VERSION 5.8 ;
BUSBITCHARS "[]" ;
DIVIDERCHAR "/" ;
UNITS
    DATABASE MICRONS 1000 ;
END UNITS

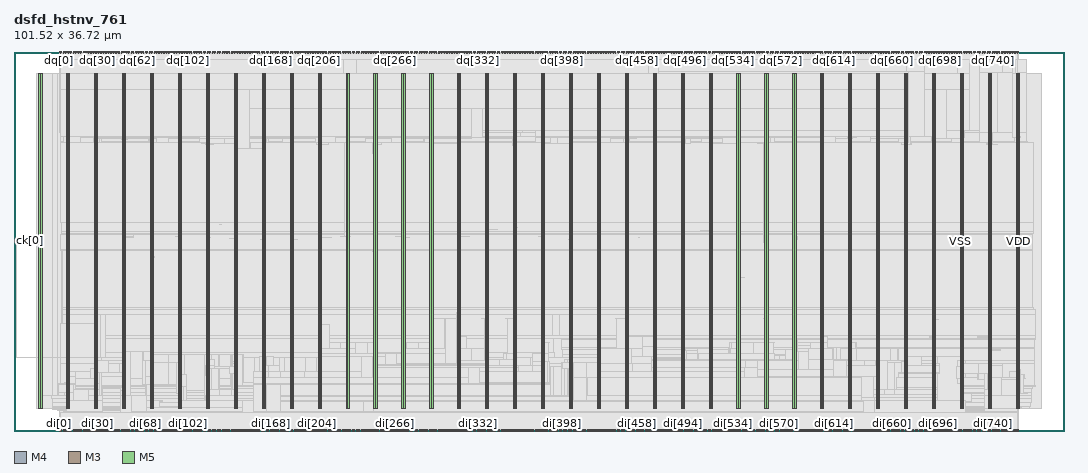
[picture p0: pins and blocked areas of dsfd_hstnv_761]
MACRO dsfd_hstnv_761
  FOREIGN dsfd_hstnv_761 0 0 ;
  CLASS BLOCK ;
  SIZE 101.52 BY 36.72 ;
  PIN ck[0]
    DIRECTION INPUT ;
    USE SIGNAL ;
    PORT
      LAYER M4 ;
        RECT  0 18.384 0.192 18.408 ;
    END
    PORT
      LAYER M4 ;
        RECT  0.156 18.384 0.275 18.408 ;
    END
  END ck[0]
  PIN di[0]
    DIRECTION INPUT ;
    USE SIGNAL ;
    PORT
      LAYER M3 ;
        RECT  4.356 0 4.374 0.144 ;
    END
  END di[0]
  PIN di[100]
    DIRECTION INPUT ;
    USE SIGNAL ;
    PORT
      LAYER M3 ;
        RECT  16.56 0 16.578 0.144 ;
    END
  END di[100]
  PIN di[101]
    DIRECTION INPUT ;
    USE SIGNAL ;
    PORT
      LAYER M5 ;
        RECT  16.704 0 16.728 0.192 ;
    END
  END di[101]
  PIN di[102]
    DIRECTION INPUT ;
    USE SIGNAL ;
    PORT
      LAYER M3 ;
        RECT  16.812 0 16.83 0.144 ;
    END
  END di[102]
  PIN di[103]
    DIRECTION INPUT ;
    USE SIGNAL ;
    PORT
      LAYER M5 ;
        RECT  16.944 0 16.968 0.192 ;
    END
  END di[103]
  PIN di[104]
    DIRECTION INPUT ;
    USE SIGNAL ;
    PORT
      LAYER M3 ;
        RECT  17.064 0 17.082 0.144 ;
    END
  END di[104]
  PIN di[105]
    DIRECTION INPUT ;
    USE SIGNAL ;
    PORT
      LAYER M5 ;
        RECT  17.184 0 17.208 0.192 ;
    END
  END di[105]
  PIN di[106]
    DIRECTION INPUT ;
    USE SIGNAL ;
    PORT
      LAYER M3 ;
        RECT  17.316 0 17.334 0.144 ;
    END
  END di[106]
  PIN di[107]
    DIRECTION INPUT ;
    USE SIGNAL ;
    PORT
      LAYER M5 ;
        RECT  17.424 0 17.448 0.192 ;
    END
  END di[107]
  PIN di[108]
    DIRECTION INPUT ;
    USE SIGNAL ;
    PORT
      LAYER M3 ;
        RECT  17.568 0 17.586 0.144 ;
    END
  END di[108]
  PIN di[109]
    DIRECTION INPUT ;
    USE SIGNAL ;
    PORT
      LAYER M5 ;
        RECT  17.664 0 17.688 0.192 ;
    END
  END di[109]
  PIN di[10]
    DIRECTION INPUT ;
    USE SIGNAL ;
    PORT
      LAYER M3 ;
        RECT  5.58 0 5.598 0.144 ;
    END
  END di[10]
  PIN di[110]
    DIRECTION INPUT ;
    USE SIGNAL ;
    PORT
      LAYER M3 ;
        RECT  17.784 0 17.802 0.144 ;
    END
  END di[110]
  PIN di[111]
    DIRECTION INPUT ;
    USE SIGNAL ;
    PORT
      LAYER M5 ;
        RECT  17.904 0 17.928 0.192 ;
    END
  END di[111]
  PIN di[112]
    DIRECTION INPUT ;
    USE SIGNAL ;
    PORT
      LAYER M3 ;
        RECT  18.036 0 18.054 0.144 ;
    END
  END di[112]
  PIN di[113]
    DIRECTION INPUT ;
    USE SIGNAL ;
    PORT
      LAYER M5 ;
        RECT  18.144 0 18.168 0.192 ;
    END
  END di[113]
  PIN di[114]
    DIRECTION INPUT ;
    USE SIGNAL ;
    PORT
      LAYER M3 ;
        RECT  18.288 0 18.306 0.144 ;
    END
  END di[114]
  PIN di[115]
    DIRECTION INPUT ;
    USE SIGNAL ;
    PORT
      LAYER M5 ;
        RECT  18.384 0 18.408 0.192 ;
    END
  END di[115]
  PIN di[116]
    DIRECTION INPUT ;
    USE SIGNAL ;
    PORT
      LAYER M3 ;
        RECT  18.54 0 18.558 0.144 ;
    END
  END di[116]
  PIN di[117]
    DIRECTION INPUT ;
    USE SIGNAL ;
    PORT
      LAYER M5 ;
        RECT  18.672 0 18.696 0.192 ;
    END
  END di[117]
  PIN di[118]
    DIRECTION INPUT ;
    USE SIGNAL ;
    PORT
      LAYER M3 ;
        RECT  18.756 0 18.774 0.144 ;
    END
  END di[118]
  PIN di[119]
    DIRECTION INPUT ;
    USE SIGNAL ;
    PORT
      LAYER M5 ;
        RECT  18.912 0 18.936 0.192 ;
    END
  END di[119]
  PIN di[11]
    DIRECTION INPUT ;
    USE SIGNAL ;
    PORT
      LAYER M5 ;
        RECT  5.712 0 5.736 0.192 ;
    END
  END di[11]
  PIN di[120]
    DIRECTION INPUT ;
    USE SIGNAL ;
    PORT
      LAYER M3 ;
        RECT  19.008 0 19.026 0.144 ;
    END
  END di[120]
  PIN di[121]
    DIRECTION INPUT ;
    USE SIGNAL ;
    PORT
      LAYER M5 ;
        RECT  19.152 0 19.176 0.192 ;
    END
  END di[121]
  PIN di[122]
    DIRECTION INPUT ;
    USE SIGNAL ;
    PORT
      LAYER M3 ;
        RECT  19.26 0 19.278 0.144 ;
    END
  END di[122]
  PIN di[123]
    DIRECTION INPUT ;
    USE SIGNAL ;
    PORT
      LAYER M5 ;
        RECT  19.392 0 19.416 0.192 ;
    END
  END di[123]
  PIN di[124]
    DIRECTION INPUT ;
    USE SIGNAL ;
    PORT
      LAYER M3 ;
        RECT  19.512 0 19.53 0.144 ;
    END
  END di[124]
  PIN di[125]
    DIRECTION INPUT ;
    USE SIGNAL ;
    PORT
      LAYER M5 ;
        RECT  19.632 0 19.656 0.192 ;
    END
  END di[125]
  PIN di[126]
    DIRECTION INPUT ;
    USE SIGNAL ;
    PORT
      LAYER M3 ;
        RECT  19.764 0 19.782 0.144 ;
    END
  END di[126]
  PIN di[127]
    DIRECTION INPUT ;
    USE SIGNAL ;
    PORT
      LAYER M5 ;
        RECT  19.872 0 19.896 0.192 ;
    END
  END di[127]
  PIN di[128]
    DIRECTION INPUT ;
    USE SIGNAL ;
    PORT
      LAYER M3 ;
        RECT  19.98 0 19.998 0.144 ;
    END
  END di[128]
  PIN di[129]
    DIRECTION INPUT ;
    USE SIGNAL ;
    PORT
      LAYER M5 ;
        RECT  20.112 0 20.136 0.192 ;
    END
  END di[129]
  PIN di[12]
    DIRECTION INPUT ;
    USE SIGNAL ;
    PORT
      LAYER M3 ;
        RECT  5.832 0 5.85 0.144 ;
    END
  END di[12]
  PIN di[130]
    DIRECTION INPUT ;
    USE SIGNAL ;
    PORT
      LAYER M3 ;
        RECT  20.232 0 20.25 0.144 ;
    END
  END di[130]
  PIN di[131]
    DIRECTION INPUT ;
    USE SIGNAL ;
    PORT
      LAYER M5 ;
        RECT  20.352 0 20.376 0.192 ;
    END
  END di[131]
  PIN di[132]
    DIRECTION INPUT ;
    USE SIGNAL ;
    PORT
      LAYER M3 ;
        RECT  20.484 0 20.502 0.144 ;
    END
  END di[132]
  PIN di[133]
    DIRECTION INPUT ;
    USE SIGNAL ;
    PORT
      LAYER M5 ;
        RECT  20.592 0 20.616 0.192 ;
    END
  END di[133]
  PIN di[134]
    DIRECTION INPUT ;
    USE SIGNAL ;
    PORT
      LAYER M3 ;
        RECT  20.736 0 20.754 0.144 ;
    END
  END di[134]
  PIN di[135]
    DIRECTION INPUT ;
    USE SIGNAL ;
    PORT
      LAYER M5 ;
        RECT  20.832 0 20.856 0.192 ;
    END
  END di[135]
  PIN di[136]
    DIRECTION INPUT ;
    USE SIGNAL ;
    PORT
      LAYER M3 ;
        RECT  20.988 0 21.006 0.144 ;
    END
  END di[136]
  PIN di[137]
    DIRECTION INPUT ;
    USE SIGNAL ;
    PORT
      LAYER M5 ;
        RECT  21.072 0 21.096 0.192 ;
    END
  END di[137]
  PIN di[138]
    DIRECTION INPUT ;
    USE SIGNAL ;
    PORT
      LAYER M3 ;
        RECT  21.204 0 21.222 0.144 ;
    END
  END di[138]
  PIN di[139]
    DIRECTION INPUT ;
    USE SIGNAL ;
    PORT
      LAYER M5 ;
        RECT  21.312 0 21.336 0.192 ;
    END
  END di[139]
  PIN di[13]
    DIRECTION INPUT ;
    USE SIGNAL ;
    PORT
      LAYER M5 ;
        RECT  5.952 0 5.976 0.192 ;
    END
  END di[13]
  PIN di[140]
    DIRECTION INPUT ;
    USE SIGNAL ;
    PORT
      LAYER M3 ;
        RECT  21.456 0 21.474 0.144 ;
    END
  END di[140]
  PIN di[141]
    DIRECTION INPUT ;
    USE SIGNAL ;
    PORT
      LAYER M5 ;
        RECT  21.6 0 21.624 0.192 ;
    END
  END di[141]
  PIN di[142]
    DIRECTION INPUT ;
    USE SIGNAL ;
    PORT
      LAYER M3 ;
        RECT  21.708 0 21.726 0.144 ;
    END
  END di[142]
  PIN di[143]
    DIRECTION INPUT ;
    USE SIGNAL ;
    PORT
      LAYER M5 ;
        RECT  21.84 0 21.864 0.192 ;
    END
  END di[143]
  PIN di[144]
    DIRECTION INPUT ;
    USE SIGNAL ;
    PORT
      LAYER M3 ;
        RECT  21.96 0 21.978 0.144 ;
    END
  END di[144]
  PIN di[145]
    DIRECTION INPUT ;
    USE SIGNAL ;
    PORT
      LAYER M5 ;
        RECT  22.08 0 22.104 0.192 ;
    END
  END di[145]
  PIN di[146]
    DIRECTION INPUT ;
    USE SIGNAL ;
    PORT
      LAYER M3 ;
        RECT  22.176 0 22.194 0.144 ;
    END
  END di[146]
  PIN di[147]
    DIRECTION INPUT ;
    USE SIGNAL ;
    PORT
      LAYER M5 ;
        RECT  22.32 0 22.344 0.192 ;
    END
  END di[147]
  PIN di[148]
    DIRECTION INPUT ;
    USE SIGNAL ;
    PORT
      LAYER M3 ;
        RECT  22.428 0 22.446 0.144 ;
    END
  END di[148]
  PIN di[149]
    DIRECTION INPUT ;
    USE SIGNAL ;
    PORT
      LAYER M5 ;
        RECT  22.56 0 22.584 0.192 ;
    END
  END di[149]
  PIN di[14]
    DIRECTION INPUT ;
    USE SIGNAL ;
    PORT
      LAYER M3 ;
        RECT  6.084 0 6.102 0.144 ;
    END
  END di[14]
  PIN di[150]
    DIRECTION INPUT ;
    USE SIGNAL ;
    PORT
      LAYER M3 ;
        RECT  22.68 0 22.698 0.144 ;
    END
  END di[150]
  PIN di[151]
    DIRECTION INPUT ;
    USE SIGNAL ;
    PORT
      LAYER M5 ;
        RECT  22.8 0 22.824 0.192 ;
    END
  END di[151]
  PIN di[152]
    DIRECTION INPUT ;
    USE SIGNAL ;
    PORT
      LAYER M3 ;
        RECT  22.932 0 22.95 0.144 ;
    END
  END di[152]
  PIN di[153]
    DIRECTION INPUT ;
    USE SIGNAL ;
    PORT
      LAYER M5 ;
        RECT  23.04 0 23.064 0.192 ;
    END
  END di[153]
  PIN di[154]
    DIRECTION INPUT ;
    USE SIGNAL ;
    PORT
      LAYER M3 ;
        RECT  23.184 0 23.202 0.144 ;
    END
  END di[154]
  PIN di[155]
    DIRECTION INPUT ;
    USE SIGNAL ;
    PORT
      LAYER M5 ;
        RECT  23.28 0 23.304 0.192 ;
    END
  END di[155]
  PIN di[156]
    DIRECTION INPUT ;
    USE SIGNAL ;
    PORT
      LAYER M3 ;
        RECT  23.4 0 23.418 0.144 ;
    END
  END di[156]
  PIN di[157]
    DIRECTION INPUT ;
    USE SIGNAL ;
    PORT
      LAYER M5 ;
        RECT  23.52 0 23.544 0.192 ;
    END
  END di[157]
  PIN di[158]
    DIRECTION INPUT ;
    USE SIGNAL ;
    PORT
      LAYER M3 ;
        RECT  23.652 0 23.67 0.144 ;
    END
  END di[158]
  PIN di[159]
    DIRECTION INPUT ;
    USE SIGNAL ;
    PORT
      LAYER M5 ;
        RECT  23.76 0 23.784 0.192 ;
    END
  END di[159]
  PIN di[15]
    DIRECTION INPUT ;
    USE SIGNAL ;
    PORT
      LAYER M5 ;
        RECT  6.192 0 6.216 0.192 ;
    END
  END di[15]
  PIN di[160]
    DIRECTION INPUT ;
    USE SIGNAL ;
    PORT
      LAYER M3 ;
        RECT  23.904 0 23.922 0.144 ;
    END
  END di[160]
  PIN di[161]
    DIRECTION INPUT ;
    USE SIGNAL ;
    PORT
      LAYER M5 ;
        RECT  24 0 24.024 0.192 ;
    END
  END di[161]
  PIN di[162]
    DIRECTION INPUT ;
    USE SIGNAL ;
    PORT
      LAYER M3 ;
        RECT  24.156 0 24.174 0.144 ;
    END
  END di[162]
  PIN di[163]
    DIRECTION INPUT ;
    USE SIGNAL ;
    PORT
      LAYER M5 ;
        RECT  24.24 0 24.264 0.192 ;
    END
  END di[163]
  PIN di[164]
    DIRECTION INPUT ;
    USE SIGNAL ;
    PORT
      LAYER M3 ;
        RECT  24.372 0 24.39 0.144 ;
    END
  END di[164]
  PIN di[165]
    DIRECTION INPUT ;
    USE SIGNAL ;
    PORT
      LAYER M5 ;
        RECT  24.528 0 24.552 0.192 ;
    END
  END di[165]
  PIN di[166]
    DIRECTION INPUT ;
    USE SIGNAL ;
    PORT
      LAYER M3 ;
        RECT  24.624 0 24.642 0.144 ;
    END
  END di[166]
  PIN di[167]
    DIRECTION INPUT ;
    USE SIGNAL ;
    PORT
      LAYER M5 ;
        RECT  24.768 0 24.792 0.192 ;
    END
  END di[167]
  PIN di[168]
    DIRECTION INPUT ;
    USE SIGNAL ;
    PORT
      LAYER M3 ;
        RECT  24.876 0 24.894 0.144 ;
    END
  END di[168]
  PIN di[169]
    DIRECTION INPUT ;
    USE SIGNAL ;
    PORT
      LAYER M5 ;
        RECT  25.008 0 25.032 0.192 ;
    END
  END di[169]
  PIN di[16]
    DIRECTION INPUT ;
    USE SIGNAL ;
    PORT
      LAYER M3 ;
        RECT  6.336 0 6.354 0.144 ;
    END
  END di[16]
  PIN di[170]
    DIRECTION INPUT ;
    USE SIGNAL ;
    PORT
      LAYER M3 ;
        RECT  25.128 0 25.146 0.144 ;
    END
  END di[170]
  PIN di[171]
    DIRECTION INPUT ;
    USE SIGNAL ;
    PORT
      LAYER M5 ;
        RECT  25.248 0 25.272 0.192 ;
    END
  END di[171]
  PIN di[172]
    DIRECTION INPUT ;
    USE SIGNAL ;
    PORT
      LAYER M3 ;
        RECT  25.38 0 25.398 0.144 ;
    END
  END di[172]
  PIN di[173]
    DIRECTION INPUT ;
    USE SIGNAL ;
    PORT
      LAYER M5 ;
        RECT  25.488 0 25.512 0.192 ;
    END
  END di[173]
  PIN di[174]
    DIRECTION INPUT ;
    USE SIGNAL ;
    PORT
      LAYER M3 ;
        RECT  25.596 0 25.614 0.144 ;
    END
  END di[174]
  PIN di[175]
    DIRECTION INPUT ;
    USE SIGNAL ;
    PORT
      LAYER M5 ;
        RECT  25.728 0 25.752 0.192 ;
    END
  END di[175]
  PIN di[176]
    DIRECTION INPUT ;
    USE SIGNAL ;
    PORT
      LAYER M3 ;
        RECT  25.848 0 25.866 0.144 ;
    END
  END di[176]
  PIN di[177]
    DIRECTION INPUT ;
    USE SIGNAL ;
    PORT
      LAYER M5 ;
        RECT  25.968 0 25.992 0.192 ;
    END
  END di[177]
  PIN di[178]
    DIRECTION INPUT ;
    USE SIGNAL ;
    PORT
      LAYER M3 ;
        RECT  26.1 0 26.118 0.144 ;
    END
  END di[178]
  PIN di[179]
    DIRECTION INPUT ;
    USE SIGNAL ;
    PORT
      LAYER M5 ;
        RECT  26.208 0 26.232 0.192 ;
    END
  END di[179]
  PIN di[17]
    DIRECTION INPUT ;
    USE SIGNAL ;
    PORT
      LAYER M5 ;
        RECT  6.432 0 6.456 0.192 ;
    END
  END di[17]
  PIN di[180]
    DIRECTION INPUT ;
    USE SIGNAL ;
    PORT
      LAYER M3 ;
        RECT  26.352 0 26.37 0.144 ;
    END
  END di[180]
  PIN di[181]
    DIRECTION INPUT ;
    USE SIGNAL ;
    PORT
      LAYER M5 ;
        RECT  26.448 0 26.472 0.192 ;
    END
  END di[181]
  PIN di[182]
    DIRECTION INPUT ;
    USE SIGNAL ;
    PORT
      LAYER M3 ;
        RECT  26.568 0 26.586 0.144 ;
    END
  END di[182]
  PIN di[183]
    DIRECTION INPUT ;
    USE SIGNAL ;
    PORT
      LAYER M5 ;
        RECT  26.688 0 26.712 0.192 ;
    END
  END di[183]
  PIN di[184]
    DIRECTION INPUT ;
    USE SIGNAL ;
    PORT
      LAYER M3 ;
        RECT  26.82 0 26.838 0.144 ;
    END
  END di[184]
  PIN di[185]
    DIRECTION INPUT ;
    USE SIGNAL ;
    PORT
      LAYER M5 ;
        RECT  26.928 0 26.952 0.192 ;
    END
  END di[185]
  PIN di[186]
    DIRECTION INPUT ;
    USE SIGNAL ;
    PORT
      LAYER M3 ;
        RECT  27.072 0 27.09 0.144 ;
    END
  END di[186]
  PIN di[187]
    DIRECTION INPUT ;
    USE SIGNAL ;
    PORT
      LAYER M5 ;
        RECT  27.216 0 27.24 0.192 ;
    END
  END di[187]
  PIN di[188]
    DIRECTION INPUT ;
    USE SIGNAL ;
    PORT
      LAYER M3 ;
        RECT  27.324 0 27.342 0.144 ;
    END
  END di[188]
  PIN di[189]
    DIRECTION INPUT ;
    USE SIGNAL ;
    PORT
      LAYER M5 ;
        RECT  27.456 0 27.48 0.192 ;
    END
  END di[189]
  PIN di[18]
    DIRECTION INPUT ;
    USE SIGNAL ;
    PORT
      LAYER M3 ;
        RECT  6.552 0 6.57 0.144 ;
    END
  END di[18]
  PIN di[190]
    DIRECTION INPUT ;
    USE SIGNAL ;
    PORT
      LAYER M3 ;
        RECT  27.576 0 27.594 0.144 ;
    END
  END di[190]
  PIN di[191]
    DIRECTION INPUT ;
    USE SIGNAL ;
    PORT
      LAYER M5 ;
        RECT  27.696 0 27.72 0.192 ;
    END
  END di[191]
  PIN di[192]
    DIRECTION INPUT ;
    USE SIGNAL ;
    PORT
      LAYER M3 ;
        RECT  27.792 0 27.81 0.144 ;
    END
  END di[192]
  PIN di[193]
    DIRECTION INPUT ;
    USE SIGNAL ;
    PORT
      LAYER M5 ;
        RECT  27.936 0 27.96 0.192 ;
    END
  END di[193]
  PIN di[194]
    DIRECTION INPUT ;
    USE SIGNAL ;
    PORT
      LAYER M3 ;
        RECT  28.044 0 28.062 0.144 ;
    END
  END di[194]
  PIN di[195]
    DIRECTION INPUT ;
    USE SIGNAL ;
    PORT
      LAYER M5 ;
        RECT  28.176 0 28.2 0.192 ;
    END
  END di[195]
  PIN di[196]
    DIRECTION INPUT ;
    USE SIGNAL ;
    PORT
      LAYER M3 ;
        RECT  28.296 0 28.314 0.144 ;
    END
  END di[196]
  PIN di[197]
    DIRECTION INPUT ;
    USE SIGNAL ;
    PORT
      LAYER M5 ;
        RECT  28.416 0 28.44 0.192 ;
    END
  END di[197]
  PIN di[198]
    DIRECTION INPUT ;
    USE SIGNAL ;
    PORT
      LAYER M3 ;
        RECT  28.548 0 28.566 0.144 ;
    END
  END di[198]
  PIN di[199]
    DIRECTION INPUT ;
    USE SIGNAL ;
    PORT
      LAYER M5 ;
        RECT  28.656 0 28.68 0.192 ;
    END
  END di[199]
  PIN di[19]
    DIRECTION INPUT ;
    USE SIGNAL ;
    PORT
      LAYER M5 ;
        RECT  6.672 0 6.696 0.192 ;
    END
  END di[19]
  PIN di[1]
    DIRECTION INPUT ;
    USE SIGNAL ;
    PORT
      LAYER M5 ;
        RECT  4.512 0 4.536 0.192 ;
    END
  END di[1]
  PIN di[200]
    DIRECTION INPUT ;
    USE SIGNAL ;
    PORT
      LAYER M3 ;
        RECT  28.8 0 28.818 0.144 ;
    END
  END di[200]
  PIN di[201]
    DIRECTION INPUT ;
    USE SIGNAL ;
    PORT
      LAYER M5 ;
        RECT  28.896 0 28.92 0.192 ;
    END
  END di[201]
  PIN di[202]
    DIRECTION INPUT ;
    USE SIGNAL ;
    PORT
      LAYER M3 ;
        RECT  29.016 0 29.034 0.144 ;
    END
  END di[202]
  PIN di[203]
    DIRECTION INPUT ;
    USE SIGNAL ;
    PORT
      LAYER M5 ;
        RECT  29.136 0 29.16 0.192 ;
    END
  END di[203]
  PIN di[204]
    DIRECTION INPUT ;
    USE SIGNAL ;
    PORT
      LAYER M3 ;
        RECT  29.268 0 29.286 0.144 ;
    END
  END di[204]
  PIN di[205]
    DIRECTION INPUT ;
    USE SIGNAL ;
    PORT
      LAYER M5 ;
        RECT  29.376 0 29.4 0.192 ;
    END
  END di[205]
  PIN di[206]
    DIRECTION INPUT ;
    USE SIGNAL ;
    PORT
      LAYER M3 ;
        RECT  29.52 0 29.538 0.144 ;
    END
  END di[206]
  PIN di[207]
    DIRECTION INPUT ;
    USE SIGNAL ;
    PORT
      LAYER M5 ;
        RECT  29.616 0 29.64 0.192 ;
    END
  END di[207]
  PIN di[208]
    DIRECTION INPUT ;
    USE SIGNAL ;
    PORT
      LAYER M3 ;
        RECT  29.772 0 29.79 0.144 ;
    END
  END di[208]
  PIN di[209]
    DIRECTION INPUT ;
    USE SIGNAL ;
    PORT
      LAYER M5 ;
        RECT  29.856 0 29.88 0.192 ;
    END
  END di[209]
  PIN di[20]
    DIRECTION INPUT ;
    USE SIGNAL ;
    PORT
      LAYER M3 ;
        RECT  6.804 0 6.822 0.144 ;
    END
  END di[20]
  PIN di[210]
    DIRECTION INPUT ;
    USE SIGNAL ;
    PORT
      LAYER M3 ;
        RECT  29.988 0 30.006 0.144 ;
    END
  END di[210]
  PIN di[211]
    DIRECTION INPUT ;
    USE SIGNAL ;
    PORT
      LAYER M5 ;
        RECT  30.144 0 30.168 0.192 ;
    END
  END di[211]
  PIN di[212]
    DIRECTION INPUT ;
    USE SIGNAL ;
    PORT
      LAYER M3 ;
        RECT  30.24 0 30.258 0.144 ;
    END
  END di[212]
  PIN di[213]
    DIRECTION INPUT ;
    USE SIGNAL ;
    PORT
      LAYER M5 ;
        RECT  30.384 0 30.408 0.192 ;
    END
  END di[213]
  PIN di[214]
    DIRECTION INPUT ;
    USE SIGNAL ;
    PORT
      LAYER M3 ;
        RECT  30.492 0 30.51 0.144 ;
    END
  END di[214]
  PIN di[215]
    DIRECTION INPUT ;
    USE SIGNAL ;
    PORT
      LAYER M5 ;
        RECT  30.624 0 30.648 0.192 ;
    END
  END di[215]
  PIN di[216]
    DIRECTION INPUT ;
    USE SIGNAL ;
    PORT
      LAYER M3 ;
        RECT  30.744 0 30.762 0.144 ;
    END
  END di[216]
  PIN di[217]
    DIRECTION INPUT ;
    USE SIGNAL ;
    PORT
      LAYER M5 ;
        RECT  30.864 0 30.888 0.192 ;
    END
  END di[217]
  PIN di[218]
    DIRECTION INPUT ;
    USE SIGNAL ;
    PORT
      LAYER M3 ;
        RECT  30.996 0 31.014 0.144 ;
    END
  END di[218]
  PIN di[219]
    DIRECTION INPUT ;
    USE SIGNAL ;
    PORT
      LAYER M5 ;
        RECT  31.104 0 31.128 0.192 ;
    END
  END di[219]
  PIN di[21]
    DIRECTION INPUT ;
    USE SIGNAL ;
    PORT
      LAYER M5 ;
        RECT  6.912 0 6.936 0.192 ;
    END
  END di[21]
  PIN di[220]
    DIRECTION INPUT ;
    USE SIGNAL ;
    PORT
      LAYER M3 ;
        RECT  31.212 0 31.23 0.144 ;
    END
  END di[220]
  PIN di[221]
    DIRECTION INPUT ;
    USE SIGNAL ;
    PORT
      LAYER M5 ;
        RECT  31.344 0 31.368 0.192 ;
    END
  END di[221]
  PIN di[222]
    DIRECTION INPUT ;
    USE SIGNAL ;
    PORT
      LAYER M3 ;
        RECT  31.464 0 31.482 0.144 ;
    END
  END di[222]
  PIN di[223]
    DIRECTION INPUT ;
    USE SIGNAL ;
    PORT
      LAYER M5 ;
        RECT  31.584 0 31.608 0.192 ;
    END
  END di[223]
  PIN di[224]
    DIRECTION INPUT ;
    USE SIGNAL ;
    PORT
      LAYER M3 ;
        RECT  31.716 0 31.734 0.144 ;
    END
  END di[224]
  PIN di[225]
    DIRECTION INPUT ;
    USE SIGNAL ;
    PORT
      LAYER M5 ;
        RECT  31.824 0 31.848 0.192 ;
    END
  END di[225]
  PIN di[226]
    DIRECTION INPUT ;
    USE SIGNAL ;
    PORT
      LAYER M3 ;
        RECT  31.968 0 31.986 0.144 ;
    END
  END di[226]
  PIN di[227]
    DIRECTION INPUT ;
    USE SIGNAL ;
    PORT
      LAYER M5 ;
        RECT  32.064 0 32.088 0.192 ;
    END
  END di[227]
  PIN di[228]
    DIRECTION INPUT ;
    USE SIGNAL ;
    PORT
      LAYER M3 ;
        RECT  32.184 0 32.202 0.144 ;
    END
  END di[228]
  PIN di[229]
    DIRECTION INPUT ;
    USE SIGNAL ;
    PORT
      LAYER M5 ;
        RECT  32.304 0 32.328 0.192 ;
    END
  END di[229]
  PIN di[22]
    DIRECTION INPUT ;
    USE SIGNAL ;
    PORT
      LAYER M3 ;
        RECT  7.056 0 7.074 0.144 ;
    END
  END di[22]
  PIN di[230]
    DIRECTION INPUT ;
    USE SIGNAL ;
    PORT
      LAYER M3 ;
        RECT  32.436 0 32.454 0.144 ;
    END
  END di[230]
  PIN di[231]
    DIRECTION INPUT ;
    USE SIGNAL ;
    PORT
      LAYER M5 ;
        RECT  32.544 0 32.568 0.192 ;
    END
  END di[231]
  PIN di[232]
    DIRECTION INPUT ;
    USE SIGNAL ;
    PORT
      LAYER M3 ;
        RECT  32.688 0 32.706 0.144 ;
    END
  END di[232]
  PIN di[233]
    DIRECTION INPUT ;
    USE SIGNAL ;
    PORT
      LAYER M5 ;
        RECT  32.784 0 32.808 0.192 ;
    END
  END di[233]
  PIN di[234]
    DIRECTION INPUT ;
    USE SIGNAL ;
    PORT
      LAYER M3 ;
        RECT  32.94 0 32.958 0.144 ;
    END
  END di[234]
  PIN di[235]
    DIRECTION INPUT ;
    USE SIGNAL ;
    PORT
      LAYER M5 ;
        RECT  33.072 0 33.096 0.192 ;
    END
  END di[235]
  PIN di[236]
    DIRECTION INPUT ;
    USE SIGNAL ;
    PORT
      LAYER M3 ;
        RECT  33.192 0 33.21 0.144 ;
    END
  END di[236]
  PIN di[237]
    DIRECTION INPUT ;
    USE SIGNAL ;
    PORT
      LAYER M5 ;
        RECT  33.312 0 33.336 0.192 ;
    END
  END di[237]
  PIN di[238]
    DIRECTION INPUT ;
    USE SIGNAL ;
    PORT
      LAYER M3 ;
        RECT  33.408 0 33.426 0.144 ;
    END
  END di[238]
  PIN di[239]
    DIRECTION INPUT ;
    USE SIGNAL ;
    PORT
      LAYER M5 ;
        RECT  33.552 0 33.576 0.192 ;
    END
  END di[239]
  PIN di[23]
    DIRECTION INPUT ;
    USE SIGNAL ;
    PORT
      LAYER M5 ;
        RECT  7.2 0 7.224 0.192 ;
    END
  END di[23]
  PIN di[240]
    DIRECTION INPUT ;
    USE SIGNAL ;
    PORT
      LAYER M3 ;
        RECT  33.66 0 33.678 0.144 ;
    END
  END di[240]
  PIN di[241]
    DIRECTION INPUT ;
    USE SIGNAL ;
    PORT
      LAYER M5 ;
        RECT  33.792 0 33.816 0.192 ;
    END
  END di[241]
  PIN di[242]
    DIRECTION INPUT ;
    USE SIGNAL ;
    PORT
      LAYER M3 ;
        RECT  33.912 0 33.93 0.144 ;
    END
  END di[242]
  PIN di[243]
    DIRECTION INPUT ;
    USE SIGNAL ;
    PORT
      LAYER M5 ;
        RECT  34.032 0 34.056 0.192 ;
    END
  END di[243]
  PIN di[244]
    DIRECTION INPUT ;
    USE SIGNAL ;
    PORT
      LAYER M3 ;
        RECT  34.164 0 34.182 0.144 ;
    END
  END di[244]
  PIN di[245]
    DIRECTION INPUT ;
    USE SIGNAL ;
    PORT
      LAYER M5 ;
        RECT  34.272 0 34.296 0.192 ;
    END
  END di[245]
  PIN di[246]
    DIRECTION INPUT ;
    USE SIGNAL ;
    PORT
      LAYER M3 ;
        RECT  34.38 0 34.398 0.144 ;
    END
  END di[246]
  PIN di[247]
    DIRECTION INPUT ;
    USE SIGNAL ;
    PORT
      LAYER M5 ;
        RECT  34.512 0 34.536 0.192 ;
    END
  END di[247]
  PIN di[248]
    DIRECTION INPUT ;
    USE SIGNAL ;
    PORT
      LAYER M3 ;
        RECT  34.632 0 34.65 0.144 ;
    END
  END di[248]
  PIN di[249]
    DIRECTION INPUT ;
    USE SIGNAL ;
    PORT
      LAYER M5 ;
        RECT  34.752 0 34.776 0.192 ;
    END
  END di[249]
  PIN di[24]
    DIRECTION INPUT ;
    USE SIGNAL ;
    PORT
      LAYER M3 ;
        RECT  7.308 0 7.326 0.144 ;
    END
  END di[24]
  PIN di[250]
    DIRECTION INPUT ;
    USE SIGNAL ;
    PORT
      LAYER M3 ;
        RECT  34.884 0 34.902 0.144 ;
    END
  END di[250]
  PIN di[251]
    DIRECTION INPUT ;
    USE SIGNAL ;
    PORT
      LAYER M5 ;
        RECT  34.992 0 35.016 0.192 ;
    END
  END di[251]
  PIN di[252]
    DIRECTION INPUT ;
    USE SIGNAL ;
    PORT
      LAYER M3 ;
        RECT  35.136 0 35.154 0.144 ;
    END
  END di[252]
  PIN di[253]
    DIRECTION INPUT ;
    USE SIGNAL ;
    PORT
      LAYER M5 ;
        RECT  35.232 0 35.256 0.192 ;
    END
  END di[253]
  PIN di[254]
    DIRECTION INPUT ;
    USE SIGNAL ;
    PORT
      LAYER M3 ;
        RECT  35.388 0 35.406 0.144 ;
    END
  END di[254]
  PIN di[255]
    DIRECTION INPUT ;
    USE SIGNAL ;
    PORT
      LAYER M5 ;
        RECT  35.472 0 35.496 0.192 ;
    END
  END di[255]
  PIN di[256]
    DIRECTION INPUT ;
    USE SIGNAL ;
    PORT
      LAYER M3 ;
        RECT  35.604 0 35.622 0.144 ;
    END
  END di[256]
  PIN di[257]
    DIRECTION INPUT ;
    USE SIGNAL ;
    PORT
      LAYER M5 ;
        RECT  35.712 0 35.736 0.192 ;
    END
  END di[257]
  PIN di[258]
    DIRECTION INPUT ;
    USE SIGNAL ;
    PORT
      LAYER M3 ;
        RECT  35.856 0 35.874 0.144 ;
    END
  END di[258]
  PIN di[259]
    DIRECTION INPUT ;
    USE SIGNAL ;
    PORT
      LAYER M5 ;
        RECT  36 0 36.024 0.192 ;
    END
  END di[259]
  PIN di[25]
    DIRECTION INPUT ;
    USE SIGNAL ;
    PORT
      LAYER M5 ;
        RECT  7.44 0 7.464 0.192 ;
    END
  END di[25]
  PIN di[260]
    DIRECTION INPUT ;
    USE SIGNAL ;
    PORT
      LAYER M3 ;
        RECT  36.108 0 36.126 0.144 ;
    END
  END di[260]
  PIN di[261]
    DIRECTION INPUT ;
    USE SIGNAL ;
    PORT
      LAYER M5 ;
        RECT  36.24 0 36.264 0.192 ;
    END
  END di[261]
  PIN di[262]
    DIRECTION INPUT ;
    USE SIGNAL ;
    PORT
      LAYER M3 ;
        RECT  36.36 0 36.378 0.144 ;
    END
  END di[262]
  PIN di[263]
    DIRECTION INPUT ;
    USE SIGNAL ;
    PORT
      LAYER M5 ;
        RECT  36.48 0 36.504 0.192 ;
    END
  END di[263]
  PIN di[264]
    DIRECTION INPUT ;
    USE SIGNAL ;
    PORT
      LAYER M3 ;
        RECT  36.576 0 36.594 0.144 ;
    END
  END di[264]
  PIN di[265]
    DIRECTION INPUT ;
    USE SIGNAL ;
    PORT
      LAYER M5 ;
        RECT  36.72 0 36.744 0.192 ;
    END
  END di[265]
  PIN di[266]
    DIRECTION INPUT ;
    USE SIGNAL ;
    PORT
      LAYER M3 ;
        RECT  36.828 0 36.846 0.144 ;
    END
  END di[266]
  PIN di[267]
    DIRECTION INPUT ;
    USE SIGNAL ;
    PORT
      LAYER M5 ;
        RECT  36.96 0 36.984 0.192 ;
    END
  END di[267]
  PIN di[268]
    DIRECTION INPUT ;
    USE SIGNAL ;
    PORT
      LAYER M3 ;
        RECT  37.08 0 37.098 0.144 ;
    END
  END di[268]
  PIN di[269]
    DIRECTION INPUT ;
    USE SIGNAL ;
    PORT
      LAYER M5 ;
        RECT  37.2 0 37.224 0.192 ;
    END
  END di[269]
  PIN di[26]
    DIRECTION INPUT ;
    USE SIGNAL ;
    PORT
      LAYER M3 ;
        RECT  7.56 0 7.578 0.144 ;
    END
  END di[26]
  PIN di[270]
    DIRECTION INPUT ;
    USE SIGNAL ;
    PORT
      LAYER M3 ;
        RECT  37.332 0 37.35 0.144 ;
    END
  END di[270]
  PIN di[271]
    DIRECTION INPUT ;
    USE SIGNAL ;
    PORT
      LAYER M5 ;
        RECT  37.44 0 37.464 0.192 ;
    END
  END di[271]
  PIN di[272]
    DIRECTION INPUT ;
    USE SIGNAL ;
    PORT
      LAYER M3 ;
        RECT  37.584 0 37.602 0.144 ;
    END
  END di[272]
  PIN di[273]
    DIRECTION INPUT ;
    USE SIGNAL ;
    PORT
      LAYER M5 ;
        RECT  37.68 0 37.704 0.192 ;
    END
  END di[273]
  PIN di[274]
    DIRECTION INPUT ;
    USE SIGNAL ;
    PORT
      LAYER M3 ;
        RECT  37.8 0 37.818 0.144 ;
    END
  END di[274]
  PIN di[275]
    DIRECTION INPUT ;
    USE SIGNAL ;
    PORT
      LAYER M5 ;
        RECT  37.92 0 37.944 0.192 ;
    END
  END di[275]
  PIN di[276]
    DIRECTION INPUT ;
    USE SIGNAL ;
    PORT
      LAYER M3 ;
        RECT  38.052 0 38.07 0.144 ;
    END
  END di[276]
  PIN di[277]
    DIRECTION INPUT ;
    USE SIGNAL ;
    PORT
      LAYER M5 ;
        RECT  38.16 0 38.184 0.192 ;
    END
  END di[277]
  PIN di[278]
    DIRECTION INPUT ;
    USE SIGNAL ;
    PORT
      LAYER M3 ;
        RECT  38.304 0 38.322 0.144 ;
    END
  END di[278]
  PIN di[279]
    DIRECTION INPUT ;
    USE SIGNAL ;
    PORT
      LAYER M5 ;
        RECT  38.4 0 38.424 0.192 ;
    END
  END di[279]
  PIN di[27]
    DIRECTION INPUT ;
    USE SIGNAL ;
    PORT
      LAYER M5 ;
        RECT  7.68 0 7.704 0.192 ;
    END
  END di[27]
  PIN di[280]
    DIRECTION INPUT ;
    USE SIGNAL ;
    PORT
      LAYER M3 ;
        RECT  38.556 0 38.574 0.144 ;
    END
  END di[280]
  PIN di[281]
    DIRECTION INPUT ;
    USE SIGNAL ;
    PORT
      LAYER M5 ;
        RECT  38.688 0 38.712 0.192 ;
    END
  END di[281]
  PIN di[282]
    DIRECTION INPUT ;
    USE SIGNAL ;
    PORT
      LAYER M3 ;
        RECT  38.808 0 38.826 0.144 ;
    END
  END di[282]
  PIN di[283]
    DIRECTION INPUT ;
    USE SIGNAL ;
    PORT
      LAYER M5 ;
        RECT  38.928 0 38.952 0.192 ;
    END
  END di[283]
  PIN di[284]
    DIRECTION INPUT ;
    USE SIGNAL ;
    PORT
      LAYER M3 ;
        RECT  39.024 0 39.042 0.144 ;
    END
  END di[284]
  PIN di[285]
    DIRECTION INPUT ;
    USE SIGNAL ;
    PORT
      LAYER M5 ;
        RECT  39.168 0 39.192 0.192 ;
    END
  END di[285]
  PIN di[286]
    DIRECTION INPUT ;
    USE SIGNAL ;
    PORT
      LAYER M3 ;
        RECT  39.276 0 39.294 0.144 ;
    END
  END di[286]
  PIN di[287]
    DIRECTION INPUT ;
    USE SIGNAL ;
    PORT
      LAYER M5 ;
        RECT  39.408 0 39.432 0.192 ;
    END
  END di[287]
  PIN di[288]
    DIRECTION INPUT ;
    USE SIGNAL ;
    PORT
      LAYER M3 ;
        RECT  39.528 0 39.546 0.144 ;
    END
  END di[288]
  PIN di[289]
    DIRECTION INPUT ;
    USE SIGNAL ;
    PORT
      LAYER M5 ;
        RECT  39.648 0 39.672 0.192 ;
    END
  END di[289]
  PIN di[28]
    DIRECTION INPUT ;
    USE SIGNAL ;
    PORT
      LAYER M3 ;
        RECT  7.776 0 7.794 0.144 ;
    END
  END di[28]
  PIN di[290]
    DIRECTION INPUT ;
    USE SIGNAL ;
    PORT
      LAYER M3 ;
        RECT  39.78 0 39.798 0.144 ;
    END
  END di[290]
  PIN di[291]
    DIRECTION INPUT ;
    USE SIGNAL ;
    PORT
      LAYER M5 ;
        RECT  39.888 0 39.912 0.192 ;
    END
  END di[291]
  PIN di[292]
    DIRECTION INPUT ;
    USE SIGNAL ;
    PORT
      LAYER M3 ;
        RECT  39.996 0 40.014 0.144 ;
    END
  END di[292]
  PIN di[293]
    DIRECTION INPUT ;
    USE SIGNAL ;
    PORT
      LAYER M5 ;
        RECT  40.128 0 40.152 0.192 ;
    END
  END di[293]
  PIN di[294]
    DIRECTION INPUT ;
    USE SIGNAL ;
    PORT
      LAYER M3 ;
        RECT  40.248 0 40.266 0.144 ;
    END
  END di[294]
  PIN di[295]
    DIRECTION INPUT ;
    USE SIGNAL ;
    PORT
      LAYER M5 ;
        RECT  40.368 0 40.392 0.192 ;
    END
  END di[295]
  PIN di[296]
    DIRECTION INPUT ;
    USE SIGNAL ;
    PORT
      LAYER M3 ;
        RECT  40.5 0 40.518 0.144 ;
    END
  END di[296]
  PIN di[297]
    DIRECTION INPUT ;
    USE SIGNAL ;
    PORT
      LAYER M5 ;
        RECT  40.608 0 40.632 0.192 ;
    END
  END di[297]
  PIN di[298]
    DIRECTION INPUT ;
    USE SIGNAL ;
    PORT
      LAYER M3 ;
        RECT  40.752 0 40.77 0.144 ;
    END
  END di[298]
  PIN di[299]
    DIRECTION INPUT ;
    USE SIGNAL ;
    PORT
      LAYER M5 ;
        RECT  40.848 0 40.872 0.192 ;
    END
  END di[299]
  PIN di[29]
    DIRECTION INPUT ;
    USE SIGNAL ;
    PORT
      LAYER M5 ;
        RECT  7.92 0 7.944 0.192 ;
    END
  END di[29]
  PIN di[2]
    DIRECTION INPUT ;
    USE SIGNAL ;
    PORT
      LAYER M3 ;
        RECT  4.608 0 4.626 0.144 ;
    END
  END di[2]
  PIN di[300]
    DIRECTION INPUT ;
    USE SIGNAL ;
    PORT
      LAYER M3 ;
        RECT  41.004 0 41.022 0.144 ;
    END
  END di[300]
  PIN di[301]
    DIRECTION INPUT ;
    USE SIGNAL ;
    PORT
      LAYER M5 ;
        RECT  41.088 0 41.112 0.192 ;
    END
  END di[301]
  PIN di[302]
    DIRECTION INPUT ;
    USE SIGNAL ;
    PORT
      LAYER M3 ;
        RECT  41.22 0 41.238 0.144 ;
    END
  END di[302]
  PIN di[303]
    DIRECTION INPUT ;
    USE SIGNAL ;
    PORT
      LAYER M5 ;
        RECT  41.328 0 41.352 0.192 ;
    END
  END di[303]
  PIN di[304]
    DIRECTION INPUT ;
    USE SIGNAL ;
    PORT
      LAYER M3 ;
        RECT  41.472 0 41.49 0.144 ;
    END
  END di[304]
  PIN di[305]
    DIRECTION INPUT ;
    USE SIGNAL ;
    PORT
      LAYER M5 ;
        RECT  41.616 0 41.64 0.192 ;
    END
  END di[305]
  PIN di[306]
    DIRECTION INPUT ;
    USE SIGNAL ;
    PORT
      LAYER M3 ;
        RECT  41.724 0 41.742 0.144 ;
    END
  END di[306]
  PIN di[307]
    DIRECTION INPUT ;
    USE SIGNAL ;
    PORT
      LAYER M5 ;
        RECT  41.856 0 41.88 0.192 ;
    END
  END di[307]
  PIN di[308]
    DIRECTION INPUT ;
    USE SIGNAL ;
    PORT
      LAYER M3 ;
        RECT  41.976 0 41.994 0.144 ;
    END
  END di[308]
  PIN di[309]
    DIRECTION INPUT ;
    USE SIGNAL ;
    PORT
      LAYER M5 ;
        RECT  42.096 0 42.12 0.192 ;
    END
  END di[309]
  PIN di[30]
    DIRECTION INPUT ;
    USE SIGNAL ;
    PORT
      LAYER M3 ;
        RECT  8.028 0 8.046 0.144 ;
    END
  END di[30]
  PIN di[310]
    DIRECTION INPUT ;
    USE SIGNAL ;
    PORT
      LAYER M3 ;
        RECT  42.192 0 42.21 0.144 ;
    END
  END di[310]
  PIN di[311]
    DIRECTION INPUT ;
    USE SIGNAL ;
    PORT
      LAYER M5 ;
        RECT  42.336 0 42.36 0.192 ;
    END
  END di[311]
  PIN di[312]
    DIRECTION INPUT ;
    USE SIGNAL ;
    PORT
      LAYER M3 ;
        RECT  42.444 0 42.462 0.144 ;
    END
  END di[312]
  PIN di[313]
    DIRECTION INPUT ;
    USE SIGNAL ;
    PORT
      LAYER M5 ;
        RECT  42.576 0 42.6 0.192 ;
    END
  END di[313]
  PIN di[314]
    DIRECTION INPUT ;
    USE SIGNAL ;
    PORT
      LAYER M3 ;
        RECT  42.696 0 42.714 0.144 ;
    END
  END di[314]
  PIN di[315]
    DIRECTION INPUT ;
    USE SIGNAL ;
    PORT
      LAYER M5 ;
        RECT  42.816 0 42.84 0.192 ;
    END
  END di[315]
  PIN di[316]
    DIRECTION INPUT ;
    USE SIGNAL ;
    PORT
      LAYER M3 ;
        RECT  42.948 0 42.966 0.144 ;
    END
  END di[316]
  PIN di[317]
    DIRECTION INPUT ;
    USE SIGNAL ;
    PORT
      LAYER M5 ;
        RECT  43.056 0 43.08 0.192 ;
    END
  END di[317]
  PIN di[318]
    DIRECTION INPUT ;
    USE SIGNAL ;
    PORT
      LAYER M3 ;
        RECT  43.2 0 43.218 0.144 ;
    END
  END di[318]
  PIN di[319]
    DIRECTION INPUT ;
    USE SIGNAL ;
    PORT
      LAYER M5 ;
        RECT  43.296 0 43.32 0.192 ;
    END
  END di[319]
  PIN di[31]
    DIRECTION INPUT ;
    USE SIGNAL ;
    PORT
      LAYER M5 ;
        RECT  8.16 0 8.184 0.192 ;
    END
  END di[31]
  PIN di[320]
    DIRECTION INPUT ;
    USE SIGNAL ;
    PORT
      LAYER M3 ;
        RECT  43.416 0 43.434 0.144 ;
    END
  END di[320]
  PIN di[321]
    DIRECTION INPUT ;
    USE SIGNAL ;
    PORT
      LAYER M5 ;
        RECT  43.536 0 43.56 0.192 ;
    END
  END di[321]
  PIN di[322]
    DIRECTION INPUT ;
    USE SIGNAL ;
    PORT
      LAYER M3 ;
        RECT  43.668 0 43.686 0.144 ;
    END
  END di[322]
  PIN di[323]
    DIRECTION INPUT ;
    USE SIGNAL ;
    PORT
      LAYER M5 ;
        RECT  43.776 0 43.8 0.192 ;
    END
  END di[323]
  PIN di[324]
    DIRECTION INPUT ;
    USE SIGNAL ;
    PORT
      LAYER M3 ;
        RECT  43.92 0 43.938 0.144 ;
    END
  END di[324]
  PIN di[325]
    DIRECTION INPUT ;
    USE SIGNAL ;
    PORT
      LAYER M5 ;
        RECT  44.016 0 44.04 0.192 ;
    END
  END di[325]
  PIN di[326]
    DIRECTION INPUT ;
    USE SIGNAL ;
    PORT
      LAYER M3 ;
        RECT  44.172 0 44.19 0.144 ;
    END
  END di[326]
  PIN di[327]
    DIRECTION INPUT ;
    USE SIGNAL ;
    PORT
      LAYER M5 ;
        RECT  44.256 0 44.28 0.192 ;
    END
  END di[327]
  PIN di[328]
    DIRECTION INPUT ;
    USE SIGNAL ;
    PORT
      LAYER M3 ;
        RECT  44.388 0 44.406 0.144 ;
    END
  END di[328]
  PIN di[329]
    DIRECTION INPUT ;
    USE SIGNAL ;
    PORT
      LAYER M5 ;
        RECT  44.544 0 44.568 0.192 ;
    END
  END di[329]
  PIN di[32]
    DIRECTION INPUT ;
    USE SIGNAL ;
    PORT
      LAYER M3 ;
        RECT  8.28 0 8.298 0.144 ;
    END
  END di[32]
  PIN di[330]
    DIRECTION INPUT ;
    USE SIGNAL ;
    PORT
      LAYER M3 ;
        RECT  44.64 0 44.658 0.144 ;
    END
  END di[330]
  PIN di[331]
    DIRECTION INPUT ;
    USE SIGNAL ;
    PORT
      LAYER M5 ;
        RECT  44.784 0 44.808 0.192 ;
    END
  END di[331]
  PIN di[332]
    DIRECTION INPUT ;
    USE SIGNAL ;
    PORT
      LAYER M3 ;
        RECT  44.892 0 44.91 0.144 ;
    END
  END di[332]
  PIN di[333]
    DIRECTION INPUT ;
    USE SIGNAL ;
    PORT
      LAYER M5 ;
        RECT  45.024 0 45.048 0.192 ;
    END
  END di[333]
  PIN di[334]
    DIRECTION INPUT ;
    USE SIGNAL ;
    PORT
      LAYER M3 ;
        RECT  45.144 0 45.162 0.144 ;
    END
  END di[334]
  PIN di[335]
    DIRECTION INPUT ;
    USE SIGNAL ;
    PORT
      LAYER M5 ;
        RECT  45.264 0 45.288 0.192 ;
    END
  END di[335]
  PIN di[336]
    DIRECTION INPUT ;
    USE SIGNAL ;
    PORT
      LAYER M3 ;
        RECT  45.396 0 45.414 0.144 ;
    END
  END di[336]
  PIN di[337]
    DIRECTION INPUT ;
    USE SIGNAL ;
    PORT
      LAYER M5 ;
        RECT  45.504 0 45.528 0.192 ;
    END
  END di[337]
  PIN di[338]
    DIRECTION INPUT ;
    USE SIGNAL ;
    PORT
      LAYER M3 ;
        RECT  45.612 0 45.63 0.144 ;
    END
  END di[338]
  PIN di[339]
    DIRECTION INPUT ;
    USE SIGNAL ;
    PORT
      LAYER M5 ;
        RECT  45.744 0 45.768 0.192 ;
    END
  END di[339]
  PIN di[33]
    DIRECTION INPUT ;
    USE SIGNAL ;
    PORT
      LAYER M5 ;
        RECT  8.4 0 8.424 0.192 ;
    END
  END di[33]
  PIN di[340]
    DIRECTION INPUT ;
    USE SIGNAL ;
    PORT
      LAYER M3 ;
        RECT  45.864 0 45.882 0.144 ;
    END
  END di[340]
  PIN di[341]
    DIRECTION INPUT ;
    USE SIGNAL ;
    PORT
      LAYER M5 ;
        RECT  45.984 0 46.008 0.192 ;
    END
  END di[341]
  PIN di[342]
    DIRECTION INPUT ;
    USE SIGNAL ;
    PORT
      LAYER M3 ;
        RECT  46.116 0 46.134 0.144 ;
    END
  END di[342]
  PIN di[343]
    DIRECTION INPUT ;
    USE SIGNAL ;
    PORT
      LAYER M5 ;
        RECT  46.224 0 46.248 0.192 ;
    END
  END di[343]
  PIN di[344]
    DIRECTION INPUT ;
    USE SIGNAL ;
    PORT
      LAYER M3 ;
        RECT  46.368 0 46.386 0.144 ;
    END
  END di[344]
  PIN di[345]
    DIRECTION INPUT ;
    USE SIGNAL ;
    PORT
      LAYER M5 ;
        RECT  46.464 0 46.488 0.192 ;
    END
  END di[345]
  PIN di[346]
    DIRECTION INPUT ;
    USE SIGNAL ;
    PORT
      LAYER M3 ;
        RECT  46.584 0 46.602 0.144 ;
    END
  END di[346]
  PIN di[347]
    DIRECTION INPUT ;
    USE SIGNAL ;
    PORT
      LAYER M5 ;
        RECT  46.704 0 46.728 0.192 ;
    END
  END di[347]
  PIN di[348]
    DIRECTION INPUT ;
    USE SIGNAL ;
    PORT
      LAYER M3 ;
        RECT  46.836 0 46.854 0.144 ;
    END
  END di[348]
  PIN di[349]
    DIRECTION INPUT ;
    USE SIGNAL ;
    PORT
      LAYER M5 ;
        RECT  46.944 0 46.968 0.192 ;
    END
  END di[349]
  PIN di[34]
    DIRECTION INPUT ;
    USE SIGNAL ;
    PORT
      LAYER M3 ;
        RECT  8.532 0 8.55 0.144 ;
    END
  END di[34]
  PIN di[350]
    DIRECTION INPUT ;
    USE SIGNAL ;
    PORT
      LAYER M3 ;
        RECT  47.088 0 47.106 0.144 ;
    END
  END di[350]
  PIN di[351]
    DIRECTION INPUT ;
    USE SIGNAL ;
    PORT
      LAYER M5 ;
        RECT  47.232 0 47.256 0.192 ;
    END
  END di[351]
  PIN di[352]
    DIRECTION INPUT ;
    USE SIGNAL ;
    PORT
      LAYER M3 ;
        RECT  47.34 0 47.358 0.144 ;
    END
  END di[352]
  PIN di[353]
    DIRECTION INPUT ;
    USE SIGNAL ;
    PORT
      LAYER M5 ;
        RECT  47.472 0 47.496 0.192 ;
    END
  END di[353]
  PIN di[354]
    DIRECTION INPUT ;
    USE SIGNAL ;
    PORT
      LAYER M3 ;
        RECT  47.592 0 47.61 0.144 ;
    END
  END di[354]
  PIN di[355]
    DIRECTION INPUT ;
    USE SIGNAL ;
    PORT
      LAYER M5 ;
        RECT  47.712 0 47.736 0.192 ;
    END
  END di[355]
  PIN di[356]
    DIRECTION INPUT ;
    USE SIGNAL ;
    PORT
      LAYER M3 ;
        RECT  47.808 0 47.826 0.144 ;
    END
  END di[356]
  PIN di[357]
    DIRECTION INPUT ;
    USE SIGNAL ;
    PORT
      LAYER M5 ;
        RECT  47.952 0 47.976 0.192 ;
    END
  END di[357]
  PIN di[358]
    DIRECTION INPUT ;
    USE SIGNAL ;
    PORT
      LAYER M3 ;
        RECT  48.06 0 48.078 0.144 ;
    END
  END di[358]
  PIN di[359]
    DIRECTION INPUT ;
    USE SIGNAL ;
    PORT
      LAYER M5 ;
        RECT  48.192 0 48.216 0.192 ;
    END
  END di[359]
  PIN di[35]
    DIRECTION INPUT ;
    USE SIGNAL ;
    PORT
      LAYER M5 ;
        RECT  8.64 0 8.664 0.192 ;
    END
  END di[35]
  PIN di[360]
    DIRECTION INPUT ;
    USE SIGNAL ;
    PORT
      LAYER M3 ;
        RECT  48.312 0 48.33 0.144 ;
    END
  END di[360]
  PIN di[361]
    DIRECTION INPUT ;
    USE SIGNAL ;
    PORT
      LAYER M5 ;
        RECT  48.432 0 48.456 0.192 ;
    END
  END di[361]
  PIN di[362]
    DIRECTION INPUT ;
    USE SIGNAL ;
    PORT
      LAYER M3 ;
        RECT  48.564 0 48.582 0.144 ;
    END
  END di[362]
  PIN di[363]
    DIRECTION INPUT ;
    USE SIGNAL ;
    PORT
      LAYER M5 ;
        RECT  48.672 0 48.696 0.192 ;
    END
  END di[363]
  PIN di[364]
    DIRECTION INPUT ;
    USE SIGNAL ;
    PORT
      LAYER M3 ;
        RECT  48.816 0 48.834 0.144 ;
    END
  END di[364]
  PIN di[365]
    DIRECTION INPUT ;
    USE SIGNAL ;
    PORT
      LAYER M5 ;
        RECT  48.912 0 48.936 0.192 ;
    END
  END di[365]
  PIN di[366]
    DIRECTION INPUT ;
    USE SIGNAL ;
    PORT
      LAYER M3 ;
        RECT  49.032 0 49.05 0.144 ;
    END
  END di[366]
  PIN di[367]
    DIRECTION INPUT ;
    USE SIGNAL ;
    PORT
      LAYER M5 ;
        RECT  49.152 0 49.176 0.192 ;
    END
  END di[367]
  PIN di[368]
    DIRECTION INPUT ;
    USE SIGNAL ;
    PORT
      LAYER M3 ;
        RECT  49.284 0 49.302 0.144 ;
    END
  END di[368]
  PIN di[369]
    DIRECTION INPUT ;
    USE SIGNAL ;
    PORT
      LAYER M5 ;
        RECT  49.392 0 49.416 0.192 ;
    END
  END di[369]
  PIN di[36]
    DIRECTION INPUT ;
    USE SIGNAL ;
    PORT
      LAYER M3 ;
        RECT  8.748 0 8.766 0.144 ;
    END
  END di[36]
  PIN di[370]
    DIRECTION INPUT ;
    USE SIGNAL ;
    PORT
      LAYER M3 ;
        RECT  49.536 0 49.554 0.144 ;
    END
  END di[370]
  PIN di[371]
    DIRECTION INPUT ;
    USE SIGNAL ;
    PORT
      LAYER M5 ;
        RECT  49.632 0 49.656 0.192 ;
    END
  END di[371]
  PIN di[372]
    DIRECTION INPUT ;
    USE SIGNAL ;
    PORT
      LAYER M3 ;
        RECT  49.788 0 49.806 0.144 ;
    END
  END di[372]
  PIN di[373]
    DIRECTION INPUT ;
    USE SIGNAL ;
    PORT
      LAYER M5 ;
        RECT  49.872 0 49.896 0.192 ;
    END
  END di[373]
  PIN di[374]
    DIRECTION INPUT ;
    USE SIGNAL ;
    PORT
      LAYER M3 ;
        RECT  50.004 0 50.022 0.144 ;
    END
  END di[374]
  PIN di[375]
    DIRECTION INPUT ;
    USE SIGNAL ;
    PORT
      LAYER M5 ;
        RECT  50.16 0 50.184 0.192 ;
    END
  END di[375]
  PIN di[376]
    DIRECTION INPUT ;
    USE SIGNAL ;
    PORT
      LAYER M3 ;
        RECT  50.256 0 50.274 0.144 ;
    END
  END di[376]
  PIN di[377]
    DIRECTION INPUT ;
    USE SIGNAL ;
    PORT
      LAYER M5 ;
        RECT  50.4 0 50.424 0.192 ;
    END
  END di[377]
  PIN di[378]
    DIRECTION INPUT ;
    USE SIGNAL ;
    PORT
      LAYER M3 ;
        RECT  50.508 0 50.526 0.144 ;
    END
  END di[378]
  PIN di[379]
    DIRECTION INPUT ;
    USE SIGNAL ;
    PORT
      LAYER M5 ;
        RECT  50.64 0 50.664 0.192 ;
    END
  END di[379]
  PIN di[37]
    DIRECTION INPUT ;
    USE SIGNAL ;
    PORT
      LAYER M5 ;
        RECT  8.88 0 8.904 0.192 ;
    END
  END di[37]
  PIN di[380]
    DIRECTION INPUT ;
    USE SIGNAL ;
    PORT
      LAYER M3 ;
        RECT  50.76 0 50.778 0.144 ;
    END
  END di[380]
  PIN di[381]
    DIRECTION INPUT ;
    USE SIGNAL ;
    PORT
      LAYER M5 ;
        RECT  50.88 0 50.904 0.192 ;
    END
  END di[381]
  PIN di[382]
    DIRECTION INPUT ;
    USE SIGNAL ;
    PORT
      LAYER M3 ;
        RECT  51.012 0 51.03 0.144 ;
    END
  END di[382]
  PIN di[383]
    DIRECTION INPUT ;
    USE SIGNAL ;
    PORT
      LAYER M5 ;
        RECT  51.12 0 51.144 0.192 ;
    END
  END di[383]
  PIN di[384]
    DIRECTION INPUT ;
    USE SIGNAL ;
    PORT
      LAYER M3 ;
        RECT  51.228 0 51.246 0.144 ;
    END
  END di[384]
  PIN di[385]
    DIRECTION INPUT ;
    USE SIGNAL ;
    PORT
      LAYER M5 ;
        RECT  51.36 0 51.384 0.192 ;
    END
  END di[385]
  PIN di[386]
    DIRECTION INPUT ;
    USE SIGNAL ;
    PORT
      LAYER M3 ;
        RECT  51.48 0 51.498 0.144 ;
    END
  END di[386]
  PIN di[387]
    DIRECTION INPUT ;
    USE SIGNAL ;
    PORT
      LAYER M5 ;
        RECT  51.6 0 51.624 0.192 ;
    END
  END di[387]
  PIN di[388]
    DIRECTION INPUT ;
    USE SIGNAL ;
    PORT
      LAYER M3 ;
        RECT  51.732 0 51.75 0.144 ;
    END
  END di[388]
  PIN di[389]
    DIRECTION INPUT ;
    USE SIGNAL ;
    PORT
      LAYER M5 ;
        RECT  51.84 0 51.864 0.192 ;
    END
  END di[389]
  PIN di[38]
    DIRECTION INPUT ;
    USE SIGNAL ;
    PORT
      LAYER M3 ;
        RECT  9 0 9.018 0.144 ;
    END
  END di[38]
  PIN di[390]
    DIRECTION INPUT ;
    USE SIGNAL ;
    PORT
      LAYER M3 ;
        RECT  51.984 0 52.002 0.144 ;
    END
  END di[390]
  PIN di[391]
    DIRECTION INPUT ;
    USE SIGNAL ;
    PORT
      LAYER M5 ;
        RECT  52.08 0 52.104 0.192 ;
    END
  END di[391]
  PIN di[392]
    DIRECTION INPUT ;
    USE SIGNAL ;
    PORT
      LAYER M3 ;
        RECT  52.2 0 52.218 0.144 ;
    END
  END di[392]
  PIN di[393]
    DIRECTION INPUT ;
    USE SIGNAL ;
    PORT
      LAYER M5 ;
        RECT  52.32 0 52.344 0.192 ;
    END
  END di[393]
  PIN di[394]
    DIRECTION INPUT ;
    USE SIGNAL ;
    PORT
      LAYER M3 ;
        RECT  52.452 0 52.47 0.144 ;
    END
  END di[394]
  PIN di[395]
    DIRECTION INPUT ;
    USE SIGNAL ;
    PORT
      LAYER M5 ;
        RECT  52.56 0 52.584 0.192 ;
    END
  END di[395]
  PIN di[396]
    DIRECTION INPUT ;
    USE SIGNAL ;
    PORT
      LAYER M3 ;
        RECT  52.704 0 52.722 0.144 ;
    END
  END di[396]
  PIN di[397]
    DIRECTION INPUT ;
    USE SIGNAL ;
    PORT
      LAYER M5 ;
        RECT  52.8 0 52.824 0.192 ;
    END
  END di[397]
  PIN di[398]
    DIRECTION INPUT ;
    USE SIGNAL ;
    PORT
      LAYER M3 ;
        RECT  52.956 0 52.974 0.144 ;
    END
  END di[398]
  PIN di[399]
    DIRECTION INPUT ;
    USE SIGNAL ;
    PORT
      LAYER M5 ;
        RECT  53.088 0 53.112 0.192 ;
    END
  END di[399]
  PIN di[39]
    DIRECTION INPUT ;
    USE SIGNAL ;
    PORT
      LAYER M5 ;
        RECT  9.12 0 9.144 0.192 ;
    END
  END di[39]
  PIN di[3]
    DIRECTION INPUT ;
    USE SIGNAL ;
    PORT
      LAYER M5 ;
        RECT  4.752 0 4.776 0.192 ;
    END
  END di[3]
  PIN di[400]
    DIRECTION INPUT ;
    USE SIGNAL ;
    PORT
      LAYER M3 ;
        RECT  53.208 0 53.226 0.144 ;
    END
  END di[400]
  PIN di[401]
    DIRECTION INPUT ;
    USE SIGNAL ;
    PORT
      LAYER M5 ;
        RECT  53.328 0 53.352 0.192 ;
    END
  END di[401]
  PIN di[402]
    DIRECTION INPUT ;
    USE SIGNAL ;
    PORT
      LAYER M3 ;
        RECT  53.424 0 53.442 0.144 ;
    END
  END di[402]
  PIN di[403]
    DIRECTION INPUT ;
    USE SIGNAL ;
    PORT
      LAYER M5 ;
        RECT  53.568 0 53.592 0.192 ;
    END
  END di[403]
  PIN di[404]
    DIRECTION INPUT ;
    USE SIGNAL ;
    PORT
      LAYER M3 ;
        RECT  53.676 0 53.694 0.144 ;
    END
  END di[404]
  PIN di[405]
    DIRECTION INPUT ;
    USE SIGNAL ;
    PORT
      LAYER M5 ;
        RECT  53.808 0 53.832 0.192 ;
    END
  END di[405]
  PIN di[406]
    DIRECTION INPUT ;
    USE SIGNAL ;
    PORT
      LAYER M3 ;
        RECT  53.928 0 53.946 0.144 ;
    END
  END di[406]
  PIN di[407]
    DIRECTION INPUT ;
    USE SIGNAL ;
    PORT
      LAYER M5 ;
        RECT  54.048 0 54.072 0.192 ;
    END
  END di[407]
  PIN di[408]
    DIRECTION INPUT ;
    USE SIGNAL ;
    PORT
      LAYER M3 ;
        RECT  54.18 0 54.198 0.144 ;
    END
  END di[408]
  PIN di[409]
    DIRECTION INPUT ;
    USE SIGNAL ;
    PORT
      LAYER M5 ;
        RECT  54.288 0 54.312 0.192 ;
    END
  END di[409]
  PIN di[40]
    DIRECTION INPUT ;
    USE SIGNAL ;
    PORT
      LAYER M3 ;
        RECT  9.252 0 9.27 0.144 ;
    END
  END di[40]
  PIN di[410]
    DIRECTION INPUT ;
    USE SIGNAL ;
    PORT
      LAYER M3 ;
        RECT  54.396 0 54.414 0.144 ;
    END
  END di[410]
  PIN di[411]
    DIRECTION INPUT ;
    USE SIGNAL ;
    PORT
      LAYER M5 ;
        RECT  54.528 0 54.552 0.192 ;
    END
  END di[411]
  PIN di[412]
    DIRECTION INPUT ;
    USE SIGNAL ;
    PORT
      LAYER M3 ;
        RECT  54.648 0 54.666 0.144 ;
    END
  END di[412]
  PIN di[413]
    DIRECTION INPUT ;
    USE SIGNAL ;
    PORT
      LAYER M5 ;
        RECT  54.768 0 54.792 0.192 ;
    END
  END di[413]
  PIN di[414]
    DIRECTION INPUT ;
    USE SIGNAL ;
    PORT
      LAYER M3 ;
        RECT  54.9 0 54.918 0.144 ;
    END
  END di[414]
  PIN di[415]
    DIRECTION INPUT ;
    USE SIGNAL ;
    PORT
      LAYER M5 ;
        RECT  55.008 0 55.032 0.192 ;
    END
  END di[415]
  PIN di[416]
    DIRECTION INPUT ;
    USE SIGNAL ;
    PORT
      LAYER M3 ;
        RECT  55.152 0 55.17 0.144 ;
    END
  END di[416]
  PIN di[417]
    DIRECTION INPUT ;
    USE SIGNAL ;
    PORT
      LAYER M5 ;
        RECT  55.248 0 55.272 0.192 ;
    END
  END di[417]
  PIN di[418]
    DIRECTION INPUT ;
    USE SIGNAL ;
    PORT
      LAYER M3 ;
        RECT  55.404 0 55.422 0.144 ;
    END
  END di[418]
  PIN di[419]
    DIRECTION INPUT ;
    USE SIGNAL ;
    PORT
      LAYER M5 ;
        RECT  55.488 0 55.512 0.192 ;
    END
  END di[419]
  PIN di[41]
    DIRECTION INPUT ;
    USE SIGNAL ;
    PORT
      LAYER M5 ;
        RECT  9.36 0 9.384 0.192 ;
    END
  END di[41]
  PIN di[420]
    DIRECTION INPUT ;
    USE SIGNAL ;
    PORT
      LAYER M3 ;
        RECT  55.62 0 55.638 0.144 ;
    END
  END di[420]
  PIN di[421]
    DIRECTION INPUT ;
    USE SIGNAL ;
    PORT
      LAYER M5 ;
        RECT  55.776 0 55.8 0.192 ;
    END
  END di[421]
  PIN di[422]
    DIRECTION INPUT ;
    USE SIGNAL ;
    PORT
      LAYER M3 ;
        RECT  55.872 0 55.89 0.144 ;
    END
  END di[422]
  PIN di[423]
    DIRECTION INPUT ;
    USE SIGNAL ;
    PORT
      LAYER M5 ;
        RECT  56.016 0 56.04 0.192 ;
    END
  END di[423]
  PIN di[424]
    DIRECTION INPUT ;
    USE SIGNAL ;
    PORT
      LAYER M3 ;
        RECT  56.124 0 56.142 0.144 ;
    END
  END di[424]
  PIN di[425]
    DIRECTION INPUT ;
    USE SIGNAL ;
    PORT
      LAYER M5 ;
        RECT  56.256 0 56.28 0.192 ;
    END
  END di[425]
  PIN di[426]
    DIRECTION INPUT ;
    USE SIGNAL ;
    PORT
      LAYER M3 ;
        RECT  56.376 0 56.394 0.144 ;
    END
  END di[426]
  PIN di[427]
    DIRECTION INPUT ;
    USE SIGNAL ;
    PORT
      LAYER M5 ;
        RECT  56.496 0 56.52 0.192 ;
    END
  END di[427]
  PIN di[428]
    DIRECTION INPUT ;
    USE SIGNAL ;
    PORT
      LAYER M3 ;
        RECT  56.592 0 56.61 0.144 ;
    END
  END di[428]
  PIN di[429]
    DIRECTION INPUT ;
    USE SIGNAL ;
    PORT
      LAYER M5 ;
        RECT  56.736 0 56.76 0.192 ;
    END
  END di[429]
  PIN di[42]
    DIRECTION INPUT ;
    USE SIGNAL ;
    PORT
      LAYER M3 ;
        RECT  9.504 0 9.522 0.144 ;
    END
  END di[42]
  PIN di[430]
    DIRECTION INPUT ;
    USE SIGNAL ;
    PORT
      LAYER M3 ;
        RECT  56.844 0 56.862 0.144 ;
    END
  END di[430]
  PIN di[431]
    DIRECTION INPUT ;
    USE SIGNAL ;
    PORT
      LAYER M5 ;
        RECT  56.976 0 57 0.192 ;
    END
  END di[431]
  PIN di[432]
    DIRECTION INPUT ;
    USE SIGNAL ;
    PORT
      LAYER M3 ;
        RECT  57.096 0 57.114 0.144 ;
    END
  END di[432]
  PIN di[433]
    DIRECTION INPUT ;
    USE SIGNAL ;
    PORT
      LAYER M5 ;
        RECT  57.216 0 57.24 0.192 ;
    END
  END di[433]
  PIN di[434]
    DIRECTION INPUT ;
    USE SIGNAL ;
    PORT
      LAYER M3 ;
        RECT  57.348 0 57.366 0.144 ;
    END
  END di[434]
  PIN di[435]
    DIRECTION INPUT ;
    USE SIGNAL ;
    PORT
      LAYER M5 ;
        RECT  57.456 0 57.48 0.192 ;
    END
  END di[435]
  PIN di[436]
    DIRECTION INPUT ;
    USE SIGNAL ;
    PORT
      LAYER M3 ;
        RECT  57.6 0 57.618 0.144 ;
    END
  END di[436]
  PIN di[437]
    DIRECTION INPUT ;
    USE SIGNAL ;
    PORT
      LAYER M5 ;
        RECT  57.696 0 57.72 0.192 ;
    END
  END di[437]
  PIN di[438]
    DIRECTION INPUT ;
    USE SIGNAL ;
    PORT
      LAYER M3 ;
        RECT  57.816 0 57.834 0.144 ;
    END
  END di[438]
  PIN di[439]
    DIRECTION INPUT ;
    USE SIGNAL ;
    PORT
      LAYER M5 ;
        RECT  57.936 0 57.96 0.192 ;
    END
  END di[439]
  PIN di[43]
    DIRECTION INPUT ;
    USE SIGNAL ;
    PORT
      LAYER M5 ;
        RECT  9.6 0 9.624 0.192 ;
    END
  END di[43]
  PIN di[440]
    DIRECTION INPUT ;
    USE SIGNAL ;
    PORT
      LAYER M3 ;
        RECT  58.068 0 58.086 0.144 ;
    END
  END di[440]
  PIN di[441]
    DIRECTION INPUT ;
    USE SIGNAL ;
    PORT
      LAYER M5 ;
        RECT  58.176 0 58.2 0.192 ;
    END
  END di[441]
  PIN di[442]
    DIRECTION INPUT ;
    USE SIGNAL ;
    PORT
      LAYER M3 ;
        RECT  58.32 0 58.338 0.144 ;
    END
  END di[442]
  PIN di[443]
    DIRECTION INPUT ;
    USE SIGNAL ;
    PORT
      LAYER M5 ;
        RECT  58.416 0 58.44 0.192 ;
    END
  END di[443]
  PIN di[444]
    DIRECTION INPUT ;
    USE SIGNAL ;
    PORT
      LAYER M3 ;
        RECT  58.572 0 58.59 0.144 ;
    END
  END di[444]
  PIN di[445]
    DIRECTION INPUT ;
    USE SIGNAL ;
    PORT
      LAYER M5 ;
        RECT  58.704 0 58.728 0.192 ;
    END
  END di[445]
  PIN di[446]
    DIRECTION INPUT ;
    USE SIGNAL ;
    PORT
      LAYER M3 ;
        RECT  58.824 0 58.842 0.144 ;
    END
  END di[446]
  PIN di[447]
    DIRECTION INPUT ;
    USE SIGNAL ;
    PORT
      LAYER M5 ;
        RECT  58.944 0 58.968 0.192 ;
    END
  END di[447]
  PIN di[448]
    DIRECTION INPUT ;
    USE SIGNAL ;
    PORT
      LAYER M3 ;
        RECT  59.04 0 59.058 0.144 ;
    END
  END di[448]
  PIN di[449]
    DIRECTION INPUT ;
    USE SIGNAL ;
    PORT
      LAYER M5 ;
        RECT  59.184 0 59.208 0.192 ;
    END
  END di[449]
  PIN di[44]
    DIRECTION INPUT ;
    USE SIGNAL ;
    PORT
      LAYER M3 ;
        RECT  9.756 0 9.774 0.144 ;
    END
  END di[44]
  PIN di[450]
    DIRECTION INPUT ;
    USE SIGNAL ;
    PORT
      LAYER M3 ;
        RECT  59.292 0 59.31 0.144 ;
    END
  END di[450]
  PIN di[451]
    DIRECTION INPUT ;
    USE SIGNAL ;
    PORT
      LAYER M5 ;
        RECT  59.424 0 59.448 0.192 ;
    END
  END di[451]
  PIN di[452]
    DIRECTION INPUT ;
    USE SIGNAL ;
    PORT
      LAYER M3 ;
        RECT  59.544 0 59.562 0.144 ;
    END
  END di[452]
  PIN di[453]
    DIRECTION INPUT ;
    USE SIGNAL ;
    PORT
      LAYER M5 ;
        RECT  59.664 0 59.688 0.192 ;
    END
  END di[453]
  PIN di[454]
    DIRECTION INPUT ;
    USE SIGNAL ;
    PORT
      LAYER M3 ;
        RECT  59.796 0 59.814 0.144 ;
    END
  END di[454]
  PIN di[455]
    DIRECTION INPUT ;
    USE SIGNAL ;
    PORT
      LAYER M5 ;
        RECT  59.904 0 59.928 0.192 ;
    END
  END di[455]
  PIN di[456]
    DIRECTION INPUT ;
    USE SIGNAL ;
    PORT
      LAYER M3 ;
        RECT  60.012 0 60.03 0.144 ;
    END
  END di[456]
  PIN di[457]
    DIRECTION INPUT ;
    USE SIGNAL ;
    PORT
      LAYER M5 ;
        RECT  60.144 0 60.168 0.192 ;
    END
  END di[457]
  PIN di[458]
    DIRECTION INPUT ;
    USE SIGNAL ;
    PORT
      LAYER M3 ;
        RECT  60.264 0 60.282 0.144 ;
    END
  END di[458]
  PIN di[459]
    DIRECTION INPUT ;
    USE SIGNAL ;
    PORT
      LAYER M5 ;
        RECT  60.384 0 60.408 0.192 ;
    END
  END di[459]
  PIN di[45]
    DIRECTION INPUT ;
    USE SIGNAL ;
    PORT
      LAYER M5 ;
        RECT  9.84 0 9.864 0.192 ;
    END
  END di[45]
  PIN di[460]
    DIRECTION INPUT ;
    USE SIGNAL ;
    PORT
      LAYER M3 ;
        RECT  60.516 0 60.534 0.144 ;
    END
  END di[460]
  PIN di[461]
    DIRECTION INPUT ;
    USE SIGNAL ;
    PORT
      LAYER M5 ;
        RECT  60.624 0 60.648 0.192 ;
    END
  END di[461]
  PIN di[462]
    DIRECTION INPUT ;
    USE SIGNAL ;
    PORT
      LAYER M3 ;
        RECT  60.768 0 60.786 0.144 ;
    END
  END di[462]
  PIN di[463]
    DIRECTION INPUT ;
    USE SIGNAL ;
    PORT
      LAYER M5 ;
        RECT  60.864 0 60.888 0.192 ;
    END
  END di[463]
  PIN di[464]
    DIRECTION INPUT ;
    USE SIGNAL ;
    PORT
      LAYER M3 ;
        RECT  61.02 0 61.038 0.144 ;
    END
  END di[464]
  PIN di[465]
    DIRECTION INPUT ;
    USE SIGNAL ;
    PORT
      LAYER M5 ;
        RECT  61.104 0 61.128 0.192 ;
    END
  END di[465]
  PIN di[466]
    DIRECTION INPUT ;
    USE SIGNAL ;
    PORT
      LAYER M3 ;
        RECT  61.236 0 61.254 0.144 ;
    END
  END di[466]
  PIN di[467]
    DIRECTION INPUT ;
    USE SIGNAL ;
    PORT
      LAYER M5 ;
        RECT  61.344 0 61.368 0.192 ;
    END
  END di[467]
  PIN di[468]
    DIRECTION INPUT ;
    USE SIGNAL ;
    PORT
      LAYER M3 ;
        RECT  61.488 0 61.506 0.144 ;
    END
  END di[468]
  PIN di[469]
    DIRECTION INPUT ;
    USE SIGNAL ;
    PORT
      LAYER M5 ;
        RECT  61.632 0 61.656 0.192 ;
    END
  END di[469]
  PIN di[46]
    DIRECTION INPUT ;
    USE SIGNAL ;
    PORT
      LAYER M3 ;
        RECT  9.972 0 9.99 0.144 ;
    END
  END di[46]
  PIN di[470]
    DIRECTION INPUT ;
    USE SIGNAL ;
    PORT
      LAYER M3 ;
        RECT  61.74 0 61.758 0.144 ;
    END
  END di[470]
  PIN di[471]
    DIRECTION INPUT ;
    USE SIGNAL ;
    PORT
      LAYER M5 ;
        RECT  61.872 0 61.896 0.192 ;
    END
  END di[471]
  PIN di[472]
    DIRECTION INPUT ;
    USE SIGNAL ;
    PORT
      LAYER M3 ;
        RECT  61.992 0 62.01 0.144 ;
    END
  END di[472]
  PIN di[473]
    DIRECTION INPUT ;
    USE SIGNAL ;
    PORT
      LAYER M5 ;
        RECT  62.112 0 62.136 0.192 ;
    END
  END di[473]
  PIN di[474]
    DIRECTION INPUT ;
    USE SIGNAL ;
    PORT
      LAYER M3 ;
        RECT  62.208 0 62.226 0.144 ;
    END
  END di[474]
  PIN di[475]
    DIRECTION INPUT ;
    USE SIGNAL ;
    PORT
      LAYER M5 ;
        RECT  62.352 0 62.376 0.192 ;
    END
  END di[475]
  PIN di[476]
    DIRECTION INPUT ;
    USE SIGNAL ;
    PORT
      LAYER M3 ;
        RECT  62.46 0 62.478 0.144 ;
    END
  END di[476]
  PIN di[477]
    DIRECTION INPUT ;
    USE SIGNAL ;
    PORT
      LAYER M5 ;
        RECT  62.592 0 62.616 0.192 ;
    END
  END di[477]
  PIN di[478]
    DIRECTION INPUT ;
    USE SIGNAL ;
    PORT
      LAYER M3 ;
        RECT  62.712 0 62.73 0.144 ;
    END
  END di[478]
  PIN di[479]
    DIRECTION INPUT ;
    USE SIGNAL ;
    PORT
      LAYER M5 ;
        RECT  62.832 0 62.856 0.192 ;
    END
  END di[479]
  PIN di[47]
    DIRECTION INPUT ;
    USE SIGNAL ;
    PORT
      LAYER M5 ;
        RECT  10.128 0 10.152 0.192 ;
    END
  END di[47]
  PIN di[480]
    DIRECTION INPUT ;
    USE SIGNAL ;
    PORT
      LAYER M3 ;
        RECT  62.964 0 62.982 0.144 ;
    END
  END di[480]
  PIN di[481]
    DIRECTION INPUT ;
    USE SIGNAL ;
    PORT
      LAYER M5 ;
        RECT  63.072 0 63.096 0.192 ;
    END
  END di[481]
  PIN di[482]
    DIRECTION INPUT ;
    USE SIGNAL ;
    PORT
      LAYER M3 ;
        RECT  63.216 0 63.234 0.144 ;
    END
  END di[482]
  PIN di[483]
    DIRECTION INPUT ;
    USE SIGNAL ;
    PORT
      LAYER M5 ;
        RECT  63.312 0 63.336 0.192 ;
    END
  END di[483]
  PIN di[484]
    DIRECTION INPUT ;
    USE SIGNAL ;
    PORT
      LAYER M3 ;
        RECT  63.432 0 63.45 0.144 ;
    END
  END di[484]
  PIN di[485]
    DIRECTION INPUT ;
    USE SIGNAL ;
    PORT
      LAYER M5 ;
        RECT  63.552 0 63.576 0.192 ;
    END
  END di[485]
  PIN di[486]
    DIRECTION INPUT ;
    USE SIGNAL ;
    PORT
      LAYER M3 ;
        RECT  63.684 0 63.702 0.144 ;
    END
  END di[486]
  PIN di[487]
    DIRECTION INPUT ;
    USE SIGNAL ;
    PORT
      LAYER M5 ;
        RECT  63.792 0 63.816 0.192 ;
    END
  END di[487]
  PIN di[488]
    DIRECTION INPUT ;
    USE SIGNAL ;
    PORT
      LAYER M3 ;
        RECT  63.936 0 63.954 0.144 ;
    END
  END di[488]
  PIN di[489]
    DIRECTION INPUT ;
    USE SIGNAL ;
    PORT
      LAYER M5 ;
        RECT  64.032 0 64.056 0.192 ;
    END
  END di[489]
  PIN di[48]
    DIRECTION INPUT ;
    USE SIGNAL ;
    PORT
      LAYER M3 ;
        RECT  10.224 0 10.242 0.144 ;
    END
  END di[48]
  PIN di[490]
    DIRECTION INPUT ;
    USE SIGNAL ;
    PORT
      LAYER M3 ;
        RECT  64.188 0 64.206 0.144 ;
    END
  END di[490]
  PIN di[491]
    DIRECTION INPUT ;
    USE SIGNAL ;
    PORT
      LAYER M5 ;
        RECT  64.272 0 64.296 0.192 ;
    END
  END di[491]
  PIN di[492]
    DIRECTION INPUT ;
    USE SIGNAL ;
    PORT
      LAYER M3 ;
        RECT  64.404 0 64.422 0.144 ;
    END
  END di[492]
  PIN di[493]
    DIRECTION INPUT ;
    USE SIGNAL ;
    PORT
      LAYER M5 ;
        RECT  64.56 0 64.584 0.192 ;
    END
  END di[493]
  PIN di[494]
    DIRECTION INPUT ;
    USE SIGNAL ;
    PORT
      LAYER M3 ;
        RECT  64.656 0 64.674 0.144 ;
    END
  END di[494]
  PIN di[495]
    DIRECTION INPUT ;
    USE SIGNAL ;
    PORT
      LAYER M5 ;
        RECT  64.8 0 64.824 0.192 ;
    END
  END di[495]
  PIN di[496]
    DIRECTION INPUT ;
    USE SIGNAL ;
    PORT
      LAYER M3 ;
        RECT  64.908 0 64.926 0.144 ;
    END
  END di[496]
  PIN di[497]
    DIRECTION INPUT ;
    USE SIGNAL ;
    PORT
      LAYER M5 ;
        RECT  65.04 0 65.064 0.192 ;
    END
  END di[497]
  PIN di[498]
    DIRECTION INPUT ;
    USE SIGNAL ;
    PORT
      LAYER M3 ;
        RECT  65.16 0 65.178 0.144 ;
    END
  END di[498]
  PIN di[499]
    DIRECTION INPUT ;
    USE SIGNAL ;
    PORT
      LAYER M5 ;
        RECT  65.28 0 65.304 0.192 ;
    END
  END di[499]
  PIN di[49]
    DIRECTION INPUT ;
    USE SIGNAL ;
    PORT
      LAYER M5 ;
        RECT  10.368 0 10.392 0.192 ;
    END
  END di[49]
  PIN di[4]
    DIRECTION INPUT ;
    USE SIGNAL ;
    PORT
      LAYER M3 ;
        RECT  4.86 0 4.878 0.144 ;
    END
  END di[4]
  PIN di[500]
    DIRECTION INPUT ;
    USE SIGNAL ;
    PORT
      LAYER M3 ;
        RECT  65.412 0 65.43 0.144 ;
    END
  END di[500]
  PIN di[501]
    DIRECTION INPUT ;
    USE SIGNAL ;
    PORT
      LAYER M5 ;
        RECT  65.52 0 65.544 0.192 ;
    END
  END di[501]
  PIN di[502]
    DIRECTION INPUT ;
    USE SIGNAL ;
    PORT
      LAYER M3 ;
        RECT  65.628 0 65.646 0.144 ;
    END
  END di[502]
  PIN di[503]
    DIRECTION INPUT ;
    USE SIGNAL ;
    PORT
      LAYER M5 ;
        RECT  65.76 0 65.784 0.192 ;
    END
  END di[503]
  PIN di[504]
    DIRECTION INPUT ;
    USE SIGNAL ;
    PORT
      LAYER M3 ;
        RECT  65.88 0 65.898 0.144 ;
    END
  END di[504]
  PIN di[505]
    DIRECTION INPUT ;
    USE SIGNAL ;
    PORT
      LAYER M5 ;
        RECT  66 0 66.024 0.192 ;
    END
  END di[505]
  PIN di[506]
    DIRECTION INPUT ;
    USE SIGNAL ;
    PORT
      LAYER M3 ;
        RECT  66.132 0 66.15 0.144 ;
    END
  END di[506]
  PIN di[507]
    DIRECTION INPUT ;
    USE SIGNAL ;
    PORT
      LAYER M5 ;
        RECT  66.24 0 66.264 0.192 ;
    END
  END di[507]
  PIN di[508]
    DIRECTION INPUT ;
    USE SIGNAL ;
    PORT
      LAYER M3 ;
        RECT  66.384 0 66.402 0.144 ;
    END
  END di[508]
  PIN di[509]
    DIRECTION INPUT ;
    USE SIGNAL ;
    PORT
      LAYER M5 ;
        RECT  66.48 0 66.504 0.192 ;
    END
  END di[509]
  PIN di[50]
    DIRECTION INPUT ;
    USE SIGNAL ;
    PORT
      LAYER M3 ;
        RECT  10.476 0 10.494 0.144 ;
    END
  END di[50]
  PIN di[510]
    DIRECTION INPUT ;
    USE SIGNAL ;
    PORT
      LAYER M3 ;
        RECT  66.6 0 66.618 0.144 ;
    END
  END di[510]
  PIN di[511]
    DIRECTION INPUT ;
    USE SIGNAL ;
    PORT
      LAYER M5 ;
        RECT  66.72 0 66.744 0.192 ;
    END
  END di[511]
  PIN di[512]
    DIRECTION INPUT ;
    USE SIGNAL ;
    PORT
      LAYER M3 ;
        RECT  66.852 0 66.87 0.144 ;
    END
  END di[512]
  PIN di[513]
    DIRECTION INPUT ;
    USE SIGNAL ;
    PORT
      LAYER M5 ;
        RECT  66.96 0 66.984 0.192 ;
    END
  END di[513]
  PIN di[514]
    DIRECTION INPUT ;
    USE SIGNAL ;
    PORT
      LAYER M3 ;
        RECT  67.104 0 67.122 0.144 ;
    END
  END di[514]
  PIN di[515]
    DIRECTION INPUT ;
    USE SIGNAL ;
    PORT
      LAYER M5 ;
        RECT  67.248 0 67.272 0.192 ;
    END
  END di[515]
  PIN di[516]
    DIRECTION INPUT ;
    USE SIGNAL ;
    PORT
      LAYER M3 ;
        RECT  67.356 0 67.374 0.144 ;
    END
  END di[516]
  PIN di[517]
    DIRECTION INPUT ;
    USE SIGNAL ;
    PORT
      LAYER M5 ;
        RECT  67.488 0 67.512 0.192 ;
    END
  END di[517]
  PIN di[518]
    DIRECTION INPUT ;
    USE SIGNAL ;
    PORT
      LAYER M3 ;
        RECT  67.608 0 67.626 0.144 ;
    END
  END di[518]
  PIN di[519]
    DIRECTION INPUT ;
    USE SIGNAL ;
    PORT
      LAYER M5 ;
        RECT  67.728 0 67.752 0.192 ;
    END
  END di[519]
  PIN di[51]
    DIRECTION INPUT ;
    USE SIGNAL ;
    PORT
      LAYER M5 ;
        RECT  10.608 0 10.632 0.192 ;
    END
  END di[51]
  PIN di[520]
    DIRECTION INPUT ;
    USE SIGNAL ;
    PORT
      LAYER M3 ;
        RECT  67.824 0 67.842 0.144 ;
    END
  END di[520]
  PIN di[521]
    DIRECTION INPUT ;
    USE SIGNAL ;
    PORT
      LAYER M5 ;
        RECT  67.968 0 67.992 0.192 ;
    END
  END di[521]
  PIN di[522]
    DIRECTION INPUT ;
    USE SIGNAL ;
    PORT
      LAYER M3 ;
        RECT  68.076 0 68.094 0.144 ;
    END
  END di[522]
  PIN di[523]
    DIRECTION INPUT ;
    USE SIGNAL ;
    PORT
      LAYER M5 ;
        RECT  68.208 0 68.232 0.192 ;
    END
  END di[523]
  PIN di[524]
    DIRECTION INPUT ;
    USE SIGNAL ;
    PORT
      LAYER M3 ;
        RECT  68.328 0 68.346 0.144 ;
    END
  END di[524]
  PIN di[525]
    DIRECTION INPUT ;
    USE SIGNAL ;
    PORT
      LAYER M5 ;
        RECT  68.448 0 68.472 0.192 ;
    END
  END di[525]
  PIN di[526]
    DIRECTION INPUT ;
    USE SIGNAL ;
    PORT
      LAYER M3 ;
        RECT  68.58 0 68.598 0.144 ;
    END
  END di[526]
  PIN di[527]
    DIRECTION INPUT ;
    USE SIGNAL ;
    PORT
      LAYER M5 ;
        RECT  68.688 0 68.712 0.192 ;
    END
  END di[527]
  PIN di[528]
    DIRECTION INPUT ;
    USE SIGNAL ;
    PORT
      LAYER M3 ;
        RECT  68.832 0 68.85 0.144 ;
    END
  END di[528]
  PIN di[529]
    DIRECTION INPUT ;
    USE SIGNAL ;
    PORT
      LAYER M5 ;
        RECT  68.928 0 68.952 0.192 ;
    END
  END di[529]
  PIN di[52]
    DIRECTION INPUT ;
    USE SIGNAL ;
    PORT
      LAYER M3 ;
        RECT  10.728 0 10.746 0.144 ;
    END
  END di[52]
  PIN di[530]
    DIRECTION INPUT ;
    USE SIGNAL ;
    PORT
      LAYER M3 ;
        RECT  69.048 0 69.066 0.144 ;
    END
  END di[530]
  PIN di[531]
    DIRECTION INPUT ;
    USE SIGNAL ;
    PORT
      LAYER M5 ;
        RECT  69.168 0 69.192 0.192 ;
    END
  END di[531]
  PIN di[532]
    DIRECTION INPUT ;
    USE SIGNAL ;
    PORT
      LAYER M3 ;
        RECT  69.3 0 69.318 0.144 ;
    END
  END di[532]
  PIN di[533]
    DIRECTION INPUT ;
    USE SIGNAL ;
    PORT
      LAYER M5 ;
        RECT  69.408 0 69.432 0.192 ;
    END
  END di[533]
  PIN di[534]
    DIRECTION INPUT ;
    USE SIGNAL ;
    PORT
      LAYER M3 ;
        RECT  69.552 0 69.57 0.144 ;
    END
  END di[534]
  PIN di[535]
    DIRECTION INPUT ;
    USE SIGNAL ;
    PORT
      LAYER M5 ;
        RECT  69.648 0 69.672 0.192 ;
    END
  END di[535]
  PIN di[536]
    DIRECTION INPUT ;
    USE SIGNAL ;
    PORT
      LAYER M3 ;
        RECT  69.804 0 69.822 0.144 ;
    END
  END di[536]
  PIN di[537]
    DIRECTION INPUT ;
    USE SIGNAL ;
    PORT
      LAYER M5 ;
        RECT  69.888 0 69.912 0.192 ;
    END
  END di[537]
  PIN di[538]
    DIRECTION INPUT ;
    USE SIGNAL ;
    PORT
      LAYER M3 ;
        RECT  70.02 0 70.038 0.144 ;
    END
  END di[538]
  PIN di[539]
    DIRECTION INPUT ;
    USE SIGNAL ;
    PORT
      LAYER M5 ;
        RECT  70.176 0 70.2 0.192 ;
    END
  END di[539]
  PIN di[53]
    DIRECTION INPUT ;
    USE SIGNAL ;
    PORT
      LAYER M5 ;
        RECT  10.848 0 10.872 0.192 ;
    END
  END di[53]
  PIN di[540]
    DIRECTION INPUT ;
    USE SIGNAL ;
    PORT
      LAYER M3 ;
        RECT  70.272 0 70.29 0.144 ;
    END
  END di[540]
  PIN di[541]
    DIRECTION INPUT ;
    USE SIGNAL ;
    PORT
      LAYER M5 ;
        RECT  70.416 0 70.44 0.192 ;
    END
  END di[541]
  PIN di[542]
    DIRECTION INPUT ;
    USE SIGNAL ;
    PORT
      LAYER M3 ;
        RECT  70.524 0 70.542 0.144 ;
    END
  END di[542]
  PIN di[543]
    DIRECTION INPUT ;
    USE SIGNAL ;
    PORT
      LAYER M5 ;
        RECT  70.656 0 70.68 0.192 ;
    END
  END di[543]
  PIN di[544]
    DIRECTION INPUT ;
    USE SIGNAL ;
    PORT
      LAYER M3 ;
        RECT  70.776 0 70.794 0.144 ;
    END
  END di[544]
  PIN di[545]
    DIRECTION INPUT ;
    USE SIGNAL ;
    PORT
      LAYER M5 ;
        RECT  70.896 0 70.92 0.192 ;
    END
  END di[545]
  PIN di[546]
    DIRECTION INPUT ;
    USE SIGNAL ;
    PORT
      LAYER M3 ;
        RECT  71.028 0 71.046 0.144 ;
    END
  END di[546]
  PIN di[547]
    DIRECTION INPUT ;
    USE SIGNAL ;
    PORT
      LAYER M5 ;
        RECT  71.136 0 71.16 0.192 ;
    END
  END di[547]
  PIN di[548]
    DIRECTION INPUT ;
    USE SIGNAL ;
    PORT
      LAYER M3 ;
        RECT  71.244 0 71.262 0.144 ;
    END
  END di[548]
  PIN di[549]
    DIRECTION INPUT ;
    USE SIGNAL ;
    PORT
      LAYER M5 ;
        RECT  71.376 0 71.4 0.192 ;
    END
  END di[549]
  PIN di[54]
    DIRECTION INPUT ;
    USE SIGNAL ;
    PORT
      LAYER M3 ;
        RECT  10.98 0 10.998 0.144 ;
    END
  END di[54]
  PIN di[550]
    DIRECTION INPUT ;
    USE SIGNAL ;
    PORT
      LAYER M3 ;
        RECT  71.496 0 71.514 0.144 ;
    END
  END di[550]
  PIN di[551]
    DIRECTION INPUT ;
    USE SIGNAL ;
    PORT
      LAYER M5 ;
        RECT  71.616 0 71.64 0.192 ;
    END
  END di[551]
  PIN di[552]
    DIRECTION INPUT ;
    USE SIGNAL ;
    PORT
      LAYER M3 ;
        RECT  71.748 0 71.766 0.144 ;
    END
  END di[552]
  PIN di[553]
    DIRECTION INPUT ;
    USE SIGNAL ;
    PORT
      LAYER M5 ;
        RECT  71.856 0 71.88 0.192 ;
    END
  END di[553]
  PIN di[554]
    DIRECTION INPUT ;
    USE SIGNAL ;
    PORT
      LAYER M3 ;
        RECT  72 0 72.018 0.144 ;
    END
  END di[554]
  PIN di[555]
    DIRECTION INPUT ;
    USE SIGNAL ;
    PORT
      LAYER M5 ;
        RECT  72.096 0 72.12 0.192 ;
    END
  END di[555]
  PIN di[556]
    DIRECTION INPUT ;
    USE SIGNAL ;
    PORT
      LAYER M3 ;
        RECT  72.216 0 72.234 0.144 ;
    END
  END di[556]
  PIN di[557]
    DIRECTION INPUT ;
    USE SIGNAL ;
    PORT
      LAYER M5 ;
        RECT  72.336 0 72.36 0.192 ;
    END
  END di[557]
  PIN di[558]
    DIRECTION INPUT ;
    USE SIGNAL ;
    PORT
      LAYER M3 ;
        RECT  72.468 0 72.486 0.144 ;
    END
  END di[558]
  PIN di[559]
    DIRECTION INPUT ;
    USE SIGNAL ;
    PORT
      LAYER M5 ;
        RECT  72.576 0 72.6 0.192 ;
    END
  END di[559]
  PIN di[55]
    DIRECTION INPUT ;
    USE SIGNAL ;
    PORT
      LAYER M5 ;
        RECT  11.088 0 11.112 0.192 ;
    END
  END di[55]
  PIN di[560]
    DIRECTION INPUT ;
    USE SIGNAL ;
    PORT
      LAYER M3 ;
        RECT  72.72 0 72.738 0.144 ;
    END
  END di[560]
  PIN di[561]
    DIRECTION INPUT ;
    USE SIGNAL ;
    PORT
      LAYER M5 ;
        RECT  72.816 0 72.84 0.192 ;
    END
  END di[561]
  PIN di[562]
    DIRECTION INPUT ;
    USE SIGNAL ;
    PORT
      LAYER M3 ;
        RECT  72.972 0 72.99 0.144 ;
    END
  END di[562]
  PIN di[563]
    DIRECTION INPUT ;
    USE SIGNAL ;
    PORT
      LAYER M5 ;
        RECT  73.104 0 73.128 0.192 ;
    END
  END di[563]
  PIN di[564]
    DIRECTION INPUT ;
    USE SIGNAL ;
    PORT
      LAYER M3 ;
        RECT  73.224 0 73.242 0.144 ;
    END
  END di[564]
  PIN di[565]
    DIRECTION INPUT ;
    USE SIGNAL ;
    PORT
      LAYER M5 ;
        RECT  73.344 0 73.368 0.192 ;
    END
  END di[565]
  PIN di[566]
    DIRECTION INPUT ;
    USE SIGNAL ;
    PORT
      LAYER M3 ;
        RECT  73.44 0 73.458 0.144 ;
    END
  END di[566]
  PIN di[567]
    DIRECTION INPUT ;
    USE SIGNAL ;
    PORT
      LAYER M5 ;
        RECT  73.584 0 73.608 0.192 ;
    END
  END di[567]
  PIN di[568]
    DIRECTION INPUT ;
    USE SIGNAL ;
    PORT
      LAYER M3 ;
        RECT  73.692 0 73.71 0.144 ;
    END
  END di[568]
  PIN di[569]
    DIRECTION INPUT ;
    USE SIGNAL ;
    PORT
      LAYER M5 ;
        RECT  73.824 0 73.848 0.192 ;
    END
  END di[569]
  PIN di[56]
    DIRECTION INPUT ;
    USE SIGNAL ;
    PORT
      LAYER M3 ;
        RECT  11.196 0 11.214 0.144 ;
    END
  END di[56]
  PIN di[570]
    DIRECTION INPUT ;
    USE SIGNAL ;
    PORT
      LAYER M3 ;
        RECT  73.944 0 73.962 0.144 ;
    END
  END di[570]
  PIN di[571]
    DIRECTION INPUT ;
    USE SIGNAL ;
    PORT
      LAYER M5 ;
        RECT  74.064 0 74.088 0.192 ;
    END
  END di[571]
  PIN di[572]
    DIRECTION INPUT ;
    USE SIGNAL ;
    PORT
      LAYER M3 ;
        RECT  74.196 0 74.214 0.144 ;
    END
  END di[572]
  PIN di[573]
    DIRECTION INPUT ;
    USE SIGNAL ;
    PORT
      LAYER M5 ;
        RECT  74.304 0 74.328 0.192 ;
    END
  END di[573]
  PIN di[574]
    DIRECTION INPUT ;
    USE SIGNAL ;
    PORT
      LAYER M3 ;
        RECT  74.412 0 74.43 0.144 ;
    END
  END di[574]
  PIN di[575]
    DIRECTION INPUT ;
    USE SIGNAL ;
    PORT
      LAYER M5 ;
        RECT  74.544 0 74.568 0.192 ;
    END
  END di[575]
  PIN di[576]
    DIRECTION INPUT ;
    USE SIGNAL ;
    PORT
      LAYER M3 ;
        RECT  74.664 0 74.682 0.144 ;
    END
  END di[576]
  PIN di[577]
    DIRECTION INPUT ;
    USE SIGNAL ;
    PORT
      LAYER M5 ;
        RECT  74.784 0 74.808 0.192 ;
    END
  END di[577]
  PIN di[578]
    DIRECTION INPUT ;
    USE SIGNAL ;
    PORT
      LAYER M3 ;
        RECT  74.916 0 74.934 0.144 ;
    END
  END di[578]
  PIN di[579]
    DIRECTION INPUT ;
    USE SIGNAL ;
    PORT
      LAYER M5 ;
        RECT  75.024 0 75.048 0.192 ;
    END
  END di[579]
  PIN di[57]
    DIRECTION INPUT ;
    USE SIGNAL ;
    PORT
      LAYER M5 ;
        RECT  11.328 0 11.352 0.192 ;
    END
  END di[57]
  PIN di[580]
    DIRECTION INPUT ;
    USE SIGNAL ;
    PORT
      LAYER M3 ;
        RECT  75.168 0 75.186 0.144 ;
    END
  END di[580]
  PIN di[581]
    DIRECTION INPUT ;
    USE SIGNAL ;
    PORT
      LAYER M5 ;
        RECT  75.264 0 75.288 0.192 ;
    END
  END di[581]
  PIN di[582]
    DIRECTION INPUT ;
    USE SIGNAL ;
    PORT
      LAYER M3 ;
        RECT  75.42 0 75.438 0.144 ;
    END
  END di[582]
  PIN di[583]
    DIRECTION INPUT ;
    USE SIGNAL ;
    PORT
      LAYER M5 ;
        RECT  75.504 0 75.528 0.192 ;
    END
  END di[583]
  PIN di[584]
    DIRECTION INPUT ;
    USE SIGNAL ;
    PORT
      LAYER M3 ;
        RECT  75.636 0 75.654 0.144 ;
    END
  END di[584]
  PIN di[585]
    DIRECTION INPUT ;
    USE SIGNAL ;
    PORT
      LAYER M5 ;
        RECT  75.792 0 75.816 0.192 ;
    END
  END di[585]
  PIN di[586]
    DIRECTION INPUT ;
    USE SIGNAL ;
    PORT
      LAYER M3 ;
        RECT  75.888 0 75.906 0.144 ;
    END
  END di[586]
  PIN di[587]
    DIRECTION INPUT ;
    USE SIGNAL ;
    PORT
      LAYER M5 ;
        RECT  76.032 0 76.056 0.192 ;
    END
    PORT
      LAYER M5 ;
        RECT  75.888 0.133 76.2 0.144 ;
    END
  END di[587]
  PIN di[588]
    DIRECTION INPUT ;
    USE SIGNAL ;
    PORT
      LAYER M3 ;
        RECT  76.14 0 76.158 0.144 ;
    END
  END di[588]
  PIN di[589]
    DIRECTION INPUT ;
    USE SIGNAL ;
    PORT
      LAYER M5 ;
        RECT  76.272 0 76.296 0.192 ;
    END
  END di[589]
  PIN di[58]
    DIRECTION INPUT ;
    USE SIGNAL ;
    PORT
      LAYER M3 ;
        RECT  11.448 0 11.466 0.144 ;
    END
  END di[58]
  PIN di[590]
    DIRECTION INPUT ;
    USE SIGNAL ;
    PORT
      LAYER M3 ;
        RECT  76.392 0 76.41 0.144 ;
    END
  END di[590]
  PIN di[591]
    DIRECTION INPUT ;
    USE SIGNAL ;
    PORT
      LAYER M5 ;
        RECT  76.512 0 76.536 0.192 ;
    END
  END di[591]
  PIN di[592]
    DIRECTION INPUT ;
    USE SIGNAL ;
    PORT
      LAYER M3 ;
        RECT  76.608 0 76.626 0.144 ;
    END
  END di[592]
  PIN di[593]
    DIRECTION INPUT ;
    USE SIGNAL ;
    PORT
      LAYER M5 ;
        RECT  76.752 0 76.776 0.192 ;
    END
  END di[593]
  PIN di[594]
    DIRECTION INPUT ;
    USE SIGNAL ;
    PORT
      LAYER M3 ;
        RECT  76.86 0 76.878 0.144 ;
    END
  END di[594]
  PIN di[595]
    DIRECTION INPUT ;
    USE SIGNAL ;
    PORT
      LAYER M5 ;
        RECT  76.992 0 77.016 0.192 ;
    END
  END di[595]
  PIN di[596]
    DIRECTION INPUT ;
    USE SIGNAL ;
    PORT
      LAYER M3 ;
        RECT  77.112 0 77.13 0.144 ;
    END
  END di[596]
  PIN di[597]
    DIRECTION INPUT ;
    USE SIGNAL ;
    PORT
      LAYER M5 ;
        RECT  77.232 0 77.256 0.192 ;
    END
  END di[597]
  PIN di[598]
    DIRECTION INPUT ;
    USE SIGNAL ;
    PORT
      LAYER M3 ;
        RECT  77.364 0 77.382 0.144 ;
    END
  END di[598]
  PIN di[599]
    DIRECTION INPUT ;
    USE SIGNAL ;
    PORT
      LAYER M5 ;
        RECT  77.472 0 77.496 0.192 ;
    END
  END di[599]
  PIN di[59]
    DIRECTION INPUT ;
    USE SIGNAL ;
    PORT
      LAYER M5 ;
        RECT  11.568 0 11.592 0.192 ;
    END
  END di[59]
  PIN di[5]
    DIRECTION INPUT ;
    USE SIGNAL ;
    PORT
      LAYER M5 ;
        RECT  4.992 0 5.016 0.192 ;
    END
  END di[5]
  PIN di[600]
    DIRECTION INPUT ;
    USE SIGNAL ;
    PORT
      LAYER M3 ;
        RECT  77.616 0 77.634 0.144 ;
    END
  END di[600]
  PIN di[601]
    DIRECTION INPUT ;
    USE SIGNAL ;
    PORT
      LAYER M5 ;
        RECT  77.712 0 77.736 0.192 ;
    END
  END di[601]
  PIN di[602]
    DIRECTION INPUT ;
    USE SIGNAL ;
    PORT
      LAYER M3 ;
        RECT  77.832 0 77.85 0.144 ;
    END
  END di[602]
  PIN di[603]
    DIRECTION INPUT ;
    USE SIGNAL ;
    PORT
      LAYER M5 ;
        RECT  77.952 0 77.976 0.192 ;
    END
  END di[603]
  PIN di[604]
    DIRECTION INPUT ;
    USE SIGNAL ;
    PORT
      LAYER M3 ;
        RECT  78.084 0 78.102 0.144 ;
    END
  END di[604]
  PIN di[605]
    DIRECTION INPUT ;
    USE SIGNAL ;
    PORT
      LAYER M5 ;
        RECT  78.192 0 78.216 0.192 ;
    END
  END di[605]
  PIN di[606]
    DIRECTION INPUT ;
    USE SIGNAL ;
    PORT
      LAYER M3 ;
        RECT  78.336 0 78.354 0.144 ;
    END
  END di[606]
  PIN di[607]
    DIRECTION INPUT ;
    USE SIGNAL ;
    PORT
      LAYER M5 ;
        RECT  78.432 0 78.456 0.192 ;
    END
  END di[607]
  PIN di[608]
    DIRECTION INPUT ;
    USE SIGNAL ;
    PORT
      LAYER M3 ;
        RECT  78.588 0 78.606 0.144 ;
    END
  END di[608]
  PIN di[609]
    DIRECTION INPUT ;
    USE SIGNAL ;
    PORT
      LAYER M5 ;
        RECT  78.72 0 78.744 0.192 ;
    END
  END di[609]
  PIN di[60]
    DIRECTION INPUT ;
    USE SIGNAL ;
    PORT
      LAYER M3 ;
        RECT  11.7 0 11.718 0.144 ;
    END
  END di[60]
  PIN di[610]
    DIRECTION INPUT ;
    USE SIGNAL ;
    PORT
      LAYER M3 ;
        RECT  78.84 0 78.858 0.144 ;
    END
  END di[610]
  PIN di[611]
    DIRECTION INPUT ;
    USE SIGNAL ;
    PORT
      LAYER M5 ;
        RECT  78.96 0 78.984 0.192 ;
    END
  END di[611]
  PIN di[612]
    DIRECTION INPUT ;
    USE SIGNAL ;
    PORT
      LAYER M3 ;
        RECT  79.056 0 79.074 0.144 ;
    END
  END di[612]
  PIN di[613]
    DIRECTION INPUT ;
    USE SIGNAL ;
    PORT
      LAYER M5 ;
        RECT  79.2 0 79.224 0.192 ;
    END
  END di[613]
  PIN di[614]
    DIRECTION INPUT ;
    USE SIGNAL ;
    PORT
      LAYER M3 ;
        RECT  79.308 0 79.326 0.144 ;
    END
  END di[614]
  PIN di[615]
    DIRECTION INPUT ;
    USE SIGNAL ;
    PORT
      LAYER M5 ;
        RECT  79.44 0 79.464 0.192 ;
    END
  END di[615]
  PIN di[616]
    DIRECTION INPUT ;
    USE SIGNAL ;
    PORT
      LAYER M3 ;
        RECT  79.56 0 79.578 0.144 ;
    END
  END di[616]
  PIN di[617]
    DIRECTION INPUT ;
    USE SIGNAL ;
    PORT
      LAYER M5 ;
        RECT  79.68 0 79.704 0.192 ;
    END
  END di[617]
  PIN di[618]
    DIRECTION INPUT ;
    USE SIGNAL ;
    PORT
      LAYER M3 ;
        RECT  79.812 0 79.83 0.144 ;
    END
  END di[618]
  PIN di[619]
    DIRECTION INPUT ;
    USE SIGNAL ;
    PORT
      LAYER M5 ;
        RECT  79.92 0 79.944 0.192 ;
    END
  END di[619]
  PIN di[61]
    DIRECTION INPUT ;
    USE SIGNAL ;
    PORT
      LAYER M5 ;
        RECT  11.808 0 11.832 0.192 ;
    END
  END di[61]
  PIN di[620]
    DIRECTION INPUT ;
    USE SIGNAL ;
    PORT
      LAYER M3 ;
        RECT  80.028 0 80.046 0.144 ;
    END
  END di[620]
  PIN di[621]
    DIRECTION INPUT ;
    USE SIGNAL ;
    PORT
      LAYER M5 ;
        RECT  80.16 0 80.184 0.192 ;
    END
  END di[621]
  PIN di[622]
    DIRECTION INPUT ;
    USE SIGNAL ;
    PORT
      LAYER M3 ;
        RECT  80.28 0 80.298 0.144 ;
    END
  END di[622]
  PIN di[623]
    DIRECTION INPUT ;
    USE SIGNAL ;
    PORT
      LAYER M5 ;
        RECT  80.4 0 80.424 0.192 ;
    END
  END di[623]
  PIN di[624]
    DIRECTION INPUT ;
    USE SIGNAL ;
    PORT
      LAYER M3 ;
        RECT  80.532 0 80.55 0.144 ;
    END
  END di[624]
  PIN di[625]
    DIRECTION INPUT ;
    USE SIGNAL ;
    PORT
      LAYER M5 ;
        RECT  80.64 0 80.664 0.192 ;
    END
  END di[625]
  PIN di[626]
    DIRECTION INPUT ;
    USE SIGNAL ;
    PORT
      LAYER M3 ;
        RECT  80.784 0 80.802 0.144 ;
    END
  END di[626]
  PIN di[627]
    DIRECTION INPUT ;
    USE SIGNAL ;
    PORT
      LAYER M5 ;
        RECT  80.88 0 80.904 0.192 ;
    END
  END di[627]
  PIN di[628]
    DIRECTION INPUT ;
    USE SIGNAL ;
    PORT
      LAYER M3 ;
        RECT  81.036 0 81.054 0.144 ;
    END
  END di[628]
  PIN di[629]
    DIRECTION INPUT ;
    USE SIGNAL ;
    PORT
      LAYER M5 ;
        RECT  81.12 0 81.144 0.192 ;
    END
  END di[629]
  PIN di[62]
    DIRECTION INPUT ;
    USE SIGNAL ;
    PORT
      LAYER M3 ;
        RECT  11.952 0 11.97 0.144 ;
    END
  END di[62]
  PIN di[630]
    DIRECTION INPUT ;
    USE SIGNAL ;
    PORT
      LAYER M3 ;
        RECT  81.252 0 81.27 0.144 ;
    END
  END di[630]
  PIN di[631]
    DIRECTION INPUT ;
    USE SIGNAL ;
    PORT
      LAYER M5 ;
        RECT  81.36 0 81.384 0.192 ;
    END
  END di[631]
  PIN di[632]
    DIRECTION INPUT ;
    USE SIGNAL ;
    PORT
      LAYER M3 ;
        RECT  81.504 0 81.522 0.144 ;
    END
  END di[632]
  PIN di[633]
    DIRECTION INPUT ;
    USE SIGNAL ;
    PORT
      LAYER M5 ;
        RECT  81.648 0 81.672 0.192 ;
    END
  END di[633]
  PIN di[634]
    DIRECTION INPUT ;
    USE SIGNAL ;
    PORT
      LAYER M3 ;
        RECT  81.756 0 81.774 0.144 ;
    END
  END di[634]
  PIN di[635]
    DIRECTION INPUT ;
    USE SIGNAL ;
    PORT
      LAYER M5 ;
        RECT  81.888 0 81.912 0.192 ;
    END
  END di[635]
  PIN di[636]
    DIRECTION INPUT ;
    USE SIGNAL ;
    PORT
      LAYER M3 ;
        RECT  82.008 0 82.026 0.144 ;
    END
  END di[636]
  PIN di[637]
    DIRECTION INPUT ;
    USE SIGNAL ;
    PORT
      LAYER M5 ;
        RECT  82.128 0 82.152 0.192 ;
    END
  END di[637]
  PIN di[638]
    DIRECTION INPUT ;
    USE SIGNAL ;
    PORT
      LAYER M3 ;
        RECT  82.224 0 82.242 0.144 ;
    END
  END di[638]
  PIN di[639]
    DIRECTION INPUT ;
    USE SIGNAL ;
    PORT
      LAYER M5 ;
        RECT  82.368 0 82.392 0.192 ;
    END
  END di[639]
  PIN di[63]
    DIRECTION INPUT ;
    USE SIGNAL ;
    PORT
      LAYER M5 ;
        RECT  12.048 0 12.072 0.192 ;
    END
  END di[63]
  PIN di[640]
    DIRECTION INPUT ;
    USE SIGNAL ;
    PORT
      LAYER M3 ;
        RECT  82.476 0 82.494 0.144 ;
    END
  END di[640]
  PIN di[641]
    DIRECTION INPUT ;
    USE SIGNAL ;
    PORT
      LAYER M5 ;
        RECT  82.608 0 82.632 0.192 ;
    END
  END di[641]
  PIN di[642]
    DIRECTION INPUT ;
    USE SIGNAL ;
    PORT
      LAYER M3 ;
        RECT  82.728 0 82.746 0.144 ;
    END
  END di[642]
  PIN di[643]
    DIRECTION INPUT ;
    USE SIGNAL ;
    PORT
      LAYER M5 ;
        RECT  82.848 0 82.872 0.192 ;
    END
  END di[643]
  PIN di[644]
    DIRECTION INPUT ;
    USE SIGNAL ;
    PORT
      LAYER M3 ;
        RECT  82.98 0 82.998 0.144 ;
    END
  END di[644]
  PIN di[645]
    DIRECTION INPUT ;
    USE SIGNAL ;
    PORT
      LAYER M5 ;
        RECT  83.088 0 83.112 0.192 ;
    END
  END di[645]
  PIN di[646]
    DIRECTION INPUT ;
    USE SIGNAL ;
    PORT
      LAYER M3 ;
        RECT  83.232 0 83.25 0.144 ;
    END
  END di[646]
  PIN di[647]
    DIRECTION INPUT ;
    USE SIGNAL ;
    PORT
      LAYER M5 ;
        RECT  83.328 0 83.352 0.192 ;
    END
  END di[647]
  PIN di[648]
    DIRECTION INPUT ;
    USE SIGNAL ;
    PORT
      LAYER M3 ;
        RECT  83.448 0 83.466 0.144 ;
    END
  END di[648]
  PIN di[649]
    DIRECTION INPUT ;
    USE SIGNAL ;
    PORT
      LAYER M5 ;
        RECT  83.568 0 83.592 0.192 ;
    END
  END di[649]
  PIN di[64]
    DIRECTION INPUT ;
    USE SIGNAL ;
    PORT
      LAYER M3 ;
        RECT  12.168 0 12.186 0.144 ;
    END
  END di[64]
  PIN di[650]
    DIRECTION INPUT ;
    USE SIGNAL ;
    PORT
      LAYER M3 ;
        RECT  83.7 0 83.718 0.144 ;
    END
  END di[650]
  PIN di[651]
    DIRECTION INPUT ;
    USE SIGNAL ;
    PORT
      LAYER M5 ;
        RECT  83.808 0 83.832 0.192 ;
    END
  END di[651]
  PIN di[652]
    DIRECTION INPUT ;
    USE SIGNAL ;
    PORT
      LAYER M3 ;
        RECT  83.952 0 83.97 0.144 ;
    END
  END di[652]
  PIN di[653]
    DIRECTION INPUT ;
    USE SIGNAL ;
    PORT
      LAYER M5 ;
        RECT  84.048 0 84.072 0.192 ;
    END
  END di[653]
  PIN di[654]
    DIRECTION INPUT ;
    USE SIGNAL ;
    PORT
      LAYER M3 ;
        RECT  84.204 0 84.222 0.144 ;
    END
  END di[654]
  PIN di[655]
    DIRECTION INPUT ;
    USE SIGNAL ;
    PORT
      LAYER M5 ;
        RECT  84.288 0 84.312 0.192 ;
    END
  END di[655]
  PIN di[656]
    DIRECTION INPUT ;
    USE SIGNAL ;
    PORT
      LAYER M3 ;
        RECT  84.42 0 84.438 0.144 ;
    END
  END di[656]
  PIN di[657]
    DIRECTION INPUT ;
    USE SIGNAL ;
    PORT
      LAYER M5 ;
        RECT  84.576 0 84.6 0.192 ;
    END
  END di[657]
  PIN di[658]
    DIRECTION INPUT ;
    USE SIGNAL ;
    PORT
      LAYER M3 ;
        RECT  84.672 0 84.69 0.144 ;
    END
  END di[658]
  PIN di[659]
    DIRECTION INPUT ;
    USE SIGNAL ;
    PORT
      LAYER M5 ;
        RECT  84.816 0 84.84 0.192 ;
    END
  END di[659]
  PIN di[65]
    DIRECTION INPUT ;
    USE SIGNAL ;
    PORT
      LAYER M5 ;
        RECT  12.288 0 12.312 0.192 ;
    END
  END di[65]
  PIN di[660]
    DIRECTION INPUT ;
    USE SIGNAL ;
    PORT
      LAYER M3 ;
        RECT  84.924 0 84.942 0.144 ;
    END
  END di[660]
  PIN di[661]
    DIRECTION INPUT ;
    USE SIGNAL ;
    PORT
      LAYER M5 ;
        RECT  85.056 0 85.08 0.192 ;
    END
  END di[661]
  PIN di[662]
    DIRECTION INPUT ;
    USE SIGNAL ;
    PORT
      LAYER M3 ;
        RECT  85.176 0 85.194 0.144 ;
    END
  END di[662]
  PIN di[663]
    DIRECTION INPUT ;
    USE SIGNAL ;
    PORT
      LAYER M5 ;
        RECT  85.296 0 85.32 0.192 ;
    END
  END di[663]
  PIN di[664]
    DIRECTION INPUT ;
    USE SIGNAL ;
    PORT
      LAYER M3 ;
        RECT  85.428 0 85.446 0.144 ;
    END
  END di[664]
  PIN di[665]
    DIRECTION INPUT ;
    USE SIGNAL ;
    PORT
      LAYER M5 ;
        RECT  85.536 0 85.56 0.192 ;
    END
  END di[665]
  PIN di[666]
    DIRECTION INPUT ;
    USE SIGNAL ;
    PORT
      LAYER M3 ;
        RECT  85.644 0 85.662 0.144 ;
    END
  END di[666]
  PIN di[667]
    DIRECTION INPUT ;
    USE SIGNAL ;
    PORT
      LAYER M5 ;
        RECT  85.776 0 85.8 0.192 ;
    END
  END di[667]
  PIN di[668]
    DIRECTION INPUT ;
    USE SIGNAL ;
    PORT
      LAYER M3 ;
        RECT  85.896 0 85.914 0.144 ;
    END
  END di[668]
  PIN di[669]
    DIRECTION INPUT ;
    USE SIGNAL ;
    PORT
      LAYER M5 ;
        RECT  86.016 0 86.04 0.192 ;
    END
  END di[669]
  PIN di[66]
    DIRECTION INPUT ;
    USE SIGNAL ;
    PORT
      LAYER M3 ;
        RECT  12.42 0 12.438 0.144 ;
    END
  END di[66]
  PIN di[670]
    DIRECTION INPUT ;
    USE SIGNAL ;
    PORT
      LAYER M3 ;
        RECT  86.148 0 86.166 0.144 ;
    END
  END di[670]
  PIN di[671]
    DIRECTION INPUT ;
    USE SIGNAL ;
    PORT
      LAYER M5 ;
        RECT  86.256 0 86.28 0.192 ;
    END
  END di[671]
  PIN di[672]
    DIRECTION INPUT ;
    USE SIGNAL ;
    PORT
      LAYER M3 ;
        RECT  86.4 0 86.418 0.144 ;
    END
  END di[672]
  PIN di[673]
    DIRECTION INPUT ;
    USE SIGNAL ;
    PORT
      LAYER M5 ;
        RECT  86.496 0 86.52 0.192 ;
    END
  END di[673]
  PIN di[674]
    DIRECTION INPUT ;
    USE SIGNAL ;
    PORT
      LAYER M3 ;
        RECT  86.616 0 86.634 0.144 ;
    END
  END di[674]
  PIN di[675]
    DIRECTION INPUT ;
    USE SIGNAL ;
    PORT
      LAYER M5 ;
        RECT  86.736 0 86.76 0.192 ;
    END
  END di[675]
  PIN di[676]
    DIRECTION INPUT ;
    USE SIGNAL ;
    PORT
      LAYER M3 ;
        RECT  86.868 0 86.886 0.144 ;
    END
  END di[676]
  PIN di[677]
    DIRECTION INPUT ;
    USE SIGNAL ;
    PORT
      LAYER M5 ;
        RECT  86.976 0 87 0.192 ;
    END
  END di[677]
  PIN di[678]
    DIRECTION INPUT ;
    USE SIGNAL ;
    PORT
      LAYER M3 ;
        RECT  87.12 0 87.138 0.144 ;
    END
  END di[678]
  PIN di[679]
    DIRECTION INPUT ;
    USE SIGNAL ;
    PORT
      LAYER M5 ;
        RECT  87.264 0 87.288 0.192 ;
    END
  END di[679]
  PIN di[67]
    DIRECTION INPUT ;
    USE SIGNAL ;
    PORT
      LAYER M5 ;
        RECT  12.528 0 12.552 0.192 ;
    END
  END di[67]
  PIN di[680]
    DIRECTION INPUT ;
    USE SIGNAL ;
    PORT
      LAYER M3 ;
        RECT  87.372 0 87.39 0.144 ;
    END
  END di[680]
  PIN di[681]
    DIRECTION INPUT ;
    USE SIGNAL ;
    PORT
      LAYER M5 ;
        RECT  87.504 0 87.528 0.192 ;
    END
  END di[681]
  PIN di[682]
    DIRECTION INPUT ;
    USE SIGNAL ;
    PORT
      LAYER M3 ;
        RECT  87.624 0 87.642 0.144 ;
    END
  END di[682]
  PIN di[683]
    DIRECTION INPUT ;
    USE SIGNAL ;
    PORT
      LAYER M5 ;
        RECT  87.744 0 87.768 0.192 ;
    END
  END di[683]
  PIN di[684]
    DIRECTION INPUT ;
    USE SIGNAL ;
    PORT
      LAYER M3 ;
        RECT  87.84 0 87.858 0.144 ;
    END
  END di[684]
  PIN di[685]
    DIRECTION INPUT ;
    USE SIGNAL ;
    PORT
      LAYER M5 ;
        RECT  87.984 0 88.008 0.192 ;
    END
  END di[685]
  PIN di[686]
    DIRECTION INPUT ;
    USE SIGNAL ;
    PORT
      LAYER M3 ;
        RECT  88.092 0 88.11 0.144 ;
    END
  END di[686]
  PIN di[687]
    DIRECTION INPUT ;
    USE SIGNAL ;
    PORT
      LAYER M5 ;
        RECT  88.224 0 88.248 0.192 ;
    END
  END di[687]
  PIN di[688]
    DIRECTION INPUT ;
    USE SIGNAL ;
    PORT
      LAYER M3 ;
        RECT  88.344 0 88.362 0.144 ;
    END
  END di[688]
  PIN di[689]
    DIRECTION INPUT ;
    USE SIGNAL ;
    PORT
      LAYER M5 ;
        RECT  88.464 0 88.488 0.192 ;
    END
  END di[689]
  PIN di[68]
    DIRECTION INPUT ;
    USE SIGNAL ;
    PORT
      LAYER M3 ;
        RECT  12.672 0 12.69 0.144 ;
    END
  END di[68]
  PIN di[690]
    DIRECTION INPUT ;
    USE SIGNAL ;
    PORT
      LAYER M3 ;
        RECT  88.596 0 88.614 0.144 ;
    END
  END di[690]
  PIN di[691]
    DIRECTION INPUT ;
    USE SIGNAL ;
    PORT
      LAYER M5 ;
        RECT  88.704 0 88.728 0.192 ;
    END
  END di[691]
  PIN di[692]
    DIRECTION INPUT ;
    USE SIGNAL ;
    PORT
      LAYER M3 ;
        RECT  88.848 0 88.866 0.144 ;
    END
  END di[692]
  PIN di[693]
    DIRECTION INPUT ;
    USE SIGNAL ;
    PORT
      LAYER M5 ;
        RECT  88.944 0 88.968 0.192 ;
    END
  END di[693]
  PIN di[694]
    DIRECTION INPUT ;
    USE SIGNAL ;
    PORT
      LAYER M3 ;
        RECT  89.064 0 89.082 0.144 ;
    END
  END di[694]
  PIN di[695]
    DIRECTION INPUT ;
    USE SIGNAL ;
    PORT
      LAYER M5 ;
        RECT  89.184 0 89.208 0.192 ;
    END
  END di[695]
  PIN di[696]
    DIRECTION INPUT ;
    USE SIGNAL ;
    PORT
      LAYER M3 ;
        RECT  89.316 0 89.334 0.144 ;
    END
  END di[696]
  PIN di[697]
    DIRECTION INPUT ;
    USE SIGNAL ;
    PORT
      LAYER M5 ;
        RECT  89.424 0 89.448 0.192 ;
    END
  END di[697]
  PIN di[698]
    DIRECTION INPUT ;
    USE SIGNAL ;
    PORT
      LAYER M3 ;
        RECT  89.568 0 89.586 0.144 ;
    END
  END di[698]
  PIN di[699]
    DIRECTION INPUT ;
    USE SIGNAL ;
    PORT
      LAYER M5 ;
        RECT  89.664 0 89.688 0.192 ;
    END
  END di[699]
  PIN di[69]
    DIRECTION INPUT ;
    USE SIGNAL ;
    PORT
      LAYER M5 ;
        RECT  12.768 0 12.792 0.192 ;
    END
  END di[69]
  PIN di[6]
    DIRECTION INPUT ;
    USE SIGNAL ;
    PORT
      LAYER M3 ;
        RECT  5.112 0 5.13 0.144 ;
    END
  END di[6]
  PIN di[700]
    DIRECTION INPUT ;
    USE SIGNAL ;
    PORT
      LAYER M3 ;
        RECT  89.82 0 89.838 0.144 ;
    END
  END di[700]
  PIN di[701]
    DIRECTION INPUT ;
    USE SIGNAL ;
    PORT
      LAYER M5 ;
        RECT  89.904 0 89.928 0.192 ;
    END
  END di[701]
  PIN di[702]
    DIRECTION INPUT ;
    USE SIGNAL ;
    PORT
      LAYER M3 ;
        RECT  90.036 0 90.054 0.144 ;
    END
  END di[702]
  PIN di[703]
    DIRECTION INPUT ;
    USE SIGNAL ;
    PORT
      LAYER M5 ;
        RECT  90.192 0 90.216 0.192 ;
    END
  END di[703]
  PIN di[704]
    DIRECTION INPUT ;
    USE SIGNAL ;
    PORT
      LAYER M3 ;
        RECT  90.288 0 90.306 0.144 ;
    END
  END di[704]
  PIN di[705]
    DIRECTION INPUT ;
    USE SIGNAL ;
    PORT
      LAYER M5 ;
        RECT  90.432 0 90.456 0.192 ;
    END
  END di[705]
  PIN di[706]
    DIRECTION INPUT ;
    USE SIGNAL ;
    PORT
      LAYER M3 ;
        RECT  90.54 0 90.558 0.144 ;
    END
  END di[706]
  PIN di[707]
    DIRECTION INPUT ;
    USE SIGNAL ;
    PORT
      LAYER M5 ;
        RECT  90.672 0 90.696 0.192 ;
    END
  END di[707]
  PIN di[708]
    DIRECTION INPUT ;
    USE SIGNAL ;
    PORT
      LAYER M3 ;
        RECT  90.792 0 90.81 0.144 ;
    END
  END di[708]
  PIN di[709]
    DIRECTION INPUT ;
    USE SIGNAL ;
    PORT
      LAYER M5 ;
        RECT  90.912 0 90.936 0.192 ;
    END
  END di[709]
  PIN di[70]
    DIRECTION INPUT ;
    USE SIGNAL ;
    PORT
      LAYER M3 ;
        RECT  12.924 0 12.942 0.144 ;
    END
  END di[70]
  PIN di[710]
    DIRECTION INPUT ;
    USE SIGNAL ;
    PORT
      LAYER M3 ;
        RECT  91.044 0 91.062 0.144 ;
    END
  END di[710]
  PIN di[711]
    DIRECTION INPUT ;
    USE SIGNAL ;
    PORT
      LAYER M5 ;
        RECT  91.152 0 91.176 0.192 ;
    END
  END di[711]
  PIN di[712]
    DIRECTION INPUT ;
    USE SIGNAL ;
    PORT
      LAYER M3 ;
        RECT  91.26 0 91.278 0.144 ;
    END
  END di[712]
  PIN di[713]
    DIRECTION INPUT ;
    USE SIGNAL ;
    PORT
      LAYER M5 ;
        RECT  91.392 0 91.416 0.192 ;
    END
  END di[713]
  PIN di[714]
    DIRECTION INPUT ;
    USE SIGNAL ;
    PORT
      LAYER M3 ;
        RECT  91.512 0 91.53 0.144 ;
    END
  END di[714]
  PIN di[715]
    DIRECTION INPUT ;
    USE SIGNAL ;
    PORT
      LAYER M5 ;
        RECT  91.632 0 91.656 0.192 ;
    END
  END di[715]
  PIN di[716]
    DIRECTION INPUT ;
    USE SIGNAL ;
    PORT
      LAYER M3 ;
        RECT  91.764 0 91.782 0.144 ;
    END
  END di[716]
  PIN di[717]
    DIRECTION INPUT ;
    USE SIGNAL ;
    PORT
      LAYER M5 ;
        RECT  91.872 0 91.896 0.192 ;
    END
  END di[717]
  PIN di[718]
    DIRECTION INPUT ;
    USE SIGNAL ;
    PORT
      LAYER M3 ;
        RECT  92.016 0 92.034 0.144 ;
    END
  END di[718]
  PIN di[719]
    DIRECTION INPUT ;
    USE SIGNAL ;
    PORT
      LAYER M5 ;
        RECT  92.112 0 92.136 0.192 ;
    END
  END di[719]
  PIN di[71]
    DIRECTION INPUT ;
    USE SIGNAL ;
    PORT
      LAYER M5 ;
        RECT  13.056 0 13.08 0.192 ;
    END
  END di[71]
  PIN di[720]
    DIRECTION INPUT ;
    USE SIGNAL ;
    PORT
      LAYER M3 ;
        RECT  92.232 0 92.25 0.144 ;
    END
  END di[720]
  PIN di[721]
    DIRECTION INPUT ;
    USE SIGNAL ;
    PORT
      LAYER M5 ;
        RECT  92.352 0 92.376 0.192 ;
    END
  END di[721]
  PIN di[722]
    DIRECTION INPUT ;
    USE SIGNAL ;
    PORT
      LAYER M3 ;
        RECT  92.484 0 92.502 0.144 ;
    END
  END di[722]
  PIN di[723]
    DIRECTION INPUT ;
    USE SIGNAL ;
    PORT
      LAYER M5 ;
        RECT  92.592 0 92.616 0.192 ;
    END
  END di[723]
  PIN di[724]
    DIRECTION INPUT ;
    USE SIGNAL ;
    PORT
      LAYER M3 ;
        RECT  92.736 0 92.754 0.144 ;
    END
  END di[724]
  PIN di[725]
    DIRECTION INPUT ;
    USE SIGNAL ;
    PORT
      LAYER M5 ;
        RECT  92.832 0 92.856 0.192 ;
    END
  END di[725]
  PIN di[726]
    DIRECTION INPUT ;
    USE SIGNAL ;
    PORT
      LAYER M3 ;
        RECT  92.988 0 93.006 0.144 ;
    END
  END di[726]
  PIN di[727]
    DIRECTION INPUT ;
    USE SIGNAL ;
    PORT
      LAYER M5 ;
        RECT  93.12 0 93.144 0.192 ;
    END
  END di[727]
  PIN di[728]
    DIRECTION INPUT ;
    USE SIGNAL ;
    PORT
      LAYER M3 ;
        RECT  93.24 0 93.258 0.144 ;
    END
  END di[728]
  PIN di[729]
    DIRECTION INPUT ;
    USE SIGNAL ;
    PORT
      LAYER M5 ;
        RECT  93.36 0 93.384 0.192 ;
    END
  END di[729]
  PIN di[72]
    DIRECTION INPUT ;
    USE SIGNAL ;
    PORT
      LAYER M3 ;
        RECT  13.176 0 13.194 0.144 ;
    END
  END di[72]
  PIN di[730]
    DIRECTION INPUT ;
    USE SIGNAL ;
    PORT
      LAYER M3 ;
        RECT  93.456 0 93.474 0.144 ;
    END
  END di[730]
  PIN di[731]
    DIRECTION INPUT ;
    USE SIGNAL ;
    PORT
      LAYER M5 ;
        RECT  93.6 0 93.624 0.192 ;
    END
  END di[731]
  PIN di[732]
    DIRECTION INPUT ;
    USE SIGNAL ;
    PORT
      LAYER M3 ;
        RECT  93.708 0 93.726 0.144 ;
    END
  END di[732]
  PIN di[733]
    DIRECTION INPUT ;
    USE SIGNAL ;
    PORT
      LAYER M5 ;
        RECT  93.84 0 93.864 0.192 ;
    END
  END di[733]
  PIN di[734]
    DIRECTION INPUT ;
    USE SIGNAL ;
    PORT
      LAYER M3 ;
        RECT  93.96 0 93.978 0.144 ;
    END
  END di[734]
  PIN di[735]
    DIRECTION INPUT ;
    USE SIGNAL ;
    PORT
      LAYER M5 ;
        RECT  94.08 0 94.104 0.192 ;
    END
  END di[735]
  PIN di[736]
    DIRECTION INPUT ;
    USE SIGNAL ;
    PORT
      LAYER M3 ;
        RECT  94.212 0 94.23 0.144 ;
    END
  END di[736]
  PIN di[737]
    DIRECTION INPUT ;
    USE SIGNAL ;
    PORT
      LAYER M5 ;
        RECT  94.32 0 94.344 0.192 ;
    END
  END di[737]
  PIN di[738]
    DIRECTION INPUT ;
    USE SIGNAL ;
    PORT
      LAYER M3 ;
        RECT  94.428 0 94.446 0.144 ;
    END
  END di[738]
  PIN di[739]
    DIRECTION INPUT ;
    USE SIGNAL ;
    PORT
      LAYER M5 ;
        RECT  94.56 0 94.584 0.192 ;
    END
  END di[739]
  PIN di[73]
    DIRECTION INPUT ;
    USE SIGNAL ;
    PORT
      LAYER M5 ;
        RECT  13.296 0 13.32 0.192 ;
    END
  END di[73]
  PIN di[740]
    DIRECTION INPUT ;
    USE SIGNAL ;
    PORT
      LAYER M3 ;
        RECT  94.68 0 94.698 0.144 ;
    END
  END di[740]
  PIN di[741]
    DIRECTION INPUT ;
    USE SIGNAL ;
    PORT
      LAYER M5 ;
        RECT  94.8 0 94.824 0.192 ;
    END
  END di[741]
  PIN di[742]
    DIRECTION INPUT ;
    USE SIGNAL ;
    PORT
      LAYER M3 ;
        RECT  94.932 0 94.95 0.144 ;
    END
  END di[742]
  PIN di[743]
    DIRECTION INPUT ;
    USE SIGNAL ;
    PORT
      LAYER M5 ;
        RECT  95.04 0 95.064 0.192 ;
    END
  END di[743]
  PIN di[744]
    DIRECTION INPUT ;
    USE SIGNAL ;
    PORT
      LAYER M3 ;
        RECT  95.184 0 95.202 0.144 ;
    END
  END di[744]
  PIN di[745]
    DIRECTION INPUT ;
    USE SIGNAL ;
    PORT
      LAYER M5 ;
        RECT  95.28 0 95.304 0.192 ;
    END
  END di[745]
  PIN di[746]
    DIRECTION INPUT ;
    USE SIGNAL ;
    PORT
      LAYER M3 ;
        RECT  95.436 0 95.454 0.144 ;
    END
  END di[746]
  PIN di[747]
    DIRECTION INPUT ;
    USE SIGNAL ;
    PORT
      LAYER M5 ;
        RECT  95.52 0 95.544 0.192 ;
    END
  END di[747]
  PIN di[748]
    DIRECTION INPUT ;
    USE SIGNAL ;
    PORT
      LAYER M3 ;
        RECT  95.652 0 95.67 0.144 ;
    END
  END di[748]
  PIN di[749]
    DIRECTION INPUT ;
    USE SIGNAL ;
    PORT
      LAYER M5 ;
        RECT  95.808 0 95.832 0.192 ;
    END
  END di[749]
  PIN di[74]
    DIRECTION INPUT ;
    USE SIGNAL ;
    PORT
      LAYER M3 ;
        RECT  13.392 0 13.41 0.144 ;
    END
  END di[74]
  PIN di[750]
    DIRECTION INPUT ;
    USE SIGNAL ;
    PORT
      LAYER M3 ;
        RECT  95.904 0 95.922 0.144 ;
    END
  END di[750]
  PIN di[751]
    DIRECTION INPUT ;
    USE SIGNAL ;
    PORT
      LAYER M5 ;
        RECT  96.048 0 96.072 0.192 ;
    END
  END di[751]
  PIN di[752]
    DIRECTION INPUT ;
    USE SIGNAL ;
    PORT
      LAYER M3 ;
        RECT  96.156 0 96.174 0.144 ;
    END
  END di[752]
  PIN di[753]
    DIRECTION INPUT ;
    USE SIGNAL ;
    PORT
      LAYER M5 ;
        RECT  96.288 0 96.312 0.192 ;
    END
  END di[753]
  PIN di[754]
    DIRECTION INPUT ;
    USE SIGNAL ;
    PORT
      LAYER M3 ;
        RECT  96.408 0 96.426 0.144 ;
    END
  END di[754]
  PIN di[755]
    DIRECTION INPUT ;
    USE SIGNAL ;
    PORT
      LAYER M5 ;
        RECT  96.528 0 96.552 0.192 ;
    END
  END di[755]
  PIN di[756]
    DIRECTION INPUT ;
    USE SIGNAL ;
    PORT
      LAYER M3 ;
        RECT  96.624 0 96.642 0.144 ;
    END
  END di[756]
  PIN di[757]
    DIRECTION INPUT ;
    USE SIGNAL ;
    PORT
      LAYER M5 ;
        RECT  96.768 0 96.792 0.192 ;
    END
  END di[757]
  PIN di[758]
    DIRECTION INPUT ;
    USE SIGNAL ;
    PORT
      LAYER M3 ;
        RECT  96.876 0 96.894 0.144 ;
    END
  END di[758]
  PIN di[759]
    DIRECTION INPUT ;
    USE SIGNAL ;
    PORT
      LAYER M5 ;
        RECT  97.008 0 97.032 0.192 ;
    END
  END di[759]
  PIN di[75]
    DIRECTION INPUT ;
    USE SIGNAL ;
    PORT
      LAYER M5 ;
        RECT  13.536 0 13.56 0.192 ;
    END
  END di[75]
  PIN di[760]
    DIRECTION INPUT ;
    USE SIGNAL ;
    PORT
      LAYER M3 ;
        RECT  97.128 0 97.146 0.144 ;
    END
  END di[760]
  PIN di[76]
    DIRECTION INPUT ;
    USE SIGNAL ;
    PORT
      LAYER M3 ;
        RECT  13.644 0 13.662 0.144 ;
    END
  END di[76]
  PIN di[77]
    DIRECTION INPUT ;
    USE SIGNAL ;
    PORT
      LAYER M5 ;
        RECT  13.776 0 13.8 0.192 ;
    END
  END di[77]
  PIN di[78]
    DIRECTION INPUT ;
    USE SIGNAL ;
    PORT
      LAYER M3 ;
        RECT  13.896 0 13.914 0.144 ;
    END
  END di[78]
  PIN di[79]
    DIRECTION INPUT ;
    USE SIGNAL ;
    PORT
      LAYER M5 ;
        RECT  14.016 0 14.04 0.192 ;
    END
  END di[79]
  PIN di[7]
    DIRECTION INPUT ;
    USE SIGNAL ;
    PORT
      LAYER M5 ;
        RECT  5.232 0 5.256 0.192 ;
    END
  END di[7]
  PIN di[80]
    DIRECTION INPUT ;
    USE SIGNAL ;
    PORT
      LAYER M3 ;
        RECT  14.148 0 14.166 0.144 ;
    END
  END di[80]
  PIN di[81]
    DIRECTION INPUT ;
    USE SIGNAL ;
    PORT
      LAYER M5 ;
        RECT  14.256 0 14.28 0.192 ;
    END
  END di[81]
  PIN di[82]
    DIRECTION INPUT ;
    USE SIGNAL ;
    PORT
      LAYER M3 ;
        RECT  14.364 0 14.382 0.144 ;
    END
  END di[82]
  PIN di[83]
    DIRECTION INPUT ;
    USE SIGNAL ;
    PORT
      LAYER M5 ;
        RECT  14.496 0 14.52 0.192 ;
    END
  END di[83]
  PIN di[84]
    DIRECTION INPUT ;
    USE SIGNAL ;
    PORT
      LAYER M3 ;
        RECT  14.616 0 14.634 0.144 ;
    END
  END di[84]
  PIN di[85]
    DIRECTION INPUT ;
    USE SIGNAL ;
    PORT
      LAYER M5 ;
        RECT  14.736 0 14.76 0.192 ;
    END
  END di[85]
  PIN di[86]
    DIRECTION INPUT ;
    USE SIGNAL ;
    PORT
      LAYER M3 ;
        RECT  14.868 0 14.886 0.144 ;
    END
  END di[86]
  PIN di[87]
    DIRECTION INPUT ;
    USE SIGNAL ;
    PORT
      LAYER M5 ;
        RECT  14.976 0 15 0.192 ;
    END
  END di[87]
  PIN di[88]
    DIRECTION INPUT ;
    USE SIGNAL ;
    PORT
      LAYER M3 ;
        RECT  15.12 0 15.138 0.144 ;
    END
  END di[88]
  PIN di[89]
    DIRECTION INPUT ;
    USE SIGNAL ;
    PORT
      LAYER M5 ;
        RECT  15.216 0 15.24 0.192 ;
    END
  END di[89]
  PIN di[8]
    DIRECTION INPUT ;
    USE SIGNAL ;
    PORT
      LAYER M3 ;
        RECT  5.364 0 5.382 0.144 ;
    END
  END di[8]
  PIN di[90]
    DIRECTION INPUT ;
    USE SIGNAL ;
    PORT
      LAYER M3 ;
        RECT  15.372 0 15.39 0.144 ;
    END
  END di[90]
  PIN di[91]
    DIRECTION INPUT ;
    USE SIGNAL ;
    PORT
      LAYER M5 ;
        RECT  15.456 0 15.48 0.192 ;
    END
  END di[91]
  PIN di[92]
    DIRECTION INPUT ;
    USE SIGNAL ;
    PORT
      LAYER M3 ;
        RECT  15.588 0 15.606 0.144 ;
    END
  END di[92]
  PIN di[93]
    DIRECTION INPUT ;
    USE SIGNAL ;
    PORT
      LAYER M5 ;
        RECT  15.696 0 15.72 0.192 ;
    END
  END di[93]
  PIN di[94]
    DIRECTION INPUT ;
    USE SIGNAL ;
    PORT
      LAYER M3 ;
        RECT  15.84 0 15.858 0.144 ;
    END
  END di[94]
  PIN di[95]
    DIRECTION INPUT ;
    USE SIGNAL ;
    PORT
      LAYER M5 ;
        RECT  15.984 0 16.008 0.192 ;
    END
  END di[95]
  PIN di[96]
    DIRECTION INPUT ;
    USE SIGNAL ;
    PORT
      LAYER M3 ;
        RECT  16.092 0 16.11 0.144 ;
    END
  END di[96]
  PIN di[97]
    DIRECTION INPUT ;
    USE SIGNAL ;
    PORT
      LAYER M5 ;
        RECT  16.224 0 16.248 0.192 ;
    END
  END di[97]
  PIN di[98]
    DIRECTION INPUT ;
    USE SIGNAL ;
    PORT
      LAYER M3 ;
        RECT  16.344 0 16.362 0.144 ;
    END
  END di[98]
  PIN di[99]
    DIRECTION INPUT ;
    USE SIGNAL ;
    PORT
      LAYER M5 ;
        RECT  16.464 0 16.488 0.192 ;
    END
  END di[99]
  PIN di[9]
    DIRECTION INPUT ;
    USE SIGNAL ;
    PORT
      LAYER M5 ;
        RECT  5.472 0 5.496 0.192 ;
    END
  END di[9]
  PIN dq[0]
    DIRECTION OUTPUT ;
    USE SIGNAL ;
    PORT
      LAYER M3 ;
        RECT  4.356 36.576 4.374 36.72 ;
    END
  END dq[0]
  PIN dq[100]
    DIRECTION OUTPUT ;
    USE SIGNAL ;
    PORT
      LAYER M3 ;
        RECT  16.56 36.576 16.578 36.72 ;
    END
  END dq[100]
  PIN dq[101]
    DIRECTION OUTPUT ;
    USE SIGNAL ;
    PORT
      LAYER M5 ;
        RECT  16.704 36.528 16.728 36.72 ;
    END
  END dq[101]
  PIN dq[102]
    DIRECTION OUTPUT ;
    USE SIGNAL ;
    PORT
      LAYER M3 ;
        RECT  16.812 36.576 16.83 36.72 ;
    END
  END dq[102]
  PIN dq[103]
    DIRECTION OUTPUT ;
    USE SIGNAL ;
    PORT
      LAYER M5 ;
        RECT  16.944 36.528 16.968 36.72 ;
    END
  END dq[103]
  PIN dq[104]
    DIRECTION OUTPUT ;
    USE SIGNAL ;
    PORT
      LAYER M3 ;
        RECT  17.064 36.576 17.082 36.72 ;
    END
  END dq[104]
  PIN dq[105]
    DIRECTION OUTPUT ;
    USE SIGNAL ;
    PORT
      LAYER M5 ;
        RECT  17.184 36.528 17.208 36.72 ;
    END
  END dq[105]
  PIN dq[106]
    DIRECTION OUTPUT ;
    USE SIGNAL ;
    PORT
      LAYER M3 ;
        RECT  17.316 36.576 17.334 36.72 ;
    END
  END dq[106]
  PIN dq[107]
    DIRECTION OUTPUT ;
    USE SIGNAL ;
    PORT
      LAYER M5 ;
        RECT  17.424 36.528 17.448 36.72 ;
    END
  END dq[107]
  PIN dq[108]
    DIRECTION OUTPUT ;
    USE SIGNAL ;
    PORT
      LAYER M3 ;
        RECT  17.568 36.576 17.586 36.72 ;
    END
  END dq[108]
  PIN dq[109]
    DIRECTION OUTPUT ;
    USE SIGNAL ;
    PORT
      LAYER M5 ;
        RECT  17.664 36.528 17.688 36.72 ;
    END
  END dq[109]
  PIN dq[10]
    DIRECTION OUTPUT ;
    USE SIGNAL ;
    PORT
      LAYER M3 ;
        RECT  5.58 36.576 5.598 36.72 ;
    END
  END dq[10]
  PIN dq[110]
    DIRECTION OUTPUT ;
    USE SIGNAL ;
    PORT
      LAYER M3 ;
        RECT  17.784 36.576 17.802 36.72 ;
    END
  END dq[110]
  PIN dq[111]
    DIRECTION OUTPUT ;
    USE SIGNAL ;
    PORT
      LAYER M5 ;
        RECT  17.904 36.528 17.928 36.72 ;
    END
  END dq[111]
  PIN dq[112]
    DIRECTION OUTPUT ;
    USE SIGNAL ;
    PORT
      LAYER M3 ;
        RECT  18.036 36.576 18.054 36.72 ;
    END
  END dq[112]
  PIN dq[113]
    DIRECTION OUTPUT ;
    USE SIGNAL ;
    PORT
      LAYER M5 ;
        RECT  18.144 36.528 18.168 36.72 ;
    END
  END dq[113]
  PIN dq[114]
    DIRECTION OUTPUT ;
    USE SIGNAL ;
    PORT
      LAYER M3 ;
        RECT  18.288 36.576 18.306 36.72 ;
    END
  END dq[114]
  PIN dq[115]
    DIRECTION OUTPUT ;
    USE SIGNAL ;
    PORT
      LAYER M5 ;
        RECT  18.384 36.528 18.408 36.72 ;
    END
  END dq[115]
  PIN dq[116]
    DIRECTION OUTPUT ;
    USE SIGNAL ;
    PORT
      LAYER M3 ;
        RECT  18.54 36.576 18.558 36.72 ;
    END
  END dq[116]
  PIN dq[117]
    DIRECTION OUTPUT ;
    USE SIGNAL ;
    PORT
      LAYER M5 ;
        RECT  18.672 36.528 18.696 36.72 ;
    END
  END dq[117]
  PIN dq[118]
    DIRECTION OUTPUT ;
    USE SIGNAL ;
    PORT
      LAYER M3 ;
        RECT  18.756 36.576 18.774 36.72 ;
    END
  END dq[118]
  PIN dq[119]
    DIRECTION OUTPUT ;
    USE SIGNAL ;
    PORT
      LAYER M5 ;
        RECT  18.912 36.528 18.936 36.72 ;
    END
  END dq[119]
  PIN dq[11]
    DIRECTION OUTPUT ;
    USE SIGNAL ;
    PORT
      LAYER M5 ;
        RECT  5.712 36.528 5.736 36.72 ;
    END
  END dq[11]
  PIN dq[120]
    DIRECTION OUTPUT ;
    USE SIGNAL ;
    PORT
      LAYER M3 ;
        RECT  19.008 36.576 19.026 36.72 ;
    END
  END dq[120]
  PIN dq[121]
    DIRECTION OUTPUT ;
    USE SIGNAL ;
    PORT
      LAYER M5 ;
        RECT  19.152 36.528 19.176 36.72 ;
    END
  END dq[121]
  PIN dq[122]
    DIRECTION OUTPUT ;
    USE SIGNAL ;
    PORT
      LAYER M3 ;
        RECT  19.26 36.576 19.278 36.72 ;
    END
  END dq[122]
  PIN dq[123]
    DIRECTION OUTPUT ;
    USE SIGNAL ;
    PORT
      LAYER M5 ;
        RECT  19.392 36.528 19.416 36.72 ;
    END
  END dq[123]
  PIN dq[124]
    DIRECTION OUTPUT ;
    USE SIGNAL ;
    PORT
      LAYER M3 ;
        RECT  19.512 36.576 19.53 36.72 ;
    END
  END dq[124]
  PIN dq[125]
    DIRECTION OUTPUT ;
    USE SIGNAL ;
    PORT
      LAYER M5 ;
        RECT  19.632 36.528 19.656 36.72 ;
    END
  END dq[125]
  PIN dq[126]
    DIRECTION OUTPUT ;
    USE SIGNAL ;
    PORT
      LAYER M3 ;
        RECT  19.764 36.576 19.782 36.72 ;
    END
  END dq[126]
  PIN dq[127]
    DIRECTION OUTPUT ;
    USE SIGNAL ;
    PORT
      LAYER M5 ;
        RECT  19.872 36.528 19.896 36.72 ;
    END
  END dq[127]
  PIN dq[128]
    DIRECTION OUTPUT ;
    USE SIGNAL ;
    PORT
      LAYER M3 ;
        RECT  19.98 36.576 19.998 36.72 ;
    END
  END dq[128]
  PIN dq[129]
    DIRECTION OUTPUT ;
    USE SIGNAL ;
    PORT
      LAYER M5 ;
        RECT  20.112 36.528 20.136 36.72 ;
    END
  END dq[129]
  PIN dq[12]
    DIRECTION OUTPUT ;
    USE SIGNAL ;
    PORT
      LAYER M3 ;
        RECT  5.832 36.576 5.85 36.72 ;
    END
  END dq[12]
  PIN dq[130]
    DIRECTION OUTPUT ;
    USE SIGNAL ;
    PORT
      LAYER M3 ;
        RECT  20.232 36.576 20.25 36.72 ;
    END
  END dq[130]
  PIN dq[131]
    DIRECTION OUTPUT ;
    USE SIGNAL ;
    PORT
      LAYER M5 ;
        RECT  20.352 36.528 20.376 36.72 ;
    END
  END dq[131]
  PIN dq[132]
    DIRECTION OUTPUT ;
    USE SIGNAL ;
    PORT
      LAYER M3 ;
        RECT  20.484 36.576 20.502 36.72 ;
    END
  END dq[132]
  PIN dq[133]
    DIRECTION OUTPUT ;
    USE SIGNAL ;
    PORT
      LAYER M5 ;
        RECT  20.592 36.528 20.616 36.72 ;
    END
  END dq[133]
  PIN dq[134]
    DIRECTION OUTPUT ;
    USE SIGNAL ;
    PORT
      LAYER M3 ;
        RECT  20.736 36.576 20.754 36.72 ;
    END
  END dq[134]
  PIN dq[135]
    DIRECTION OUTPUT ;
    USE SIGNAL ;
    PORT
      LAYER M5 ;
        RECT  20.832 36.528 20.856 36.72 ;
    END
  END dq[135]
  PIN dq[136]
    DIRECTION OUTPUT ;
    USE SIGNAL ;
    PORT
      LAYER M3 ;
        RECT  20.988 36.576 21.006 36.72 ;
    END
  END dq[136]
  PIN dq[137]
    DIRECTION OUTPUT ;
    USE SIGNAL ;
    PORT
      LAYER M5 ;
        RECT  21.072 36.528 21.096 36.72 ;
    END
  END dq[137]
  PIN dq[138]
    DIRECTION OUTPUT ;
    USE SIGNAL ;
    PORT
      LAYER M3 ;
        RECT  21.204 36.576 21.222 36.72 ;
    END
  END dq[138]
  PIN dq[139]
    DIRECTION OUTPUT ;
    USE SIGNAL ;
    PORT
      LAYER M5 ;
        RECT  21.312 36.528 21.336 36.72 ;
    END
  END dq[139]
  PIN dq[13]
    DIRECTION OUTPUT ;
    USE SIGNAL ;
    PORT
      LAYER M5 ;
        RECT  5.952 36.528 5.976 36.72 ;
    END
  END dq[13]
  PIN dq[140]
    DIRECTION OUTPUT ;
    USE SIGNAL ;
    PORT
      LAYER M3 ;
        RECT  21.456 36.576 21.474 36.72 ;
    END
  END dq[140]
  PIN dq[141]
    DIRECTION OUTPUT ;
    USE SIGNAL ;
    PORT
      LAYER M5 ;
        RECT  21.6 36.528 21.624 36.72 ;
    END
  END dq[141]
  PIN dq[142]
    DIRECTION OUTPUT ;
    USE SIGNAL ;
    PORT
      LAYER M3 ;
        RECT  21.708 36.576 21.726 36.72 ;
    END
  END dq[142]
  PIN dq[143]
    DIRECTION OUTPUT ;
    USE SIGNAL ;
    PORT
      LAYER M5 ;
        RECT  21.84 36.528 21.864 36.72 ;
    END
  END dq[143]
  PIN dq[144]
    DIRECTION OUTPUT ;
    USE SIGNAL ;
    PORT
      LAYER M3 ;
        RECT  21.96 36.576 21.978 36.72 ;
    END
  END dq[144]
  PIN dq[145]
    DIRECTION OUTPUT ;
    USE SIGNAL ;
    PORT
      LAYER M5 ;
        RECT  22.08 36.528 22.104 36.72 ;
    END
  END dq[145]
  PIN dq[146]
    DIRECTION OUTPUT ;
    USE SIGNAL ;
    PORT
      LAYER M3 ;
        RECT  22.176 36.576 22.194 36.72 ;
    END
  END dq[146]
  PIN dq[147]
    DIRECTION OUTPUT ;
    USE SIGNAL ;
    PORT
      LAYER M5 ;
        RECT  22.32 36.528 22.344 36.72 ;
    END
  END dq[147]
  PIN dq[148]
    DIRECTION OUTPUT ;
    USE SIGNAL ;
    PORT
      LAYER M3 ;
        RECT  22.428 36.576 22.446 36.72 ;
    END
  END dq[148]
  PIN dq[149]
    DIRECTION OUTPUT ;
    USE SIGNAL ;
    PORT
      LAYER M5 ;
        RECT  22.56 36.528 22.584 36.72 ;
    END
  END dq[149]
  PIN dq[14]
    DIRECTION OUTPUT ;
    USE SIGNAL ;
    PORT
      LAYER M3 ;
        RECT  6.084 36.576 6.102 36.72 ;
    END
  END dq[14]
  PIN dq[150]
    DIRECTION OUTPUT ;
    USE SIGNAL ;
    PORT
      LAYER M3 ;
        RECT  22.68 36.576 22.698 36.72 ;
    END
  END dq[150]
  PIN dq[151]
    DIRECTION OUTPUT ;
    USE SIGNAL ;
    PORT
      LAYER M5 ;
        RECT  22.8 36.528 22.824 36.72 ;
    END
  END dq[151]
  PIN dq[152]
    DIRECTION OUTPUT ;
    USE SIGNAL ;
    PORT
      LAYER M3 ;
        RECT  22.932 36.576 22.95 36.72 ;
    END
  END dq[152]
  PIN dq[153]
    DIRECTION OUTPUT ;
    USE SIGNAL ;
    PORT
      LAYER M5 ;
        RECT  23.04 36.528 23.064 36.72 ;
    END
  END dq[153]
  PIN dq[154]
    DIRECTION OUTPUT ;
    USE SIGNAL ;
    PORT
      LAYER M3 ;
        RECT  23.184 36.576 23.202 36.72 ;
    END
  END dq[154]
  PIN dq[155]
    DIRECTION OUTPUT ;
    USE SIGNAL ;
    PORT
      LAYER M5 ;
        RECT  23.28 36.528 23.304 36.72 ;
    END
  END dq[155]
  PIN dq[156]
    DIRECTION OUTPUT ;
    USE SIGNAL ;
    PORT
      LAYER M3 ;
        RECT  23.4 36.576 23.418 36.72 ;
    END
  END dq[156]
  PIN dq[157]
    DIRECTION OUTPUT ;
    USE SIGNAL ;
    PORT
      LAYER M5 ;
        RECT  23.52 36.528 23.544 36.72 ;
    END
  END dq[157]
  PIN dq[158]
    DIRECTION OUTPUT ;
    USE SIGNAL ;
    PORT
      LAYER M3 ;
        RECT  23.652 36.576 23.67 36.72 ;
    END
  END dq[158]
  PIN dq[159]
    DIRECTION OUTPUT ;
    USE SIGNAL ;
    PORT
      LAYER M5 ;
        RECT  23.76 36.528 23.784 36.72 ;
    END
  END dq[159]
  PIN dq[15]
    DIRECTION OUTPUT ;
    USE SIGNAL ;
    PORT
      LAYER M5 ;
        RECT  6.192 36.528 6.216 36.72 ;
    END
  END dq[15]
  PIN dq[160]
    DIRECTION OUTPUT ;
    USE SIGNAL ;
    PORT
      LAYER M3 ;
        RECT  23.904 36.576 23.922 36.72 ;
    END
  END dq[160]
  PIN dq[161]
    DIRECTION OUTPUT ;
    USE SIGNAL ;
    PORT
      LAYER M5 ;
        RECT  24 36.528 24.024 36.72 ;
    END
  END dq[161]
  PIN dq[162]
    DIRECTION OUTPUT ;
    USE SIGNAL ;
    PORT
      LAYER M3 ;
        RECT  24.156 36.576 24.174 36.72 ;
    END
  END dq[162]
  PIN dq[163]
    DIRECTION OUTPUT ;
    USE SIGNAL ;
    PORT
      LAYER M5 ;
        RECT  24.24 36.528 24.264 36.72 ;
    END
  END dq[163]
  PIN dq[164]
    DIRECTION OUTPUT ;
    USE SIGNAL ;
    PORT
      LAYER M3 ;
        RECT  24.372 36.576 24.39 36.72 ;
    END
  END dq[164]
  PIN dq[165]
    DIRECTION OUTPUT ;
    USE SIGNAL ;
    PORT
      LAYER M5 ;
        RECT  24.528 36.528 24.552 36.72 ;
    END
  END dq[165]
  PIN dq[166]
    DIRECTION OUTPUT ;
    USE SIGNAL ;
    PORT
      LAYER M3 ;
        RECT  24.624 36.576 24.642 36.72 ;
    END
  END dq[166]
  PIN dq[167]
    DIRECTION OUTPUT ;
    USE SIGNAL ;
    PORT
      LAYER M5 ;
        RECT  24.768 36.528 24.792 36.72 ;
    END
  END dq[167]
  PIN dq[168]
    DIRECTION OUTPUT ;
    USE SIGNAL ;
    PORT
      LAYER M3 ;
        RECT  24.876 36.576 24.894 36.72 ;
    END
  END dq[168]
  PIN dq[169]
    DIRECTION OUTPUT ;
    USE SIGNAL ;
    PORT
      LAYER M5 ;
        RECT  25.008 36.528 25.032 36.72 ;
    END
  END dq[169]
  PIN dq[16]
    DIRECTION OUTPUT ;
    USE SIGNAL ;
    PORT
      LAYER M3 ;
        RECT  6.336 36.576 6.354 36.72 ;
    END
  END dq[16]
  PIN dq[170]
    DIRECTION OUTPUT ;
    USE SIGNAL ;
    PORT
      LAYER M3 ;
        RECT  25.128 36.576 25.146 36.72 ;
    END
  END dq[170]
  PIN dq[171]
    DIRECTION OUTPUT ;
    USE SIGNAL ;
    PORT
      LAYER M5 ;
        RECT  25.248 36.528 25.272 36.72 ;
    END
  END dq[171]
  PIN dq[172]
    DIRECTION OUTPUT ;
    USE SIGNAL ;
    PORT
      LAYER M3 ;
        RECT  25.38 36.576 25.398 36.72 ;
    END
  END dq[172]
  PIN dq[173]
    DIRECTION OUTPUT ;
    USE SIGNAL ;
    PORT
      LAYER M5 ;
        RECT  25.488 36.528 25.512 36.72 ;
    END
  END dq[173]
  PIN dq[174]
    DIRECTION OUTPUT ;
    USE SIGNAL ;
    PORT
      LAYER M3 ;
        RECT  25.596 36.576 25.614 36.72 ;
    END
  END dq[174]
  PIN dq[175]
    DIRECTION OUTPUT ;
    USE SIGNAL ;
    PORT
      LAYER M5 ;
        RECT  25.728 36.528 25.752 36.72 ;
    END
  END dq[175]
  PIN dq[176]
    DIRECTION OUTPUT ;
    USE SIGNAL ;
    PORT
      LAYER M3 ;
        RECT  25.848 36.576 25.866 36.72 ;
    END
  END dq[176]
  PIN dq[177]
    DIRECTION OUTPUT ;
    USE SIGNAL ;
    PORT
      LAYER M5 ;
        RECT  25.968 36.528 25.992 36.72 ;
    END
  END dq[177]
  PIN dq[178]
    DIRECTION OUTPUT ;
    USE SIGNAL ;
    PORT
      LAYER M3 ;
        RECT  26.1 36.576 26.118 36.72 ;
    END
  END dq[178]
  PIN dq[179]
    DIRECTION OUTPUT ;
    USE SIGNAL ;
    PORT
      LAYER M5 ;
        RECT  26.208 36.528 26.232 36.72 ;
    END
  END dq[179]
  PIN dq[17]
    DIRECTION OUTPUT ;
    USE SIGNAL ;
    PORT
      LAYER M5 ;
        RECT  6.432 36.528 6.456 36.72 ;
    END
  END dq[17]
  PIN dq[180]
    DIRECTION OUTPUT ;
    USE SIGNAL ;
    PORT
      LAYER M3 ;
        RECT  26.352 36.576 26.37 36.72 ;
    END
  END dq[180]
  PIN dq[181]
    DIRECTION OUTPUT ;
    USE SIGNAL ;
    PORT
      LAYER M5 ;
        RECT  26.448 36.528 26.472 36.72 ;
    END
  END dq[181]
  PIN dq[182]
    DIRECTION OUTPUT ;
    USE SIGNAL ;
    PORT
      LAYER M3 ;
        RECT  26.568 36.576 26.586 36.72 ;
    END
  END dq[182]
  PIN dq[183]
    DIRECTION OUTPUT ;
    USE SIGNAL ;
    PORT
      LAYER M5 ;
        RECT  26.688 36.528 26.712 36.72 ;
    END
  END dq[183]
  PIN dq[184]
    DIRECTION OUTPUT ;
    USE SIGNAL ;
    PORT
      LAYER M3 ;
        RECT  26.82 36.576 26.838 36.72 ;
    END
  END dq[184]
  PIN dq[185]
    DIRECTION OUTPUT ;
    USE SIGNAL ;
    PORT
      LAYER M5 ;
        RECT  26.928 36.528 26.952 36.72 ;
    END
  END dq[185]
  PIN dq[186]
    DIRECTION OUTPUT ;
    USE SIGNAL ;
    PORT
      LAYER M3 ;
        RECT  27.072 36.576 27.09 36.72 ;
    END
  END dq[186]
  PIN dq[187]
    DIRECTION OUTPUT ;
    USE SIGNAL ;
    PORT
      LAYER M5 ;
        RECT  27.216 36.528 27.24 36.72 ;
    END
  END dq[187]
  PIN dq[188]
    DIRECTION OUTPUT ;
    USE SIGNAL ;
    PORT
      LAYER M3 ;
        RECT  27.324 36.576 27.342 36.72 ;
    END
  END dq[188]
  PIN dq[189]
    DIRECTION OUTPUT ;
    USE SIGNAL ;
    PORT
      LAYER M5 ;
        RECT  27.456 36.528 27.48 36.72 ;
    END
  END dq[189]
  PIN dq[18]
    DIRECTION OUTPUT ;
    USE SIGNAL ;
    PORT
      LAYER M3 ;
        RECT  6.552 36.576 6.57 36.72 ;
    END
  END dq[18]
  PIN dq[190]
    DIRECTION OUTPUT ;
    USE SIGNAL ;
    PORT
      LAYER M3 ;
        RECT  27.576 36.576 27.594 36.72 ;
    END
  END dq[190]
  PIN dq[191]
    DIRECTION OUTPUT ;
    USE SIGNAL ;
    PORT
      LAYER M5 ;
        RECT  27.696 36.528 27.72 36.72 ;
    END
  END dq[191]
  PIN dq[192]
    DIRECTION OUTPUT ;
    USE SIGNAL ;
    PORT
      LAYER M3 ;
        RECT  27.792 36.576 27.81 36.72 ;
    END
  END dq[192]
  PIN dq[193]
    DIRECTION OUTPUT ;
    USE SIGNAL ;
    PORT
      LAYER M5 ;
        RECT  27.936 36.528 27.96 36.72 ;
    END
  END dq[193]
  PIN dq[194]
    DIRECTION OUTPUT ;
    USE SIGNAL ;
    PORT
      LAYER M3 ;
        RECT  28.044 36.576 28.062 36.72 ;
    END
  END dq[194]
  PIN dq[195]
    DIRECTION OUTPUT ;
    USE SIGNAL ;
    PORT
      LAYER M5 ;
        RECT  28.176 36.528 28.2 36.72 ;
    END
  END dq[195]
  PIN dq[196]
    DIRECTION OUTPUT ;
    USE SIGNAL ;
    PORT
      LAYER M3 ;
        RECT  28.296 36.576 28.314 36.72 ;
    END
  END dq[196]
  PIN dq[197]
    DIRECTION OUTPUT ;
    USE SIGNAL ;
    PORT
      LAYER M5 ;
        RECT  28.416 36.528 28.44 36.72 ;
    END
  END dq[197]
  PIN dq[198]
    DIRECTION OUTPUT ;
    USE SIGNAL ;
    PORT
      LAYER M3 ;
        RECT  28.548 36.576 28.566 36.72 ;
    END
  END dq[198]
  PIN dq[199]
    DIRECTION OUTPUT ;
    USE SIGNAL ;
    PORT
      LAYER M5 ;
        RECT  28.656 36.528 28.68 36.72 ;
    END
  END dq[199]
  PIN dq[19]
    DIRECTION OUTPUT ;
    USE SIGNAL ;
    PORT
      LAYER M5 ;
        RECT  6.672 36.528 6.696 36.72 ;
    END
  END dq[19]
  PIN dq[1]
    DIRECTION OUTPUT ;
    USE SIGNAL ;
    PORT
      LAYER M5 ;
        RECT  4.512 36.528 4.536 36.72 ;
    END
  END dq[1]
  PIN dq[200]
    DIRECTION OUTPUT ;
    USE SIGNAL ;
    PORT
      LAYER M3 ;
        RECT  28.8 36.576 28.818 36.72 ;
    END
  END dq[200]
  PIN dq[201]
    DIRECTION OUTPUT ;
    USE SIGNAL ;
    PORT
      LAYER M5 ;
        RECT  28.896 36.528 28.92 36.72 ;
    END
  END dq[201]
  PIN dq[202]
    DIRECTION OUTPUT ;
    USE SIGNAL ;
    PORT
      LAYER M3 ;
        RECT  29.016 36.576 29.034 36.72 ;
    END
  END dq[202]
  PIN dq[203]
    DIRECTION OUTPUT ;
    USE SIGNAL ;
    PORT
      LAYER M5 ;
        RECT  29.136 36.528 29.16 36.72 ;
    END
  END dq[203]
  PIN dq[204]
    DIRECTION OUTPUT ;
    USE SIGNAL ;
    PORT
      LAYER M3 ;
        RECT  29.268 36.576 29.286 36.72 ;
    END
  END dq[204]
  PIN dq[205]
    DIRECTION OUTPUT ;
    USE SIGNAL ;
    PORT
      LAYER M5 ;
        RECT  29.376 36.528 29.4 36.72 ;
    END
  END dq[205]
  PIN dq[206]
    DIRECTION OUTPUT ;
    USE SIGNAL ;
    PORT
      LAYER M3 ;
        RECT  29.52 36.576 29.538 36.72 ;
    END
  END dq[206]
  PIN dq[207]
    DIRECTION OUTPUT ;
    USE SIGNAL ;
    PORT
      LAYER M5 ;
        RECT  29.616 36.528 29.64 36.72 ;
    END
  END dq[207]
  PIN dq[208]
    DIRECTION OUTPUT ;
    USE SIGNAL ;
    PORT
      LAYER M3 ;
        RECT  29.772 36.576 29.79 36.72 ;
    END
  END dq[208]
  PIN dq[209]
    DIRECTION OUTPUT ;
    USE SIGNAL ;
    PORT
      LAYER M5 ;
        RECT  29.856 36.528 29.88 36.72 ;
    END
  END dq[209]
  PIN dq[20]
    DIRECTION OUTPUT ;
    USE SIGNAL ;
    PORT
      LAYER M3 ;
        RECT  6.804 36.576 6.822 36.72 ;
    END
  END dq[20]
  PIN dq[210]
    DIRECTION OUTPUT ;
    USE SIGNAL ;
    PORT
      LAYER M3 ;
        RECT  29.988 36.576 30.006 36.72 ;
    END
  END dq[210]
  PIN dq[211]
    DIRECTION OUTPUT ;
    USE SIGNAL ;
    PORT
      LAYER M5 ;
        RECT  30.144 36.528 30.168 36.72 ;
    END
  END dq[211]
  PIN dq[212]
    DIRECTION OUTPUT ;
    USE SIGNAL ;
    PORT
      LAYER M3 ;
        RECT  30.24 36.576 30.258 36.72 ;
    END
  END dq[212]
  PIN dq[213]
    DIRECTION OUTPUT ;
    USE SIGNAL ;
    PORT
      LAYER M5 ;
        RECT  30.384 36.528 30.408 36.72 ;
    END
  END dq[213]
  PIN dq[214]
    DIRECTION OUTPUT ;
    USE SIGNAL ;
    PORT
      LAYER M3 ;
        RECT  30.492 36.576 30.51 36.72 ;
    END
  END dq[214]
  PIN dq[215]
    DIRECTION OUTPUT ;
    USE SIGNAL ;
    PORT
      LAYER M5 ;
        RECT  30.624 36.528 30.648 36.72 ;
    END
  END dq[215]
  PIN dq[216]
    DIRECTION OUTPUT ;
    USE SIGNAL ;
    PORT
      LAYER M3 ;
        RECT  30.744 36.576 30.762 36.72 ;
    END
  END dq[216]
  PIN dq[217]
    DIRECTION OUTPUT ;
    USE SIGNAL ;
    PORT
      LAYER M5 ;
        RECT  30.864 36.528 30.888 36.72 ;
    END
  END dq[217]
  PIN dq[218]
    DIRECTION OUTPUT ;
    USE SIGNAL ;
    PORT
      LAYER M3 ;
        RECT  30.996 36.576 31.014 36.72 ;
    END
  END dq[218]
  PIN dq[219]
    DIRECTION OUTPUT ;
    USE SIGNAL ;
    PORT
      LAYER M5 ;
        RECT  31.104 36.528 31.128 36.72 ;
    END
  END dq[219]
  PIN dq[21]
    DIRECTION OUTPUT ;
    USE SIGNAL ;
    PORT
      LAYER M5 ;
        RECT  6.912 36.528 6.936 36.72 ;
    END
  END dq[21]
  PIN dq[220]
    DIRECTION OUTPUT ;
    USE SIGNAL ;
    PORT
      LAYER M3 ;
        RECT  31.212 36.576 31.23 36.72 ;
    END
  END dq[220]
  PIN dq[221]
    DIRECTION OUTPUT ;
    USE SIGNAL ;
    PORT
      LAYER M5 ;
        RECT  31.344 36.528 31.368 36.72 ;
    END
  END dq[221]
  PIN dq[222]
    DIRECTION OUTPUT ;
    USE SIGNAL ;
    PORT
      LAYER M3 ;
        RECT  31.464 36.576 31.482 36.72 ;
    END
  END dq[222]
  PIN dq[223]
    DIRECTION OUTPUT ;
    USE SIGNAL ;
    PORT
      LAYER M5 ;
        RECT  31.584 36.528 31.608 36.72 ;
    END
  END dq[223]
  PIN dq[224]
    DIRECTION OUTPUT ;
    USE SIGNAL ;
    PORT
      LAYER M3 ;
        RECT  31.716 36.576 31.734 36.72 ;
    END
  END dq[224]
  PIN dq[225]
    DIRECTION OUTPUT ;
    USE SIGNAL ;
    PORT
      LAYER M5 ;
        RECT  31.824 36.528 31.848 36.72 ;
    END
  END dq[225]
  PIN dq[226]
    DIRECTION OUTPUT ;
    USE SIGNAL ;
    PORT
      LAYER M3 ;
        RECT  31.968 36.576 31.986 36.72 ;
    END
  END dq[226]
  PIN dq[227]
    DIRECTION OUTPUT ;
    USE SIGNAL ;
    PORT
      LAYER M5 ;
        RECT  32.064 36.528 32.088 36.72 ;
    END
  END dq[227]
  PIN dq[228]
    DIRECTION OUTPUT ;
    USE SIGNAL ;
    PORT
      LAYER M3 ;
        RECT  32.184 36.576 32.202 36.72 ;
    END
  END dq[228]
  PIN dq[229]
    DIRECTION OUTPUT ;
    USE SIGNAL ;
    PORT
      LAYER M5 ;
        RECT  32.304 36.528 32.328 36.72 ;
    END
  END dq[229]
  PIN dq[22]
    DIRECTION OUTPUT ;
    USE SIGNAL ;
    PORT
      LAYER M3 ;
        RECT  7.056 36.576 7.074 36.72 ;
    END
  END dq[22]
  PIN dq[230]
    DIRECTION OUTPUT ;
    USE SIGNAL ;
    PORT
      LAYER M3 ;
        RECT  32.436 36.576 32.454 36.72 ;
    END
  END dq[230]
  PIN dq[231]
    DIRECTION OUTPUT ;
    USE SIGNAL ;
    PORT
      LAYER M5 ;
        RECT  32.544 36.528 32.568 36.72 ;
    END
  END dq[231]
  PIN dq[232]
    DIRECTION OUTPUT ;
    USE SIGNAL ;
    PORT
      LAYER M3 ;
        RECT  32.688 36.576 32.706 36.72 ;
    END
  END dq[232]
  PIN dq[233]
    DIRECTION OUTPUT ;
    USE SIGNAL ;
    PORT
      LAYER M5 ;
        RECT  32.784 36.528 32.808 36.72 ;
    END
  END dq[233]
  PIN dq[234]
    DIRECTION OUTPUT ;
    USE SIGNAL ;
    PORT
      LAYER M3 ;
        RECT  32.94 36.576 32.958 36.72 ;
    END
  END dq[234]
  PIN dq[235]
    DIRECTION OUTPUT ;
    USE SIGNAL ;
    PORT
      LAYER M5 ;
        RECT  33.072 36.528 33.096 36.72 ;
    END
  END dq[235]
  PIN dq[236]
    DIRECTION OUTPUT ;
    USE SIGNAL ;
    PORT
      LAYER M3 ;
        RECT  33.192 36.576 33.21 36.72 ;
    END
  END dq[236]
  PIN dq[237]
    DIRECTION OUTPUT ;
    USE SIGNAL ;
    PORT
      LAYER M5 ;
        RECT  33.312 36.528 33.336 36.72 ;
    END
  END dq[237]
  PIN dq[238]
    DIRECTION OUTPUT ;
    USE SIGNAL ;
    PORT
      LAYER M3 ;
        RECT  33.408 36.576 33.426 36.72 ;
    END
  END dq[238]
  PIN dq[239]
    DIRECTION OUTPUT ;
    USE SIGNAL ;
    PORT
      LAYER M5 ;
        RECT  33.552 36.528 33.576 36.72 ;
    END
  END dq[239]
  PIN dq[23]
    DIRECTION OUTPUT ;
    USE SIGNAL ;
    PORT
      LAYER M5 ;
        RECT  7.2 36.528 7.224 36.72 ;
    END
  END dq[23]
  PIN dq[240]
    DIRECTION OUTPUT ;
    USE SIGNAL ;
    PORT
      LAYER M3 ;
        RECT  33.66 36.576 33.678 36.72 ;
    END
  END dq[240]
  PIN dq[241]
    DIRECTION OUTPUT ;
    USE SIGNAL ;
    PORT
      LAYER M5 ;
        RECT  33.792 36.528 33.816 36.72 ;
    END
  END dq[241]
  PIN dq[242]
    DIRECTION OUTPUT ;
    USE SIGNAL ;
    PORT
      LAYER M3 ;
        RECT  33.912 36.576 33.93 36.72 ;
    END
  END dq[242]
  PIN dq[243]
    DIRECTION OUTPUT ;
    USE SIGNAL ;
    PORT
      LAYER M5 ;
        RECT  34.032 36.528 34.056 36.72 ;
    END
  END dq[243]
  PIN dq[244]
    DIRECTION OUTPUT ;
    USE SIGNAL ;
    PORT
      LAYER M3 ;
        RECT  34.164 36.576 34.182 36.72 ;
    END
  END dq[244]
  PIN dq[245]
    DIRECTION OUTPUT ;
    USE SIGNAL ;
    PORT
      LAYER M5 ;
        RECT  34.272 36.528 34.296 36.72 ;
    END
  END dq[245]
  PIN dq[246]
    DIRECTION OUTPUT ;
    USE SIGNAL ;
    PORT
      LAYER M3 ;
        RECT  34.38 36.576 34.398 36.72 ;
    END
  END dq[246]
  PIN dq[247]
    DIRECTION OUTPUT ;
    USE SIGNAL ;
    PORT
      LAYER M5 ;
        RECT  34.512 36.528 34.536 36.72 ;
    END
  END dq[247]
  PIN dq[248]
    DIRECTION OUTPUT ;
    USE SIGNAL ;
    PORT
      LAYER M3 ;
        RECT  34.632 36.576 34.65 36.72 ;
    END
  END dq[248]
  PIN dq[249]
    DIRECTION OUTPUT ;
    USE SIGNAL ;
    PORT
      LAYER M5 ;
        RECT  34.752 36.528 34.776 36.72 ;
    END
  END dq[249]
  PIN dq[24]
    DIRECTION OUTPUT ;
    USE SIGNAL ;
    PORT
      LAYER M3 ;
        RECT  7.308 36.576 7.326 36.72 ;
    END
  END dq[24]
  PIN dq[250]
    DIRECTION OUTPUT ;
    USE SIGNAL ;
    PORT
      LAYER M3 ;
        RECT  34.884 36.576 34.902 36.72 ;
    END
  END dq[250]
  PIN dq[251]
    DIRECTION OUTPUT ;
    USE SIGNAL ;
    PORT
      LAYER M5 ;
        RECT  34.992 36.528 35.016 36.72 ;
    END
  END dq[251]
  PIN dq[252]
    DIRECTION OUTPUT ;
    USE SIGNAL ;
    PORT
      LAYER M3 ;
        RECT  35.136 36.576 35.154 36.72 ;
    END
  END dq[252]
  PIN dq[253]
    DIRECTION OUTPUT ;
    USE SIGNAL ;
    PORT
      LAYER M5 ;
        RECT  35.232 36.528 35.256 36.72 ;
    END
  END dq[253]
  PIN dq[254]
    DIRECTION OUTPUT ;
    USE SIGNAL ;
    PORT
      LAYER M3 ;
        RECT  35.388 36.576 35.406 36.72 ;
    END
  END dq[254]
  PIN dq[255]
    DIRECTION OUTPUT ;
    USE SIGNAL ;
    PORT
      LAYER M5 ;
        RECT  35.472 36.528 35.496 36.72 ;
    END
  END dq[255]
  PIN dq[256]
    DIRECTION OUTPUT ;
    USE SIGNAL ;
    PORT
      LAYER M3 ;
        RECT  35.604 36.576 35.622 36.72 ;
    END
  END dq[256]
  PIN dq[257]
    DIRECTION OUTPUT ;
    USE SIGNAL ;
    PORT
      LAYER M5 ;
        RECT  35.712 36.528 35.736 36.72 ;
    END
  END dq[257]
  PIN dq[258]
    DIRECTION OUTPUT ;
    USE SIGNAL ;
    PORT
      LAYER M3 ;
        RECT  35.856 36.576 35.874 36.72 ;
    END
  END dq[258]
  PIN dq[259]
    DIRECTION OUTPUT ;
    USE SIGNAL ;
    PORT
      LAYER M5 ;
        RECT  36 36.528 36.024 36.72 ;
    END
  END dq[259]
  PIN dq[25]
    DIRECTION OUTPUT ;
    USE SIGNAL ;
    PORT
      LAYER M5 ;
        RECT  7.44 36.528 7.464 36.72 ;
    END
  END dq[25]
  PIN dq[260]
    DIRECTION OUTPUT ;
    USE SIGNAL ;
    PORT
      LAYER M3 ;
        RECT  36.108 36.576 36.126 36.72 ;
    END
  END dq[260]
  PIN dq[261]
    DIRECTION OUTPUT ;
    USE SIGNAL ;
    PORT
      LAYER M5 ;
        RECT  36.24 36.528 36.264 36.72 ;
    END
  END dq[261]
  PIN dq[262]
    DIRECTION OUTPUT ;
    USE SIGNAL ;
    PORT
      LAYER M3 ;
        RECT  36.36 36.576 36.378 36.72 ;
    END
  END dq[262]
  PIN dq[263]
    DIRECTION OUTPUT ;
    USE SIGNAL ;
    PORT
      LAYER M5 ;
        RECT  36.48 36.528 36.504 36.72 ;
    END
  END dq[263]
  PIN dq[264]
    DIRECTION OUTPUT ;
    USE SIGNAL ;
    PORT
      LAYER M3 ;
        RECT  36.576 36.576 36.594 36.72 ;
    END
  END dq[264]
  PIN dq[265]
    DIRECTION OUTPUT ;
    USE SIGNAL ;
    PORT
      LAYER M5 ;
        RECT  36.72 36.528 36.744 36.72 ;
    END
  END dq[265]
  PIN dq[266]
    DIRECTION OUTPUT ;
    USE SIGNAL ;
    PORT
      LAYER M3 ;
        RECT  36.828 36.576 36.846 36.72 ;
    END
  END dq[266]
  PIN dq[267]
    DIRECTION OUTPUT ;
    USE SIGNAL ;
    PORT
      LAYER M5 ;
        RECT  36.96 36.528 36.984 36.72 ;
    END
  END dq[267]
  PIN dq[268]
    DIRECTION OUTPUT ;
    USE SIGNAL ;
    PORT
      LAYER M3 ;
        RECT  37.08 36.576 37.098 36.72 ;
    END
  END dq[268]
  PIN dq[269]
    DIRECTION OUTPUT ;
    USE SIGNAL ;
    PORT
      LAYER M5 ;
        RECT  37.2 36.528 37.224 36.72 ;
    END
  END dq[269]
  PIN dq[26]
    DIRECTION OUTPUT ;
    USE SIGNAL ;
    PORT
      LAYER M3 ;
        RECT  7.56 36.576 7.578 36.72 ;
    END
  END dq[26]
  PIN dq[270]
    DIRECTION OUTPUT ;
    USE SIGNAL ;
    PORT
      LAYER M3 ;
        RECT  37.332 36.576 37.35 36.72 ;
    END
  END dq[270]
  PIN dq[271]
    DIRECTION OUTPUT ;
    USE SIGNAL ;
    PORT
      LAYER M5 ;
        RECT  37.44 36.528 37.464 36.72 ;
    END
  END dq[271]
  PIN dq[272]
    DIRECTION OUTPUT ;
    USE SIGNAL ;
    PORT
      LAYER M3 ;
        RECT  37.584 36.576 37.602 36.72 ;
    END
  END dq[272]
  PIN dq[273]
    DIRECTION OUTPUT ;
    USE SIGNAL ;
    PORT
      LAYER M5 ;
        RECT  37.68 36.528 37.704 36.72 ;
    END
  END dq[273]
  PIN dq[274]
    DIRECTION OUTPUT ;
    USE SIGNAL ;
    PORT
      LAYER M3 ;
        RECT  37.8 36.576 37.818 36.72 ;
    END
  END dq[274]
  PIN dq[275]
    DIRECTION OUTPUT ;
    USE SIGNAL ;
    PORT
      LAYER M5 ;
        RECT  37.92 36.528 37.944 36.72 ;
    END
  END dq[275]
  PIN dq[276]
    DIRECTION OUTPUT ;
    USE SIGNAL ;
    PORT
      LAYER M3 ;
        RECT  38.052 36.576 38.07 36.72 ;
    END
  END dq[276]
  PIN dq[277]
    DIRECTION OUTPUT ;
    USE SIGNAL ;
    PORT
      LAYER M5 ;
        RECT  38.16 36.528 38.184 36.72 ;
    END
  END dq[277]
  PIN dq[278]
    DIRECTION OUTPUT ;
    USE SIGNAL ;
    PORT
      LAYER M3 ;
        RECT  38.304 36.576 38.322 36.72 ;
    END
  END dq[278]
  PIN dq[279]
    DIRECTION OUTPUT ;
    USE SIGNAL ;
    PORT
      LAYER M5 ;
        RECT  38.4 36.528 38.424 36.72 ;
    END
  END dq[279]
  PIN dq[27]
    DIRECTION OUTPUT ;
    USE SIGNAL ;
    PORT
      LAYER M5 ;
        RECT  7.68 36.528 7.704 36.72 ;
    END
  END dq[27]
  PIN dq[280]
    DIRECTION OUTPUT ;
    USE SIGNAL ;
    PORT
      LAYER M3 ;
        RECT  38.556 36.576 38.574 36.72 ;
    END
  END dq[280]
  PIN dq[281]
    DIRECTION OUTPUT ;
    USE SIGNAL ;
    PORT
      LAYER M5 ;
        RECT  38.688 36.528 38.712 36.72 ;
    END
  END dq[281]
  PIN dq[282]
    DIRECTION OUTPUT ;
    USE SIGNAL ;
    PORT
      LAYER M3 ;
        RECT  38.808 36.576 38.826 36.72 ;
    END
  END dq[282]
  PIN dq[283]
    DIRECTION OUTPUT ;
    USE SIGNAL ;
    PORT
      LAYER M5 ;
        RECT  38.928 36.528 38.952 36.72 ;
    END
  END dq[283]
  PIN dq[284]
    DIRECTION OUTPUT ;
    USE SIGNAL ;
    PORT
      LAYER M3 ;
        RECT  39.024 36.576 39.042 36.72 ;
    END
  END dq[284]
  PIN dq[285]
    DIRECTION OUTPUT ;
    USE SIGNAL ;
    PORT
      LAYER M5 ;
        RECT  39.168 36.528 39.192 36.72 ;
    END
  END dq[285]
  PIN dq[286]
    DIRECTION OUTPUT ;
    USE SIGNAL ;
    PORT
      LAYER M3 ;
        RECT  39.276 36.576 39.294 36.72 ;
    END
  END dq[286]
  PIN dq[287]
    DIRECTION OUTPUT ;
    USE SIGNAL ;
    PORT
      LAYER M5 ;
        RECT  39.408 36.528 39.432 36.72 ;
    END
  END dq[287]
  PIN dq[288]
    DIRECTION OUTPUT ;
    USE SIGNAL ;
    PORT
      LAYER M3 ;
        RECT  39.528 36.576 39.546 36.72 ;
    END
  END dq[288]
  PIN dq[289]
    DIRECTION OUTPUT ;
    USE SIGNAL ;
    PORT
      LAYER M5 ;
        RECT  39.648 36.528 39.672 36.72 ;
    END
  END dq[289]
  PIN dq[28]
    DIRECTION OUTPUT ;
    USE SIGNAL ;
    PORT
      LAYER M3 ;
        RECT  7.776 36.576 7.794 36.72 ;
    END
  END dq[28]
  PIN dq[290]
    DIRECTION OUTPUT ;
    USE SIGNAL ;
    PORT
      LAYER M3 ;
        RECT  39.78 36.576 39.798 36.72 ;
    END
  END dq[290]
  PIN dq[291]
    DIRECTION OUTPUT ;
    USE SIGNAL ;
    PORT
      LAYER M5 ;
        RECT  39.888 36.528 39.912 36.72 ;
    END
  END dq[291]
  PIN dq[292]
    DIRECTION OUTPUT ;
    USE SIGNAL ;
    PORT
      LAYER M3 ;
        RECT  39.996 36.576 40.014 36.72 ;
    END
  END dq[292]
  PIN dq[293]
    DIRECTION OUTPUT ;
    USE SIGNAL ;
    PORT
      LAYER M5 ;
        RECT  40.128 36.528 40.152 36.72 ;
    END
  END dq[293]
  PIN dq[294]
    DIRECTION OUTPUT ;
    USE SIGNAL ;
    PORT
      LAYER M3 ;
        RECT  40.248 36.576 40.266 36.72 ;
    END
  END dq[294]
  PIN dq[295]
    DIRECTION OUTPUT ;
    USE SIGNAL ;
    PORT
      LAYER M5 ;
        RECT  40.368 36.528 40.392 36.72 ;
    END
  END dq[295]
  PIN dq[296]
    DIRECTION OUTPUT ;
    USE SIGNAL ;
    PORT
      LAYER M3 ;
        RECT  40.5 36.576 40.518 36.72 ;
    END
  END dq[296]
  PIN dq[297]
    DIRECTION OUTPUT ;
    USE SIGNAL ;
    PORT
      LAYER M5 ;
        RECT  40.608 36.528 40.632 36.72 ;
    END
  END dq[297]
  PIN dq[298]
    DIRECTION OUTPUT ;
    USE SIGNAL ;
    PORT
      LAYER M3 ;
        RECT  40.752 36.576 40.77 36.72 ;
    END
  END dq[298]
  PIN dq[299]
    DIRECTION OUTPUT ;
    USE SIGNAL ;
    PORT
      LAYER M5 ;
        RECT  40.848 36.528 40.872 36.72 ;
    END
  END dq[299]
  PIN dq[29]
    DIRECTION OUTPUT ;
    USE SIGNAL ;
    PORT
      LAYER M5 ;
        RECT  7.92 36.528 7.944 36.72 ;
    END
  END dq[29]
  PIN dq[2]
    DIRECTION OUTPUT ;
    USE SIGNAL ;
    PORT
      LAYER M3 ;
        RECT  4.608 36.576 4.626 36.72 ;
    END
  END dq[2]
  PIN dq[300]
    DIRECTION OUTPUT ;
    USE SIGNAL ;
    PORT
      LAYER M3 ;
        RECT  41.004 36.576 41.022 36.72 ;
    END
  END dq[300]
  PIN dq[301]
    DIRECTION OUTPUT ;
    USE SIGNAL ;
    PORT
      LAYER M5 ;
        RECT  41.088 36.528 41.112 36.72 ;
    END
  END dq[301]
  PIN dq[302]
    DIRECTION OUTPUT ;
    USE SIGNAL ;
    PORT
      LAYER M3 ;
        RECT  41.22 36.576 41.238 36.72 ;
    END
  END dq[302]
  PIN dq[303]
    DIRECTION OUTPUT ;
    USE SIGNAL ;
    PORT
      LAYER M5 ;
        RECT  41.328 36.528 41.352 36.72 ;
    END
  END dq[303]
  PIN dq[304]
    DIRECTION OUTPUT ;
    USE SIGNAL ;
    PORT
      LAYER M3 ;
        RECT  41.472 36.576 41.49 36.72 ;
    END
  END dq[304]
  PIN dq[305]
    DIRECTION OUTPUT ;
    USE SIGNAL ;
    PORT
      LAYER M5 ;
        RECT  41.616 36.528 41.64 36.72 ;
    END
  END dq[305]
  PIN dq[306]
    DIRECTION OUTPUT ;
    USE SIGNAL ;
    PORT
      LAYER M3 ;
        RECT  41.724 36.576 41.742 36.72 ;
    END
  END dq[306]
  PIN dq[307]
    DIRECTION OUTPUT ;
    USE SIGNAL ;
    PORT
      LAYER M5 ;
        RECT  41.856 36.528 41.88 36.72 ;
    END
  END dq[307]
  PIN dq[308]
    DIRECTION OUTPUT ;
    USE SIGNAL ;
    PORT
      LAYER M3 ;
        RECT  41.976 36.576 41.994 36.72 ;
    END
  END dq[308]
  PIN dq[309]
    DIRECTION OUTPUT ;
    USE SIGNAL ;
    PORT
      LAYER M5 ;
        RECT  42.096 36.528 42.12 36.72 ;
    END
  END dq[309]
  PIN dq[30]
    DIRECTION OUTPUT ;
    USE SIGNAL ;
    PORT
      LAYER M3 ;
        RECT  8.028 36.576 8.046 36.72 ;
    END
  END dq[30]
  PIN dq[310]
    DIRECTION OUTPUT ;
    USE SIGNAL ;
    PORT
      LAYER M3 ;
        RECT  42.192 36.576 42.21 36.72 ;
    END
  END dq[310]
  PIN dq[311]
    DIRECTION OUTPUT ;
    USE SIGNAL ;
    PORT
      LAYER M5 ;
        RECT  42.336 36.528 42.36 36.72 ;
    END
  END dq[311]
  PIN dq[312]
    DIRECTION OUTPUT ;
    USE SIGNAL ;
    PORT
      LAYER M3 ;
        RECT  42.444 36.576 42.462 36.72 ;
    END
  END dq[312]
  PIN dq[313]
    DIRECTION OUTPUT ;
    USE SIGNAL ;
    PORT
      LAYER M5 ;
        RECT  42.576 36.528 42.6 36.72 ;
    END
  END dq[313]
  PIN dq[314]
    DIRECTION OUTPUT ;
    USE SIGNAL ;
    PORT
      LAYER M3 ;
        RECT  42.696 36.576 42.714 36.72 ;
    END
  END dq[314]
  PIN dq[315]
    DIRECTION OUTPUT ;
    USE SIGNAL ;
    PORT
      LAYER M5 ;
        RECT  42.816 36.528 42.84 36.72 ;
    END
  END dq[315]
  PIN dq[316]
    DIRECTION OUTPUT ;
    USE SIGNAL ;
    PORT
      LAYER M3 ;
        RECT  42.948 36.576 42.966 36.72 ;
    END
  END dq[316]
  PIN dq[317]
    DIRECTION OUTPUT ;
    USE SIGNAL ;
    PORT
      LAYER M5 ;
        RECT  43.056 36.528 43.08 36.72 ;
    END
  END dq[317]
  PIN dq[318]
    DIRECTION OUTPUT ;
    USE SIGNAL ;
    PORT
      LAYER M3 ;
        RECT  43.2 36.576 43.218 36.72 ;
    END
  END dq[318]
  PIN dq[319]
    DIRECTION OUTPUT ;
    USE SIGNAL ;
    PORT
      LAYER M5 ;
        RECT  43.296 36.528 43.32 36.72 ;
    END
  END dq[319]
  PIN dq[31]
    DIRECTION OUTPUT ;
    USE SIGNAL ;
    PORT
      LAYER M5 ;
        RECT  8.16 36.528 8.184 36.72 ;
    END
  END dq[31]
  PIN dq[320]
    DIRECTION OUTPUT ;
    USE SIGNAL ;
    PORT
      LAYER M3 ;
        RECT  43.416 36.576 43.434 36.72 ;
    END
  END dq[320]
  PIN dq[321]
    DIRECTION OUTPUT ;
    USE SIGNAL ;
    PORT
      LAYER M5 ;
        RECT  43.536 36.528 43.56 36.72 ;
    END
  END dq[321]
  PIN dq[322]
    DIRECTION OUTPUT ;
    USE SIGNAL ;
    PORT
      LAYER M3 ;
        RECT  43.668 36.576 43.686 36.72 ;
    END
  END dq[322]
  PIN dq[323]
    DIRECTION OUTPUT ;
    USE SIGNAL ;
    PORT
      LAYER M5 ;
        RECT  43.776 36.528 43.8 36.72 ;
    END
  END dq[323]
  PIN dq[324]
    DIRECTION OUTPUT ;
    USE SIGNAL ;
    PORT
      LAYER M3 ;
        RECT  43.92 36.576 43.938 36.72 ;
    END
  END dq[324]
  PIN dq[325]
    DIRECTION OUTPUT ;
    USE SIGNAL ;
    PORT
      LAYER M5 ;
        RECT  44.016 36.528 44.04 36.72 ;
    END
  END dq[325]
  PIN dq[326]
    DIRECTION OUTPUT ;
    USE SIGNAL ;
    PORT
      LAYER M3 ;
        RECT  44.172 36.576 44.19 36.72 ;
    END
  END dq[326]
  PIN dq[327]
    DIRECTION OUTPUT ;
    USE SIGNAL ;
    PORT
      LAYER M5 ;
        RECT  44.256 36.528 44.28 36.72 ;
    END
  END dq[327]
  PIN dq[328]
    DIRECTION OUTPUT ;
    USE SIGNAL ;
    PORT
      LAYER M3 ;
        RECT  44.388 36.576 44.406 36.72 ;
    END
  END dq[328]
  PIN dq[329]
    DIRECTION OUTPUT ;
    USE SIGNAL ;
    PORT
      LAYER M5 ;
        RECT  44.544 36.528 44.568 36.72 ;
    END
  END dq[329]
  PIN dq[32]
    DIRECTION OUTPUT ;
    USE SIGNAL ;
    PORT
      LAYER M3 ;
        RECT  8.28 36.576 8.298 36.72 ;
    END
  END dq[32]
  PIN dq[330]
    DIRECTION OUTPUT ;
    USE SIGNAL ;
    PORT
      LAYER M3 ;
        RECT  44.64 36.576 44.658 36.72 ;
    END
  END dq[330]
  PIN dq[331]
    DIRECTION OUTPUT ;
    USE SIGNAL ;
    PORT
      LAYER M5 ;
        RECT  44.784 36.528 44.808 36.72 ;
    END
  END dq[331]
  PIN dq[332]
    DIRECTION OUTPUT ;
    USE SIGNAL ;
    PORT
      LAYER M3 ;
        RECT  44.892 36.576 44.91 36.72 ;
    END
  END dq[332]
  PIN dq[333]
    DIRECTION OUTPUT ;
    USE SIGNAL ;
    PORT
      LAYER M5 ;
        RECT  45.024 36.528 45.048 36.72 ;
    END
  END dq[333]
  PIN dq[334]
    DIRECTION OUTPUT ;
    USE SIGNAL ;
    PORT
      LAYER M3 ;
        RECT  45.144 36.576 45.162 36.72 ;
    END
  END dq[334]
  PIN dq[335]
    DIRECTION OUTPUT ;
    USE SIGNAL ;
    PORT
      LAYER M5 ;
        RECT  45.264 36.528 45.288 36.72 ;
    END
  END dq[335]
  PIN dq[336]
    DIRECTION OUTPUT ;
    USE SIGNAL ;
    PORT
      LAYER M3 ;
        RECT  45.396 36.576 45.414 36.72 ;
    END
  END dq[336]
  PIN dq[337]
    DIRECTION OUTPUT ;
    USE SIGNAL ;
    PORT
      LAYER M5 ;
        RECT  45.504 36.528 45.528 36.72 ;
    END
  END dq[337]
  PIN dq[338]
    DIRECTION OUTPUT ;
    USE SIGNAL ;
    PORT
      LAYER M3 ;
        RECT  45.612 36.576 45.63 36.72 ;
    END
  END dq[338]
  PIN dq[339]
    DIRECTION OUTPUT ;
    USE SIGNAL ;
    PORT
      LAYER M5 ;
        RECT  45.744 36.528 45.768 36.72 ;
    END
  END dq[339]
  PIN dq[33]
    DIRECTION OUTPUT ;
    USE SIGNAL ;
    PORT
      LAYER M5 ;
        RECT  8.4 36.528 8.424 36.72 ;
    END
  END dq[33]
  PIN dq[340]
    DIRECTION OUTPUT ;
    USE SIGNAL ;
    PORT
      LAYER M3 ;
        RECT  45.864 36.576 45.882 36.72 ;
    END
  END dq[340]
  PIN dq[341]
    DIRECTION OUTPUT ;
    USE SIGNAL ;
    PORT
      LAYER M5 ;
        RECT  45.984 36.528 46.008 36.72 ;
    END
  END dq[341]
  PIN dq[342]
    DIRECTION OUTPUT ;
    USE SIGNAL ;
    PORT
      LAYER M3 ;
        RECT  46.116 36.576 46.134 36.72 ;
    END
  END dq[342]
  PIN dq[343]
    DIRECTION OUTPUT ;
    USE SIGNAL ;
    PORT
      LAYER M5 ;
        RECT  46.224 36.528 46.248 36.72 ;
    END
  END dq[343]
  PIN dq[344]
    DIRECTION OUTPUT ;
    USE SIGNAL ;
    PORT
      LAYER M3 ;
        RECT  46.368 36.576 46.386 36.72 ;
    END
  END dq[344]
  PIN dq[345]
    DIRECTION OUTPUT ;
    USE SIGNAL ;
    PORT
      LAYER M5 ;
        RECT  46.464 36.528 46.488 36.72 ;
    END
  END dq[345]
  PIN dq[346]
    DIRECTION OUTPUT ;
    USE SIGNAL ;
    PORT
      LAYER M3 ;
        RECT  46.584 36.576 46.602 36.72 ;
    END
  END dq[346]
  PIN dq[347]
    DIRECTION OUTPUT ;
    USE SIGNAL ;
    PORT
      LAYER M5 ;
        RECT  46.704 36.528 46.728 36.72 ;
    END
  END dq[347]
  PIN dq[348]
    DIRECTION OUTPUT ;
    USE SIGNAL ;
    PORT
      LAYER M3 ;
        RECT  46.836 36.576 46.854 36.72 ;
    END
  END dq[348]
  PIN dq[349]
    DIRECTION OUTPUT ;
    USE SIGNAL ;
    PORT
      LAYER M5 ;
        RECT  46.944 36.528 46.968 36.72 ;
    END
  END dq[349]
  PIN dq[34]
    DIRECTION OUTPUT ;
    USE SIGNAL ;
    PORT
      LAYER M3 ;
        RECT  8.532 36.576 8.55 36.72 ;
    END
  END dq[34]
  PIN dq[350]
    DIRECTION OUTPUT ;
    USE SIGNAL ;
    PORT
      LAYER M3 ;
        RECT  47.088 36.576 47.106 36.72 ;
    END
  END dq[350]
  PIN dq[351]
    DIRECTION OUTPUT ;
    USE SIGNAL ;
    PORT
      LAYER M5 ;
        RECT  47.232 36.528 47.256 36.72 ;
    END
  END dq[351]
  PIN dq[352]
    DIRECTION OUTPUT ;
    USE SIGNAL ;
    PORT
      LAYER M3 ;
        RECT  47.34 36.576 47.358 36.72 ;
    END
  END dq[352]
  PIN dq[353]
    DIRECTION OUTPUT ;
    USE SIGNAL ;
    PORT
      LAYER M5 ;
        RECT  47.472 36.528 47.496 36.72 ;
    END
  END dq[353]
  PIN dq[354]
    DIRECTION OUTPUT ;
    USE SIGNAL ;
    PORT
      LAYER M3 ;
        RECT  47.592 36.576 47.61 36.72 ;
    END
  END dq[354]
  PIN dq[355]
    DIRECTION OUTPUT ;
    USE SIGNAL ;
    PORT
      LAYER M5 ;
        RECT  47.712 36.528 47.736 36.72 ;
    END
  END dq[355]
  PIN dq[356]
    DIRECTION OUTPUT ;
    USE SIGNAL ;
    PORT
      LAYER M3 ;
        RECT  47.808 36.576 47.826 36.72 ;
    END
  END dq[356]
  PIN dq[357]
    DIRECTION OUTPUT ;
    USE SIGNAL ;
    PORT
      LAYER M5 ;
        RECT  47.952 36.528 47.976 36.72 ;
    END
  END dq[357]
  PIN dq[358]
    DIRECTION OUTPUT ;
    USE SIGNAL ;
    PORT
      LAYER M3 ;
        RECT  48.06 36.576 48.078 36.72 ;
    END
  END dq[358]
  PIN dq[359]
    DIRECTION OUTPUT ;
    USE SIGNAL ;
    PORT
      LAYER M5 ;
        RECT  48.192 36.528 48.216 36.72 ;
    END
  END dq[359]
  PIN dq[35]
    DIRECTION OUTPUT ;
    USE SIGNAL ;
    PORT
      LAYER M5 ;
        RECT  8.64 36.528 8.664 36.72 ;
    END
  END dq[35]
  PIN dq[360]
    DIRECTION OUTPUT ;
    USE SIGNAL ;
    PORT
      LAYER M3 ;
        RECT  48.312 36.576 48.33 36.72 ;
    END
  END dq[360]
  PIN dq[361]
    DIRECTION OUTPUT ;
    USE SIGNAL ;
    PORT
      LAYER M5 ;
        RECT  48.432 36.528 48.456 36.72 ;
    END
  END dq[361]
  PIN dq[362]
    DIRECTION OUTPUT ;
    USE SIGNAL ;
    PORT
      LAYER M3 ;
        RECT  48.564 36.576 48.582 36.72 ;
    END
  END dq[362]
  PIN dq[363]
    DIRECTION OUTPUT ;
    USE SIGNAL ;
    PORT
      LAYER M5 ;
        RECT  48.672 36.528 48.696 36.72 ;
    END
  END dq[363]
  PIN dq[364]
    DIRECTION OUTPUT ;
    USE SIGNAL ;
    PORT
      LAYER M3 ;
        RECT  48.816 36.576 48.834 36.72 ;
    END
  END dq[364]
  PIN dq[365]
    DIRECTION OUTPUT ;
    USE SIGNAL ;
    PORT
      LAYER M5 ;
        RECT  48.912 36.528 48.936 36.72 ;
    END
  END dq[365]
  PIN dq[366]
    DIRECTION OUTPUT ;
    USE SIGNAL ;
    PORT
      LAYER M3 ;
        RECT  49.032 36.576 49.05 36.72 ;
    END
  END dq[366]
  PIN dq[367]
    DIRECTION OUTPUT ;
    USE SIGNAL ;
    PORT
      LAYER M5 ;
        RECT  49.152 36.528 49.176 36.72 ;
    END
  END dq[367]
  PIN dq[368]
    DIRECTION OUTPUT ;
    USE SIGNAL ;
    PORT
      LAYER M3 ;
        RECT  49.284 36.576 49.302 36.72 ;
    END
  END dq[368]
  PIN dq[369]
    DIRECTION OUTPUT ;
    USE SIGNAL ;
    PORT
      LAYER M5 ;
        RECT  49.392 36.528 49.416 36.72 ;
    END
  END dq[369]
  PIN dq[36]
    DIRECTION OUTPUT ;
    USE SIGNAL ;
    PORT
      LAYER M3 ;
        RECT  8.748 36.576 8.766 36.72 ;
    END
  END dq[36]
  PIN dq[370]
    DIRECTION OUTPUT ;
    USE SIGNAL ;
    PORT
      LAYER M3 ;
        RECT  49.536 36.576 49.554 36.72 ;
    END
  END dq[370]
  PIN dq[371]
    DIRECTION OUTPUT ;
    USE SIGNAL ;
    PORT
      LAYER M5 ;
        RECT  49.632 36.528 49.656 36.72 ;
    END
  END dq[371]
  PIN dq[372]
    DIRECTION OUTPUT ;
    USE SIGNAL ;
    PORT
      LAYER M3 ;
        RECT  49.788 36.576 49.806 36.72 ;
    END
  END dq[372]
  PIN dq[373]
    DIRECTION OUTPUT ;
    USE SIGNAL ;
    PORT
      LAYER M5 ;
        RECT  49.872 36.528 49.896 36.72 ;
    END
  END dq[373]
  PIN dq[374]
    DIRECTION OUTPUT ;
    USE SIGNAL ;
    PORT
      LAYER M3 ;
        RECT  50.004 36.576 50.022 36.72 ;
    END
  END dq[374]
  PIN dq[375]
    DIRECTION OUTPUT ;
    USE SIGNAL ;
    PORT
      LAYER M5 ;
        RECT  50.16 36.528 50.184 36.72 ;
    END
  END dq[375]
  PIN dq[376]
    DIRECTION OUTPUT ;
    USE SIGNAL ;
    PORT
      LAYER M3 ;
        RECT  50.256 36.576 50.274 36.72 ;
    END
  END dq[376]
  PIN dq[377]
    DIRECTION OUTPUT ;
    USE SIGNAL ;
    PORT
      LAYER M5 ;
        RECT  50.4 36.528 50.424 36.72 ;
    END
  END dq[377]
  PIN dq[378]
    DIRECTION OUTPUT ;
    USE SIGNAL ;
    PORT
      LAYER M3 ;
        RECT  50.508 36.576 50.526 36.72 ;
    END
  END dq[378]
  PIN dq[379]
    DIRECTION OUTPUT ;
    USE SIGNAL ;
    PORT
      LAYER M5 ;
        RECT  50.64 36.528 50.664 36.72 ;
    END
  END dq[379]
  PIN dq[37]
    DIRECTION OUTPUT ;
    USE SIGNAL ;
    PORT
      LAYER M5 ;
        RECT  8.88 36.528 8.904 36.72 ;
    END
  END dq[37]
  PIN dq[380]
    DIRECTION OUTPUT ;
    USE SIGNAL ;
    PORT
      LAYER M3 ;
        RECT  50.76 36.576 50.778 36.72 ;
    END
  END dq[380]
  PIN dq[381]
    DIRECTION OUTPUT ;
    USE SIGNAL ;
    PORT
      LAYER M5 ;
        RECT  50.88 36.528 50.904 36.72 ;
    END
  END dq[381]
  PIN dq[382]
    DIRECTION OUTPUT ;
    USE SIGNAL ;
    PORT
      LAYER M3 ;
        RECT  51.012 36.576 51.03 36.72 ;
    END
  END dq[382]
  PIN dq[383]
    DIRECTION OUTPUT ;
    USE SIGNAL ;
    PORT
      LAYER M5 ;
        RECT  51.12 36.528 51.144 36.72 ;
    END
  END dq[383]
  PIN dq[384]
    DIRECTION OUTPUT ;
    USE SIGNAL ;
    PORT
      LAYER M3 ;
        RECT  51.228 36.576 51.246 36.72 ;
    END
  END dq[384]
  PIN dq[385]
    DIRECTION OUTPUT ;
    USE SIGNAL ;
    PORT
      LAYER M5 ;
        RECT  51.36 36.528 51.384 36.72 ;
    END
  END dq[385]
  PIN dq[386]
    DIRECTION OUTPUT ;
    USE SIGNAL ;
    PORT
      LAYER M3 ;
        RECT  51.48 36.576 51.498 36.72 ;
    END
  END dq[386]
  PIN dq[387]
    DIRECTION OUTPUT ;
    USE SIGNAL ;
    PORT
      LAYER M5 ;
        RECT  51.6 36.528 51.624 36.72 ;
    END
  END dq[387]
  PIN dq[388]
    DIRECTION OUTPUT ;
    USE SIGNAL ;
    PORT
      LAYER M3 ;
        RECT  51.732 36.576 51.75 36.72 ;
    END
  END dq[388]
  PIN dq[389]
    DIRECTION OUTPUT ;
    USE SIGNAL ;
    PORT
      LAYER M5 ;
        RECT  51.84 36.528 51.864 36.72 ;
    END
  END dq[389]
  PIN dq[38]
    DIRECTION OUTPUT ;
    USE SIGNAL ;
    PORT
      LAYER M3 ;
        RECT  9 36.576 9.018 36.72 ;
    END
  END dq[38]
  PIN dq[390]
    DIRECTION OUTPUT ;
    USE SIGNAL ;
    PORT
      LAYER M3 ;
        RECT  51.984 36.576 52.002 36.72 ;
    END
  END dq[390]
  PIN dq[391]
    DIRECTION OUTPUT ;
    USE SIGNAL ;
    PORT
      LAYER M5 ;
        RECT  52.08 36.528 52.104 36.72 ;
    END
  END dq[391]
  PIN dq[392]
    DIRECTION OUTPUT ;
    USE SIGNAL ;
    PORT
      LAYER M3 ;
        RECT  52.2 36.576 52.218 36.72 ;
    END
  END dq[392]
  PIN dq[393]
    DIRECTION OUTPUT ;
    USE SIGNAL ;
    PORT
      LAYER M5 ;
        RECT  52.32 36.528 52.344 36.72 ;
    END
  END dq[393]
  PIN dq[394]
    DIRECTION OUTPUT ;
    USE SIGNAL ;
    PORT
      LAYER M3 ;
        RECT  52.452 36.576 52.47 36.72 ;
    END
  END dq[394]
  PIN dq[395]
    DIRECTION OUTPUT ;
    USE SIGNAL ;
    PORT
      LAYER M5 ;
        RECT  52.56 36.528 52.584 36.72 ;
    END
  END dq[395]
  PIN dq[396]
    DIRECTION OUTPUT ;
    USE SIGNAL ;
    PORT
      LAYER M3 ;
        RECT  52.704 36.576 52.722 36.72 ;
    END
  END dq[396]
  PIN dq[397]
    DIRECTION OUTPUT ;
    USE SIGNAL ;
    PORT
      LAYER M5 ;
        RECT  52.8 36.528 52.824 36.72 ;
    END
  END dq[397]
  PIN dq[398]
    DIRECTION OUTPUT ;
    USE SIGNAL ;
    PORT
      LAYER M3 ;
        RECT  52.956 36.576 52.974 36.72 ;
    END
  END dq[398]
  PIN dq[399]
    DIRECTION OUTPUT ;
    USE SIGNAL ;
    PORT
      LAYER M5 ;
        RECT  53.088 36.528 53.112 36.72 ;
    END
  END dq[399]
  PIN dq[39]
    DIRECTION OUTPUT ;
    USE SIGNAL ;
    PORT
      LAYER M5 ;
        RECT  9.12 36.528 9.144 36.72 ;
    END
  END dq[39]
  PIN dq[3]
    DIRECTION OUTPUT ;
    USE SIGNAL ;
    PORT
      LAYER M5 ;
        RECT  4.752 36.528 4.776 36.72 ;
    END
  END dq[3]
  PIN dq[400]
    DIRECTION OUTPUT ;
    USE SIGNAL ;
    PORT
      LAYER M3 ;
        RECT  53.208 36.576 53.226 36.72 ;
    END
  END dq[400]
  PIN dq[401]
    DIRECTION OUTPUT ;
    USE SIGNAL ;
    PORT
      LAYER M5 ;
        RECT  53.328 36.528 53.352 36.72 ;
    END
  END dq[401]
  PIN dq[402]
    DIRECTION OUTPUT ;
    USE SIGNAL ;
    PORT
      LAYER M3 ;
        RECT  53.424 36.576 53.442 36.72 ;
    END
  END dq[402]
  PIN dq[403]
    DIRECTION OUTPUT ;
    USE SIGNAL ;
    PORT
      LAYER M5 ;
        RECT  53.568 36.528 53.592 36.72 ;
    END
  END dq[403]
  PIN dq[404]
    DIRECTION OUTPUT ;
    USE SIGNAL ;
    PORT
      LAYER M3 ;
        RECT  53.676 36.576 53.694 36.72 ;
    END
  END dq[404]
  PIN dq[405]
    DIRECTION OUTPUT ;
    USE SIGNAL ;
    PORT
      LAYER M5 ;
        RECT  53.808 36.528 53.832 36.72 ;
    END
  END dq[405]
  PIN dq[406]
    DIRECTION OUTPUT ;
    USE SIGNAL ;
    PORT
      LAYER M3 ;
        RECT  53.928 36.576 53.946 36.72 ;
    END
  END dq[406]
  PIN dq[407]
    DIRECTION OUTPUT ;
    USE SIGNAL ;
    PORT
      LAYER M5 ;
        RECT  54.048 36.528 54.072 36.72 ;
    END
  END dq[407]
  PIN dq[408]
    DIRECTION OUTPUT ;
    USE SIGNAL ;
    PORT
      LAYER M3 ;
        RECT  54.18 36.576 54.198 36.72 ;
    END
  END dq[408]
  PIN dq[409]
    DIRECTION OUTPUT ;
    USE SIGNAL ;
    PORT
      LAYER M5 ;
        RECT  54.288 36.528 54.312 36.72 ;
    END
  END dq[409]
  PIN dq[40]
    DIRECTION OUTPUT ;
    USE SIGNAL ;
    PORT
      LAYER M3 ;
        RECT  9.252 36.576 9.27 36.72 ;
    END
  END dq[40]
  PIN dq[410]
    DIRECTION OUTPUT ;
    USE SIGNAL ;
    PORT
      LAYER M3 ;
        RECT  54.396 36.576 54.414 36.72 ;
    END
  END dq[410]
  PIN dq[411]
    DIRECTION OUTPUT ;
    USE SIGNAL ;
    PORT
      LAYER M5 ;
        RECT  54.528 36.528 54.552 36.72 ;
    END
  END dq[411]
  PIN dq[412]
    DIRECTION OUTPUT ;
    USE SIGNAL ;
    PORT
      LAYER M3 ;
        RECT  54.648 36.576 54.666 36.72 ;
    END
  END dq[412]
  PIN dq[413]
    DIRECTION OUTPUT ;
    USE SIGNAL ;
    PORT
      LAYER M5 ;
        RECT  54.768 36.528 54.792 36.72 ;
    END
  END dq[413]
  PIN dq[414]
    DIRECTION OUTPUT ;
    USE SIGNAL ;
    PORT
      LAYER M3 ;
        RECT  54.9 36.576 54.918 36.72 ;
    END
  END dq[414]
  PIN dq[415]
    DIRECTION OUTPUT ;
    USE SIGNAL ;
    PORT
      LAYER M5 ;
        RECT  55.008 36.528 55.032 36.72 ;
    END
  END dq[415]
  PIN dq[416]
    DIRECTION OUTPUT ;
    USE SIGNAL ;
    PORT
      LAYER M3 ;
        RECT  55.152 36.576 55.17 36.72 ;
    END
  END dq[416]
  PIN dq[417]
    DIRECTION OUTPUT ;
    USE SIGNAL ;
    PORT
      LAYER M5 ;
        RECT  55.248 36.528 55.272 36.72 ;
    END
  END dq[417]
  PIN dq[418]
    DIRECTION OUTPUT ;
    USE SIGNAL ;
    PORT
      LAYER M3 ;
        RECT  55.404 36.576 55.422 36.72 ;
    END
  END dq[418]
  PIN dq[419]
    DIRECTION OUTPUT ;
    USE SIGNAL ;
    PORT
      LAYER M5 ;
        RECT  55.488 36.528 55.512 36.72 ;
    END
  END dq[419]
  PIN dq[41]
    DIRECTION OUTPUT ;
    USE SIGNAL ;
    PORT
      LAYER M5 ;
        RECT  9.36 36.528 9.384 36.72 ;
    END
  END dq[41]
  PIN dq[420]
    DIRECTION OUTPUT ;
    USE SIGNAL ;
    PORT
      LAYER M3 ;
        RECT  55.62 36.576 55.638 36.72 ;
    END
  END dq[420]
  PIN dq[421]
    DIRECTION OUTPUT ;
    USE SIGNAL ;
    PORT
      LAYER M5 ;
        RECT  55.776 36.528 55.8 36.72 ;
    END
  END dq[421]
  PIN dq[422]
    DIRECTION OUTPUT ;
    USE SIGNAL ;
    PORT
      LAYER M3 ;
        RECT  55.872 36.576 55.89 36.72 ;
    END
  END dq[422]
  PIN dq[423]
    DIRECTION OUTPUT ;
    USE SIGNAL ;
    PORT
      LAYER M5 ;
        RECT  56.016 36.528 56.04 36.72 ;
    END
  END dq[423]
  PIN dq[424]
    DIRECTION OUTPUT ;
    USE SIGNAL ;
    PORT
      LAYER M3 ;
        RECT  56.124 36.576 56.142 36.72 ;
    END
  END dq[424]
  PIN dq[425]
    DIRECTION OUTPUT ;
    USE SIGNAL ;
    PORT
      LAYER M5 ;
        RECT  56.256 36.528 56.28 36.72 ;
    END
  END dq[425]
  PIN dq[426]
    DIRECTION OUTPUT ;
    USE SIGNAL ;
    PORT
      LAYER M3 ;
        RECT  56.376 36.576 56.394 36.72 ;
    END
  END dq[426]
  PIN dq[427]
    DIRECTION OUTPUT ;
    USE SIGNAL ;
    PORT
      LAYER M5 ;
        RECT  56.496 36.528 56.52 36.72 ;
    END
  END dq[427]
  PIN dq[428]
    DIRECTION OUTPUT ;
    USE SIGNAL ;
    PORT
      LAYER M3 ;
        RECT  56.592 36.576 56.61 36.72 ;
    END
  END dq[428]
  PIN dq[429]
    DIRECTION OUTPUT ;
    USE SIGNAL ;
    PORT
      LAYER M5 ;
        RECT  56.736 36.528 56.76 36.72 ;
    END
  END dq[429]
  PIN dq[42]
    DIRECTION OUTPUT ;
    USE SIGNAL ;
    PORT
      LAYER M3 ;
        RECT  9.504 36.576 9.522 36.72 ;
    END
  END dq[42]
  PIN dq[430]
    DIRECTION OUTPUT ;
    USE SIGNAL ;
    PORT
      LAYER M3 ;
        RECT  56.844 36.576 56.862 36.72 ;
    END
  END dq[430]
  PIN dq[431]
    DIRECTION OUTPUT ;
    USE SIGNAL ;
    PORT
      LAYER M5 ;
        RECT  56.976 36.528 57 36.72 ;
    END
  END dq[431]
  PIN dq[432]
    DIRECTION OUTPUT ;
    USE SIGNAL ;
    PORT
      LAYER M3 ;
        RECT  57.096 36.576 57.114 36.72 ;
    END
  END dq[432]
  PIN dq[433]
    DIRECTION OUTPUT ;
    USE SIGNAL ;
    PORT
      LAYER M5 ;
        RECT  57.216 36.528 57.24 36.72 ;
    END
  END dq[433]
  PIN dq[434]
    DIRECTION OUTPUT ;
    USE SIGNAL ;
    PORT
      LAYER M3 ;
        RECT  57.348 36.576 57.366 36.72 ;
    END
  END dq[434]
  PIN dq[435]
    DIRECTION OUTPUT ;
    USE SIGNAL ;
    PORT
      LAYER M5 ;
        RECT  57.456 36.528 57.48 36.72 ;
    END
  END dq[435]
  PIN dq[436]
    DIRECTION OUTPUT ;
    USE SIGNAL ;
    PORT
      LAYER M3 ;
        RECT  57.6 36.576 57.618 36.72 ;
    END
  END dq[436]
  PIN dq[437]
    DIRECTION OUTPUT ;
    USE SIGNAL ;
    PORT
      LAYER M5 ;
        RECT  57.696 36.528 57.72 36.72 ;
    END
  END dq[437]
  PIN dq[438]
    DIRECTION OUTPUT ;
    USE SIGNAL ;
    PORT
      LAYER M3 ;
        RECT  57.816 36.576 57.834 36.72 ;
    END
  END dq[438]
  PIN dq[439]
    DIRECTION OUTPUT ;
    USE SIGNAL ;
    PORT
      LAYER M5 ;
        RECT  57.936 36.528 57.96 36.72 ;
    END
  END dq[439]
  PIN dq[43]
    DIRECTION OUTPUT ;
    USE SIGNAL ;
    PORT
      LAYER M5 ;
        RECT  9.6 36.528 9.624 36.72 ;
    END
  END dq[43]
  PIN dq[440]
    DIRECTION OUTPUT ;
    USE SIGNAL ;
    PORT
      LAYER M3 ;
        RECT  58.068 36.576 58.086 36.72 ;
    END
  END dq[440]
  PIN dq[441]
    DIRECTION OUTPUT ;
    USE SIGNAL ;
    PORT
      LAYER M5 ;
        RECT  58.176 36.528 58.2 36.72 ;
    END
  END dq[441]
  PIN dq[442]
    DIRECTION OUTPUT ;
    USE SIGNAL ;
    PORT
      LAYER M3 ;
        RECT  58.32 36.576 58.338 36.72 ;
    END
  END dq[442]
  PIN dq[443]
    DIRECTION OUTPUT ;
    USE SIGNAL ;
    PORT
      LAYER M5 ;
        RECT  58.416 36.528 58.44 36.72 ;
    END
  END dq[443]
  PIN dq[444]
    DIRECTION OUTPUT ;
    USE SIGNAL ;
    PORT
      LAYER M3 ;
        RECT  58.572 36.576 58.59 36.72 ;
    END
  END dq[444]
  PIN dq[445]
    DIRECTION OUTPUT ;
    USE SIGNAL ;
    PORT
      LAYER M5 ;
        RECT  58.704 36.528 58.728 36.72 ;
    END
  END dq[445]
  PIN dq[446]
    DIRECTION OUTPUT ;
    USE SIGNAL ;
    PORT
      LAYER M3 ;
        RECT  58.824 36.576 58.842 36.72 ;
    END
  END dq[446]
  PIN dq[447]
    DIRECTION OUTPUT ;
    USE SIGNAL ;
    PORT
      LAYER M5 ;
        RECT  58.944 36.528 58.968 36.72 ;
    END
  END dq[447]
  PIN dq[448]
    DIRECTION OUTPUT ;
    USE SIGNAL ;
    PORT
      LAYER M3 ;
        RECT  59.04 36.576 59.058 36.72 ;
    END
  END dq[448]
  PIN dq[449]
    DIRECTION OUTPUT ;
    USE SIGNAL ;
    PORT
      LAYER M5 ;
        RECT  59.184 36.528 59.208 36.72 ;
    END
  END dq[449]
  PIN dq[44]
    DIRECTION OUTPUT ;
    USE SIGNAL ;
    PORT
      LAYER M3 ;
        RECT  9.756 36.576 9.774 36.72 ;
    END
  END dq[44]
  PIN dq[450]
    DIRECTION OUTPUT ;
    USE SIGNAL ;
    PORT
      LAYER M3 ;
        RECT  59.292 36.576 59.31 36.72 ;
    END
  END dq[450]
  PIN dq[451]
    DIRECTION OUTPUT ;
    USE SIGNAL ;
    PORT
      LAYER M5 ;
        RECT  59.424 36.528 59.448 36.72 ;
    END
  END dq[451]
  PIN dq[452]
    DIRECTION OUTPUT ;
    USE SIGNAL ;
    PORT
      LAYER M3 ;
        RECT  59.544 36.576 59.562 36.72 ;
    END
  END dq[452]
  PIN dq[453]
    DIRECTION OUTPUT ;
    USE SIGNAL ;
    PORT
      LAYER M5 ;
        RECT  59.664 36.528 59.688 36.72 ;
    END
  END dq[453]
  PIN dq[454]
    DIRECTION OUTPUT ;
    USE SIGNAL ;
    PORT
      LAYER M3 ;
        RECT  59.796 36.576 59.814 36.72 ;
    END
  END dq[454]
  PIN dq[455]
    DIRECTION OUTPUT ;
    USE SIGNAL ;
    PORT
      LAYER M5 ;
        RECT  59.904 36.528 59.928 36.72 ;
    END
  END dq[455]
  PIN dq[456]
    DIRECTION OUTPUT ;
    USE SIGNAL ;
    PORT
      LAYER M3 ;
        RECT  60.012 36.576 60.03 36.72 ;
    END
  END dq[456]
  PIN dq[457]
    DIRECTION OUTPUT ;
    USE SIGNAL ;
    PORT
      LAYER M5 ;
        RECT  60.144 36.528 60.168 36.72 ;
    END
  END dq[457]
  PIN dq[458]
    DIRECTION OUTPUT ;
    USE SIGNAL ;
    PORT
      LAYER M3 ;
        RECT  60.264 36.576 60.282 36.72 ;
    END
  END dq[458]
  PIN dq[459]
    DIRECTION OUTPUT ;
    USE SIGNAL ;
    PORT
      LAYER M5 ;
        RECT  60.384 36.528 60.408 36.72 ;
    END
  END dq[459]
  PIN dq[45]
    DIRECTION OUTPUT ;
    USE SIGNAL ;
    PORT
      LAYER M5 ;
        RECT  9.84 36.528 9.864 36.72 ;
    END
  END dq[45]
  PIN dq[460]
    DIRECTION OUTPUT ;
    USE SIGNAL ;
    PORT
      LAYER M3 ;
        RECT  60.516 36.576 60.534 36.72 ;
    END
  END dq[460]
  PIN dq[461]
    DIRECTION OUTPUT ;
    USE SIGNAL ;
    PORT
      LAYER M5 ;
        RECT  60.624 36.528 60.648 36.72 ;
    END
  END dq[461]
  PIN dq[462]
    DIRECTION OUTPUT ;
    USE SIGNAL ;
    PORT
      LAYER M3 ;
        RECT  60.768 36.576 60.786 36.72 ;
    END
  END dq[462]
  PIN dq[463]
    DIRECTION OUTPUT ;
    USE SIGNAL ;
    PORT
      LAYER M5 ;
        RECT  60.864 36.528 60.888 36.72 ;
    END
  END dq[463]
  PIN dq[464]
    DIRECTION OUTPUT ;
    USE SIGNAL ;
    PORT
      LAYER M3 ;
        RECT  61.02 36.576 61.038 36.72 ;
    END
  END dq[464]
  PIN dq[465]
    DIRECTION OUTPUT ;
    USE SIGNAL ;
    PORT
      LAYER M5 ;
        RECT  61.104 36.528 61.128 36.72 ;
    END
  END dq[465]
  PIN dq[466]
    DIRECTION OUTPUT ;
    USE SIGNAL ;
    PORT
      LAYER M3 ;
        RECT  61.236 36.576 61.254 36.72 ;
    END
  END dq[466]
  PIN dq[467]
    DIRECTION OUTPUT ;
    USE SIGNAL ;
    PORT
      LAYER M5 ;
        RECT  61.344 36.528 61.368 36.72 ;
    END
  END dq[467]
  PIN dq[468]
    DIRECTION OUTPUT ;
    USE SIGNAL ;
    PORT
      LAYER M3 ;
        RECT  61.488 36.576 61.506 36.72 ;
    END
  END dq[468]
  PIN dq[469]
    DIRECTION OUTPUT ;
    USE SIGNAL ;
    PORT
      LAYER M5 ;
        RECT  61.632 36.528 61.656 36.72 ;
    END
  END dq[469]
  PIN dq[46]
    DIRECTION OUTPUT ;
    USE SIGNAL ;
    PORT
      LAYER M3 ;
        RECT  9.972 36.576 9.99 36.72 ;
    END
  END dq[46]
  PIN dq[470]
    DIRECTION OUTPUT ;
    USE SIGNAL ;
    PORT
      LAYER M3 ;
        RECT  61.74 36.576 61.758 36.72 ;
    END
  END dq[470]
  PIN dq[471]
    DIRECTION OUTPUT ;
    USE SIGNAL ;
    PORT
      LAYER M5 ;
        RECT  61.872 36.528 61.896 36.72 ;
    END
  END dq[471]
  PIN dq[472]
    DIRECTION OUTPUT ;
    USE SIGNAL ;
    PORT
      LAYER M3 ;
        RECT  61.992 36.576 62.01 36.72 ;
    END
  END dq[472]
  PIN dq[473]
    DIRECTION OUTPUT ;
    USE SIGNAL ;
    PORT
      LAYER M5 ;
        RECT  62.112 36.528 62.136 36.72 ;
    END
  END dq[473]
  PIN dq[474]
    DIRECTION OUTPUT ;
    USE SIGNAL ;
    PORT
      LAYER M3 ;
        RECT  62.208 36.576 62.226 36.72 ;
    END
  END dq[474]
  PIN dq[475]
    DIRECTION OUTPUT ;
    USE SIGNAL ;
    PORT
      LAYER M5 ;
        RECT  62.352 36.528 62.376 36.72 ;
    END
  END dq[475]
  PIN dq[476]
    DIRECTION OUTPUT ;
    USE SIGNAL ;
    PORT
      LAYER M3 ;
        RECT  62.46 36.576 62.478 36.72 ;
    END
  END dq[476]
  PIN dq[477]
    DIRECTION OUTPUT ;
    USE SIGNAL ;
    PORT
      LAYER M5 ;
        RECT  62.592 36.528 62.616 36.72 ;
    END
  END dq[477]
  PIN dq[478]
    DIRECTION OUTPUT ;
    USE SIGNAL ;
    PORT
      LAYER M3 ;
        RECT  62.712 36.576 62.73 36.72 ;
    END
  END dq[478]
  PIN dq[479]
    DIRECTION OUTPUT ;
    USE SIGNAL ;
    PORT
      LAYER M5 ;
        RECT  62.832 36.528 62.856 36.72 ;
    END
  END dq[479]
  PIN dq[47]
    DIRECTION OUTPUT ;
    USE SIGNAL ;
    PORT
      LAYER M5 ;
        RECT  10.128 36.528 10.152 36.72 ;
    END
  END dq[47]
  PIN dq[480]
    DIRECTION OUTPUT ;
    USE SIGNAL ;
    PORT
      LAYER M3 ;
        RECT  62.964 36.576 62.982 36.72 ;
    END
  END dq[480]
  PIN dq[481]
    DIRECTION OUTPUT ;
    USE SIGNAL ;
    PORT
      LAYER M5 ;
        RECT  63.072 36.528 63.096 36.72 ;
    END
  END dq[481]
  PIN dq[482]
    DIRECTION OUTPUT ;
    USE SIGNAL ;
    PORT
      LAYER M3 ;
        RECT  63.216 36.576 63.234 36.72 ;
    END
  END dq[482]
  PIN dq[483]
    DIRECTION OUTPUT ;
    USE SIGNAL ;
    PORT
      LAYER M5 ;
        RECT  63.312 36.528 63.336 36.72 ;
    END
  END dq[483]
  PIN dq[484]
    DIRECTION OUTPUT ;
    USE SIGNAL ;
    PORT
      LAYER M3 ;
        RECT  63.432 36.576 63.45 36.72 ;
    END
  END dq[484]
  PIN dq[485]
    DIRECTION OUTPUT ;
    USE SIGNAL ;
    PORT
      LAYER M5 ;
        RECT  63.552 36.528 63.576 36.72 ;
    END
  END dq[485]
  PIN dq[486]
    DIRECTION OUTPUT ;
    USE SIGNAL ;
    PORT
      LAYER M3 ;
        RECT  63.684 36.576 63.702 36.72 ;
    END
  END dq[486]
  PIN dq[487]
    DIRECTION OUTPUT ;
    USE SIGNAL ;
    PORT
      LAYER M5 ;
        RECT  63.792 36.528 63.816 36.72 ;
    END
  END dq[487]
  PIN dq[488]
    DIRECTION OUTPUT ;
    USE SIGNAL ;
    PORT
      LAYER M3 ;
        RECT  63.936 36.576 63.954 36.72 ;
    END
  END dq[488]
  PIN dq[489]
    DIRECTION OUTPUT ;
    USE SIGNAL ;
    PORT
      LAYER M5 ;
        RECT  64.032 36.528 64.056 36.72 ;
    END
  END dq[489]
  PIN dq[48]
    DIRECTION OUTPUT ;
    USE SIGNAL ;
    PORT
      LAYER M3 ;
        RECT  10.224 36.576 10.242 36.72 ;
    END
  END dq[48]
  PIN dq[490]
    DIRECTION OUTPUT ;
    USE SIGNAL ;
    PORT
      LAYER M3 ;
        RECT  64.188 36.576 64.206 36.72 ;
    END
  END dq[490]
  PIN dq[491]
    DIRECTION OUTPUT ;
    USE SIGNAL ;
    PORT
      LAYER M5 ;
        RECT  64.272 36.528 64.296 36.72 ;
    END
  END dq[491]
  PIN dq[492]
    DIRECTION OUTPUT ;
    USE SIGNAL ;
    PORT
      LAYER M3 ;
        RECT  64.404 36.576 64.422 36.72 ;
    END
  END dq[492]
  PIN dq[493]
    DIRECTION OUTPUT ;
    USE SIGNAL ;
    PORT
      LAYER M5 ;
        RECT  64.56 36.528 64.584 36.72 ;
    END
  END dq[493]
  PIN dq[494]
    DIRECTION OUTPUT ;
    USE SIGNAL ;
    PORT
      LAYER M3 ;
        RECT  64.656 36.576 64.674 36.72 ;
    END
  END dq[494]
  PIN dq[495]
    DIRECTION OUTPUT ;
    USE SIGNAL ;
    PORT
      LAYER M5 ;
        RECT  64.8 36.528 64.824 36.72 ;
    END
  END dq[495]
  PIN dq[496]
    DIRECTION OUTPUT ;
    USE SIGNAL ;
    PORT
      LAYER M3 ;
        RECT  64.908 36.576 64.926 36.72 ;
    END
  END dq[496]
  PIN dq[497]
    DIRECTION OUTPUT ;
    USE SIGNAL ;
    PORT
      LAYER M5 ;
        RECT  65.04 36.528 65.064 36.72 ;
    END
  END dq[497]
  PIN dq[498]
    DIRECTION OUTPUT ;
    USE SIGNAL ;
    PORT
      LAYER M3 ;
        RECT  65.16 36.576 65.178 36.72 ;
    END
  END dq[498]
  PIN dq[499]
    DIRECTION OUTPUT ;
    USE SIGNAL ;
    PORT
      LAYER M5 ;
        RECT  65.28 36.528 65.304 36.72 ;
    END
  END dq[499]
  PIN dq[49]
    DIRECTION OUTPUT ;
    USE SIGNAL ;
    PORT
      LAYER M5 ;
        RECT  10.368 36.528 10.392 36.72 ;
    END
  END dq[49]
  PIN dq[4]
    DIRECTION OUTPUT ;
    USE SIGNAL ;
    PORT
      LAYER M3 ;
        RECT  4.86 36.576 4.878 36.72 ;
    END
  END dq[4]
  PIN dq[500]
    DIRECTION OUTPUT ;
    USE SIGNAL ;
    PORT
      LAYER M3 ;
        RECT  65.412 36.576 65.43 36.72 ;
    END
  END dq[500]
  PIN dq[501]
    DIRECTION OUTPUT ;
    USE SIGNAL ;
    PORT
      LAYER M5 ;
        RECT  65.52 36.528 65.544 36.72 ;
    END
  END dq[501]
  PIN dq[502]
    DIRECTION OUTPUT ;
    USE SIGNAL ;
    PORT
      LAYER M3 ;
        RECT  65.628 36.576 65.646 36.72 ;
    END
  END dq[502]
  PIN dq[503]
    DIRECTION OUTPUT ;
    USE SIGNAL ;
    PORT
      LAYER M5 ;
        RECT  65.76 36.528 65.784 36.72 ;
    END
  END dq[503]
  PIN dq[504]
    DIRECTION OUTPUT ;
    USE SIGNAL ;
    PORT
      LAYER M3 ;
        RECT  65.88 36.576 65.898 36.72 ;
    END
  END dq[504]
  PIN dq[505]
    DIRECTION OUTPUT ;
    USE SIGNAL ;
    PORT
      LAYER M5 ;
        RECT  66 36.528 66.024 36.72 ;
    END
  END dq[505]
  PIN dq[506]
    DIRECTION OUTPUT ;
    USE SIGNAL ;
    PORT
      LAYER M3 ;
        RECT  66.132 36.576 66.15 36.72 ;
    END
  END dq[506]
  PIN dq[507]
    DIRECTION OUTPUT ;
    USE SIGNAL ;
    PORT
      LAYER M5 ;
        RECT  66.24 36.528 66.264 36.72 ;
    END
  END dq[507]
  PIN dq[508]
    DIRECTION OUTPUT ;
    USE SIGNAL ;
    PORT
      LAYER M3 ;
        RECT  66.384 36.576 66.402 36.72 ;
    END
  END dq[508]
  PIN dq[509]
    DIRECTION OUTPUT ;
    USE SIGNAL ;
    PORT
      LAYER M5 ;
        RECT  66.48 36.528 66.504 36.72 ;
    END
  END dq[509]
  PIN dq[50]
    DIRECTION OUTPUT ;
    USE SIGNAL ;
    PORT
      LAYER M3 ;
        RECT  10.476 36.576 10.494 36.72 ;
    END
  END dq[50]
  PIN dq[510]
    DIRECTION OUTPUT ;
    USE SIGNAL ;
    PORT
      LAYER M3 ;
        RECT  66.6 36.576 66.618 36.72 ;
    END
  END dq[510]
  PIN dq[511]
    DIRECTION OUTPUT ;
    USE SIGNAL ;
    PORT
      LAYER M5 ;
        RECT  66.72 36.528 66.744 36.72 ;
    END
  END dq[511]
  PIN dq[512]
    DIRECTION OUTPUT ;
    USE SIGNAL ;
    PORT
      LAYER M3 ;
        RECT  66.852 36.576 66.87 36.72 ;
    END
  END dq[512]
  PIN dq[513]
    DIRECTION OUTPUT ;
    USE SIGNAL ;
    PORT
      LAYER M5 ;
        RECT  66.96 36.528 66.984 36.72 ;
    END
  END dq[513]
  PIN dq[514]
    DIRECTION OUTPUT ;
    USE SIGNAL ;
    PORT
      LAYER M3 ;
        RECT  67.104 36.576 67.122 36.72 ;
    END
  END dq[514]
  PIN dq[515]
    DIRECTION OUTPUT ;
    USE SIGNAL ;
    PORT
      LAYER M5 ;
        RECT  67.248 36.528 67.272 36.72 ;
    END
  END dq[515]
  PIN dq[516]
    DIRECTION OUTPUT ;
    USE SIGNAL ;
    PORT
      LAYER M3 ;
        RECT  67.356 36.576 67.374 36.72 ;
    END
  END dq[516]
  PIN dq[517]
    DIRECTION OUTPUT ;
    USE SIGNAL ;
    PORT
      LAYER M5 ;
        RECT  67.488 36.528 67.512 36.72 ;
    END
  END dq[517]
  PIN dq[518]
    DIRECTION OUTPUT ;
    USE SIGNAL ;
    PORT
      LAYER M3 ;
        RECT  67.608 36.576 67.626 36.72 ;
    END
  END dq[518]
  PIN dq[519]
    DIRECTION OUTPUT ;
    USE SIGNAL ;
    PORT
      LAYER M5 ;
        RECT  67.728 36.528 67.752 36.72 ;
    END
  END dq[519]
  PIN dq[51]
    DIRECTION OUTPUT ;
    USE SIGNAL ;
    PORT
      LAYER M5 ;
        RECT  10.608 36.528 10.632 36.72 ;
    END
  END dq[51]
  PIN dq[520]
    DIRECTION OUTPUT ;
    USE SIGNAL ;
    PORT
      LAYER M3 ;
        RECT  67.824 36.576 67.842 36.72 ;
    END
  END dq[520]
  PIN dq[521]
    DIRECTION OUTPUT ;
    USE SIGNAL ;
    PORT
      LAYER M5 ;
        RECT  67.968 36.528 67.992 36.72 ;
    END
  END dq[521]
  PIN dq[522]
    DIRECTION OUTPUT ;
    USE SIGNAL ;
    PORT
      LAYER M3 ;
        RECT  68.076 36.576 68.094 36.72 ;
    END
  END dq[522]
  PIN dq[523]
    DIRECTION OUTPUT ;
    USE SIGNAL ;
    PORT
      LAYER M5 ;
        RECT  68.208 36.528 68.232 36.72 ;
    END
  END dq[523]
  PIN dq[524]
    DIRECTION OUTPUT ;
    USE SIGNAL ;
    PORT
      LAYER M3 ;
        RECT  68.328 36.576 68.346 36.72 ;
    END
  END dq[524]
  PIN dq[525]
    DIRECTION OUTPUT ;
    USE SIGNAL ;
    PORT
      LAYER M5 ;
        RECT  68.448 36.528 68.472 36.72 ;
    END
  END dq[525]
  PIN dq[526]
    DIRECTION OUTPUT ;
    USE SIGNAL ;
    PORT
      LAYER M3 ;
        RECT  68.58 36.576 68.598 36.72 ;
    END
  END dq[526]
  PIN dq[527]
    DIRECTION OUTPUT ;
    USE SIGNAL ;
    PORT
      LAYER M5 ;
        RECT  68.688 36.528 68.712 36.72 ;
    END
  END dq[527]
  PIN dq[528]
    DIRECTION OUTPUT ;
    USE SIGNAL ;
    PORT
      LAYER M3 ;
        RECT  68.832 36.576 68.85 36.72 ;
    END
  END dq[528]
  PIN dq[529]
    DIRECTION OUTPUT ;
    USE SIGNAL ;
    PORT
      LAYER M5 ;
        RECT  68.928 36.528 68.952 36.72 ;
    END
  END dq[529]
  PIN dq[52]
    DIRECTION OUTPUT ;
    USE SIGNAL ;
    PORT
      LAYER M3 ;
        RECT  10.728 36.576 10.746 36.72 ;
    END
  END dq[52]
  PIN dq[530]
    DIRECTION OUTPUT ;
    USE SIGNAL ;
    PORT
      LAYER M3 ;
        RECT  69.048 36.576 69.066 36.72 ;
    END
  END dq[530]
  PIN dq[531]
    DIRECTION OUTPUT ;
    USE SIGNAL ;
    PORT
      LAYER M5 ;
        RECT  69.168 36.528 69.192 36.72 ;
    END
  END dq[531]
  PIN dq[532]
    DIRECTION OUTPUT ;
    USE SIGNAL ;
    PORT
      LAYER M3 ;
        RECT  69.3 36.576 69.318 36.72 ;
    END
  END dq[532]
  PIN dq[533]
    DIRECTION OUTPUT ;
    USE SIGNAL ;
    PORT
      LAYER M5 ;
        RECT  69.408 36.528 69.432 36.72 ;
    END
  END dq[533]
  PIN dq[534]
    DIRECTION OUTPUT ;
    USE SIGNAL ;
    PORT
      LAYER M3 ;
        RECT  69.552 36.576 69.57 36.72 ;
    END
  END dq[534]
  PIN dq[535]
    DIRECTION OUTPUT ;
    USE SIGNAL ;
    PORT
      LAYER M5 ;
        RECT  69.648 36.528 69.672 36.72 ;
    END
  END dq[535]
  PIN dq[536]
    DIRECTION OUTPUT ;
    USE SIGNAL ;
    PORT
      LAYER M3 ;
        RECT  69.804 36.576 69.822 36.72 ;
    END
  END dq[536]
  PIN dq[537]
    DIRECTION OUTPUT ;
    USE SIGNAL ;
    PORT
      LAYER M5 ;
        RECT  69.888 36.528 69.912 36.72 ;
    END
  END dq[537]
  PIN dq[538]
    DIRECTION OUTPUT ;
    USE SIGNAL ;
    PORT
      LAYER M3 ;
        RECT  70.02 36.576 70.038 36.72 ;
    END
  END dq[538]
  PIN dq[539]
    DIRECTION OUTPUT ;
    USE SIGNAL ;
    PORT
      LAYER M5 ;
        RECT  70.176 36.528 70.2 36.72 ;
    END
  END dq[539]
  PIN dq[53]
    DIRECTION OUTPUT ;
    USE SIGNAL ;
    PORT
      LAYER M5 ;
        RECT  10.848 36.528 10.872 36.72 ;
    END
  END dq[53]
  PIN dq[540]
    DIRECTION OUTPUT ;
    USE SIGNAL ;
    PORT
      LAYER M3 ;
        RECT  70.272 36.576 70.29 36.72 ;
    END
  END dq[540]
  PIN dq[541]
    DIRECTION OUTPUT ;
    USE SIGNAL ;
    PORT
      LAYER M5 ;
        RECT  70.416 36.528 70.44 36.72 ;
    END
  END dq[541]
  PIN dq[542]
    DIRECTION OUTPUT ;
    USE SIGNAL ;
    PORT
      LAYER M3 ;
        RECT  70.524 36.576 70.542 36.72 ;
    END
  END dq[542]
  PIN dq[543]
    DIRECTION OUTPUT ;
    USE SIGNAL ;
    PORT
      LAYER M5 ;
        RECT  70.656 36.528 70.68 36.72 ;
    END
  END dq[543]
  PIN dq[544]
    DIRECTION OUTPUT ;
    USE SIGNAL ;
    PORT
      LAYER M3 ;
        RECT  70.776 36.576 70.794 36.72 ;
    END
  END dq[544]
  PIN dq[545]
    DIRECTION OUTPUT ;
    USE SIGNAL ;
    PORT
      LAYER M5 ;
        RECT  70.896 36.528 70.92 36.72 ;
    END
  END dq[545]
  PIN dq[546]
    DIRECTION OUTPUT ;
    USE SIGNAL ;
    PORT
      LAYER M3 ;
        RECT  71.028 36.576 71.046 36.72 ;
    END
  END dq[546]
  PIN dq[547]
    DIRECTION OUTPUT ;
    USE SIGNAL ;
    PORT
      LAYER M5 ;
        RECT  71.136 36.528 71.16 36.72 ;
    END
  END dq[547]
  PIN dq[548]
    DIRECTION OUTPUT ;
    USE SIGNAL ;
    PORT
      LAYER M3 ;
        RECT  71.244 36.576 71.262 36.72 ;
    END
  END dq[548]
  PIN dq[549]
    DIRECTION OUTPUT ;
    USE SIGNAL ;
    PORT
      LAYER M5 ;
        RECT  71.376 36.528 71.4 36.72 ;
    END
  END dq[549]
  PIN dq[54]
    DIRECTION OUTPUT ;
    USE SIGNAL ;
    PORT
      LAYER M3 ;
        RECT  10.98 36.576 10.998 36.72 ;
    END
  END dq[54]
  PIN dq[550]
    DIRECTION OUTPUT ;
    USE SIGNAL ;
    PORT
      LAYER M3 ;
        RECT  71.496 36.576 71.514 36.72 ;
    END
  END dq[550]
  PIN dq[551]
    DIRECTION OUTPUT ;
    USE SIGNAL ;
    PORT
      LAYER M5 ;
        RECT  71.616 36.528 71.64 36.72 ;
    END
  END dq[551]
  PIN dq[552]
    DIRECTION OUTPUT ;
    USE SIGNAL ;
    PORT
      LAYER M3 ;
        RECT  71.748 36.576 71.766 36.72 ;
    END
  END dq[552]
  PIN dq[553]
    DIRECTION OUTPUT ;
    USE SIGNAL ;
    PORT
      LAYER M5 ;
        RECT  71.856 36.528 71.88 36.72 ;
    END
  END dq[553]
  PIN dq[554]
    DIRECTION OUTPUT ;
    USE SIGNAL ;
    PORT
      LAYER M3 ;
        RECT  72 36.576 72.018 36.72 ;
    END
  END dq[554]
  PIN dq[555]
    DIRECTION OUTPUT ;
    USE SIGNAL ;
    PORT
      LAYER M5 ;
        RECT  72.096 36.528 72.12 36.72 ;
    END
  END dq[555]
  PIN dq[556]
    DIRECTION OUTPUT ;
    USE SIGNAL ;
    PORT
      LAYER M3 ;
        RECT  72.216 36.576 72.234 36.72 ;
    END
  END dq[556]
  PIN dq[557]
    DIRECTION OUTPUT ;
    USE SIGNAL ;
    PORT
      LAYER M5 ;
        RECT  72.336 36.528 72.36 36.72 ;
    END
  END dq[557]
  PIN dq[558]
    DIRECTION OUTPUT ;
    USE SIGNAL ;
    PORT
      LAYER M3 ;
        RECT  72.468 36.576 72.486 36.72 ;
    END
  END dq[558]
  PIN dq[559]
    DIRECTION OUTPUT ;
    USE SIGNAL ;
    PORT
      LAYER M5 ;
        RECT  72.576 36.528 72.6 36.72 ;
    END
  END dq[559]
  PIN dq[55]
    DIRECTION OUTPUT ;
    USE SIGNAL ;
    PORT
      LAYER M5 ;
        RECT  11.088 36.528 11.112 36.72 ;
    END
  END dq[55]
  PIN dq[560]
    DIRECTION OUTPUT ;
    USE SIGNAL ;
    PORT
      LAYER M3 ;
        RECT  72.72 36.576 72.738 36.72 ;
    END
  END dq[560]
  PIN dq[561]
    DIRECTION OUTPUT ;
    USE SIGNAL ;
    PORT
      LAYER M5 ;
        RECT  72.816 36.528 72.84 36.72 ;
    END
  END dq[561]
  PIN dq[562]
    DIRECTION OUTPUT ;
    USE SIGNAL ;
    PORT
      LAYER M3 ;
        RECT  72.972 36.576 72.99 36.72 ;
    END
  END dq[562]
  PIN dq[563]
    DIRECTION OUTPUT ;
    USE SIGNAL ;
    PORT
      LAYER M5 ;
        RECT  73.104 36.528 73.128 36.72 ;
    END
  END dq[563]
  PIN dq[564]
    DIRECTION OUTPUT ;
    USE SIGNAL ;
    PORT
      LAYER M3 ;
        RECT  73.224 36.576 73.242 36.72 ;
    END
  END dq[564]
  PIN dq[565]
    DIRECTION OUTPUT ;
    USE SIGNAL ;
    PORT
      LAYER M5 ;
        RECT  73.344 36.528 73.368 36.72 ;
    END
  END dq[565]
  PIN dq[566]
    DIRECTION OUTPUT ;
    USE SIGNAL ;
    PORT
      LAYER M3 ;
        RECT  73.44 36.576 73.458 36.72 ;
    END
  END dq[566]
  PIN dq[567]
    DIRECTION OUTPUT ;
    USE SIGNAL ;
    PORT
      LAYER M5 ;
        RECT  73.584 36.528 73.608 36.72 ;
    END
  END dq[567]
  PIN dq[568]
    DIRECTION OUTPUT ;
    USE SIGNAL ;
    PORT
      LAYER M3 ;
        RECT  73.692 36.576 73.71 36.72 ;
    END
  END dq[568]
  PIN dq[569]
    DIRECTION OUTPUT ;
    USE SIGNAL ;
    PORT
      LAYER M5 ;
        RECT  73.824 36.528 73.848 36.72 ;
    END
  END dq[569]
  PIN dq[56]
    DIRECTION OUTPUT ;
    USE SIGNAL ;
    PORT
      LAYER M3 ;
        RECT  11.196 36.576 11.214 36.72 ;
    END
  END dq[56]
  PIN dq[570]
    DIRECTION OUTPUT ;
    USE SIGNAL ;
    PORT
      LAYER M3 ;
        RECT  73.944 36.576 73.962 36.72 ;
    END
  END dq[570]
  PIN dq[571]
    DIRECTION OUTPUT ;
    USE SIGNAL ;
    PORT
      LAYER M5 ;
        RECT  74.064 36.528 74.088 36.72 ;
    END
  END dq[571]
  PIN dq[572]
    DIRECTION OUTPUT ;
    USE SIGNAL ;
    PORT
      LAYER M3 ;
        RECT  74.196 36.576 74.214 36.72 ;
    END
  END dq[572]
  PIN dq[573]
    DIRECTION OUTPUT ;
    USE SIGNAL ;
    PORT
      LAYER M5 ;
        RECT  74.304 36.528 74.328 36.72 ;
    END
  END dq[573]
  PIN dq[574]
    DIRECTION OUTPUT ;
    USE SIGNAL ;
    PORT
      LAYER M3 ;
        RECT  74.412 36.576 74.43 36.72 ;
    END
  END dq[574]
  PIN dq[575]
    DIRECTION OUTPUT ;
    USE SIGNAL ;
    PORT
      LAYER M5 ;
        RECT  74.544 36.528 74.568 36.72 ;
    END
  END dq[575]
  PIN dq[576]
    DIRECTION OUTPUT ;
    USE SIGNAL ;
    PORT
      LAYER M3 ;
        RECT  74.664 36.576 74.682 36.72 ;
    END
  END dq[576]
  PIN dq[577]
    DIRECTION OUTPUT ;
    USE SIGNAL ;
    PORT
      LAYER M5 ;
        RECT  74.784 36.528 74.808 36.72 ;
    END
  END dq[577]
  PIN dq[578]
    DIRECTION OUTPUT ;
    USE SIGNAL ;
    PORT
      LAYER M3 ;
        RECT  74.916 36.576 74.934 36.72 ;
    END
  END dq[578]
  PIN dq[579]
    DIRECTION OUTPUT ;
    USE SIGNAL ;
    PORT
      LAYER M5 ;
        RECT  75.024 36.528 75.048 36.72 ;
    END
  END dq[579]
  PIN dq[57]
    DIRECTION OUTPUT ;
    USE SIGNAL ;
    PORT
      LAYER M5 ;
        RECT  11.328 36.528 11.352 36.72 ;
    END
  END dq[57]
  PIN dq[580]
    DIRECTION OUTPUT ;
    USE SIGNAL ;
    PORT
      LAYER M3 ;
        RECT  75.168 36.576 75.186 36.72 ;
    END
  END dq[580]
  PIN dq[581]
    DIRECTION OUTPUT ;
    USE SIGNAL ;
    PORT
      LAYER M5 ;
        RECT  75.264 36.528 75.288 36.72 ;
    END
  END dq[581]
  PIN dq[582]
    DIRECTION OUTPUT ;
    USE SIGNAL ;
    PORT
      LAYER M3 ;
        RECT  75.42 36.576 75.438 36.72 ;
    END
  END dq[582]
  PIN dq[583]
    DIRECTION OUTPUT ;
    USE SIGNAL ;
    PORT
      LAYER M5 ;
        RECT  75.504 36.528 75.528 36.72 ;
    END
  END dq[583]
  PIN dq[584]
    DIRECTION OUTPUT ;
    USE SIGNAL ;
    PORT
      LAYER M3 ;
        RECT  75.636 36.576 75.654 36.72 ;
    END
  END dq[584]
  PIN dq[585]
    DIRECTION OUTPUT ;
    USE SIGNAL ;
    PORT
      LAYER M5 ;
        RECT  75.792 36.528 75.816 36.72 ;
    END
  END dq[585]
  PIN dq[586]
    DIRECTION OUTPUT ;
    USE SIGNAL ;
    PORT
      LAYER M3 ;
        RECT  75.888 36.576 75.906 36.72 ;
    END
  END dq[586]
  PIN dq[587]
    DIRECTION OUTPUT ;
    USE SIGNAL ;
    PORT
      LAYER M5 ;
        RECT  76.032 36.528 76.056 36.72 ;
    END
  END dq[587]
  PIN dq[588]
    DIRECTION OUTPUT ;
    USE SIGNAL ;
    PORT
      LAYER M3 ;
        RECT  76.14 36.576 76.158 36.72 ;
    END
  END dq[588]
  PIN dq[589]
    DIRECTION OUTPUT ;
    USE SIGNAL ;
    PORT
      LAYER M5 ;
        RECT  76.272 36.528 76.296 36.72 ;
    END
  END dq[589]
  PIN dq[58]
    DIRECTION OUTPUT ;
    USE SIGNAL ;
    PORT
      LAYER M3 ;
        RECT  11.448 36.576 11.466 36.72 ;
    END
  END dq[58]
  PIN dq[590]
    DIRECTION OUTPUT ;
    USE SIGNAL ;
    PORT
      LAYER M3 ;
        RECT  76.392 36.576 76.41 36.72 ;
    END
  END dq[590]
  PIN dq[591]
    DIRECTION OUTPUT ;
    USE SIGNAL ;
    PORT
      LAYER M5 ;
        RECT  76.512 36.528 76.536 36.72 ;
    END
  END dq[591]
  PIN dq[592]
    DIRECTION OUTPUT ;
    USE SIGNAL ;
    PORT
      LAYER M3 ;
        RECT  76.608 36.576 76.626 36.72 ;
    END
  END dq[592]
  PIN dq[593]
    DIRECTION OUTPUT ;
    USE SIGNAL ;
    PORT
      LAYER M5 ;
        RECT  76.752 36.528 76.776 36.72 ;
    END
  END dq[593]
  PIN dq[594]
    DIRECTION OUTPUT ;
    USE SIGNAL ;
    PORT
      LAYER M3 ;
        RECT  76.86 36.576 76.878 36.72 ;
    END
  END dq[594]
  PIN dq[595]
    DIRECTION OUTPUT ;
    USE SIGNAL ;
    PORT
      LAYER M5 ;
        RECT  76.992 36.528 77.016 36.72 ;
    END
  END dq[595]
  PIN dq[596]
    DIRECTION OUTPUT ;
    USE SIGNAL ;
    PORT
      LAYER M3 ;
        RECT  77.112 36.576 77.13 36.72 ;
    END
  END dq[596]
  PIN dq[597]
    DIRECTION OUTPUT ;
    USE SIGNAL ;
    PORT
      LAYER M5 ;
        RECT  77.232 36.528 77.256 36.72 ;
    END
  END dq[597]
  PIN dq[598]
    DIRECTION OUTPUT ;
    USE SIGNAL ;
    PORT
      LAYER M3 ;
        RECT  77.364 36.576 77.382 36.72 ;
    END
  END dq[598]
  PIN dq[599]
    DIRECTION OUTPUT ;
    USE SIGNAL ;
    PORT
      LAYER M5 ;
        RECT  77.472 36.528 77.496 36.72 ;
    END
  END dq[599]
  PIN dq[59]
    DIRECTION OUTPUT ;
    USE SIGNAL ;
    PORT
      LAYER M5 ;
        RECT  11.568 36.528 11.592 36.72 ;
    END
  END dq[59]
  PIN dq[5]
    DIRECTION OUTPUT ;
    USE SIGNAL ;
    PORT
      LAYER M5 ;
        RECT  4.992 36.528 5.016 36.72 ;
    END
  END dq[5]
  PIN dq[600]
    DIRECTION OUTPUT ;
    USE SIGNAL ;
    PORT
      LAYER M3 ;
        RECT  77.616 36.576 77.634 36.72 ;
    END
  END dq[600]
  PIN dq[601]
    DIRECTION OUTPUT ;
    USE SIGNAL ;
    PORT
      LAYER M5 ;
        RECT  77.712 36.528 77.736 36.72 ;
    END
  END dq[601]
  PIN dq[602]
    DIRECTION OUTPUT ;
    USE SIGNAL ;
    PORT
      LAYER M3 ;
        RECT  77.832 36.576 77.85 36.72 ;
    END
  END dq[602]
  PIN dq[603]
    DIRECTION OUTPUT ;
    USE SIGNAL ;
    PORT
      LAYER M5 ;
        RECT  77.952 36.528 77.976 36.72 ;
    END
  END dq[603]
  PIN dq[604]
    DIRECTION OUTPUT ;
    USE SIGNAL ;
    PORT
      LAYER M3 ;
        RECT  78.084 36.576 78.102 36.72 ;
    END
  END dq[604]
  PIN dq[605]
    DIRECTION OUTPUT ;
    USE SIGNAL ;
    PORT
      LAYER M5 ;
        RECT  78.192 36.528 78.216 36.72 ;
    END
  END dq[605]
  PIN dq[606]
    DIRECTION OUTPUT ;
    USE SIGNAL ;
    PORT
      LAYER M3 ;
        RECT  78.336 36.576 78.354 36.72 ;
    END
  END dq[606]
  PIN dq[607]
    DIRECTION OUTPUT ;
    USE SIGNAL ;
    PORT
      LAYER M5 ;
        RECT  78.432 36.528 78.456 36.72 ;
    END
  END dq[607]
  PIN dq[608]
    DIRECTION OUTPUT ;
    USE SIGNAL ;
    PORT
      LAYER M3 ;
        RECT  78.588 36.576 78.606 36.72 ;
    END
    PORT
      LAYER M3 ;
        RECT  78.516 36.588 78.642 36.653 ;
    END
  END dq[608]
  PIN dq[609]
    DIRECTION OUTPUT ;
    USE SIGNAL ;
    PORT
      LAYER M5 ;
        RECT  78.72 36.528 78.744 36.72 ;
    END
  END dq[609]
  PIN dq[60]
    DIRECTION OUTPUT ;
    USE SIGNAL ;
    PORT
      LAYER M3 ;
        RECT  11.7 36.576 11.718 36.72 ;
    END
  END dq[60]
  PIN dq[610]
    DIRECTION OUTPUT ;
    USE SIGNAL ;
    PORT
      LAYER M3 ;
        RECT  78.84 36.576 78.858 36.72 ;
    END
  END dq[610]
  PIN dq[611]
    DIRECTION OUTPUT ;
    USE SIGNAL ;
    PORT
      LAYER M5 ;
        RECT  78.96 36.528 78.984 36.72 ;
    END
  END dq[611]
  PIN dq[612]
    DIRECTION OUTPUT ;
    USE SIGNAL ;
    PORT
      LAYER M3 ;
        RECT  79.056 36.576 79.074 36.72 ;
    END
  END dq[612]
  PIN dq[613]
    DIRECTION OUTPUT ;
    USE SIGNAL ;
    PORT
      LAYER M5 ;
        RECT  79.2 36.528 79.224 36.72 ;
    END
  END dq[613]
  PIN dq[614]
    DIRECTION OUTPUT ;
    USE SIGNAL ;
    PORT
      LAYER M3 ;
        RECT  79.308 36.576 79.326 36.72 ;
    END
  END dq[614]
  PIN dq[615]
    DIRECTION OUTPUT ;
    USE SIGNAL ;
    PORT
      LAYER M5 ;
        RECT  79.44 36.528 79.464 36.72 ;
    END
  END dq[615]
  PIN dq[616]
    DIRECTION OUTPUT ;
    USE SIGNAL ;
    PORT
      LAYER M3 ;
        RECT  79.56 36.576 79.578 36.72 ;
    END
  END dq[616]
  PIN dq[617]
    DIRECTION OUTPUT ;
    USE SIGNAL ;
    PORT
      LAYER M5 ;
        RECT  79.68 36.528 79.704 36.72 ;
    END
  END dq[617]
  PIN dq[618]
    DIRECTION OUTPUT ;
    USE SIGNAL ;
    PORT
      LAYER M3 ;
        RECT  79.812 36.576 79.83 36.72 ;
    END
  END dq[618]
  PIN dq[619]
    DIRECTION OUTPUT ;
    USE SIGNAL ;
    PORT
      LAYER M5 ;
        RECT  79.92 36.528 79.944 36.72 ;
    END
  END dq[619]
  PIN dq[61]
    DIRECTION OUTPUT ;
    USE SIGNAL ;
    PORT
      LAYER M5 ;
        RECT  11.808 36.528 11.832 36.72 ;
    END
  END dq[61]
  PIN dq[620]
    DIRECTION OUTPUT ;
    USE SIGNAL ;
    PORT
      LAYER M3 ;
        RECT  80.028 36.576 80.046 36.72 ;
    END
  END dq[620]
  PIN dq[621]
    DIRECTION OUTPUT ;
    USE SIGNAL ;
    PORT
      LAYER M5 ;
        RECT  80.16 36.528 80.184 36.72 ;
    END
  END dq[621]
  PIN dq[622]
    DIRECTION OUTPUT ;
    USE SIGNAL ;
    PORT
      LAYER M3 ;
        RECT  80.28 36.576 80.298 36.72 ;
    END
  END dq[622]
  PIN dq[623]
    DIRECTION OUTPUT ;
    USE SIGNAL ;
    PORT
      LAYER M5 ;
        RECT  80.4 36.528 80.424 36.72 ;
    END
  END dq[623]
  PIN dq[624]
    DIRECTION OUTPUT ;
    USE SIGNAL ;
    PORT
      LAYER M3 ;
        RECT  80.532 36.576 80.55 36.72 ;
    END
  END dq[624]
  PIN dq[625]
    DIRECTION OUTPUT ;
    USE SIGNAL ;
    PORT
      LAYER M5 ;
        RECT  80.64 36.528 80.664 36.72 ;
    END
  END dq[625]
  PIN dq[626]
    DIRECTION OUTPUT ;
    USE SIGNAL ;
    PORT
      LAYER M3 ;
        RECT  80.784 36.576 80.802 36.72 ;
    END
  END dq[626]
  PIN dq[627]
    DIRECTION OUTPUT ;
    USE SIGNAL ;
    PORT
      LAYER M5 ;
        RECT  80.88 36.528 80.904 36.72 ;
    END
  END dq[627]
  PIN dq[628]
    DIRECTION OUTPUT ;
    USE SIGNAL ;
    PORT
      LAYER M3 ;
        RECT  81.036 36.576 81.054 36.72 ;
    END
  END dq[628]
  PIN dq[629]
    DIRECTION OUTPUT ;
    USE SIGNAL ;
    PORT
      LAYER M5 ;
        RECT  81.12 36.528 81.144 36.72 ;
    END
  END dq[629]
  PIN dq[62]
    DIRECTION OUTPUT ;
    USE SIGNAL ;
    PORT
      LAYER M3 ;
        RECT  11.952 36.576 11.97 36.72 ;
    END
  END dq[62]
  PIN dq[630]
    DIRECTION OUTPUT ;
    USE SIGNAL ;
    PORT
      LAYER M3 ;
        RECT  81.252 36.576 81.27 36.72 ;
    END
  END dq[630]
  PIN dq[631]
    DIRECTION OUTPUT ;
    USE SIGNAL ;
    PORT
      LAYER M5 ;
        RECT  81.36 36.528 81.384 36.72 ;
    END
  END dq[631]
  PIN dq[632]
    DIRECTION OUTPUT ;
    USE SIGNAL ;
    PORT
      LAYER M3 ;
        RECT  81.504 36.576 81.522 36.72 ;
    END
  END dq[632]
  PIN dq[633]
    DIRECTION OUTPUT ;
    USE SIGNAL ;
    PORT
      LAYER M5 ;
        RECT  81.648 36.528 81.672 36.72 ;
    END
  END dq[633]
  PIN dq[634]
    DIRECTION OUTPUT ;
    USE SIGNAL ;
    PORT
      LAYER M3 ;
        RECT  81.756 36.576 81.774 36.72 ;
    END
  END dq[634]
  PIN dq[635]
    DIRECTION OUTPUT ;
    USE SIGNAL ;
    PORT
      LAYER M5 ;
        RECT  81.888 36.528 81.912 36.72 ;
    END
  END dq[635]
  PIN dq[636]
    DIRECTION OUTPUT ;
    USE SIGNAL ;
    PORT
      LAYER M3 ;
        RECT  82.008 36.576 82.026 36.72 ;
    END
  END dq[636]
  PIN dq[637]
    DIRECTION OUTPUT ;
    USE SIGNAL ;
    PORT
      LAYER M5 ;
        RECT  82.128 36.528 82.152 36.72 ;
    END
  END dq[637]
  PIN dq[638]
    DIRECTION OUTPUT ;
    USE SIGNAL ;
    PORT
      LAYER M3 ;
        RECT  82.224 36.576 82.242 36.72 ;
    END
  END dq[638]
  PIN dq[639]
    DIRECTION OUTPUT ;
    USE SIGNAL ;
    PORT
      LAYER M5 ;
        RECT  82.368 36.528 82.392 36.72 ;
    END
  END dq[639]
  PIN dq[63]
    DIRECTION OUTPUT ;
    USE SIGNAL ;
    PORT
      LAYER M5 ;
        RECT  12.048 36.528 12.072 36.72 ;
    END
  END dq[63]
  PIN dq[640]
    DIRECTION OUTPUT ;
    USE SIGNAL ;
    PORT
      LAYER M3 ;
        RECT  82.476 36.576 82.494 36.72 ;
    END
  END dq[640]
  PIN dq[641]
    DIRECTION OUTPUT ;
    USE SIGNAL ;
    PORT
      LAYER M5 ;
        RECT  82.608 36.528 82.632 36.72 ;
    END
  END dq[641]
  PIN dq[642]
    DIRECTION OUTPUT ;
    USE SIGNAL ;
    PORT
      LAYER M3 ;
        RECT  82.728 36.576 82.746 36.72 ;
    END
  END dq[642]
  PIN dq[643]
    DIRECTION OUTPUT ;
    USE SIGNAL ;
    PORT
      LAYER M5 ;
        RECT  82.848 36.528 82.872 36.72 ;
    END
  END dq[643]
  PIN dq[644]
    DIRECTION OUTPUT ;
    USE SIGNAL ;
    PORT
      LAYER M3 ;
        RECT  82.98 36.576 82.998 36.72 ;
    END
  END dq[644]
  PIN dq[645]
    DIRECTION OUTPUT ;
    USE SIGNAL ;
    PORT
      LAYER M5 ;
        RECT  83.088 36.528 83.112 36.72 ;
    END
  END dq[645]
  PIN dq[646]
    DIRECTION OUTPUT ;
    USE SIGNAL ;
    PORT
      LAYER M3 ;
        RECT  83.232 36.576 83.25 36.72 ;
    END
  END dq[646]
  PIN dq[647]
    DIRECTION OUTPUT ;
    USE SIGNAL ;
    PORT
      LAYER M5 ;
        RECT  83.328 36.528 83.352 36.72 ;
    END
  END dq[647]
  PIN dq[648]
    DIRECTION OUTPUT ;
    USE SIGNAL ;
    PORT
      LAYER M3 ;
        RECT  83.448 36.576 83.466 36.72 ;
    END
  END dq[648]
  PIN dq[649]
    DIRECTION OUTPUT ;
    USE SIGNAL ;
    PORT
      LAYER M5 ;
        RECT  83.568 36.528 83.592 36.72 ;
    END
  END dq[649]
  PIN dq[64]
    DIRECTION OUTPUT ;
    USE SIGNAL ;
    PORT
      LAYER M3 ;
        RECT  12.168 36.576 12.186 36.72 ;
    END
  END dq[64]
  PIN dq[650]
    DIRECTION OUTPUT ;
    USE SIGNAL ;
    PORT
      LAYER M3 ;
        RECT  83.7 36.576 83.718 36.72 ;
    END
  END dq[650]
  PIN dq[651]
    DIRECTION OUTPUT ;
    USE SIGNAL ;
    PORT
      LAYER M5 ;
        RECT  83.808 36.528 83.832 36.72 ;
    END
  END dq[651]
  PIN dq[652]
    DIRECTION OUTPUT ;
    USE SIGNAL ;
    PORT
      LAYER M3 ;
        RECT  83.952 36.576 83.97 36.72 ;
    END
  END dq[652]
  PIN dq[653]
    DIRECTION OUTPUT ;
    USE SIGNAL ;
    PORT
      LAYER M5 ;
        RECT  84.048 36.528 84.072 36.72 ;
    END
  END dq[653]
  PIN dq[654]
    DIRECTION OUTPUT ;
    USE SIGNAL ;
    PORT
      LAYER M3 ;
        RECT  84.204 36.576 84.222 36.72 ;
    END
  END dq[654]
  PIN dq[655]
    DIRECTION OUTPUT ;
    USE SIGNAL ;
    PORT
      LAYER M5 ;
        RECT  84.288 36.528 84.312 36.72 ;
    END
  END dq[655]
  PIN dq[656]
    DIRECTION OUTPUT ;
    USE SIGNAL ;
    PORT
      LAYER M3 ;
        RECT  84.42 36.576 84.438 36.72 ;
    END
  END dq[656]
  PIN dq[657]
    DIRECTION OUTPUT ;
    USE SIGNAL ;
    PORT
      LAYER M5 ;
        RECT  84.576 36.528 84.6 36.72 ;
    END
  END dq[657]
  PIN dq[658]
    DIRECTION OUTPUT ;
    USE SIGNAL ;
    PORT
      LAYER M3 ;
        RECT  84.672 36.576 84.69 36.72 ;
    END
  END dq[658]
  PIN dq[659]
    DIRECTION OUTPUT ;
    USE SIGNAL ;
    PORT
      LAYER M5 ;
        RECT  84.816 36.528 84.84 36.72 ;
    END
  END dq[659]
  PIN dq[65]
    DIRECTION OUTPUT ;
    USE SIGNAL ;
    PORT
      LAYER M5 ;
        RECT  12.288 36.528 12.312 36.72 ;
    END
  END dq[65]
  PIN dq[660]
    DIRECTION OUTPUT ;
    USE SIGNAL ;
    PORT
      LAYER M3 ;
        RECT  84.924 36.576 84.942 36.72 ;
    END
  END dq[660]
  PIN dq[661]
    DIRECTION OUTPUT ;
    USE SIGNAL ;
    PORT
      LAYER M5 ;
        RECT  85.056 36.528 85.08 36.72 ;
    END
  END dq[661]
  PIN dq[662]
    DIRECTION OUTPUT ;
    USE SIGNAL ;
    PORT
      LAYER M3 ;
        RECT  85.176 36.576 85.194 36.72 ;
    END
  END dq[662]
  PIN dq[663]
    DIRECTION OUTPUT ;
    USE SIGNAL ;
    PORT
      LAYER M5 ;
        RECT  85.296 36.528 85.32 36.72 ;
    END
  END dq[663]
  PIN dq[664]
    DIRECTION OUTPUT ;
    USE SIGNAL ;
    PORT
      LAYER M3 ;
        RECT  85.428 36.576 85.446 36.72 ;
    END
  END dq[664]
  PIN dq[665]
    DIRECTION OUTPUT ;
    USE SIGNAL ;
    PORT
      LAYER M5 ;
        RECT  85.536 36.528 85.56 36.72 ;
    END
  END dq[665]
  PIN dq[666]
    DIRECTION OUTPUT ;
    USE SIGNAL ;
    PORT
      LAYER M3 ;
        RECT  85.644 36.576 85.662 36.72 ;
    END
  END dq[666]
  PIN dq[667]
    DIRECTION OUTPUT ;
    USE SIGNAL ;
    PORT
      LAYER M5 ;
        RECT  85.776 36.528 85.8 36.72 ;
    END
  END dq[667]
  PIN dq[668]
    DIRECTION OUTPUT ;
    USE SIGNAL ;
    PORT
      LAYER M3 ;
        RECT  85.896 36.576 85.914 36.72 ;
    END
  END dq[668]
  PIN dq[669]
    DIRECTION OUTPUT ;
    USE SIGNAL ;
    PORT
      LAYER M5 ;
        RECT  86.016 36.528 86.04 36.72 ;
    END
  END dq[669]
  PIN dq[66]
    DIRECTION OUTPUT ;
    USE SIGNAL ;
    PORT
      LAYER M3 ;
        RECT  12.42 36.576 12.438 36.72 ;
    END
  END dq[66]
  PIN dq[670]
    DIRECTION OUTPUT ;
    USE SIGNAL ;
    PORT
      LAYER M3 ;
        RECT  86.148 36.576 86.166 36.72 ;
    END
  END dq[670]
  PIN dq[671]
    DIRECTION OUTPUT ;
    USE SIGNAL ;
    PORT
      LAYER M5 ;
        RECT  86.256 36.528 86.28 36.72 ;
    END
  END dq[671]
  PIN dq[672]
    DIRECTION OUTPUT ;
    USE SIGNAL ;
    PORT
      LAYER M3 ;
        RECT  86.4 36.576 86.418 36.72 ;
    END
  END dq[672]
  PIN dq[673]
    DIRECTION OUTPUT ;
    USE SIGNAL ;
    PORT
      LAYER M5 ;
        RECT  86.496 36.528 86.52 36.72 ;
    END
  END dq[673]
  PIN dq[674]
    DIRECTION OUTPUT ;
    USE SIGNAL ;
    PORT
      LAYER M3 ;
        RECT  86.616 36.576 86.634 36.72 ;
    END
  END dq[674]
  PIN dq[675]
    DIRECTION OUTPUT ;
    USE SIGNAL ;
    PORT
      LAYER M5 ;
        RECT  86.736 36.528 86.76 36.72 ;
    END
  END dq[675]
  PIN dq[676]
    DIRECTION OUTPUT ;
    USE SIGNAL ;
    PORT
      LAYER M3 ;
        RECT  86.868 36.576 86.886 36.72 ;
    END
  END dq[676]
  PIN dq[677]
    DIRECTION OUTPUT ;
    USE SIGNAL ;
    PORT
      LAYER M5 ;
        RECT  86.976 36.528 87 36.72 ;
    END
  END dq[677]
  PIN dq[678]
    DIRECTION OUTPUT ;
    USE SIGNAL ;
    PORT
      LAYER M3 ;
        RECT  87.12 36.576 87.138 36.72 ;
    END
  END dq[678]
  PIN dq[679]
    DIRECTION OUTPUT ;
    USE SIGNAL ;
    PORT
      LAYER M5 ;
        RECT  87.264 36.528 87.288 36.72 ;
    END
  END dq[679]
  PIN dq[67]
    DIRECTION OUTPUT ;
    USE SIGNAL ;
    PORT
      LAYER M5 ;
        RECT  12.528 36.528 12.552 36.72 ;
    END
  END dq[67]
  PIN dq[680]
    DIRECTION OUTPUT ;
    USE SIGNAL ;
    PORT
      LAYER M3 ;
        RECT  87.372 36.576 87.39 36.72 ;
    END
  END dq[680]
  PIN dq[681]
    DIRECTION OUTPUT ;
    USE SIGNAL ;
    PORT
      LAYER M5 ;
        RECT  87.504 36.528 87.528 36.72 ;
    END
  END dq[681]
  PIN dq[682]
    DIRECTION OUTPUT ;
    USE SIGNAL ;
    PORT
      LAYER M3 ;
        RECT  87.624 36.576 87.642 36.72 ;
    END
  END dq[682]
  PIN dq[683]
    DIRECTION OUTPUT ;
    USE SIGNAL ;
    PORT
      LAYER M5 ;
        RECT  87.744 36.528 87.768 36.72 ;
    END
  END dq[683]
  PIN dq[684]
    DIRECTION OUTPUT ;
    USE SIGNAL ;
    PORT
      LAYER M3 ;
        RECT  87.84 36.576 87.858 36.72 ;
    END
  END dq[684]
  PIN dq[685]
    DIRECTION OUTPUT ;
    USE SIGNAL ;
    PORT
      LAYER M5 ;
        RECT  87.984 36.528 88.008 36.72 ;
    END
  END dq[685]
  PIN dq[686]
    DIRECTION OUTPUT ;
    USE SIGNAL ;
    PORT
      LAYER M3 ;
        RECT  88.092 36.576 88.11 36.72 ;
    END
  END dq[686]
  PIN dq[687]
    DIRECTION OUTPUT ;
    USE SIGNAL ;
    PORT
      LAYER M5 ;
        RECT  88.224 36.528 88.248 36.72 ;
    END
  END dq[687]
  PIN dq[688]
    DIRECTION OUTPUT ;
    USE SIGNAL ;
    PORT
      LAYER M3 ;
        RECT  88.344 36.576 88.362 36.72 ;
    END
  END dq[688]
  PIN dq[689]
    DIRECTION OUTPUT ;
    USE SIGNAL ;
    PORT
      LAYER M5 ;
        RECT  88.464 36.528 88.488 36.72 ;
    END
  END dq[689]
  PIN dq[68]
    DIRECTION OUTPUT ;
    USE SIGNAL ;
    PORT
      LAYER M3 ;
        RECT  12.672 36.576 12.69 36.72 ;
    END
  END dq[68]
  PIN dq[690]
    DIRECTION OUTPUT ;
    USE SIGNAL ;
    PORT
      LAYER M3 ;
        RECT  88.596 36.576 88.614 36.72 ;
    END
  END dq[690]
  PIN dq[691]
    DIRECTION OUTPUT ;
    USE SIGNAL ;
    PORT
      LAYER M5 ;
        RECT  88.704 36.528 88.728 36.72 ;
    END
  END dq[691]
  PIN dq[692]
    DIRECTION OUTPUT ;
    USE SIGNAL ;
    PORT
      LAYER M3 ;
        RECT  88.848 36.576 88.866 36.72 ;
    END
  END dq[692]
  PIN dq[693]
    DIRECTION OUTPUT ;
    USE SIGNAL ;
    PORT
      LAYER M5 ;
        RECT  88.944 36.528 88.968 36.72 ;
    END
  END dq[693]
  PIN dq[694]
    DIRECTION OUTPUT ;
    USE SIGNAL ;
    PORT
      LAYER M3 ;
        RECT  89.064 36.576 89.082 36.72 ;
    END
  END dq[694]
  PIN dq[695]
    DIRECTION OUTPUT ;
    USE SIGNAL ;
    PORT
      LAYER M5 ;
        RECT  89.184 36.528 89.208 36.72 ;
    END
  END dq[695]
  PIN dq[696]
    DIRECTION OUTPUT ;
    USE SIGNAL ;
    PORT
      LAYER M3 ;
        RECT  89.316 36.576 89.334 36.72 ;
    END
  END dq[696]
  PIN dq[697]
    DIRECTION OUTPUT ;
    USE SIGNAL ;
    PORT
      LAYER M5 ;
        RECT  89.424 36.528 89.448 36.72 ;
    END
  END dq[697]
  PIN dq[698]
    DIRECTION OUTPUT ;
    USE SIGNAL ;
    PORT
      LAYER M3 ;
        RECT  89.568 36.576 89.586 36.72 ;
    END
  END dq[698]
  PIN dq[699]
    DIRECTION OUTPUT ;
    USE SIGNAL ;
    PORT
      LAYER M5 ;
        RECT  89.664 36.528 89.688 36.72 ;
    END
  END dq[699]
  PIN dq[69]
    DIRECTION OUTPUT ;
    USE SIGNAL ;
    PORT
      LAYER M5 ;
        RECT  12.768 36.528 12.792 36.72 ;
    END
  END dq[69]
  PIN dq[6]
    DIRECTION OUTPUT ;
    USE SIGNAL ;
    PORT
      LAYER M3 ;
        RECT  5.112 36.576 5.13 36.72 ;
    END
  END dq[6]
  PIN dq[700]
    DIRECTION OUTPUT ;
    USE SIGNAL ;
    PORT
      LAYER M3 ;
        RECT  89.82 36.576 89.838 36.72 ;
    END
  END dq[700]
  PIN dq[701]
    DIRECTION OUTPUT ;
    USE SIGNAL ;
    PORT
      LAYER M5 ;
        RECT  89.904 36.528 89.928 36.72 ;
    END
  END dq[701]
  PIN dq[702]
    DIRECTION OUTPUT ;
    USE SIGNAL ;
    PORT
      LAYER M3 ;
        RECT  90.036 36.576 90.054 36.72 ;
    END
  END dq[702]
  PIN dq[703]
    DIRECTION OUTPUT ;
    USE SIGNAL ;
    PORT
      LAYER M5 ;
        RECT  90.192 36.528 90.216 36.72 ;
    END
  END dq[703]
  PIN dq[704]
    DIRECTION OUTPUT ;
    USE SIGNAL ;
    PORT
      LAYER M3 ;
        RECT  90.288 36.576 90.306 36.72 ;
    END
  END dq[704]
  PIN dq[705]
    DIRECTION OUTPUT ;
    USE SIGNAL ;
    PORT
      LAYER M5 ;
        RECT  90.432 36.528 90.456 36.72 ;
    END
  END dq[705]
  PIN dq[706]
    DIRECTION OUTPUT ;
    USE SIGNAL ;
    PORT
      LAYER M3 ;
        RECT  90.54 36.576 90.558 36.72 ;
    END
  END dq[706]
  PIN dq[707]
    DIRECTION OUTPUT ;
    USE SIGNAL ;
    PORT
      LAYER M5 ;
        RECT  90.672 36.528 90.696 36.72 ;
    END
  END dq[707]
  PIN dq[708]
    DIRECTION OUTPUT ;
    USE SIGNAL ;
    PORT
      LAYER M3 ;
        RECT  90.792 36.576 90.81 36.72 ;
    END
  END dq[708]
  PIN dq[709]
    DIRECTION OUTPUT ;
    USE SIGNAL ;
    PORT
      LAYER M5 ;
        RECT  90.912 36.528 90.936 36.72 ;
    END
  END dq[709]
  PIN dq[70]
    DIRECTION OUTPUT ;
    USE SIGNAL ;
    PORT
      LAYER M3 ;
        RECT  12.924 36.576 12.942 36.72 ;
    END
  END dq[70]
  PIN dq[710]
    DIRECTION OUTPUT ;
    USE SIGNAL ;
    PORT
      LAYER M3 ;
        RECT  91.044 36.576 91.062 36.72 ;
    END
  END dq[710]
  PIN dq[711]
    DIRECTION OUTPUT ;
    USE SIGNAL ;
    PORT
      LAYER M5 ;
        RECT  91.152 36.528 91.176 36.72 ;
    END
  END dq[711]
  PIN dq[712]
    DIRECTION OUTPUT ;
    USE SIGNAL ;
    PORT
      LAYER M3 ;
        RECT  91.26 36.576 91.278 36.72 ;
    END
  END dq[712]
  PIN dq[713]
    DIRECTION OUTPUT ;
    USE SIGNAL ;
    PORT
      LAYER M5 ;
        RECT  91.392 36.528 91.416 36.72 ;
    END
  END dq[713]
  PIN dq[714]
    DIRECTION OUTPUT ;
    USE SIGNAL ;
    PORT
      LAYER M3 ;
        RECT  91.512 36.576 91.53 36.72 ;
    END
    PORT
      LAYER M3 ;
        RECT  91.476 36.588 91.602 36.653 ;
    END
  END dq[714]
  PIN dq[715]
    DIRECTION OUTPUT ;
    USE SIGNAL ;
    PORT
      LAYER M5 ;
        RECT  91.632 36.528 91.656 36.72 ;
    END
  END dq[715]
  PIN dq[716]
    DIRECTION OUTPUT ;
    USE SIGNAL ;
    PORT
      LAYER M3 ;
        RECT  91.764 36.576 91.782 36.72 ;
    END
  END dq[716]
  PIN dq[717]
    DIRECTION OUTPUT ;
    USE SIGNAL ;
    PORT
      LAYER M5 ;
        RECT  91.872 36.528 91.896 36.72 ;
    END
  END dq[717]
  PIN dq[718]
    DIRECTION OUTPUT ;
    USE SIGNAL ;
    PORT
      LAYER M3 ;
        RECT  92.016 36.576 92.034 36.72 ;
    END
  END dq[718]
  PIN dq[719]
    DIRECTION OUTPUT ;
    USE SIGNAL ;
    PORT
      LAYER M5 ;
        RECT  92.112 36.528 92.136 36.72 ;
    END
  END dq[719]
  PIN dq[71]
    DIRECTION OUTPUT ;
    USE SIGNAL ;
    PORT
      LAYER M5 ;
        RECT  13.056 36.528 13.08 36.72 ;
    END
  END dq[71]
  PIN dq[720]
    DIRECTION OUTPUT ;
    USE SIGNAL ;
    PORT
      LAYER M3 ;
        RECT  92.232 36.576 92.25 36.72 ;
    END
  END dq[720]
  PIN dq[721]
    DIRECTION OUTPUT ;
    USE SIGNAL ;
    PORT
      LAYER M5 ;
        RECT  92.352 36.528 92.376 36.72 ;
    END
  END dq[721]
  PIN dq[722]
    DIRECTION OUTPUT ;
    USE SIGNAL ;
    PORT
      LAYER M3 ;
        RECT  92.484 36.576 92.502 36.72 ;
    END
  END dq[722]
  PIN dq[723]
    DIRECTION OUTPUT ;
    USE SIGNAL ;
    PORT
      LAYER M5 ;
        RECT  92.592 36.528 92.616 36.72 ;
    END
  END dq[723]
  PIN dq[724]
    DIRECTION OUTPUT ;
    USE SIGNAL ;
    PORT
      LAYER M3 ;
        RECT  92.736 36.576 92.754 36.72 ;
    END
  END dq[724]
  PIN dq[725]
    DIRECTION OUTPUT ;
    USE SIGNAL ;
    PORT
      LAYER M5 ;
        RECT  92.832 36.528 92.856 36.72 ;
    END
  END dq[725]
  PIN dq[726]
    DIRECTION OUTPUT ;
    USE SIGNAL ;
    PORT
      LAYER M3 ;
        RECT  92.988 36.576 93.006 36.72 ;
    END
  END dq[726]
  PIN dq[727]
    DIRECTION OUTPUT ;
    USE SIGNAL ;
    PORT
      LAYER M5 ;
        RECT  93.12 36.528 93.144 36.72 ;
    END
  END dq[727]
  PIN dq[728]
    DIRECTION OUTPUT ;
    USE SIGNAL ;
    PORT
      LAYER M3 ;
        RECT  93.24 36.576 93.258 36.72 ;
    END
  END dq[728]
  PIN dq[729]
    DIRECTION OUTPUT ;
    USE SIGNAL ;
    PORT
      LAYER M5 ;
        RECT  93.36 36.528 93.384 36.72 ;
    END
  END dq[729]
  PIN dq[72]
    DIRECTION OUTPUT ;
    USE SIGNAL ;
    PORT
      LAYER M3 ;
        RECT  13.176 36.576 13.194 36.72 ;
    END
  END dq[72]
  PIN dq[730]
    DIRECTION OUTPUT ;
    USE SIGNAL ;
    PORT
      LAYER M3 ;
        RECT  93.456 36.576 93.474 36.72 ;
    END
  END dq[730]
  PIN dq[731]
    DIRECTION OUTPUT ;
    USE SIGNAL ;
    PORT
      LAYER M5 ;
        RECT  93.6 36.528 93.624 36.72 ;
    END
  END dq[731]
  PIN dq[732]
    DIRECTION OUTPUT ;
    USE SIGNAL ;
    PORT
      LAYER M3 ;
        RECT  93.708 36.576 93.726 36.72 ;
    END
  END dq[732]
  PIN dq[733]
    DIRECTION OUTPUT ;
    USE SIGNAL ;
    PORT
      LAYER M5 ;
        RECT  93.84 36.528 93.864 36.72 ;
    END
  END dq[733]
  PIN dq[734]
    DIRECTION OUTPUT ;
    USE SIGNAL ;
    PORT
      LAYER M3 ;
        RECT  93.96 36.576 93.978 36.72 ;
    END
  END dq[734]
  PIN dq[735]
    DIRECTION OUTPUT ;
    USE SIGNAL ;
    PORT
      LAYER M5 ;
        RECT  94.08 36.528 94.104 36.72 ;
    END
  END dq[735]
  PIN dq[736]
    DIRECTION OUTPUT ;
    USE SIGNAL ;
    PORT
      LAYER M3 ;
        RECT  94.212 36.576 94.23 36.72 ;
    END
  END dq[736]
  PIN dq[737]
    DIRECTION OUTPUT ;
    USE SIGNAL ;
    PORT
      LAYER M5 ;
        RECT  94.32 36.528 94.344 36.72 ;
    END
  END dq[737]
  PIN dq[738]
    DIRECTION OUTPUT ;
    USE SIGNAL ;
    PORT
      LAYER M3 ;
        RECT  94.428 36.576 94.446 36.72 ;
    END
  END dq[738]
  PIN dq[739]
    DIRECTION OUTPUT ;
    USE SIGNAL ;
    PORT
      LAYER M5 ;
        RECT  94.56 36.528 94.584 36.72 ;
    END
  END dq[739]
  PIN dq[73]
    DIRECTION OUTPUT ;
    USE SIGNAL ;
    PORT
      LAYER M5 ;
        RECT  13.296 36.528 13.32 36.72 ;
    END
  END dq[73]
  PIN dq[740]
    DIRECTION OUTPUT ;
    USE SIGNAL ;
    PORT
      LAYER M3 ;
        RECT  94.68 36.576 94.698 36.72 ;
    END
  END dq[740]
  PIN dq[741]
    DIRECTION OUTPUT ;
    USE SIGNAL ;
    PORT
      LAYER M5 ;
        RECT  94.8 36.528 94.824 36.72 ;
    END
  END dq[741]
  PIN dq[742]
    DIRECTION OUTPUT ;
    USE SIGNAL ;
    PORT
      LAYER M3 ;
        RECT  94.932 36.576 94.95 36.72 ;
    END
  END dq[742]
  PIN dq[743]
    DIRECTION OUTPUT ;
    USE SIGNAL ;
    PORT
      LAYER M5 ;
        RECT  95.04 36.528 95.064 36.72 ;
    END
  END dq[743]
  PIN dq[744]
    DIRECTION OUTPUT ;
    USE SIGNAL ;
    PORT
      LAYER M3 ;
        RECT  95.184 36.576 95.202 36.72 ;
    END
  END dq[744]
  PIN dq[745]
    DIRECTION OUTPUT ;
    USE SIGNAL ;
    PORT
      LAYER M5 ;
        RECT  95.28 36.528 95.304 36.72 ;
    END
  END dq[745]
  PIN dq[746]
    DIRECTION OUTPUT ;
    USE SIGNAL ;
    PORT
      LAYER M3 ;
        RECT  95.436 36.576 95.454 36.72 ;
    END
  END dq[746]
  PIN dq[747]
    DIRECTION OUTPUT ;
    USE SIGNAL ;
    PORT
      LAYER M5 ;
        RECT  95.52 36.528 95.544 36.72 ;
    END
  END dq[747]
  PIN dq[748]
    DIRECTION OUTPUT ;
    USE SIGNAL ;
    PORT
      LAYER M3 ;
        RECT  95.652 36.576 95.67 36.72 ;
    END
  END dq[748]
  PIN dq[749]
    DIRECTION OUTPUT ;
    USE SIGNAL ;
    PORT
      LAYER M5 ;
        RECT  95.808 36.528 95.832 36.72 ;
    END
  END dq[749]
  PIN dq[74]
    DIRECTION OUTPUT ;
    USE SIGNAL ;
    PORT
      LAYER M3 ;
        RECT  13.392 36.576 13.41 36.72 ;
    END
  END dq[74]
  PIN dq[750]
    DIRECTION OUTPUT ;
    USE SIGNAL ;
    PORT
      LAYER M3 ;
        RECT  95.904 36.576 95.922 36.72 ;
    END
  END dq[750]
  PIN dq[751]
    DIRECTION OUTPUT ;
    USE SIGNAL ;
    PORT
      LAYER M5 ;
        RECT  96.048 36.528 96.072 36.72 ;
    END
  END dq[751]
  PIN dq[752]
    DIRECTION OUTPUT ;
    USE SIGNAL ;
    PORT
      LAYER M3 ;
        RECT  96.156 36.576 96.174 36.72 ;
    END
  END dq[752]
  PIN dq[753]
    DIRECTION OUTPUT ;
    USE SIGNAL ;
    PORT
      LAYER M5 ;
        RECT  96.288 36.528 96.312 36.72 ;
    END
  END dq[753]
  PIN dq[754]
    DIRECTION OUTPUT ;
    USE SIGNAL ;
    PORT
      LAYER M3 ;
        RECT  96.408 36.576 96.426 36.72 ;
    END
  END dq[754]
  PIN dq[755]
    DIRECTION OUTPUT ;
    USE SIGNAL ;
    PORT
      LAYER M5 ;
        RECT  96.528 36.528 96.552 36.72 ;
    END
  END dq[755]
  PIN dq[756]
    DIRECTION OUTPUT ;
    USE SIGNAL ;
    PORT
      LAYER M3 ;
        RECT  96.624 36.576 96.642 36.72 ;
    END
  END dq[756]
  PIN dq[757]
    DIRECTION OUTPUT ;
    USE SIGNAL ;
    PORT
      LAYER M5 ;
        RECT  96.768 36.528 96.792 36.72 ;
    END
  END dq[757]
  PIN dq[758]
    DIRECTION OUTPUT ;
    USE SIGNAL ;
    PORT
      LAYER M3 ;
        RECT  96.876 36.576 96.894 36.72 ;
    END
  END dq[758]
  PIN dq[759]
    DIRECTION OUTPUT ;
    USE SIGNAL ;
    PORT
      LAYER M5 ;
        RECT  97.008 36.528 97.032 36.72 ;
    END
  END dq[759]
  PIN dq[75]
    DIRECTION OUTPUT ;
    USE SIGNAL ;
    PORT
      LAYER M5 ;
        RECT  13.536 36.528 13.56 36.72 ;
    END
  END dq[75]
  PIN dq[760]
    DIRECTION OUTPUT ;
    USE SIGNAL ;
    PORT
      LAYER M3 ;
        RECT  97.128 36.576 97.146 36.72 ;
    END
  END dq[760]
  PIN dq[76]
    DIRECTION OUTPUT ;
    USE SIGNAL ;
    PORT
      LAYER M3 ;
        RECT  13.644 36.576 13.662 36.72 ;
    END
  END dq[76]
  PIN dq[77]
    DIRECTION OUTPUT ;
    USE SIGNAL ;
    PORT
      LAYER M5 ;
        RECT  13.776 36.528 13.8 36.72 ;
    END
  END dq[77]
  PIN dq[78]
    DIRECTION OUTPUT ;
    USE SIGNAL ;
    PORT
      LAYER M3 ;
        RECT  13.896 36.576 13.914 36.72 ;
    END
  END dq[78]
  PIN dq[79]
    DIRECTION OUTPUT ;
    USE SIGNAL ;
    PORT
      LAYER M5 ;
        RECT  14.016 36.528 14.04 36.72 ;
    END
  END dq[79]
  PIN dq[7]
    DIRECTION OUTPUT ;
    USE SIGNAL ;
    PORT
      LAYER M5 ;
        RECT  5.232 36.528 5.256 36.72 ;
    END
  END dq[7]
  PIN dq[80]
    DIRECTION OUTPUT ;
    USE SIGNAL ;
    PORT
      LAYER M3 ;
        RECT  14.148 36.576 14.166 36.72 ;
    END
  END dq[80]
  PIN dq[81]
    DIRECTION OUTPUT ;
    USE SIGNAL ;
    PORT
      LAYER M5 ;
        RECT  14.256 36.528 14.28 36.72 ;
    END
  END dq[81]
  PIN dq[82]
    DIRECTION OUTPUT ;
    USE SIGNAL ;
    PORT
      LAYER M3 ;
        RECT  14.364 36.576 14.382 36.72 ;
    END
  END dq[82]
  PIN dq[83]
    DIRECTION OUTPUT ;
    USE SIGNAL ;
    PORT
      LAYER M5 ;
        RECT  14.496 36.528 14.52 36.72 ;
    END
  END dq[83]
  PIN dq[84]
    DIRECTION OUTPUT ;
    USE SIGNAL ;
    PORT
      LAYER M3 ;
        RECT  14.616 36.576 14.634 36.72 ;
    END
  END dq[84]
  PIN dq[85]
    DIRECTION OUTPUT ;
    USE SIGNAL ;
    PORT
      LAYER M5 ;
        RECT  14.736 36.528 14.76 36.72 ;
    END
  END dq[85]
  PIN dq[86]
    DIRECTION OUTPUT ;
    USE SIGNAL ;
    PORT
      LAYER M3 ;
        RECT  14.868 36.576 14.886 36.72 ;
    END
  END dq[86]
  PIN dq[87]
    DIRECTION OUTPUT ;
    USE SIGNAL ;
    PORT
      LAYER M5 ;
        RECT  14.976 36.528 15 36.72 ;
    END
  END dq[87]
  PIN dq[88]
    DIRECTION OUTPUT ;
    USE SIGNAL ;
    PORT
      LAYER M3 ;
        RECT  15.12 36.576 15.138 36.72 ;
    END
  END dq[88]
  PIN dq[89]
    DIRECTION OUTPUT ;
    USE SIGNAL ;
    PORT
      LAYER M5 ;
        RECT  15.216 36.528 15.24 36.72 ;
    END
  END dq[89]
  PIN dq[8]
    DIRECTION OUTPUT ;
    USE SIGNAL ;
    PORT
      LAYER M3 ;
        RECT  5.364 36.576 5.382 36.72 ;
    END
  END dq[8]
  PIN dq[90]
    DIRECTION OUTPUT ;
    USE SIGNAL ;
    PORT
      LAYER M3 ;
        RECT  15.372 36.576 15.39 36.72 ;
    END
  END dq[90]
  PIN dq[91]
    DIRECTION OUTPUT ;
    USE SIGNAL ;
    PORT
      LAYER M5 ;
        RECT  15.456 36.528 15.48 36.72 ;
    END
  END dq[91]
  PIN dq[92]
    DIRECTION OUTPUT ;
    USE SIGNAL ;
    PORT
      LAYER M3 ;
        RECT  15.588 36.576 15.606 36.72 ;
    END
  END dq[92]
  PIN dq[93]
    DIRECTION OUTPUT ;
    USE SIGNAL ;
    PORT
      LAYER M5 ;
        RECT  15.696 36.528 15.72 36.72 ;
    END
  END dq[93]
  PIN dq[94]
    DIRECTION OUTPUT ;
    USE SIGNAL ;
    PORT
      LAYER M3 ;
        RECT  15.84 36.576 15.858 36.72 ;
    END
  END dq[94]
  PIN dq[95]
    DIRECTION OUTPUT ;
    USE SIGNAL ;
    PORT
      LAYER M5 ;
        RECT  15.984 36.528 16.008 36.72 ;
    END
  END dq[95]
  PIN dq[96]
    DIRECTION OUTPUT ;
    USE SIGNAL ;
    PORT
      LAYER M3 ;
        RECT  16.092 36.576 16.11 36.72 ;
    END
  END dq[96]
  PIN dq[97]
    DIRECTION OUTPUT ;
    USE SIGNAL ;
    PORT
      LAYER M5 ;
        RECT  16.224 36.528 16.248 36.72 ;
    END
  END dq[97]
  PIN dq[98]
    DIRECTION OUTPUT ;
    USE SIGNAL ;
    PORT
      LAYER M3 ;
        RECT  16.344 36.576 16.362 36.72 ;
    END
  END dq[98]
  PIN dq[99]
    DIRECTION OUTPUT ;
    USE SIGNAL ;
    PORT
      LAYER M5 ;
        RECT  16.464 36.528 16.488 36.72 ;
    END
  END dq[99]
  PIN dq[9]
    DIRECTION OUTPUT ;
    USE SIGNAL ;
    PORT
      LAYER M5 ;
        RECT  5.472 36.528 5.496 36.72 ;
    END
  END dq[9]
  PIN VDD
    DIRECTION INOUT ;
    USE POWER ;
    PORT
      LAYER M5 ;
        RECT  97.092 2.151 97.212 34.569 ;
        RECT  94.392 2.151 94.512 34.569 ;
        RECT  91.692 2.151 91.812 34.569 ;
        RECT  88.992 2.151 89.112 34.569 ;
        RECT  86.292 2.151 86.412 34.569 ;
        RECT  83.592 2.151 83.712 34.569 ;
        RECT  80.892 2.151 81.012 34.569 ;
        RECT  78.192 2.151 78.312 34.569 ;
        RECT  75.492 2.151 75.612 34.569 ;
        RECT  72.792 2.151 72.912 34.569 ;
        RECT  70.092 2.151 70.212 34.569 ;
        RECT  67.392 2.151 67.512 34.569 ;
        RECT  64.692 2.151 64.812 34.569 ;
        RECT  61.992 2.151 62.112 34.569 ;
        RECT  59.292 2.151 59.412 34.569 ;
        RECT  56.592 2.151 56.712 34.569 ;
        RECT  53.892 2.151 54.012 34.569 ;
        RECT  51.192 2.151 51.312 34.569 ;
        RECT  48.492 2.151 48.612 34.569 ;
        RECT  45.792 2.151 45.912 34.569 ;
        RECT  43.092 2.151 43.212 34.569 ;
        RECT  40.392 2.151 40.512 34.569 ;
        RECT  37.692 2.151 37.812 34.569 ;
        RECT  34.992 2.151 35.112 34.569 ;
        RECT  32.292 2.151 32.412 34.569 ;
        RECT  29.592 2.151 29.712 34.569 ;
        RECT  26.892 2.151 27.012 34.569 ;
        RECT  24.192 2.151 24.312 34.569 ;
        RECT  21.492 2.151 21.612 34.569 ;
        RECT  18.792 2.151 18.912 34.569 ;
        RECT  16.092 2.151 16.212 34.569 ;
        RECT  13.392 2.151 13.512 34.569 ;
        RECT  10.692 2.151 10.812 34.569 ;
        RECT  7.992 2.151 8.112 34.569 ;
        RECT  5.292 2.151 5.412 34.569 ;
        RECT  2.592 2.151 2.712 34.569 ;
    END
  END VDD
  PIN VSS
    DIRECTION INOUT ;
    USE GROUND ;
    PORT
      LAYER M5 ;
        RECT  96.9 2.137 97.02 34.583 ;
        RECT  94.2 2.137 94.32 34.583 ;
        RECT  91.5 2.137 91.62 34.583 ;
        RECT  88.8 2.137 88.92 34.583 ;
        RECT  86.1 2.137 86.22 34.583 ;
        RECT  83.4 2.137 83.52 34.583 ;
        RECT  80.7 2.137 80.82 34.583 ;
        RECT  78 2.137 78.12 34.583 ;
        RECT  75.3 2.137 75.42 34.583 ;
        RECT  72.6 2.137 72.72 34.583 ;
        RECT  69.9 2.137 70.02 34.583 ;
        RECT  67.2 2.137 67.32 34.583 ;
        RECT  64.5 2.137 64.62 34.583 ;
        RECT  61.8 2.137 61.92 34.583 ;
        RECT  59.1 2.137 59.22 34.583 ;
        RECT  56.4 2.137 56.52 34.583 ;
        RECT  53.7 2.137 53.82 34.583 ;
        RECT  51 2.137 51.12 34.583 ;
        RECT  48.3 2.137 48.42 34.583 ;
        RECT  45.6 2.137 45.72 34.583 ;
        RECT  42.9 2.137 43.02 34.583 ;
        RECT  40.2 2.137 40.32 34.583 ;
        RECT  37.5 2.137 37.62 34.583 ;
        RECT  34.8 2.137 34.92 34.583 ;
        RECT  32.1 2.137 32.22 34.583 ;
        RECT  29.4 2.137 29.52 34.583 ;
        RECT  26.7 2.137 26.82 34.583 ;
        RECT  24 2.137 24.12 34.583 ;
        RECT  21.3 2.137 21.42 34.583 ;
        RECT  18.6 2.137 18.72 34.583 ;
        RECT  15.9 2.137 16.02 34.583 ;
        RECT  13.2 2.137 13.32 34.583 ;
        RECT  10.5 2.137 10.62 34.583 ;
        RECT  7.8 2.137 7.92 34.583 ;
        RECT  5.1 2.137 5.22 34.583 ;
        RECT  2.4 2.137 2.52 34.583 ;
    END
  END VSS
  # OT_OBS_CLOSED layer=M5 d_um=1.536 added=123
  OBS
    LAYER RVTN ;
     RECT  2.16 2.16 99.36 2.295 ;
     RECT  2.16 2.565 99.36 2.835 ;
     RECT  2.16 3.105 99.36 3.375 ;
     RECT  2.16 3.645 99.36 3.915 ;
     RECT  2.16 4.185 99.36 4.455 ;
     RECT  2.16 4.725 99.36 4.995 ;
     RECT  2.16 5.265 99.36 5.535 ;
     RECT  2.16 5.805 99.36 6.075 ;
     RECT  2.16 6.345 99.36 6.615 ;
     RECT  2.16 6.885 99.36 7.155 ;
     RECT  2.16 7.425 99.36 7.695 ;
     RECT  2.16 7.965 99.36 8.235 ;
     RECT  2.16 8.505 99.36 8.775 ;
     RECT  2.16 9.045 99.36 9.315 ;
     RECT  2.16 9.585 99.36 9.855 ;
     RECT  2.16 10.125 99.36 10.395 ;
     RECT  2.16 10.665 99.36 10.935 ;
     RECT  2.16 11.205 99.36 11.475 ;
     RECT  2.16 11.745 99.36 12.015 ;
     RECT  2.16 12.285 99.36 12.555 ;
     RECT  2.16 12.825 99.36 13.095 ;
     RECT  2.16 13.365 99.36 13.635 ;
     RECT  2.16 13.905 99.36 14.175 ;
     RECT  2.16 14.445 99.36 14.715 ;
     RECT  2.16 14.985 99.36 15.255 ;
     RECT  2.16 15.525 99.36 15.795 ;
     RECT  2.16 16.065 99.36 16.335 ;
     RECT  2.16 16.605 99.36 16.875 ;
     RECT  2.16 17.145 99.36 17.415 ;
     RECT  2.16 17.685 99.36 17.955 ;
     RECT  2.16 18.225 99.36 18.495 ;
     RECT  2.16 18.765 99.36 19.035 ;
     RECT  2.16 19.305 99.36 19.575 ;
     RECT  2.16 19.845 99.36 20.115 ;
     RECT  2.16 20.385 99.36 20.655 ;
     RECT  2.16 20.925 99.36 21.195 ;
     RECT  2.16 21.465 99.36 21.735 ;
     RECT  2.16 22.005 99.36 22.275 ;
     RECT  2.16 22.545 99.36 22.815 ;
     RECT  2.16 23.085 99.36 23.355 ;
     RECT  2.16 23.625 99.36 23.895 ;
     RECT  2.16 24.165 99.36 24.435 ;
     RECT  2.16 24.705 99.36 24.975 ;
     RECT  2.16 25.245 99.36 25.515 ;
     RECT  2.16 25.785 99.36 26.055 ;
     RECT  2.16 26.325 99.36 26.595 ;
     RECT  2.16 26.865 99.36 27.135 ;
     RECT  2.16 27.405 99.36 27.675 ;
     RECT  2.16 27.945 99.36 28.215 ;
     RECT  2.16 28.485 99.36 28.755 ;
     RECT  2.16 29.025 99.36 29.295 ;
     RECT  2.16 29.565 99.36 29.835 ;
     RECT  2.16 30.105 99.36 30.375 ;
     RECT  2.16 30.645 99.36 30.915 ;
     RECT  2.16 31.185 99.36 31.455 ;
     RECT  2.16 31.725 99.36 31.995 ;
     RECT  2.16 32.265 99.36 32.535 ;
     RECT  2.16 32.805 99.36 33.075 ;
     RECT  2.16 33.345 99.36 33.615 ;
     RECT  2.16 33.885 99.36 34.155 ;
     RECT  2.16 34.425 99.36 34.56 ;
    LAYER RVTP ;
     RECT  2.16 2.295 99.36 2.565 ;
     RECT  2.16 2.835 99.36 3.105 ;
     RECT  2.16 3.375 99.36 3.645 ;
     RECT  2.16 3.915 99.36 4.185 ;
     RECT  2.16 4.455 99.36 4.725 ;
     RECT  2.16 4.995 99.36 5.265 ;
     RECT  2.16 5.535 99.36 5.805 ;
     RECT  2.16 6.075 99.36 6.345 ;
     RECT  2.16 6.615 99.36 6.885 ;
     RECT  2.16 7.155 99.36 7.425 ;
     RECT  2.16 7.695 99.36 7.965 ;
     RECT  2.16 8.235 99.36 8.505 ;
     RECT  2.16 8.775 99.36 9.045 ;
     RECT  2.16 9.315 99.36 9.585 ;
     RECT  2.16 9.855 99.36 10.125 ;
     RECT  2.16 10.395 99.36 10.665 ;
     RECT  2.16 10.935 99.36 11.205 ;
     RECT  2.16 11.475 99.36 11.745 ;
     RECT  2.16 12.015 99.36 12.285 ;
     RECT  2.16 12.555 99.36 12.825 ;
     RECT  2.16 13.095 99.36 13.365 ;
     RECT  2.16 13.635 99.36 13.905 ;
     RECT  2.16 14.175 99.36 14.445 ;
     RECT  2.16 14.715 99.36 14.985 ;
     RECT  2.16 15.255 99.36 15.525 ;
     RECT  2.16 15.795 99.36 16.065 ;
     RECT  2.16 16.335 99.36 16.605 ;
     RECT  2.16 16.875 99.36 17.145 ;
     RECT  2.16 17.415 99.36 17.685 ;
     RECT  2.16 17.955 99.36 18.225 ;
     RECT  2.16 18.495 99.36 18.765 ;
     RECT  2.16 19.035 99.36 19.305 ;
     RECT  2.16 19.575 99.36 19.845 ;
     RECT  2.16 20.115 99.36 20.385 ;
     RECT  2.16 20.655 99.36 20.925 ;
     RECT  2.16 21.195 99.36 21.465 ;
     RECT  2.16 21.735 99.36 22.005 ;
     RECT  2.16 22.275 99.36 22.545 ;
     RECT  2.16 22.815 99.36 23.085 ;
     RECT  2.16 23.355 99.36 23.625 ;
     RECT  2.16 23.895 99.36 24.165 ;
     RECT  2.16 24.435 99.36 24.705 ;
     RECT  2.16 24.975 99.36 25.245 ;
     RECT  2.16 25.515 99.36 25.785 ;
     RECT  2.16 26.055 99.36 26.325 ;
     RECT  2.16 26.595 99.36 26.865 ;
     RECT  2.16 27.135 99.36 27.405 ;
     RECT  2.16 27.675 99.36 27.945 ;
     RECT  2.16 28.215 99.36 28.485 ;
     RECT  2.16 28.755 99.36 29.025 ;
     RECT  2.16 29.295 99.36 29.565 ;
     RECT  2.16 29.835 99.36 30.105 ;
     RECT  2.16 30.375 99.36 30.645 ;
     RECT  2.16 30.915 99.36 31.185 ;
     RECT  2.16 31.455 99.36 31.725 ;
     RECT  2.16 31.995 99.36 32.265 ;
     RECT  2.16 32.535 99.36 32.805 ;
     RECT  2.16 33.075 99.36 33.345 ;
     RECT  2.16 33.615 99.36 33.885 ;
     RECT  2.16 34.155 99.36 34.425 ;
    LAYER M1 ;
     RECT  2.16 2.151 99.36 34.569 ;
    LAYER M2 ;
     RECT  2.16 2.151 3.703 34.569 ;
     RECT  3.703 2.106 4.243 34.569 ;
     RECT  4.243 2.034 4.603 34.569 ;
     RECT  4.603 2.034 4.883 34.794 ;
     RECT  4.883 2.151 5.035 34.794 ;
     RECT  5.035 2.151 5.135 34.839 ;
     RECT  5.035 0.144 5.459 0.162 ;
     RECT  5.359 35.901 6.323 35.919 ;
     RECT  6.331 36.558 6.367 36.576 ;
     RECT  6.367 36.558 6.467 36.648 ;
     RECT  6.547 0.144 6.647 0.162 ;
     RECT  5.135 2.151 6.691 34.569 ;
     RECT  6.691 2.106 7.303 34.569 ;
     RECT  8.023 0.144 8.195 0.162 ;
     RECT  7.303 1.728 8.411 34.569 ;
     RECT  8.995 35.901 9.499 35.919 ;
     RECT  9.427 0.144 10.247 0.162 ;
     RECT  8.411 2.151 10.327 34.569 ;
     RECT  10.327 2.106 10.471 34.569 ;
     RECT  9.499 35.901 10.975 35.964 ;
     RECT  10.471 1.728 11.075 34.569 ;
     RECT  10.975 35.901 11.507 36.036 ;
     RECT  11.507 36.018 12.155 36.036 ;
     RECT  11.075 2.151 12.919 34.569 ;
     RECT  13.387 0.144 13.559 0.162 ;
     RECT  12.919 1.728 13.639 34.569 ;
     RECT  13.387 35.901 13.639 35.919 ;
     RECT  13.639 1.656 13.739 34.569 ;
     RECT  13.639 35.901 13.847 35.964 ;
     RECT  13.739 2.151 13.891 34.569 ;
     RECT  13.891 2.151 13.991 34.794 ;
     RECT  13.847 35.946 14.315 35.964 ;
     RECT  14.611 0.144 14.711 0.162 ;
     RECT  13.991 2.151 15.259 34.569 ;
     RECT  16.087 0.144 16.259 0.162 ;
     RECT  16.339 35.901 16.807 35.919 ;
     RECT  16.807 35.901 16.843 36.576 ;
     RECT  16.843 35.901 16.943 36.648 ;
     RECT  16.943 35.901 17.411 35.919 ;
     RECT  15.259 2.151 17.555 34.794 ;
     RECT  17.555 2.151 18.283 34.758 ;
     RECT  18.283 2.151 18.383 34.794 ;
     RECT  20.407 1.152 20.507 1.17 ;
     RECT  19.003 35.901 20.903 35.919 ;
     RECT  18.383 2.151 21.199 34.569 ;
     RECT  21.199 2.151 22.163 34.794 ;
     RECT  22.163 2.151 22.235 34.758 ;
     RECT  21.955 35.901 22.559 35.919 ;
     RECT  22.927 0.144 23.027 0.162 ;
     RECT  23.971 0.144 24.395 0.162 ;
     RECT  22.235 2.151 25.051 34.569 ;
     RECT  24.871 35.901 25.123 35.919 ;
     RECT  25.123 35.901 25.159 36.576 ;
     RECT  25.159 35.901 25.259 36.648 ;
     RECT  25.051 2.106 25.375 34.569 ;
     RECT  25.375 2.106 25.655 34.794 ;
     RECT  25.655 2.106 25.691 34.569 ;
     RECT  25.303 0.144 26.195 0.162 ;
     RECT  25.691 2.151 26.815 34.569 ;
     RECT  26.815 2.07 27.167 34.794 ;
     RECT  27.167 2.07 27.383 34.569 ;
     RECT  27.571 0.306 27.787 0.324 ;
     RECT  27.787 0.144 27.815 0.324 ;
     RECT  27.815 0.144 27.887 0.162 ;
     RECT  28.039 36.558 28.075 36.576 ;
     RECT  28.075 36.558 28.175 36.648 ;
     RECT  27.383 2.151 29.335 34.569 ;
     RECT  29.371 0.144 29.543 0.162 ;
     RECT  29.335 2.151 31.307 34.794 ;
     RECT  31.207 35.901 31.415 35.919 ;
     RECT  31.307 2.151 32.179 34.569 ;
     RECT  32.179 0.144 32.279 0.162 ;
     RECT  32.179 2.151 32.359 34.794 ;
     RECT  32.359 2.151 32.459 34.884 ;
     RECT  32.459 2.151 32.495 34.839 ;
     RECT  32.431 0.576 33.107 0.594 ;
     RECT  33.187 35.982 33.467 36 ;
     RECT  32.495 2.151 34.159 34.569 ;
     RECT  34.159 1.728 34.547 34.569 ;
     RECT  34.547 2.151 34.879 34.569 ;
     RECT  34.771 0.144 34.907 0.162 ;
     RECT  34.879 2.151 35.195 34.65 ;
     RECT  35.131 35.901 36.103 35.919 ;
     RECT  36.103 35.901 36.275 35.964 ;
     RECT  36.275 35.946 36.527 35.964 ;
     RECT  35.195 2.151 37.471 34.569 ;
     RECT  37.471 2.151 37.579 34.65 ;
     RECT  37.579 1.728 37.607 34.65 ;
     RECT  37.607 1.728 38.327 34.569 ;
     RECT  38.299 0.144 38.507 0.162 ;
     RECT  40.243 35.901 40.747 35.919 ;
     RECT  40.495 0.306 40.775 0.324 ;
     RECT  40.747 35.901 40.855 35.964 ;
     RECT  40.855 35.901 40.919 36 ;
     RECT  38.327 2.151 40.999 34.569 ;
     RECT  40.919 35.946 41.027 36 ;
     RECT  40.999 1.656 41.099 34.569 ;
     RECT  41.027 35.946 41.351 35.964 ;
     RECT  41.099 2.151 42.187 34.569 ;
     RECT  42.187 2.151 43.079 34.794 ;
     RECT  41.971 0.144 43.295 0.162 ;
     RECT  42.619 36.558 43.331 36.648 ;
     RECT  43.411 36.018 43.583 36.036 ;
     RECT  43.079 2.151 44.635 34.569 ;
     RECT  44.167 35.901 44.699 35.919 ;
     RECT  44.635 2.151 45.859 34.794 ;
     RECT  45.859 2.151 46.031 34.839 ;
     RECT  46.031 2.151 46.111 34.569 ;
     RECT  45.607 0.144 46.175 0.162 ;
     RECT  46.111 1.728 46.823 34.569 ;
     RECT  46.823 2.151 46.831 34.569 ;
     RECT  46.831 2.151 47.291 34.794 ;
     RECT  47.291 2.151 48.235 34.569 ;
     RECT  47.803 0.144 48.659 0.162 ;
     RECT  48.235 2.151 48.811 34.794 ;
     RECT  48.811 1.728 48.983 34.794 ;
     RECT  48.983 1.728 49.631 34.569 ;
     RECT  49.631 2.151 50.899 34.569 ;
     RECT  50.899 2.151 51.035 34.65 ;
     RECT  51.007 0.144 51.179 0.162 ;
     RECT  51.035 2.151 51.223 34.569 ;
     RECT  51.223 1.728 51.467 34.569 ;
     RECT  52.447 36.558 52.483 36.576 ;
     RECT  52.483 36.558 52.583 36.648 ;
     RECT  53.851 0.144 53.951 0.162 ;
     RECT  55.147 35.901 55.571 35.919 ;
     RECT  55.147 0.144 56.759 0.162 ;
     RECT  51.467 2.151 57.091 34.569 ;
     RECT  57.091 2.151 57.343 34.794 ;
     RECT  57.343 1.728 57.623 34.794 ;
     RECT  57.595 0.144 57.695 0.162 ;
     RECT  57.343 35.901 57.875 35.919 ;
     RECT  57.623 2.151 57.947 34.794 ;
     RECT  59.035 36.558 59.071 36.576 ;
     RECT  59.071 36.558 59.171 36.648 ;
     RECT  59.035 0.144 59.279 0.162 ;
     RECT  57.947 2.151 59.287 34.569 ;
     RECT  59.287 2.151 59.459 34.794 ;
     RECT  59.539 35.901 60.251 35.919 ;
     RECT  59.459 2.151 60.259 34.569 ;
     RECT  60.259 2.151 62.015 34.794 ;
     RECT  62.959 35.982 63.427 36 ;
     RECT  63.427 35.982 63.463 36.576 ;
     RECT  63.463 35.982 63.563 36.648 ;
     RECT  63.679 35.901 63.995 35.919 ;
     RECT  62.015 2.151 64.399 34.569 ;
     RECT  64.399 2.151 64.859 34.794 ;
     RECT  65.155 36.018 65.399 36.036 ;
     RECT  64.859 2.151 65.407 34.569 ;
     RECT  65.407 1.656 65.615 34.569 ;
     RECT  65.407 35.901 65.615 35.919 ;
     RECT  65.615 2.151 65.875 34.569 ;
     RECT  65.875 2.151 65.975 34.794 ;
     RECT  66.379 0.144 66.479 0.162 ;
     RECT  65.975 2.151 67.063 34.569 ;
     RECT  67.063 2.151 67.603 34.758 ;
     RECT  67.603 1.728 67.919 34.758 ;
     RECT  67.819 0.144 67.955 0.162 ;
     RECT  67.919 2.151 68.575 34.758 ;
     RECT  69.043 36.558 69.079 36.576 ;
     RECT  69.079 36.558 69.179 36.648 ;
     RECT  68.575 2.151 70.043 34.794 ;
     RECT  70.043 2.151 70.771 34.569 ;
     RECT  70.771 2.151 71.239 34.758 ;
     RECT  71.239 2.151 71.491 34.839 ;
     RECT  71.491 1.728 71.555 34.839 ;
     RECT  71.555 1.728 71.591 34.758 ;
     RECT  71.591 1.728 71.915 34.569 ;
     RECT  71.915 2.151 72.535 34.569 ;
     RECT  71.743 0.576 72.563 0.594 ;
     RECT  72.571 0.144 72.743 0.162 ;
     RECT  72.535 2.151 72.743 34.794 ;
     RECT  72.743 2.151 73.687 34.569 ;
     RECT  73.435 35.901 73.823 35.919 ;
     RECT  73.939 0.144 74.039 0.162 ;
     RECT  74.659 35.982 74.911 36 ;
     RECT  74.911 35.982 74.939 36.072 ;
     RECT  74.939 36.054 75.047 36.072 ;
     RECT  75.415 0.306 75.559 0.324 ;
     RECT  73.687 2.151 75.559 34.794 ;
     RECT  75.559 0.144 75.659 0.324 ;
     RECT  75.559 1.728 75.803 34.794 ;
     RECT  75.803 1.728 76.127 34.569 ;
     RECT  76.127 2.151 76.675 34.569 ;
     RECT  76.675 2.151 76.811 34.758 ;
     RECT  76.135 35.901 77.243 35.919 ;
     RECT  77.359 0.144 77.459 0.162 ;
     RECT  76.811 2.151 78.079 34.569 ;
     RECT  78.511 36.558 78.647 36.648 ;
     RECT  79.303 0.144 79.403 0.162 ;
     RECT  79.051 35.901 79.439 35.919 ;
     RECT  78.079 2.151 79.555 34.794 ;
     RECT  79.555 1.728 79.979 34.794 ;
     RECT  80.779 0.144 80.879 0.162 ;
     RECT  80.779 35.901 81.563 35.919 ;
     RECT  79.979 1.728 82.471 34.569 ;
     RECT  82.471 1.656 82.787 34.569 ;
     RECT  83.443 35.901 83.695 35.919 ;
     RECT  83.443 0.144 83.795 0.162 ;
     RECT  83.695 35.901 83.947 35.964 ;
     RECT  83.947 35.901 84.587 36.036 ;
     RECT  82.787 2.151 85.423 34.569 ;
     RECT  84.587 35.901 85.423 35.919 ;
     RECT  85.423 1.728 85.523 34.569 ;
     RECT  85.423 35.901 85.523 35.964 ;
     RECT  85.523 35.946 85.703 35.964 ;
     RECT  85.523 2.151 86.143 34.569 ;
     RECT  86.143 2.151 86.459 34.65 ;
     RECT  86.459 2.151 86.575 34.569 ;
     RECT  86.611 35.901 86.855 35.919 ;
     RECT  86.071 0.144 87.215 0.162 ;
     RECT  86.575 2.106 87.619 34.569 ;
     RECT  87.619 1.728 87.971 34.569 ;
     RECT  87.619 35.901 88.007 35.919 ;
     RECT  88.123 1.152 88.223 1.17 ;
     RECT  88.519 0.144 88.871 0.162 ;
     RECT  87.971 2.151 89.059 34.569 ;
     RECT  89.059 2.151 89.267 34.794 ;
     RECT  88.843 35.901 89.699 35.919 ;
     RECT  89.959 0.144 90.059 0.162 ;
     RECT  90.031 35.946 90.599 36.108 ;
     RECT  90.599 35.946 90.779 35.964 ;
     RECT  89.267 2.151 90.787 34.569 ;
     RECT  90.787 2.151 90.859 34.794 ;
     RECT  91.471 36.63 91.507 36.648 ;
     RECT  91.507 36.558 91.607 36.648 ;
     RECT  91.327 0.144 91.859 0.162 ;
     RECT  90.859 2.106 91.895 34.794 ;
     RECT  91.895 2.106 92.227 34.569 ;
     RECT  92.227 35.901 92.731 35.919 ;
     RECT  92.227 1.728 92.831 34.569 ;
     RECT  92.831 2.151 92.983 34.569 ;
     RECT  92.731 35.901 93.047 35.964 ;
     RECT  92.983 2.151 93.479 34.794 ;
     RECT  93.047 35.901 94.019 35.919 ;
     RECT  93.479 2.151 94.207 34.569 ;
     RECT  94.135 0.144 94.235 0.162 ;
     RECT  94.207 2.151 94.423 34.794 ;
     RECT  94.423 1.728 94.595 34.794 ;
     RECT  94.595 1.728 94.883 34.569 ;
     RECT  94.423 36.018 94.927 36.036 ;
     RECT  94.927 35.901 95.431 36.036 ;
     RECT  94.883 2.151 95.647 34.569 ;
     RECT  95.431 35.901 95.999 36.108 ;
     RECT  95.647 1.728 96.071 34.569 ;
     RECT  95.999 35.901 96.251 36 ;
     RECT  96.071 2.151 96.403 34.569 ;
     RECT  96.403 2.151 96.619 34.794 ;
     RECT  96.619 2.151 96.899 34.839 ;
     RECT  96.899 2.151 97.259 34.794 ;
     RECT  96.251 35.901 97.727 35.919 ;
     RECT  97.259 2.151 99.36 34.569 ;
    LAYER M3 ;
     RECT  4.374 0.108 4.608 0.144 ;
     RECT  4.626 0.108 4.86 0.144 ;
     RECT  4.878 0.108 5.112 0.144 ;
     RECT  5.13 0.108 5.364 0.144 ;
     RECT  5.382 0.108 5.58 0.144 ;
     RECT  5.598 0.108 5.832 0.144 ;
     RECT  5.85 0.108 6.084 0.144 ;
     RECT  6.102 0.108 6.336 0.144 ;
     RECT  6.354 0.108 6.552 0.144 ;
     RECT  6.57 0.108 6.804 0.144 ;
     RECT  6.822 0.108 7.056 0.144 ;
     RECT  7.074 0.108 7.308 0.144 ;
     RECT  7.326 0.108 7.56 0.144 ;
     RECT  7.578 0.108 7.776 0.144 ;
     RECT  7.794 0.108 8.028 0.144 ;
     RECT  8.046 0.108 8.28 0.144 ;
     RECT  8.298 0.108 8.532 0.144 ;
     RECT  8.55 0.108 8.748 0.144 ;
     RECT  8.766 0.108 9 0.144 ;
     RECT  9.018 0.108 9.252 0.144 ;
     RECT  9.27 0.108 9.504 0.144 ;
     RECT  9.522 0.108 9.756 0.144 ;
     RECT  9.774 0.108 9.972 0.144 ;
     RECT  9.99 0.108 10.224 0.144 ;
     RECT  10.242 0.108 10.476 0.144 ;
     RECT  10.494 0.108 10.728 0.144 ;
     RECT  10.746 0.108 10.98 0.144 ;
     RECT  10.998 0.108 11.196 0.144 ;
     RECT  11.214 0.108 11.448 0.144 ;
     RECT  11.466 0.108 11.7 0.144 ;
     RECT  11.718 0.108 11.952 0.144 ;
     RECT  11.97 0.108 12.168 0.144 ;
     RECT  12.186 0.108 12.42 0.144 ;
     RECT  12.438 0.108 12.672 0.144 ;
     RECT  12.69 0.108 12.924 0.144 ;
     RECT  12.942 0.108 13.176 0.144 ;
     RECT  13.194 0.108 13.392 0.144 ;
     RECT  13.41 0.108 13.644 0.144 ;
     RECT  13.662 0.108 13.896 0.144 ;
     RECT  13.914 0.108 14.148 0.144 ;
     RECT  14.166 0.108 14.364 0.144 ;
     RECT  14.382 0.108 14.616 0.144 ;
     RECT  14.634 0.108 14.868 0.144 ;
     RECT  14.886 0.108 15.12 0.144 ;
     RECT  15.138 0.108 15.372 0.144 ;
     RECT  15.39 0.108 15.588 0.144 ;
     RECT  15.606 0.108 15.84 0.144 ;
     RECT  15.858 0.108 16.092 0.144 ;
     RECT  16.11 0.108 16.344 0.144 ;
     RECT  16.362 0.108 16.56 0.144 ;
     RECT  16.578 0.108 16.812 0.144 ;
     RECT  16.83 0.108 17.064 0.144 ;
     RECT  17.082 0.108 17.316 0.144 ;
     RECT  17.334 0.108 17.568 0.144 ;
     RECT  17.586 0.108 17.784 0.144 ;
     RECT  17.802 0.108 18.036 0.144 ;
     RECT  18.054 0.108 18.288 0.144 ;
     RECT  18.306 0.108 18.54 0.144 ;
     RECT  18.558 0.108 18.756 0.144 ;
     RECT  18.774 0.108 19.008 0.144 ;
     RECT  19.026 0.108 19.26 0.144 ;
     RECT  19.278 0.108 19.512 0.144 ;
     RECT  19.53 0.108 19.764 0.144 ;
     RECT  19.782 0.108 19.98 0.144 ;
     RECT  19.998 0.108 20.232 0.144 ;
     RECT  20.25 0.108 20.484 0.144 ;
     RECT  20.502 0.108 20.736 0.144 ;
     RECT  20.754 0.108 20.988 0.144 ;
     RECT  21.006 0.108 21.204 0.144 ;
     RECT  21.222 0.108 21.456 0.144 ;
     RECT  21.474 0.108 21.708 0.144 ;
     RECT  21.726 0.108 21.96 0.144 ;
     RECT  21.978 0.108 22.176 0.144 ;
     RECT  22.194 0.108 22.428 0.144 ;
     RECT  22.446 0.108 22.68 0.144 ;
     RECT  22.698 0.108 22.932 0.144 ;
     RECT  22.95 0.108 23.184 0.144 ;
     RECT  23.202 0.108 23.4 0.144 ;
     RECT  23.418 0.108 23.652 0.144 ;
     RECT  23.67 0.108 23.904 0.144 ;
     RECT  23.922 0.108 24.156 0.144 ;
     RECT  24.174 0.108 24.372 0.144 ;
     RECT  24.39 0.108 24.624 0.144 ;
     RECT  24.642 0.108 24.876 0.144 ;
     RECT  24.894 0.108 25.128 0.144 ;
     RECT  25.146 0.108 25.38 0.144 ;
     RECT  25.398 0.108 25.596 0.144 ;
     RECT  25.614 0.108 25.848 0.144 ;
     RECT  25.866 0.108 26.1 0.144 ;
     RECT  26.118 0.108 26.352 0.144 ;
     RECT  26.37 0.108 26.568 0.144 ;
     RECT  26.586 0.108 26.82 0.144 ;
     RECT  26.838 0.108 27.072 0.144 ;
     RECT  27.09 0.108 27.324 0.144 ;
     RECT  27.342 0.108 27.576 0.144 ;
     RECT  27.594 0.108 27.792 0.144 ;
     RECT  27.81 0.108 28.044 0.144 ;
     RECT  28.062 0.108 28.296 0.144 ;
     RECT  28.314 0.108 28.548 0.144 ;
     RECT  28.566 0.108 28.8 0.144 ;
     RECT  28.818 0.108 29.016 0.144 ;
     RECT  29.034 0.108 29.268 0.144 ;
     RECT  29.286 0.108 29.52 0.144 ;
     RECT  29.538 0.108 29.772 0.144 ;
     RECT  29.79 0.108 29.988 0.144 ;
     RECT  30.006 0.108 30.24 0.144 ;
     RECT  30.258 0.108 30.492 0.144 ;
     RECT  30.51 0.108 30.744 0.144 ;
     RECT  30.762 0.108 30.996 0.144 ;
     RECT  31.014 0.108 31.212 0.144 ;
     RECT  31.23 0.108 31.464 0.144 ;
     RECT  31.482 0.108 31.716 0.144 ;
     RECT  31.734 0.108 31.968 0.144 ;
     RECT  31.986 0.108 32.184 0.144 ;
     RECT  32.202 0.108 32.436 0.144 ;
     RECT  32.454 0.108 32.688 0.144 ;
     RECT  32.706 0.108 32.94 0.144 ;
     RECT  32.958 0.108 33.192 0.144 ;
     RECT  33.21 0.108 33.408 0.144 ;
     RECT  33.426 0.108 33.66 0.144 ;
     RECT  33.678 0.108 33.912 0.144 ;
     RECT  33.93 0.108 34.164 0.144 ;
     RECT  34.182 0.108 34.38 0.144 ;
     RECT  34.398 0.108 34.632 0.144 ;
     RECT  34.65 0.108 34.884 0.144 ;
     RECT  34.902 0.108 35.136 0.144 ;
     RECT  35.154 0.108 35.388 0.144 ;
     RECT  35.406 0.108 35.604 0.144 ;
     RECT  35.622 0.108 35.856 0.144 ;
     RECT  35.874 0.108 36.108 0.144 ;
     RECT  36.126 0.108 36.36 0.144 ;
     RECT  36.378 0.108 36.576 0.144 ;
     RECT  36.594 0.108 36.828 0.144 ;
     RECT  36.846 0.108 37.08 0.144 ;
     RECT  37.098 0.108 37.332 0.144 ;
     RECT  37.35 0.108 37.584 0.144 ;
     RECT  37.602 0.108 37.8 0.144 ;
     RECT  37.818 0.108 38.052 0.144 ;
     RECT  38.07 0.108 38.304 0.144 ;
     RECT  38.322 0.108 38.556 0.144 ;
     RECT  38.574 0.108 38.808 0.144 ;
     RECT  38.826 0.108 39.024 0.144 ;
     RECT  39.042 0.108 39.276 0.144 ;
     RECT  39.294 0.108 39.528 0.144 ;
     RECT  39.546 0.108 39.78 0.144 ;
     RECT  39.798 0.108 39.996 0.144 ;
     RECT  40.014 0.108 40.248 0.144 ;
     RECT  40.266 0.108 40.5 0.144 ;
     RECT  40.518 0.108 40.752 0.144 ;
     RECT  40.77 0.108 41.004 0.144 ;
     RECT  41.022 0.108 41.22 0.144 ;
     RECT  41.238 0.108 41.472 0.144 ;
     RECT  41.49 0.108 41.724 0.144 ;
     RECT  41.742 0.108 41.976 0.144 ;
     RECT  41.994 0.108 42.192 0.144 ;
     RECT  42.21 0.108 42.444 0.144 ;
     RECT  42.462 0.108 42.696 0.144 ;
     RECT  42.714 0.108 42.948 0.144 ;
     RECT  42.966 0.108 43.2 0.144 ;
     RECT  43.218 0.108 43.416 0.144 ;
     RECT  43.434 0.108 43.668 0.144 ;
     RECT  43.686 0.108 43.92 0.144 ;
     RECT  43.938 0.108 44.172 0.144 ;
     RECT  44.19 0.108 44.388 0.144 ;
     RECT  44.406 0.108 44.64 0.144 ;
     RECT  44.658 0.108 44.892 0.144 ;
     RECT  44.91 0.108 45.144 0.144 ;
     RECT  45.162 0.108 45.396 0.144 ;
     RECT  45.414 0.108 45.612 0.144 ;
     RECT  45.63 0.108 45.864 0.144 ;
     RECT  45.882 0.108 46.116 0.144 ;
     RECT  46.134 0.108 46.368 0.144 ;
     RECT  46.386 0.108 46.584 0.144 ;
     RECT  46.602 0.108 46.836 0.144 ;
     RECT  46.854 0.108 47.088 0.144 ;
     RECT  47.106 0.108 47.34 0.144 ;
     RECT  47.358 0.108 47.592 0.144 ;
     RECT  47.61 0.108 47.808 0.144 ;
     RECT  47.826 0.108 48.06 0.144 ;
     RECT  48.078 0.108 48.312 0.144 ;
     RECT  48.33 0.108 48.564 0.144 ;
     RECT  48.582 0.108 48.816 0.144 ;
     RECT  48.834 0.108 49.032 0.144 ;
     RECT  49.05 0.108 49.284 0.144 ;
     RECT  49.302 0.108 49.536 0.144 ;
     RECT  49.554 0.108 49.788 0.144 ;
     RECT  49.806 0.108 50.004 0.144 ;
     RECT  50.022 0.108 50.256 0.144 ;
     RECT  50.274 0.108 50.508 0.144 ;
     RECT  50.526 0.108 50.76 0.144 ;
     RECT  50.778 0.108 51.012 0.144 ;
     RECT  51.03 0.108 51.228 0.144 ;
     RECT  51.246 0.108 51.48 0.144 ;
     RECT  51.498 0.108 51.732 0.144 ;
     RECT  51.75 0.108 51.984 0.144 ;
     RECT  52.002 0.108 52.2 0.144 ;
     RECT  52.218 0.108 52.452 0.144 ;
     RECT  52.47 0.108 52.704 0.144 ;
     RECT  52.722 0.108 52.956 0.144 ;
     RECT  52.974 0.108 53.208 0.144 ;
     RECT  53.226 0.108 53.424 0.144 ;
     RECT  53.442 0.108 53.676 0.144 ;
     RECT  53.694 0.108 53.928 0.144 ;
     RECT  53.946 0.108 54.18 0.144 ;
     RECT  54.198 0.108 54.396 0.144 ;
     RECT  54.414 0.108 54.648 0.144 ;
     RECT  54.666 0.108 54.9 0.144 ;
     RECT  54.918 0.108 55.152 0.144 ;
     RECT  55.17 0.108 55.404 0.144 ;
     RECT  55.422 0.108 55.62 0.144 ;
     RECT  55.638 0.108 55.872 0.144 ;
     RECT  55.89 0.108 56.124 0.144 ;
     RECT  56.142 0.108 56.376 0.144 ;
     RECT  56.394 0.108 56.592 0.144 ;
     RECT  56.61 0.108 56.844 0.144 ;
     RECT  56.862 0.108 57.096 0.144 ;
     RECT  57.114 0.108 57.348 0.144 ;
     RECT  57.366 0.108 57.6 0.144 ;
     RECT  57.618 0.108 57.816 0.144 ;
     RECT  57.834 0.108 58.068 0.144 ;
     RECT  58.086 0.108 58.32 0.144 ;
     RECT  58.338 0.108 58.572 0.144 ;
     RECT  58.59 0.108 58.824 0.144 ;
     RECT  58.842 0.108 59.04 0.144 ;
     RECT  59.058 0.108 59.292 0.144 ;
     RECT  59.31 0.108 59.544 0.144 ;
     RECT  59.562 0.108 59.796 0.144 ;
     RECT  59.814 0.108 60.012 0.144 ;
     RECT  60.03 0.108 60.264 0.144 ;
     RECT  60.282 0.108 60.516 0.144 ;
     RECT  60.534 0.108 60.768 0.144 ;
     RECT  60.786 0.108 61.02 0.144 ;
     RECT  61.038 0.108 61.236 0.144 ;
     RECT  61.254 0.108 61.488 0.144 ;
     RECT  61.506 0.108 61.74 0.144 ;
     RECT  61.758 0.108 61.992 0.144 ;
     RECT  62.01 0.108 62.208 0.144 ;
     RECT  62.226 0.108 62.46 0.144 ;
     RECT  62.478 0.108 62.712 0.144 ;
     RECT  62.73 0.108 62.964 0.144 ;
     RECT  62.982 0.108 63.216 0.144 ;
     RECT  63.234 0.108 63.432 0.144 ;
     RECT  63.45 0.108 63.684 0.144 ;
     RECT  63.702 0.108 63.936 0.144 ;
     RECT  63.954 0.108 64.188 0.144 ;
     RECT  64.206 0.108 64.404 0.144 ;
     RECT  64.422 0.108 64.656 0.144 ;
     RECT  64.674 0.108 64.908 0.144 ;
     RECT  64.926 0.108 65.16 0.144 ;
     RECT  65.178 0.108 65.412 0.144 ;
     RECT  65.43 0.108 65.628 0.144 ;
     RECT  65.646 0.108 65.88 0.144 ;
     RECT  65.898 0.108 66.132 0.144 ;
     RECT  66.15 0.108 66.384 0.144 ;
     RECT  66.402 0.108 66.6 0.144 ;
     RECT  66.618 0.108 66.852 0.144 ;
     RECT  66.87 0.108 67.104 0.144 ;
     RECT  67.122 0.108 67.356 0.144 ;
     RECT  67.374 0.108 67.608 0.144 ;
     RECT  67.626 0.108 67.824 0.144 ;
     RECT  67.842 0.108 68.076 0.144 ;
     RECT  68.094 0.108 68.328 0.144 ;
     RECT  68.346 0.108 68.58 0.144 ;
     RECT  68.598 0.108 68.832 0.144 ;
     RECT  68.85 0.108 69.048 0.144 ;
     RECT  69.066 0.108 69.3 0.144 ;
     RECT  69.318 0.108 69.552 0.144 ;
     RECT  69.57 0.108 69.804 0.144 ;
     RECT  69.822 0.108 70.02 0.144 ;
     RECT  70.038 0.108 70.272 0.144 ;
     RECT  70.29 0.108 70.524 0.144 ;
     RECT  70.542 0.108 70.776 0.144 ;
     RECT  70.794 0.108 71.028 0.144 ;
     RECT  71.046 0.108 71.244 0.144 ;
     RECT  71.262 0.108 71.496 0.144 ;
     RECT  71.514 0.108 71.748 0.144 ;
     RECT  71.766 0.108 72 0.144 ;
     RECT  72.018 0.108 72.216 0.144 ;
     RECT  72.234 0.108 72.468 0.144 ;
     RECT  72.486 0.108 72.72 0.144 ;
     RECT  72.738 0.108 72.972 0.144 ;
     RECT  72.99 0.108 73.224 0.144 ;
     RECT  73.242 0.108 73.44 0.144 ;
     RECT  73.458 0.108 73.692 0.144 ;
     RECT  73.71 0.108 73.944 0.144 ;
     RECT  73.962 0.108 74.196 0.144 ;
     RECT  74.214 0.108 74.412 0.144 ;
     RECT  74.43 0.108 74.664 0.144 ;
     RECT  74.682 0.108 74.916 0.144 ;
     RECT  74.934 0.108 75.168 0.144 ;
     RECT  75.186 0.108 75.42 0.144 ;
     RECT  75.438 0.108 75.636 0.144 ;
     RECT  75.654 0.108 75.888 0.144 ;
     RECT  75.906 0.108 76.14 0.144 ;
     RECT  76.158 0.108 76.392 0.144 ;
     RECT  76.41 0.108 76.608 0.144 ;
     RECT  76.626 0.108 76.86 0.144 ;
     RECT  76.878 0.108 77.112 0.144 ;
     RECT  77.13 0.108 77.364 0.144 ;
     RECT  77.382 0.108 77.616 0.144 ;
     RECT  77.634 0.108 77.832 0.144 ;
     RECT  77.85 0.108 78.084 0.144 ;
     RECT  78.102 0.108 78.336 0.144 ;
     RECT  78.354 0.108 78.588 0.144 ;
     RECT  78.606 0.108 78.84 0.144 ;
     RECT  78.858 0.108 79.056 0.144 ;
     RECT  79.074 0.108 79.308 0.144 ;
     RECT  79.326 0.108 79.56 0.144 ;
     RECT  79.578 0.108 79.812 0.144 ;
     RECT  79.83 0.108 80.028 0.144 ;
     RECT  80.046 0.108 80.28 0.144 ;
     RECT  80.298 0.108 80.532 0.144 ;
     RECT  80.55 0.108 80.784 0.144 ;
     RECT  80.802 0.108 81.036 0.144 ;
     RECT  81.054 0.108 81.252 0.144 ;
     RECT  81.27 0.108 81.504 0.144 ;
     RECT  81.522 0.108 81.756 0.144 ;
     RECT  81.774 0.108 82.008 0.144 ;
     RECT  82.026 0.108 82.224 0.144 ;
     RECT  82.242 0.108 82.476 0.144 ;
     RECT  82.494 0.108 82.728 0.144 ;
     RECT  82.746 0.108 82.98 0.144 ;
     RECT  82.998 0.108 83.232 0.144 ;
     RECT  83.25 0.108 83.448 0.144 ;
     RECT  83.466 0.108 83.7 0.144 ;
     RECT  83.718 0.108 83.952 0.144 ;
     RECT  83.97 0.108 84.204 0.144 ;
     RECT  84.222 0.108 84.42 0.144 ;
     RECT  84.438 0.108 84.672 0.144 ;
     RECT  84.69 0.108 84.924 0.144 ;
     RECT  84.942 0.108 85.176 0.144 ;
     RECT  85.194 0.108 85.428 0.144 ;
     RECT  85.446 0.108 85.644 0.144 ;
     RECT  85.662 0.108 85.896 0.144 ;
     RECT  85.914 0.108 86.148 0.144 ;
     RECT  86.166 0.108 86.4 0.144 ;
     RECT  86.418 0.108 86.616 0.144 ;
     RECT  86.634 0.108 86.868 0.144 ;
     RECT  86.886 0.108 87.12 0.144 ;
     RECT  87.138 0.108 87.372 0.144 ;
     RECT  87.39 0.108 87.624 0.144 ;
     RECT  87.642 0.108 87.84 0.144 ;
     RECT  87.858 0.108 88.092 0.144 ;
     RECT  88.11 0.108 88.344 0.144 ;
     RECT  88.362 0.108 88.596 0.144 ;
     RECT  88.614 0.108 88.848 0.144 ;
     RECT  88.866 0.108 89.064 0.144 ;
     RECT  89.082 0.108 89.316 0.144 ;
     RECT  89.334 0.108 89.568 0.144 ;
     RECT  89.586 0.108 89.82 0.144 ;
     RECT  89.838 0.108 90.036 0.144 ;
     RECT  90.054 0.108 90.288 0.144 ;
     RECT  90.306 0.108 90.54 0.144 ;
     RECT  90.558 0.108 90.792 0.144 ;
     RECT  90.81 0.108 91.044 0.144 ;
     RECT  91.062 0.108 91.26 0.144 ;
     RECT  91.278 0.108 91.512 0.144 ;
     RECT  91.53 0.108 91.764 0.144 ;
     RECT  91.782 0.108 92.016 0.144 ;
     RECT  92.034 0.108 92.232 0.144 ;
     RECT  92.25 0.108 92.484 0.144 ;
     RECT  92.502 0.108 92.736 0.144 ;
     RECT  92.754 0.108 92.988 0.144 ;
     RECT  93.006 0.108 93.24 0.144 ;
     RECT  93.258 0.108 93.456 0.144 ;
     RECT  93.474 0.108 93.708 0.144 ;
     RECT  93.726 0.108 93.96 0.144 ;
     RECT  93.978 0.108 94.212 0.144 ;
     RECT  94.23 0.108 94.428 0.144 ;
     RECT  94.446 0.108 94.68 0.144 ;
     RECT  94.698 0.108 94.932 0.144 ;
     RECT  94.95 0.108 95.184 0.144 ;
     RECT  95.202 0.108 95.436 0.144 ;
     RECT  95.454 0.108 95.652 0.144 ;
     RECT  95.67 0.108 95.904 0.144 ;
     RECT  95.922 0.108 96.156 0.144 ;
     RECT  96.174 0.108 96.408 0.144 ;
     RECT  96.426 0.108 96.624 0.144 ;
     RECT  96.642 0.108 96.876 0.144 ;
     RECT  96.894 0.108 97.128 0.144 ;
     RECT  4.356 0.144 97.146 0.173 ;
     RECT  4.356 0.173 75.654 1.723 ;
     RECT  76.392 0.173 97.146 1.723 ;
     RECT  4.356 1.723 97.146 2.029 ;
     RECT  4.248 2.029 97.146 2.101 ;
     RECT  3.708 2.101 97.146 2.191 ;
     RECT  3.708 2.191 97.362 2.263 ;
     RECT  3.708 2.263 97.398 2.371 ;
     RECT  98.172 2.191 98.19 2.371 ;
     RECT  2.415 2.143 2.505 2.413 ;
     RECT  3.708 2.371 98.262 2.767 ;
     RECT  3.708 2.767 98.334 3.181 ;
     RECT  3.672 3.181 98.334 3.437 ;
     RECT  4.248 3.437 98.334 3.451 ;
     RECT  4.248 3.451 98.406 3.725 ;
     RECT  4.5 3.725 98.406 4.081 ;
     RECT  4.5 4.081 98.442 4.261 ;
     RECT  4.5 4.261 98.766 4.379 ;
     RECT  4.5 4.379 98.694 6.539 ;
     RECT  79.956 6.539 98.694 6.809 ;
     RECT  8.82 6.539 68.49 7.079 ;
     RECT  53.028 7.079 68.49 7.435 ;
     RECT  69.264 6.539 79.218 7.435 ;
     RECT  8.82 7.079 52.254 7.619 ;
     RECT  53.028 7.435 79.218 7.861 ;
     RECT  79.956 6.809 84.726 7.933 ;
     RECT  85.5 6.809 98.694 7.933 ;
     RECT  52.92 7.861 79.218 8.041 ;
     RECT  79.956 7.933 98.694 8.041 ;
     RECT  52.92 8.041 98.694 8.851 ;
     RECT  8.82 7.619 52.146 8.941 ;
     RECT  52.92 8.851 98.73 8.941 ;
     RECT  8.82 8.941 98.73 9.275 ;
     RECT  4.5 6.539 8.097 10.355 ;
     RECT  4.716 10.355 8.097 11.281 ;
     RECT  8.82 9.275 52.038 11.281 ;
     RECT  52.776 9.275 98.73 11.281 ;
     RECT  4.716 11.281 98.73 11.705 ;
     RECT  4.716 11.705 98.586 11.975 ;
     RECT  4.716 11.975 98.478 17.491 ;
     RECT  4.5 17.491 98.478 17.581 ;
     RECT  4.5 17.581 98.514 18.995 ;
     RECT  4.572 18.995 98.514 19.111 ;
     RECT  4.572 19.111 98.586 19.265 ;
     RECT  4.608 19.265 98.586 20.191 ;
     RECT  4.5 20.191 98.586 27.905 ;
     RECT  4.5 27.905 98.01 27.977 ;
     RECT  4.5 27.977 97.902 28.831 ;
     RECT  2.415 2.413 2.697 34.307 ;
     RECT  2.415 34.307 2.505 34.577 ;
     RECT  4.356 28.831 97.902 34.685 ;
     RECT  4.356 34.685 10.242 35.896 ;
     RECT  11.052 34.685 97.902 35.896 ;
     RECT  4.356 35.896 97.902 35.924 ;
     RECT  97.884 35.924 97.902 35.933 ;
     RECT  4.356 35.924 97.146 36.576 ;
     RECT  4.374 36.576 4.608 36.588 ;
     RECT  4.626 36.576 4.86 36.588 ;
     RECT  4.878 36.576 5.112 36.588 ;
     RECT  5.13 36.576 5.364 36.588 ;
     RECT  5.382 36.576 5.58 36.588 ;
     RECT  5.598 36.576 5.832 36.588 ;
     RECT  5.85 36.576 6.084 36.588 ;
     RECT  6.102 36.576 6.336 36.588 ;
     RECT  6.354 36.576 6.552 36.588 ;
     RECT  6.57 36.576 6.804 36.588 ;
     RECT  6.822 36.576 7.056 36.588 ;
     RECT  7.074 36.576 7.308 36.588 ;
     RECT  7.326 36.576 7.56 36.588 ;
     RECT  7.578 36.576 7.776 36.588 ;
     RECT  7.794 36.576 8.028 36.588 ;
     RECT  8.046 36.576 8.28 36.588 ;
     RECT  8.298 36.576 8.532 36.588 ;
     RECT  8.55 36.576 8.748 36.588 ;
     RECT  8.766 36.576 9 36.588 ;
     RECT  9.018 36.576 9.252 36.588 ;
     RECT  9.27 36.576 9.504 36.588 ;
     RECT  9.522 36.576 9.756 36.588 ;
     RECT  9.774 36.576 9.972 36.588 ;
     RECT  9.99 36.576 10.224 36.588 ;
     RECT  10.242 36.576 10.476 36.588 ;
     RECT  10.494 36.576 10.728 36.588 ;
     RECT  10.746 36.576 10.98 36.588 ;
     RECT  10.998 36.576 11.196 36.588 ;
     RECT  11.214 36.576 11.448 36.588 ;
     RECT  11.466 36.576 11.7 36.588 ;
     RECT  11.718 36.576 11.952 36.588 ;
     RECT  11.97 36.576 12.168 36.588 ;
     RECT  12.186 36.576 12.42 36.588 ;
     RECT  12.438 36.576 12.672 36.588 ;
     RECT  12.69 36.576 12.924 36.588 ;
     RECT  12.942 36.576 13.176 36.588 ;
     RECT  13.194 36.576 13.392 36.588 ;
     RECT  13.41 36.576 13.644 36.588 ;
     RECT  13.662 36.576 13.896 36.588 ;
     RECT  13.914 36.576 14.148 36.588 ;
     RECT  14.166 36.576 14.364 36.588 ;
     RECT  14.382 36.576 14.616 36.588 ;
     RECT  14.634 36.576 14.868 36.588 ;
     RECT  14.886 36.576 15.12 36.588 ;
     RECT  15.138 36.576 15.372 36.588 ;
     RECT  15.39 36.576 15.588 36.588 ;
     RECT  15.606 36.576 15.84 36.588 ;
     RECT  15.858 36.576 16.092 36.588 ;
     RECT  16.11 36.576 16.344 36.588 ;
     RECT  16.362 36.576 16.56 36.588 ;
     RECT  16.578 36.576 16.812 36.588 ;
     RECT  16.83 36.576 17.064 36.588 ;
     RECT  17.082 36.576 17.316 36.588 ;
     RECT  17.334 36.576 17.568 36.588 ;
     RECT  17.586 36.576 17.784 36.588 ;
     RECT  17.802 36.576 18.036 36.588 ;
     RECT  18.054 36.576 18.288 36.588 ;
     RECT  18.306 36.576 18.54 36.588 ;
     RECT  18.558 36.576 18.756 36.588 ;
     RECT  18.774 36.576 19.008 36.588 ;
     RECT  19.026 36.576 19.26 36.588 ;
     RECT  19.278 36.576 19.512 36.588 ;
     RECT  19.53 36.576 19.764 36.588 ;
     RECT  19.782 36.576 19.98 36.588 ;
     RECT  19.998 36.576 20.232 36.588 ;
     RECT  20.25 36.576 20.484 36.588 ;
     RECT  20.502 36.576 20.736 36.588 ;
     RECT  20.754 36.576 20.988 36.588 ;
     RECT  21.006 36.576 21.204 36.588 ;
     RECT  21.222 36.576 21.456 36.588 ;
     RECT  21.474 36.576 21.708 36.588 ;
     RECT  21.726 36.576 21.96 36.588 ;
     RECT  21.978 36.576 22.176 36.588 ;
     RECT  22.194 36.576 22.428 36.588 ;
     RECT  22.446 36.576 22.68 36.588 ;
     RECT  22.698 36.576 22.932 36.588 ;
     RECT  22.95 36.576 23.184 36.588 ;
     RECT  23.202 36.576 23.4 36.588 ;
     RECT  23.418 36.576 23.652 36.588 ;
     RECT  23.67 36.576 23.904 36.588 ;
     RECT  23.922 36.576 24.156 36.588 ;
     RECT  24.174 36.576 24.372 36.588 ;
     RECT  24.39 36.576 24.624 36.588 ;
     RECT  24.642 36.576 24.876 36.588 ;
     RECT  24.894 36.576 25.128 36.588 ;
     RECT  25.146 36.576 25.38 36.588 ;
     RECT  25.398 36.576 25.596 36.588 ;
     RECT  25.614 36.576 25.848 36.588 ;
     RECT  25.866 36.576 26.1 36.588 ;
     RECT  26.118 36.576 26.352 36.588 ;
     RECT  26.37 36.576 26.568 36.588 ;
     RECT  26.586 36.576 26.82 36.588 ;
     RECT  26.838 36.576 27.072 36.588 ;
     RECT  27.09 36.576 27.324 36.588 ;
     RECT  27.342 36.576 27.576 36.588 ;
     RECT  27.594 36.576 27.792 36.588 ;
     RECT  27.81 36.576 28.044 36.588 ;
     RECT  28.062 36.576 28.296 36.588 ;
     RECT  28.314 36.576 28.548 36.588 ;
     RECT  28.566 36.576 28.8 36.588 ;
     RECT  28.818 36.576 29.016 36.588 ;
     RECT  29.034 36.576 29.268 36.588 ;
     RECT  29.286 36.576 29.52 36.588 ;
     RECT  29.538 36.576 29.772 36.588 ;
     RECT  29.79 36.576 29.988 36.588 ;
     RECT  30.006 36.576 30.24 36.588 ;
     RECT  30.258 36.576 30.492 36.588 ;
     RECT  30.51 36.576 30.744 36.588 ;
     RECT  30.762 36.576 30.996 36.588 ;
     RECT  31.014 36.576 31.212 36.588 ;
     RECT  31.23 36.576 31.464 36.588 ;
     RECT  31.482 36.576 31.716 36.588 ;
     RECT  31.734 36.576 31.968 36.588 ;
     RECT  31.986 36.576 32.184 36.588 ;
     RECT  32.202 36.576 32.436 36.588 ;
     RECT  32.454 36.576 32.688 36.588 ;
     RECT  32.706 36.576 32.94 36.588 ;
     RECT  32.958 36.576 33.192 36.588 ;
     RECT  33.21 36.576 33.408 36.588 ;
     RECT  33.426 36.576 33.66 36.588 ;
     RECT  33.678 36.576 33.912 36.588 ;
     RECT  33.93 36.576 34.164 36.588 ;
     RECT  34.182 36.576 34.38 36.588 ;
     RECT  34.398 36.576 34.632 36.588 ;
     RECT  34.65 36.576 34.884 36.588 ;
     RECT  34.902 36.576 35.136 36.588 ;
     RECT  35.154 36.576 35.388 36.588 ;
     RECT  35.406 36.576 35.604 36.588 ;
     RECT  35.622 36.576 35.856 36.588 ;
     RECT  35.874 36.576 36.108 36.588 ;
     RECT  36.126 36.576 36.36 36.588 ;
     RECT  36.378 36.576 36.576 36.588 ;
     RECT  36.594 36.576 36.828 36.588 ;
     RECT  36.846 36.576 37.08 36.588 ;
     RECT  37.098 36.576 37.332 36.588 ;
     RECT  37.35 36.576 37.584 36.588 ;
     RECT  37.602 36.576 37.8 36.588 ;
     RECT  37.818 36.576 38.052 36.588 ;
     RECT  38.07 36.576 38.304 36.588 ;
     RECT  38.322 36.576 38.556 36.588 ;
     RECT  38.574 36.576 38.808 36.588 ;
     RECT  38.826 36.576 39.024 36.588 ;
     RECT  39.042 36.576 39.276 36.588 ;
     RECT  39.294 36.576 39.528 36.588 ;
     RECT  39.546 36.576 39.78 36.588 ;
     RECT  39.798 36.576 39.996 36.588 ;
     RECT  40.014 36.576 40.248 36.588 ;
     RECT  40.266 36.576 40.5 36.588 ;
     RECT  40.518 36.576 40.752 36.588 ;
     RECT  40.77 36.576 41.004 36.588 ;
     RECT  41.022 36.576 41.22 36.588 ;
     RECT  41.238 36.576 41.472 36.588 ;
     RECT  41.49 36.576 41.724 36.588 ;
     RECT  41.742 36.576 41.976 36.588 ;
     RECT  41.994 36.576 42.192 36.588 ;
     RECT  42.21 36.576 42.444 36.588 ;
     RECT  42.462 36.576 42.696 36.588 ;
     RECT  42.714 36.576 42.948 36.588 ;
     RECT  42.966 36.576 43.2 36.588 ;
     RECT  43.218 36.576 43.416 36.588 ;
     RECT  43.434 36.576 43.668 36.588 ;
     RECT  43.686 36.576 43.92 36.588 ;
     RECT  43.938 36.576 44.172 36.588 ;
     RECT  44.19 36.576 44.388 36.588 ;
     RECT  44.406 36.576 44.64 36.588 ;
     RECT  44.658 36.576 44.892 36.588 ;
     RECT  44.91 36.576 45.144 36.588 ;
     RECT  45.162 36.576 45.396 36.588 ;
     RECT  45.414 36.576 45.612 36.588 ;
     RECT  45.63 36.576 45.864 36.588 ;
     RECT  45.882 36.576 46.116 36.588 ;
     RECT  46.134 36.576 46.368 36.588 ;
     RECT  46.386 36.576 46.584 36.588 ;
     RECT  46.602 36.576 46.836 36.588 ;
     RECT  46.854 36.576 47.088 36.588 ;
     RECT  47.106 36.576 47.34 36.588 ;
     RECT  47.358 36.576 47.592 36.588 ;
     RECT  47.61 36.576 47.808 36.588 ;
     RECT  47.826 36.576 48.06 36.588 ;
     RECT  48.078 36.576 48.312 36.588 ;
     RECT  48.33 36.576 48.564 36.588 ;
     RECT  48.582 36.576 48.816 36.588 ;
     RECT  48.834 36.576 49.032 36.588 ;
     RECT  49.05 36.576 49.284 36.588 ;
     RECT  49.302 36.576 49.536 36.588 ;
     RECT  49.554 36.576 49.788 36.588 ;
     RECT  49.806 36.576 50.004 36.588 ;
     RECT  50.022 36.576 50.256 36.588 ;
     RECT  50.274 36.576 50.508 36.588 ;
     RECT  50.526 36.576 50.76 36.588 ;
     RECT  50.778 36.576 51.012 36.588 ;
     RECT  51.03 36.576 51.228 36.588 ;
     RECT  51.246 36.576 51.48 36.588 ;
     RECT  51.498 36.576 51.732 36.588 ;
     RECT  51.75 36.576 51.984 36.588 ;
     RECT  52.002 36.576 52.2 36.588 ;
     RECT  52.218 36.576 52.452 36.588 ;
     RECT  52.47 36.576 52.704 36.588 ;
     RECT  52.722 36.576 52.956 36.588 ;
     RECT  52.974 36.576 53.208 36.588 ;
     RECT  53.226 36.576 53.424 36.588 ;
     RECT  53.442 36.576 53.676 36.588 ;
     RECT  53.694 36.576 53.928 36.588 ;
     RECT  53.946 36.576 54.18 36.588 ;
     RECT  54.198 36.576 54.396 36.588 ;
     RECT  54.414 36.576 54.648 36.588 ;
     RECT  54.666 36.576 54.9 36.588 ;
     RECT  54.918 36.576 55.152 36.588 ;
     RECT  55.17 36.576 55.404 36.588 ;
     RECT  55.422 36.576 55.62 36.588 ;
     RECT  55.638 36.576 55.872 36.588 ;
     RECT  55.89 36.576 56.124 36.588 ;
     RECT  56.142 36.576 56.376 36.588 ;
     RECT  56.394 36.576 56.592 36.588 ;
     RECT  56.61 36.576 56.844 36.588 ;
     RECT  56.862 36.576 57.096 36.588 ;
     RECT  57.114 36.576 57.348 36.588 ;
     RECT  57.366 36.576 57.6 36.588 ;
     RECT  57.618 36.576 57.816 36.588 ;
     RECT  57.834 36.576 58.068 36.588 ;
     RECT  58.086 36.576 58.32 36.588 ;
     RECT  58.338 36.576 58.572 36.588 ;
     RECT  58.59 36.576 58.824 36.588 ;
     RECT  58.842 36.576 59.04 36.588 ;
     RECT  59.058 36.576 59.292 36.588 ;
     RECT  59.31 36.576 59.544 36.588 ;
     RECT  59.562 36.576 59.796 36.588 ;
     RECT  59.814 36.576 60.012 36.588 ;
     RECT  60.03 36.576 60.264 36.588 ;
     RECT  60.282 36.576 60.516 36.588 ;
     RECT  60.534 36.576 60.768 36.588 ;
     RECT  60.786 36.576 61.02 36.588 ;
     RECT  61.038 36.576 61.236 36.588 ;
     RECT  61.254 36.576 61.488 36.588 ;
     RECT  61.506 36.576 61.74 36.588 ;
     RECT  61.758 36.576 61.992 36.588 ;
     RECT  62.01 36.576 62.208 36.588 ;
     RECT  62.226 36.576 62.46 36.588 ;
     RECT  62.478 36.576 62.712 36.588 ;
     RECT  62.73 36.576 62.964 36.588 ;
     RECT  62.982 36.576 63.216 36.588 ;
     RECT  63.234 36.576 63.432 36.588 ;
     RECT  63.45 36.576 63.684 36.588 ;
     RECT  63.702 36.576 63.936 36.588 ;
     RECT  63.954 36.576 64.188 36.588 ;
     RECT  64.206 36.576 64.404 36.588 ;
     RECT  64.422 36.576 64.656 36.588 ;
     RECT  64.674 36.576 64.908 36.588 ;
     RECT  64.926 36.576 65.16 36.588 ;
     RECT  65.178 36.576 65.412 36.588 ;
     RECT  65.43 36.576 65.628 36.588 ;
     RECT  65.646 36.576 65.88 36.588 ;
     RECT  65.898 36.576 66.132 36.588 ;
     RECT  66.15 36.576 66.384 36.588 ;
     RECT  66.402 36.576 66.6 36.588 ;
     RECT  66.618 36.576 66.852 36.588 ;
     RECT  66.87 36.576 67.104 36.588 ;
     RECT  67.122 36.576 67.356 36.588 ;
     RECT  67.374 36.576 67.608 36.588 ;
     RECT  67.626 36.576 67.824 36.588 ;
     RECT  67.842 36.576 68.076 36.588 ;
     RECT  68.094 36.576 68.328 36.588 ;
     RECT  68.346 36.576 68.58 36.588 ;
     RECT  68.598 36.576 68.832 36.588 ;
     RECT  68.85 36.576 69.048 36.588 ;
     RECT  69.066 36.576 69.3 36.588 ;
     RECT  69.318 36.576 69.552 36.588 ;
     RECT  69.57 36.576 69.804 36.588 ;
     RECT  69.822 36.576 70.02 36.588 ;
     RECT  70.038 36.576 70.272 36.588 ;
     RECT  70.29 36.576 70.524 36.588 ;
     RECT  70.542 36.576 70.776 36.588 ;
     RECT  70.794 36.576 71.028 36.588 ;
     RECT  71.046 36.576 71.244 36.588 ;
     RECT  71.262 36.576 71.496 36.588 ;
     RECT  71.514 36.576 71.748 36.588 ;
     RECT  71.766 36.576 72 36.588 ;
     RECT  72.018 36.576 72.216 36.588 ;
     RECT  72.234 36.576 72.468 36.588 ;
     RECT  72.486 36.576 72.72 36.588 ;
     RECT  72.738 36.576 72.972 36.588 ;
     RECT  72.99 36.576 73.224 36.588 ;
     RECT  73.242 36.576 73.44 36.588 ;
     RECT  73.458 36.576 73.692 36.588 ;
     RECT  73.71 36.576 73.944 36.588 ;
     RECT  73.962 36.576 74.196 36.588 ;
     RECT  74.214 36.576 74.412 36.588 ;
     RECT  74.43 36.576 74.664 36.588 ;
     RECT  74.682 36.576 74.916 36.588 ;
     RECT  74.934 36.576 75.168 36.588 ;
     RECT  75.186 36.576 75.42 36.588 ;
     RECT  75.438 36.576 75.636 36.588 ;
     RECT  75.654 36.576 75.888 36.588 ;
     RECT  75.906 36.576 76.14 36.588 ;
     RECT  76.158 36.576 76.392 36.588 ;
     RECT  76.41 36.576 76.608 36.588 ;
     RECT  76.626 36.576 76.86 36.588 ;
     RECT  76.878 36.576 77.112 36.588 ;
     RECT  77.13 36.576 77.364 36.588 ;
     RECT  77.382 36.576 77.616 36.588 ;
     RECT  77.634 36.576 77.832 36.588 ;
     RECT  77.85 36.576 78.084 36.588 ;
     RECT  78.102 36.576 78.336 36.588 ;
     RECT  78.354 36.576 78.588 36.588 ;
     RECT  78.606 36.576 78.84 36.588 ;
     RECT  78.858 36.576 79.056 36.588 ;
     RECT  79.074 36.576 79.308 36.588 ;
     RECT  79.326 36.576 79.56 36.588 ;
     RECT  79.578 36.576 79.812 36.588 ;
     RECT  79.83 36.576 80.028 36.588 ;
     RECT  80.046 36.576 80.28 36.588 ;
     RECT  80.298 36.576 80.532 36.588 ;
     RECT  80.55 36.576 80.784 36.588 ;
     RECT  80.802 36.576 81.036 36.588 ;
     RECT  81.054 36.576 81.252 36.588 ;
     RECT  81.27 36.576 81.504 36.588 ;
     RECT  81.522 36.576 81.756 36.588 ;
     RECT  81.774 36.576 82.008 36.588 ;
     RECT  82.026 36.576 82.224 36.588 ;
     RECT  82.242 36.576 82.476 36.588 ;
     RECT  82.494 36.576 82.728 36.588 ;
     RECT  82.746 36.576 82.98 36.588 ;
     RECT  82.998 36.576 83.232 36.588 ;
     RECT  83.25 36.576 83.448 36.588 ;
     RECT  83.466 36.576 83.7 36.588 ;
     RECT  83.718 36.576 83.952 36.588 ;
     RECT  83.97 36.576 84.204 36.588 ;
     RECT  84.222 36.576 84.42 36.588 ;
     RECT  84.438 36.576 84.672 36.588 ;
     RECT  84.69 36.576 84.924 36.588 ;
     RECT  84.942 36.576 85.176 36.588 ;
     RECT  85.194 36.576 85.428 36.588 ;
     RECT  85.446 36.576 85.644 36.588 ;
     RECT  85.662 36.576 85.896 36.588 ;
     RECT  85.914 36.576 86.148 36.588 ;
     RECT  86.166 36.576 86.4 36.588 ;
     RECT  86.418 36.576 86.616 36.588 ;
     RECT  86.634 36.576 86.868 36.588 ;
     RECT  86.886 36.576 87.12 36.588 ;
     RECT  87.138 36.576 87.372 36.588 ;
     RECT  87.39 36.576 87.624 36.588 ;
     RECT  87.642 36.576 87.84 36.588 ;
     RECT  87.858 36.576 88.092 36.588 ;
     RECT  88.11 36.576 88.344 36.588 ;
     RECT  88.362 36.576 88.596 36.588 ;
     RECT  88.614 36.576 88.848 36.588 ;
     RECT  88.866 36.576 89.064 36.588 ;
     RECT  89.082 36.576 89.316 36.588 ;
     RECT  89.334 36.576 89.568 36.588 ;
     RECT  89.586 36.576 89.82 36.588 ;
     RECT  89.838 36.576 90.036 36.588 ;
     RECT  90.054 36.576 90.288 36.588 ;
     RECT  90.306 36.576 90.54 36.588 ;
     RECT  90.558 36.576 90.792 36.588 ;
     RECT  90.81 36.576 91.044 36.588 ;
     RECT  91.062 36.576 91.26 36.588 ;
     RECT  91.278 36.576 91.512 36.588 ;
     RECT  91.53 36.576 91.764 36.588 ;
     RECT  91.782 36.576 92.016 36.588 ;
     RECT  92.034 36.576 92.232 36.588 ;
     RECT  92.25 36.576 92.484 36.588 ;
     RECT  92.502 36.576 92.736 36.588 ;
     RECT  92.754 36.576 92.988 36.588 ;
     RECT  93.006 36.576 93.24 36.588 ;
     RECT  93.258 36.576 93.456 36.588 ;
     RECT  93.474 36.576 93.708 36.588 ;
     RECT  93.726 36.576 93.96 36.588 ;
     RECT  93.978 36.576 94.212 36.588 ;
     RECT  94.23 36.576 94.428 36.588 ;
     RECT  94.446 36.576 94.68 36.588 ;
     RECT  94.698 36.576 94.932 36.588 ;
     RECT  94.95 36.576 95.184 36.588 ;
     RECT  95.202 36.576 95.436 36.588 ;
     RECT  95.454 36.576 95.652 36.588 ;
     RECT  95.67 36.576 95.904 36.588 ;
     RECT  95.922 36.576 96.156 36.588 ;
     RECT  96.174 36.576 96.408 36.588 ;
     RECT  96.426 36.576 96.624 36.588 ;
     RECT  96.642 36.576 96.876 36.588 ;
     RECT  96.894 36.576 97.128 36.588 ;
     RECT  6.372 36.588 6.462 36.653 ;
     RECT  16.848 36.588 16.938 36.653 ;
     RECT  25.164 36.588 25.254 36.653 ;
     RECT  28.08 36.588 28.17 36.653 ;
     RECT  42.624 36.588 42.696 36.653 ;
     RECT  42.714 36.588 42.948 36.653 ;
     RECT  42.966 36.588 43.2 36.653 ;
     RECT  43.218 36.588 43.326 36.653 ;
     RECT  52.488 36.588 52.578 36.653 ;
     RECT  59.076 36.588 59.166 36.653 ;
     RECT  63.468 36.588 63.558 36.653 ;
     RECT  69.084 36.588 69.174 36.653 ;
    LAYER M4 ;
     RECT  0.229 7.104 2.408 7.128 ;
     RECT  2.408 2.148 2.512 34.572 ;
     RECT  2.512 2.418 2.704 34.302 ;
     RECT  2.704 3.408 4.22 3.432 ;
     RECT  4.22 3.408 4.261 3.72 ;
     RECT  4.501 28.464 4.741 28.488 ;
     RECT  4.489 1.728 4.813 1.752 ;
     RECT  4.261 3.408 4.849 4.536 ;
     RECT  4.741 27.888 4.981 28.488 ;
     RECT  4.813 1.728 5.108 1.848 ;
     RECT  4.849 3.408 5.108 4.68 ;
     RECT  2.704 7.104 5.108 7.128 ;
     RECT  4.981 27.888 5.108 29.256 ;
     RECT  5.108 1.728 5.221 34.572 ;
     RECT  5.221 1.728 5.404 34.728 ;
     RECT  5.404 34.704 5.461 34.728 ;
     RECT  5.461 34.704 5.555 34.824 ;
     RECT  5.555 34.8 5.603 34.824 ;
     RECT  5.404 32.4 5.681 33.048 ;
     RECT  5.404 3.024 5.987 5.736 ;
     RECT  5.681 32.4 6.005 32.472 ;
     RECT  5.404 1.728 6.257 1.8 ;
     RECT  6.005 32.4 6.257 32.424 ;
     RECT  5.987 3.024 6.661 4.008 ;
     RECT  5.404 27.888 6.661 28.488 ;
     RECT  5.987 5.088 7.369 5.736 ;
     RECT  6.257 1.728 7.405 1.752 ;
     RECT  6.661 2.88 7.405 4.008 ;
     RECT  7.405 1.728 7.409 4.008 ;
     RECT  7.409 2.148 7.808 4.008 ;
     RECT  7.369 5.088 7.808 6.024 ;
     RECT  5.404 7.104 7.808 7.128 ;
     RECT  6.661 27.888 7.808 29.064 ;
     RECT  7.621 34.704 7.808 34.728 ;
     RECT  7.808 2.148 7.955 34.728 ;
     RECT  7.955 2.148 8.104 34.68 ;
     RECT  7.621 0.288 8.149 0.312 ;
     RECT  8.104 27.888 8.237 28.968 ;
     RECT  8.104 34.56 8.281 34.68 ;
     RECT  8.149 0.192 8.291 0.312 ;
     RECT  8.237 27.888 8.453 28.872 ;
     RECT  8.104 3.408 8.489 7.128 ;
     RECT  8.489 3.408 8.531 4.248 ;
     RECT  8.389 1.728 8.572 1.8 ;
     RECT  8.572 1.728 8.621 1.752 ;
     RECT  8.621 1.152 8.705 1.752 ;
     RECT  8.453 28.32 8.777 28.872 ;
     RECT  7.429 35.904 8.813 35.928 ;
     RECT  8.104 31.296 9.317 31.32 ;
     RECT  9.109 35.328 9.533 35.352 ;
     RECT  10.261 33.216 10.277 33.24 ;
     RECT  8.705 1.728 10.309 1.752 ;
     RECT  8.531 4.224 10.309 4.248 ;
     RECT  8.777 28.32 10.309 28.488 ;
     RECT  10.277 33.12 10.316 33.24 ;
     RECT  10.309 1.728 10.321 2.52 ;
     RECT  10.309 3.84 10.321 4.248 ;
     RECT  10.309 28.272 10.357 28.488 ;
     RECT  10.321 1.728 10.508 4.248 ;
     RECT  8.489 5.232 10.508 7.128 ;
     RECT  10.357 28.176 10.508 28.488 ;
     RECT  10.316 33.12 10.508 33.336 ;
     RECT  10.261 34.704 10.508 34.728 ;
     RECT  10.508 1.728 10.804 34.728 ;
     RECT  10.804 28.176 10.937 29.064 ;
     RECT  10.804 34.56 10.945 34.728 ;
     RECT  10.837 0.192 10.979 0.216 ;
     RECT  10.804 3.408 11.225 7.656 ;
     RECT  11.225 3.408 11.369 3.432 ;
     RECT  10.937 28.272 11.441 29.064 ;
     RECT  10.804 18.672 11.513 18.984 ;
     RECT  11.441 28.32 11.549 29.064 ;
     RECT  11.513 18.672 11.555 18.792 ;
     RECT  11.555 18.768 11.557 18.792 ;
     RECT  11.549 28.32 11.693 28.488 ;
     RECT  11.557 35.328 11.797 35.352 ;
     RECT  11.797 35.328 11.909 35.928 ;
     RECT  10.804 1.728 12.013 1.752 ;
     RECT  11.909 35.904 12.037 35.928 ;
     RECT  12.037 35.904 12.269 35.976 ;
     RECT  11.225 5.088 12.409 7.656 ;
     RECT  12.013 1.728 12.484 1.8 ;
     RECT  12.269 35.952 12.629 35.976 ;
     RECT  11.693 28.416 12.757 28.488 ;
     RECT  12.589 3.408 12.764 3.432 ;
     RECT  12.764 3.12 12.769 3.432 ;
     RECT  12.409 4.464 12.769 7.656 ;
     RECT  12.757 28.272 13.045 28.488 ;
     RECT  12.484 1.728 13.208 1.848 ;
     RECT  12.769 3.12 13.208 7.656 ;
     RECT  13.045 27.888 13.208 28.488 ;
     RECT  13.208 1.728 13.285 34.572 ;
     RECT  13.285 1.728 13.504 34.824 ;
     RECT  13.504 34.8 13.525 34.824 ;
     RECT  13.504 16.8 13.565 16.824 ;
     RECT  13.525 34.8 13.619 34.92 ;
     RECT  13.619 34.896 13.667 34.92 ;
     RECT  13.504 27.888 13.889 29.064 ;
     RECT  14.204 0.528 14.291 0.552 ;
     RECT  13.504 2.88 14.357 2.904 ;
     RECT  13.504 1.728 14.684 1.752 ;
     RECT  13.889 27.888 14.717 28.872 ;
     RECT  14.485 33.024 14.753 33.048 ;
     RECT  13.504 4.464 14.965 7.128 ;
     RECT  15.445 35.328 15.581 35.352 ;
     RECT  14.717 27.888 15.685 28.488 ;
     RECT  14.684 1.728 15.689 2.28 ;
     RECT  14.965 4.464 15.721 7.368 ;
     RECT  15.689 1.776 15.908 2.28 ;
     RECT  15.721 3.648 15.908 7.368 ;
     RECT  15.649 18.816 15.908 18.84 ;
     RECT  15.685 27.888 15.908 29.064 ;
     RECT  15.908 1.776 16.204 34.824 ;
     RECT  15.973 0.192 16.213 0.216 ;
     RECT  16.213 0.192 16.355 0.312 ;
     RECT  16.204 34.8 16.355 34.824 ;
     RECT  16.355 0.288 16.403 0.312 ;
     RECT  16.204 2.928 16.481 7.368 ;
     RECT  16.213 35.904 16.517 35.928 ;
     RECT  16.204 1.776 16.693 1.8 ;
     RECT  16.204 28.32 16.769 29.064 ;
     RECT  16.693 1.728 16.979 1.8 ;
     RECT  16.481 2.928 17.413 2.952 ;
     RECT  17.173 33.024 17.453 33.048 ;
     RECT  16.769 28.416 17.893 29.064 ;
     RECT  17.893 27.888 18.133 29.064 ;
     RECT  16.979 1.728 18.361 1.752 ;
     RECT  17.413 2.88 18.449 2.952 ;
     RECT  16.481 3.936 18.449 7.368 ;
     RECT  18.133 27.84 18.469 29.064 ;
     RECT  18.449 2.88 18.608 7.368 ;
     RECT  18.469 27.696 18.608 29.064 ;
     RECT  18.469 34.8 18.608 34.824 ;
     RECT  18.608 2.148 18.904 34.824 ;
     RECT  18.904 27.696 18.965 28.968 ;
     RECT  18.904 18.72 19.037 18.744 ;
     RECT  18.469 0.192 19.043 0.216 ;
     RECT  18.904 34.8 19.043 34.824 ;
     RECT  18.904 2.88 19.073 7.368 ;
     RECT  18.965 27.696 19.289 28.488 ;
     RECT  19.073 2.928 19.793 7.368 ;
     RECT  19.381 35.328 19.829 35.352 ;
     RECT  19.793 3.984 19.901 7.368 ;
     RECT  19.901 3.984 19.937 4.008 ;
     RECT  19.897 19.92 20.045 19.944 ;
     RECT  19.793 2.928 20.101 2.952 ;
     RECT  19.289 28.32 20.341 28.488 ;
     RECT  19.349 1.728 20.513 1.752 ;
     RECT  20.341 27.792 20.581 28.488 ;
     RECT  20.101 2.88 20.797 2.952 ;
     RECT  20.797 2.88 20.917 3.432 ;
     RECT  19.901 5.088 20.941 7.368 ;
     RECT  20.917 2.832 20.972 3.432 ;
     RECT  20.972 2.784 21.013 3.432 ;
     RECT  20.941 4.416 21.013 7.368 ;
     RECT  21.013 2.784 21.109 7.368 ;
     RECT  21.109 2.148 21.308 7.368 ;
     RECT  20.869 18.624 21.308 18.648 ;
     RECT  20.581 27.792 21.308 29.064 ;
     RECT  21.157 34.8 21.308 34.824 ;
     RECT  21.157 0.192 21.347 0.216 ;
     RECT  21.308 2.148 21.347 34.824 ;
     RECT  21.347 2.148 21.412 34.572 ;
     RECT  21.412 2.148 21.589 34.302 ;
     RECT  21.589 2.016 21.604 34.302 ;
     RECT  21.604 2.016 21.773 2.904 ;
     RECT  21.604 4.416 22.133 7.368 ;
     RECT  21.604 33.024 22.133 33.048 ;
     RECT  21.604 28.416 22.169 28.44 ;
     RECT  22.133 4.704 22.205 7.368 ;
     RECT  21.589 35.904 22.276 35.928 ;
     RECT  21.829 1.728 23.173 1.8 ;
     RECT  21.773 2.88 23.173 2.904 ;
     RECT  22.205 4.704 23.269 7.128 ;
     RECT  22.276 35.904 23.285 35.976 ;
     RECT  23.269 28.464 23.5 28.488 ;
     RECT  23.285 35.952 23.537 35.976 ;
     RECT  23.269 3.936 23.713 7.128 ;
     RECT  22.789 27.312 23.749 27.336 ;
     RECT  23.5 28.416 23.749 28.488 ;
     RECT  23.173 1.728 24.008 2.904 ;
     RECT  23.713 3.936 24.008 7.224 ;
     RECT  23.821 18.48 24.008 18.504 ;
     RECT  23.749 27.312 24.008 28.488 ;
     RECT  23.989 34.8 24.008 34.824 ;
     RECT  23.989 0.192 24.229 0.216 ;
     RECT  24.008 1.728 24.229 34.824 ;
     RECT  24.229 1.728 24.304 34.92 ;
     RECT  24.229 0.192 24.419 0.312 ;
     RECT  24.304 34.8 24.419 34.92 ;
     RECT  24.304 3.888 24.437 7.224 ;
     RECT  24.419 0.192 24.467 0.216 ;
     RECT  24.419 34.896 24.467 34.92 ;
     RECT  24.437 3.888 24.581 5.16 ;
     RECT  24.304 27.888 24.653 29.064 ;
     RECT  24.517 35.904 24.797 35.928 ;
     RECT  24.304 1.728 25.057 1.848 ;
     RECT  24.437 6.336 25.085 7.224 ;
     RECT  24.653 28.32 25.229 29.064 ;
     RECT  24.581 4.224 25.685 5.16 ;
     RECT  25.085 6.336 25.685 7.128 ;
     RECT  25.229 28.32 25.957 28.488 ;
     RECT  25.057 1.728 26.108 1.8 ;
     RECT  25.685 4.224 26.149 7.128 ;
     RECT  26.197 35.328 26.417 35.352 ;
     RECT  26.108 1.728 26.708 2.76 ;
     RECT  26.149 4.128 26.708 7.128 ;
     RECT  25.957 27.888 26.708 28.488 ;
     RECT  26.581 34.8 26.708 34.824 ;
     RECT  26.708 1.728 27.004 34.824 ;
     RECT  26.917 0.192 27.155 0.216 ;
     RECT  27.004 34.8 27.155 34.824 ;
     RECT  27.004 18.528 27.389 18.552 ;
     RECT  26.437 35.904 27.749 35.928 ;
     RECT  27.004 28.32 27.821 28.488 ;
     RECT  27.004 1.728 28.217 7.128 ;
     RECT  27.004 33.024 28.361 33.048 ;
     RECT  28.165 35.328 28.397 35.352 ;
     RECT  27.821 28.32 28.885 28.44 ;
     RECT  28.885 28.32 29.125 28.488 ;
     RECT  29.125 27.888 29.221 28.488 ;
     RECT  28.217 1.728 29.269 2.904 ;
     RECT  28.217 3.888 29.269 7.128 ;
     RECT  29.221 34.896 29.269 34.92 ;
     RECT  29.269 1.728 29.408 7.128 ;
     RECT  29.221 27.696 29.408 28.488 ;
     RECT  28.645 31.2 29.408 31.224 ;
     RECT  29.269 34.8 29.408 34.92 ;
     RECT  29.269 0.192 29.411 0.216 ;
     RECT  29.408 1.728 29.651 34.92 ;
     RECT  29.651 1.728 29.704 34.302 ;
     RECT  29.704 31.2 29.765 31.32 ;
     RECT  29.704 1.728 30.089 7.128 ;
     RECT  29.845 35.904 30.133 35.928 ;
     RECT  30.089 1.776 30.197 7.128 ;
     RECT  29.704 27.696 30.377 28.488 ;
     RECT  29.704 10.272 30.467 10.296 ;
     RECT  29.948 0.144 30.563 0.168 ;
     RECT  29.704 18.72 30.701 18.744 ;
     RECT  30.197 2.256 30.977 7.128 ;
     RECT  30.133 35.904 30.989 35.976 ;
     RECT  30.977 2.256 31.333 7.992 ;
     RECT  31.333 1.728 31.453 7.992 ;
     RECT  31.285 0.288 31.493 0.312 ;
     RECT  31.525 18.768 31.957 18.792 ;
     RECT  31.453 1.728 32.108 8.568 ;
     RECT  31.957 18.768 32.108 19.368 ;
     RECT  30.377 27.888 32.108 28.488 ;
     RECT  29.765 31.296 32.108 31.32 ;
     RECT  32.108 1.728 32.212 34.572 ;
     RECT  32.212 1.728 32.404 34.302 ;
     RECT  32.404 18.768 32.465 19.368 ;
     RECT  32.465 18.768 32.501 18.792 ;
     RECT  30.989 35.904 32.533 35.928 ;
     RECT  32.404 28.416 32.573 28.488 ;
     RECT  32.749 0.192 32.924 0.216 ;
     RECT  32.533 35.904 32.933 35.976 ;
     RECT  32.924 0.144 33.011 0.216 ;
     RECT  32.404 8.544 33.085 8.568 ;
     RECT  33.137 0.528 33.221 0.552 ;
     RECT  32.404 1.728 33.404 2.904 ;
     RECT  32.404 3.936 33.404 7.464 ;
     RECT  32.573 28.416 33.541 28.44 ;
     RECT  33.404 1.728 33.635 7.464 ;
     RECT  33.635 1.728 33.805 7.272 ;
     RECT  32.933 35.904 33.977 35.928 ;
     RECT  33.541 28.416 34.021 28.488 ;
     RECT  34.261 35.328 34.597 35.352 ;
     RECT  34.657 26.784 34.693 26.808 ;
     RECT  34.021 27.888 34.693 28.488 ;
     RECT  34.597 34.704 34.733 35.352 ;
     RECT  34.733 34.704 34.787 34.728 ;
     RECT  33.805 1.728 34.808 1.848 ;
     RECT  33.805 2.832 34.808 7.272 ;
     RECT  34.153 8.544 34.808 8.568 ;
     RECT  34.693 17.376 34.808 17.4 ;
     RECT  34.693 26.784 34.808 28.488 ;
     RECT  34.597 33.072 34.808 33.096 ;
     RECT  34.808 1.728 34.912 34.572 ;
     RECT  34.912 1.728 35.104 34.302 ;
     RECT  34.981 0.288 35.219 0.312 ;
     RECT  35.104 27.696 35.561 28.488 ;
     RECT  34.981 35.904 35.813 35.928 ;
     RECT  35.104 1.728 35.921 7.464 ;
     RECT  35.921 1.728 36.173 7.128 ;
     RECT  35.989 35.328 36.317 35.352 ;
     RECT  36.097 0.144 36.371 0.168 ;
     RECT  36.173 2.208 36.961 7.128 ;
     RECT  37.333 0.192 37.381 0.216 ;
     RECT  37.349 34.608 37.388 34.632 ;
     RECT  37.381 0.192 37.475 0.552 ;
     RECT  37.388 34.608 37.475 34.728 ;
     RECT  36.961 2.208 37.508 7.464 ;
     RECT  36.925 18.768 37.508 18.792 ;
     RECT  35.561 27.888 37.508 28.488 ;
     RECT  35.104 31.296 37.508 31.32 ;
     RECT  37.508 2.148 37.612 34.572 ;
     RECT  37.612 2.256 37.804 34.302 ;
     RECT  37.475 0.288 37.829 0.552 ;
     RECT  37.669 35.904 37.909 35.928 ;
     RECT  37.829 0.288 38.147 0.312 ;
     RECT  37.804 18.672 38.261 18.696 ;
     RECT  37.909 35.904 38.477 35.976 ;
     RECT  37.804 28.416 38.549 28.488 ;
     RECT  37.804 2.256 38.621 8.568 ;
     RECT  38.621 2.256 38.833 7.128 ;
     RECT  38.549 28.416 38.917 28.44 ;
     RECT  38.917 28.272 38.945 28.44 ;
     RECT  38.833 2.208 39.229 7.128 ;
     RECT  38.945 28.272 39.637 28.296 ;
     RECT  39.229 2.112 39.733 7.128 ;
     RECT  39.733 2.112 39.869 7.224 ;
     RECT  39.637 27.888 39.973 28.296 ;
     RECT  40.049 34.56 40.076 34.584 ;
     RECT  40.076 34.56 40.163 34.68 ;
     RECT  39.869 1.728 40.208 7.224 ;
     RECT  38.621 8.544 40.208 8.568 ;
     RECT  39.973 27.888 40.208 28.488 ;
     RECT  39.157 31.296 40.208 31.32 ;
     RECT  39.877 33.072 40.208 33.096 ;
     RECT  40.163 34.56 40.208 34.572 ;
     RECT  40.208 1.728 40.312 34.572 ;
     RECT  40.312 1.728 40.504 34.302 ;
     RECT  40.504 18.816 40.565 18.84 ;
     RECT  38.477 35.904 40.597 35.928 ;
     RECT  40.597 35.904 41.033 35.976 ;
     RECT  38.581 0.144 41.267 0.168 ;
     RECT  41.033 35.952 41.321 35.976 ;
     RECT  40.504 27.888 41.605 28.488 ;
     RECT  40.504 3.936 41.645 7.992 ;
     RECT  41.641 10.848 41.725 10.872 ;
     RECT  41.605 27.84 41.845 28.488 ;
     RECT  40.504 1.728 41.857 2.952 ;
     RECT  41.645 3.936 41.857 7.128 ;
     RECT  41.857 1.728 41.861 7.128 ;
     RECT  41.861 1.776 42.005 7.128 ;
     RECT  42.757 0.384 42.805 0.408 ;
     RECT  42.005 2.148 42.908 7.128 ;
     RECT  42.757 11.424 42.908 11.448 ;
     RECT  42.793 19.104 42.908 19.128 ;
     RECT  41.845 27.84 42.908 29.064 ;
     RECT  42.908 2.148 43.012 34.572 ;
     RECT  42.805 35.904 43.045 35.928 ;
     RECT  42.805 0.288 43.091 0.408 ;
     RECT  43.091 0.288 43.189 0.312 ;
     RECT  43.012 2.148 43.189 34.302 ;
     RECT  43.189 1.776 43.204 34.302 ;
     RECT  43.189 0.192 43.331 0.312 ;
     RECT  43.045 35.904 43.445 35.976 ;
     RECT  43.204 28.32 43.481 29.064 ;
     RECT  43.204 1.776 43.757 7.992 ;
     RECT  43.204 9.12 43.777 9.144 ;
     RECT  43.204 18.768 44.021 18.792 ;
     RECT  43.757 1.728 44.165 7.992 ;
     RECT  43.481 28.32 44.201 28.488 ;
     RECT  44.165 2.256 44.317 7.992 ;
     RECT  44.201 28.416 44.489 28.488 ;
     RECT  43.445 35.904 45.013 35.928 ;
     RECT  44.317 2.256 45.253 7.128 ;
     RECT  45.013 35.904 45.389 35.976 ;
     RECT  44.489 28.416 45.493 28.44 ;
     RECT  45.253 1.728 45.608 7.128 ;
     RECT  45.169 10.848 45.608 10.872 ;
     RECT  45.493 28.416 45.608 28.488 ;
     RECT  44.533 31.2 45.608 31.224 ;
     RECT  45.608 1.728 45.733 34.572 ;
     RECT  45.733 1.728 45.904 35.112 ;
     RECT  45.904 34.896 46.163 35.112 ;
     RECT  45.904 28.368 46.505 29.064 ;
     RECT  45.904 19.488 46.793 19.512 ;
     RECT  45.904 30.768 46.865 30.888 ;
     RECT  46.505 28.368 46.9 28.488 ;
     RECT  46.865 30.864 47.333 30.888 ;
     RECT  45.904 1.728 47.365 7.128 ;
     RECT  46.9 28.32 48.181 28.488 ;
     RECT  47.365 1.728 48.308 7.464 ;
     RECT  47.473 10.848 48.308 10.872 ;
     RECT  48.181 27.648 48.308 28.488 ;
     RECT  48.133 34.8 48.308 34.824 ;
     RECT  48.133 0.288 48.467 0.312 ;
     RECT  48.308 1.728 48.467 34.824 ;
     RECT  48.467 1.728 48.604 34.302 ;
     RECT  48.604 19.632 48.701 19.656 ;
     RECT  48.604 1.728 48.737 3.672 ;
     RECT  48.604 28.464 49.313 28.872 ;
     RECT  49.313 28.848 49.621 28.872 ;
     RECT  46.453 35.904 49.852 35.928 ;
     RECT  48.737 1.776 49.957 3.672 ;
     RECT  48.604 4.704 49.957 7.128 ;
     RECT  48.841 0.144 50.051 0.168 ;
     RECT  49.957 1.776 50.149 7.128 ;
     RECT  49.852 35.904 50.357 35.976 ;
     RECT  49.621 28.848 50.389 29.064 ;
     RECT  50.149 1.728 50.609 7.464 ;
     RECT  50.609 2.148 51.008 7.464 ;
     RECT  50.749 18.768 51.008 18.792 ;
     RECT  50.389 27.888 51.008 29.064 ;
     RECT  50.849 33.024 51.008 33.048 ;
     RECT  50.821 0.288 51.155 0.312 ;
     RECT  51.008 2.148 51.304 34.572 ;
     RECT  51.304 34.56 51.349 34.572 ;
     RECT  51.304 27.84 51.401 28.488 ;
     RECT  51.349 34.56 51.437 34.68 ;
     RECT  51.437 34.56 51.481 34.584 ;
     RECT  51.349 0.192 51.491 0.216 ;
     RECT  51.304 2.148 51.577 7.128 ;
     RECT  51.577 1.728 51.581 7.128 ;
     RECT  51.304 8.544 51.731 8.568 ;
     RECT  51.581 1.728 51.772 6.744 ;
     RECT  51.772 1.728 51.877 6.264 ;
     RECT  51.877 2.88 52.121 6.264 ;
     RECT  51.401 27.84 52.549 28.44 ;
     RECT  52.121 3.312 52.92 6.264 ;
     RECT  52.92 3.312 53.197 6.6 ;
     RECT  53.197 3.312 53.557 6.888 ;
     RECT  50.357 35.904 53.557 35.928 ;
     RECT  51.877 1.728 53.708 1.8 ;
     RECT  53.557 2.88 53.708 6.888 ;
     RECT  53.629 18.528 53.708 18.552 ;
     RECT  52.549 27.84 53.708 28.488 ;
     RECT  53.557 35.328 53.708 35.928 ;
     RECT  53.708 1.728 54.004 35.928 ;
     RECT  54.004 18.528 54.029 18.552 ;
     RECT  54.004 1.728 54.101 6.6 ;
     RECT  54.004 34.56 54.101 35.928 ;
     RECT  53.797 0.288 54.131 0.312 ;
     RECT  54.101 2.88 54.137 6.6 ;
     RECT  54.101 34.56 54.137 34.68 ;
     RECT  54.101 1.728 54.205 1.752 ;
     RECT  54.205 1.152 54.563 1.752 ;
     RECT  54.004 33.072 54.677 33.096 ;
     RECT  54.101 35.904 54.713 35.928 ;
     RECT  54.004 28.368 54.997 28.872 ;
     RECT  54.563 1.728 55.324 1.752 ;
     RECT  54.137 2.88 55.349 2.952 ;
     RECT  55.349 2.88 55.357 3.432 ;
     RECT  54.137 4.416 55.357 6.6 ;
     RECT  54.997 28.368 55.361 29.064 ;
     RECT  55.361 28.368 55.468 28.488 ;
     RECT  55.237 31.296 55.765 31.32 ;
     RECT  55.357 2.88 56.408 6.6 ;
     RECT  55.468 28.32 56.408 28.488 ;
     RECT  55.765 31.2 56.408 31.32 ;
     RECT  56.408 2.148 56.485 34.572 ;
     RECT  56.485 2.148 56.704 34.728 ;
     RECT  56.485 0.288 56.725 0.312 ;
     RECT  56.704 34.704 56.725 34.728 ;
     RECT  56.725 34.704 56.819 34.824 ;
     RECT  56.725 0.192 56.828 0.312 ;
     RECT  56.828 0.192 56.867 0.408 ;
     RECT  56.704 28.368 56.873 28.488 ;
     RECT  56.867 0.288 56.915 0.408 ;
     RECT  56.819 34.8 56.915 34.824 ;
     RECT  56.915 0.288 56.963 0.312 ;
     RECT  56.704 2.148 57.205 3.432 ;
     RECT  56.704 7.968 57.491 7.992 ;
     RECT  56.005 35.904 57.521 35.928 ;
     RECT  56.873 28.368 57.685 28.44 ;
     RECT  57.205 1.728 57.817 3.432 ;
     RECT  57.685 27.888 57.925 28.44 ;
     RECT  57.817 3.408 58.117 3.432 ;
     RECT  56.704 4.416 58.117 6.696 ;
     RECT  58.117 3.408 58.165 6.696 ;
     RECT  58.165 33.024 58.693 33.048 ;
     RECT  58.655 0.576 58.773 0.6 ;
     RECT  57.817 1.728 58.981 2.28 ;
     RECT  58.165 3.408 58.981 6.888 ;
     RECT  58.981 1.728 59.108 6.888 ;
     RECT  58.381 9.12 59.108 9.144 ;
     RECT  58.165 10.848 59.108 10.872 ;
     RECT  57.925 27.888 59.108 28.488 ;
     RECT  58.693 32.832 59.108 33.048 ;
     RECT  58.981 34.8 59.108 34.824 ;
     RECT  59.108 1.728 59.404 34.824 ;
     RECT  59.404 27.888 59.537 28.488 ;
     RECT  59.281 0.144 59.555 0.168 ;
     RECT  59.404 34.8 59.555 34.824 ;
     RECT  59.404 3.936 59.603 7.992 ;
     RECT  59.603 7.968 59.699 7.992 ;
     RECT  59.404 33.024 59.717 33.048 ;
     RECT  59.404 1.728 59.977 2.952 ;
     RECT  59.537 28.32 60.185 28.488 ;
     RECT  59.893 35.328 60.221 35.352 ;
     RECT  60.209 0.528 60.293 0.552 ;
     RECT  59.977 2.256 60.373 2.952 ;
     RECT  59.603 3.936 60.373 6.84 ;
     RECT  60.397 18.672 60.509 18.696 ;
     RECT  60.373 2.256 60.716 6.84 ;
     RECT  60.716 0.144 60.803 0.168 ;
     RECT  60.716 2.256 60.803 7.272 ;
     RECT  60.757 9.12 60.841 9.144 ;
     RECT  60.803 2.256 61.093 6.84 ;
     RECT  60.185 28.416 61.333 28.488 ;
     RECT  61.093 1.728 61.808 6.84 ;
     RECT  61.669 8.16 61.808 8.184 ;
     RECT  61.333 28.416 61.808 28.872 ;
     RECT  61.808 1.728 61.912 34.572 ;
     RECT  60.373 35.904 62.101 35.928 ;
     RECT  61.912 1.728 62.104 34.302 ;
     RECT  61.669 0.288 62.147 0.312 ;
     RECT  62.101 35.904 62.417 35.976 ;
     RECT  62.104 2.736 63.089 6.888 ;
     RECT  63.089 2.736 63.173 6.984 ;
     RECT  62.104 1.728 63.421 1.752 ;
     RECT  63.173 2.736 63.421 6.888 ;
     RECT  63.421 1.728 63.443 6.888 ;
     RECT  62.104 28.416 63.781 29.064 ;
     RECT  62.417 35.904 63.821 35.928 ;
     RECT  63.443 1.728 64.508 6.792 ;
     RECT  63.781 28.368 64.508 29.064 ;
     RECT  63.404 0.144 64.549 0.168 ;
     RECT  64.508 1.728 64.549 34.572 ;
     RECT  64.549 0.144 64.691 0.216 ;
     RECT  64.549 1.728 64.804 34.824 ;
     RECT  64.691 0.192 64.931 0.216 ;
     RECT  64.804 34.8 64.931 34.824 ;
     RECT  64.804 1.728 64.979 7.992 ;
     RECT  64.789 35.904 65.029 35.928 ;
     RECT  65.029 35.904 65.189 35.976 ;
     RECT  64.804 27.792 65.369 28.488 ;
     RECT  64.979 1.728 66.013 7.752 ;
     RECT  66.013 1.728 66.131 7.992 ;
     RECT  66.131 1.728 66.197 7.464 ;
     RECT  65.369 28.32 66.229 28.488 ;
     RECT  66.197 1.728 66.413 6.888 ;
     RECT  66.229 28.32 66.469 28.872 ;
     RECT  66.413 2.148 67.208 6.888 ;
     RECT  66.409 19.344 67.208 19.368 ;
     RECT  66.469 27.888 67.208 28.872 ;
     RECT  67.208 2.148 67.237 34.572 ;
     RECT  66.709 0.192 67.477 0.216 ;
     RECT  67.237 2.148 67.504 34.824 ;
     RECT  67.477 0.192 67.619 0.312 ;
     RECT  67.504 34.8 67.619 34.824 ;
     RECT  67.619 0.288 67.667 0.312 ;
     RECT  67.504 2.148 67.957 7.464 ;
     RECT  65.189 35.904 67.957 35.928 ;
     RECT  67.504 27.792 67.997 28.488 ;
     RECT  67.957 35.328 68.321 35.928 ;
     RECT  68.321 35.904 68.917 35.928 ;
     RECT  67.957 1.728 69.073 7.464 ;
     RECT  69.073 1.728 69.145 7.992 ;
     RECT  68.917 35.904 69.149 35.976 ;
     RECT  67.997 27.792 69.157 28.44 ;
     RECT  69.149 35.952 69.257 35.976 ;
     RECT  69.26 0.144 69.347 0.168 ;
     RECT  69.145 1.728 69.908 8.568 ;
     RECT  69.157 27.792 69.908 29.064 ;
     RECT  69.733 30.672 69.908 30.792 ;
     RECT  69.781 34.8 69.908 34.824 ;
     RECT  69.781 0.528 70.049 0.552 ;
     RECT  69.908 1.728 70.085 34.824 ;
     RECT  70.085 2.016 70.204 34.824 ;
     RECT  70.204 2.016 70.265 7.464 ;
     RECT  70.204 27.888 70.265 29.016 ;
     RECT  70.204 34.8 70.355 34.824 ;
     RECT  70.265 2.496 70.481 7.464 ;
     RECT  70.204 14.832 70.589 14.856 ;
     RECT  70.481 3.888 70.691 7.464 ;
     RECT  70.691 3.888 70.697 6.84 ;
     RECT  70.265 27.888 71.021 28.488 ;
     RECT  70.481 2.496 71.333 2.904 ;
     RECT  71.333 1.728 71.417 2.904 ;
     RECT  71.417 2.256 71.605 2.904 ;
     RECT  70.697 3.888 71.605 5.208 ;
     RECT  71.605 2.256 71.809 5.208 ;
     RECT  70.697 6.192 71.809 6.84 ;
     RECT  71.021 27.888 71.845 28.44 ;
     RECT  71.804 1.104 71.891 1.128 ;
     RECT  70.405 35.904 72.173 35.928 ;
     RECT  71.809 2.256 72.373 6.84 ;
     RECT  72.373 2.256 72.421 6.936 ;
     RECT  72.421 0.288 72.469 0.312 ;
     RECT  71.845 27.792 72.469 28.44 ;
     RECT  72.469 34.8 72.565 34.824 ;
     RECT  72.421 2.256 72.608 7.464 ;
     RECT  71.449 8.544 72.608 8.568 ;
     RECT  72.457 10.896 72.608 10.92 ;
     RECT  72.469 18.192 72.608 18.216 ;
     RECT  72.469 27.36 72.608 28.968 ;
     RECT  72.565 34.8 72.608 35.352 ;
     RECT  72.469 0.192 72.611 0.312 ;
     RECT  72.611 0.288 72.851 0.312 ;
     RECT  72.608 2.148 72.851 35.352 ;
     RECT  72.851 2.148 72.904 34.302 ;
     RECT  72.904 18.192 72.965 18.216 ;
     RECT  72.851 35.328 72.965 35.352 ;
     RECT  72.904 2.148 73.043 7.464 ;
     RECT  72.904 27.888 73.145 28.968 ;
     RECT  73.043 2.832 73.523 7.464 ;
     RECT  72.904 8.544 73.541 8.568 ;
     RECT  73.145 27.888 73.577 28.488 ;
     RECT  73.093 1.728 74.053 1.752 ;
     RECT  73.523 2.832 74.053 7.272 ;
     RECT  73.333 35.904 74.293 35.928 ;
     RECT  74.053 1.728 74.617 7.272 ;
     RECT  74.293 35.328 74.693 35.928 ;
     RECT  73.577 28.416 75.013 28.488 ;
     RECT  74.617 1.728 75.308 7.896 ;
     RECT  75.013 28.416 75.308 28.872 ;
     RECT  74.693 35.328 75.308 35.352 ;
     RECT  75.308 1.728 75.604 35.352 ;
     RECT  75.493 0.192 75.731 0.216 ;
     RECT  75.604 18.48 75.731 18.792 ;
     RECT  75.604 34.8 75.731 35.352 ;
     RECT  75.604 1.728 75.773 8.904 ;
     RECT  75.731 18.768 75.773 18.792 ;
     RECT  75.731 35.328 75.781 35.352 ;
     RECT  75.773 1.728 75.809 8.28 ;
     RECT  75.836 0.144 76.211 0.168 ;
     RECT  75.809 1.728 76.307 7.992 ;
     RECT  75.781 35.328 76.457 35.928 ;
     RECT  76.307 3.408 76.957 7.992 ;
     RECT  76.457 35.328 76.961 35.352 ;
     RECT  75.604 28.464 76.981 28.488 ;
     RECT  76.981 28.416 77.221 28.488 ;
     RECT  76.307 1.728 77.365 2.376 ;
     RECT  76.957 3.408 77.365 8.568 ;
     RECT  77.365 1.728 77.537 8.568 ;
     RECT  77.845 0.192 77.893 0.216 ;
     RECT  77.461 35.904 77.941 35.928 ;
     RECT  77.893 0.192 77.987 0.552 ;
     RECT  77.537 2.148 78.008 8.568 ;
     RECT  77.221 28.368 78.008 28.488 ;
     RECT  75.604 31.296 78.008 31.32 ;
     RECT  77.701 33.024 78.008 33.048 ;
     RECT  78.008 2.148 78.112 34.572 ;
     RECT  77.987 0.288 78.113 0.552 ;
     RECT  77.941 35.904 78.181 35.976 ;
     RECT  78.112 2.148 78.304 34.302 ;
     RECT  78.113 0.288 78.419 0.312 ;
     RECT  78.181 35.328 78.509 35.976 ;
     RECT  78.304 9.12 78.659 9.144 ;
     RECT  78.304 2.148 78.709 6.888 ;
     RECT  78.709 1.728 78.72 6.888 ;
     RECT  78.509 35.904 78.941 35.976 ;
     RECT  78.72 1.728 79.049 1.752 ;
     RECT  78.304 7.968 79.165 7.992 ;
     RECT  78.72 2.88 79.235 6.888 ;
     RECT  78.304 28.464 79.429 28.488 ;
     RECT  79.235 2.88 79.685 6.648 ;
     RECT  79.685 2.784 79.729 6.648 ;
     RECT  79.729 2.256 80.053 6.648 ;
     RECT  78.304 31.296 80.149 31.32 ;
     RECT  80.053 2.16 80.437 6.648 ;
     RECT  80.533 34.8 80.581 34.824 ;
     RECT  80.437 2.16 80.665 6.792 ;
     RECT  80.533 0.192 80.675 0.216 ;
     RECT  80.665 2.016 80.708 6.792 ;
     RECT  79.429 27.888 80.708 28.488 ;
     RECT  80.149 31.2 80.708 31.32 ;
     RECT  80.581 34.8 80.708 34.92 ;
     RECT  80.708 2.016 80.915 34.92 ;
     RECT  80.915 2.418 81.004 34.302 ;
     RECT  81.004 28.272 81.101 28.488 ;
     RECT  78.941 35.904 81.109 35.928 ;
     RECT  81.004 2.688 81.203 6.84 ;
     RECT  81.109 35.328 81.389 35.928 ;
     RECT  81.101 28.416 81.425 28.488 ;
     RECT  81.004 7.968 81.433 8.568 ;
     RECT  81.433 7.968 81.443 7.992 ;
     RECT  81.004 31.2 81.497 31.224 ;
     RECT  81.203 2.784 81.533 6.84 ;
     RECT  81.389 35.904 81.637 35.928 ;
     RECT  81.637 35.904 82.324 35.976 ;
     RECT  82.357 1.728 82.504 1.752 ;
     RECT  82.324 35.904 82.577 36.024 ;
     RECT  82.504 1.728 82.645 1.8 ;
     RECT  81.533 2.784 82.645 2.904 ;
     RECT  81.425 28.464 82.837 28.488 ;
     RECT  82.645 1.728 83.036 2.904 ;
     RECT  81.533 3.936 83.036 6.84 ;
     RECT  82.577 35.952 83.045 36.024 ;
     RECT  83.221 0.192 83.269 0.216 ;
     RECT  83.036 1.728 83.269 6.84 ;
     RECT  82.837 27.888 83.269 28.488 ;
     RECT  83.249 34.56 83.276 34.584 ;
     RECT  83.269 0.192 83.363 6.84 ;
     RECT  83.276 34.56 83.363 34.68 ;
     RECT  83.363 1.152 83.408 6.84 ;
     RECT  83.269 27.888 83.408 28.968 ;
     RECT  83.363 34.56 83.408 34.572 ;
     RECT  83.408 1.152 83.512 34.572 ;
     RECT  83.045 35.952 83.557 35.976 ;
     RECT  83.512 1.152 83.603 34.302 ;
     RECT  83.603 1.728 83.704 34.302 ;
     RECT  83.704 1.728 84.449 6.84 ;
     RECT  84.449 1.728 85.139 6.648 ;
     RECT  83.557 35.904 85.276 35.976 ;
     RECT  85.139 1.728 85.385 1.848 ;
     RECT  85.385 1.824 85.421 1.848 ;
     RECT  85.276 35.904 85.421 36.024 ;
     RECT  83.704 28.32 85.525 29.064 ;
     RECT  85.421 36 85.637 36.024 ;
     RECT  85.525 27.888 85.765 29.064 ;
     RECT  85.139 2.832 85.849 6.648 ;
     RECT  85.949 34.56 85.964 34.584 ;
     RECT  85.849 2.832 86.108 6.696 ;
     RECT  85.765 27.696 86.108 29.064 ;
     RECT  85.964 34.56 86.108 34.68 ;
     RECT  85.909 0.192 86.245 0.216 ;
     RECT  86.108 2.148 86.245 34.68 ;
     RECT  86.245 2.148 86.404 34.728 ;
     RECT  86.245 0.192 86.531 0.312 ;
     RECT  86.404 34.704 86.531 34.728 ;
     RECT  86.531 0.192 86.627 0.216 ;
     RECT  86.404 27.696 86.681 28.488 ;
     RECT  86.404 2.148 86.705 7.224 ;
     RECT  86.485 35.904 86.725 35.928 ;
     RECT  86.681 27.696 86.789 27.912 ;
     RECT  86.725 35.904 86.965 35.976 ;
     RECT  86.705 1.728 87.779 7.224 ;
     RECT  86.965 35.904 88.193 36.024 ;
     RECT  87.973 28.464 88.213 28.488 ;
     RECT  88.189 0.576 88.373 0.6 ;
     RECT  88.213 28.464 88.693 29.064 ;
     RECT  87.779 1.728 88.808 7.128 ;
     RECT  88.549 9.072 88.808 9.096 ;
     RECT  88.693 27.888 88.808 29.064 ;
     RECT  88.808 1.728 88.912 34.572 ;
     RECT  88.912 1.728 89.104 34.302 ;
     RECT  88.193 35.904 89.173 35.928 ;
     RECT  89.104 1.728 89.315 7.176 ;
     RECT  89.104 10.8 89.345 10.824 ;
     RECT  89.173 35.904 89.413 35.976 ;
     RECT  89.104 33.024 89.957 33.048 ;
     RECT  89.413 35.904 90.065 36.024 ;
     RECT  90.065 35.904 90.389 35.976 ;
     RECT  90.181 28.32 90.661 28.344 ;
     RECT  90.661 27.888 90.901 28.344 ;
     RECT  90.389 35.952 91.381 35.976 ;
     RECT  89.315 1.728 91.508 1.752 ;
     RECT  89.315 2.88 91.508 7.176 ;
     RECT  90.901 27.888 91.508 28.488 ;
     RECT  91.508 1.728 91.612 34.572 ;
     RECT  91.612 1.728 91.804 34.302 ;
     RECT  91.804 28.416 91.937 29.064 ;
     RECT  91.804 5.184 91.973 6.84 ;
     RECT  91.861 0.192 92.003 0.216 ;
     RECT  91.381 35.904 92.101 35.976 ;
     RECT  92.293 0.576 92.387 0.6 ;
     RECT  91.804 2.88 92.549 3.624 ;
     RECT  92.101 35.904 92.621 36.024 ;
     RECT  91.973 5.184 93.193 6.408 ;
     RECT  93.193 4.944 93.253 6.408 ;
     RECT  91.804 1.728 93.337 1.752 ;
     RECT  93.349 27.888 93.589 27.912 ;
     RECT  91.937 29.04 93.589 29.064 ;
     RECT  92.549 3.6 93.829 3.624 ;
     RECT  93.253 4.944 93.829 6.504 ;
     RECT  93.589 27.888 94.069 29.064 ;
     RECT  93.337 1.728 94.208 1.848 ;
     RECT  93.829 3.6 94.208 6.504 ;
     RECT  93.193 9.072 94.208 9.096 ;
     RECT  94.069 27.696 94.208 29.064 ;
     RECT  94.208 1.728 94.504 34.572 ;
     RECT  94.504 27.696 94.565 28.872 ;
     RECT  94.504 1.728 94.595 1.848 ;
     RECT  92.621 35.904 94.789 35.976 ;
     RECT  94.504 3.408 94.889 3.624 ;
     RECT  94.565 27.696 95.105 27.72 ;
     RECT  94.504 7.824 95.357 7.848 ;
     RECT  94.789 35.904 95.465 36.024 ;
     RECT  94.565 28.848 95.501 28.872 ;
     RECT  95.269 34.752 95.509 34.776 ;
     RECT  94.889 3.6 95.533 3.624 ;
     RECT  94.504 4.944 95.533 6.312 ;
     RECT  95.509 34.656 95.717 34.776 ;
     RECT  95.717 34.656 95.753 34.68 ;
     RECT  95.465 35.904 96.545 35.976 ;
     RECT  96.517 28.416 96.757 28.44 ;
     RECT  94.595 1.728 96.908 1.8 ;
     RECT  95.533 3.6 96.908 6.552 ;
     RECT  96.757 27.888 96.908 28.44 ;
     RECT  96.908 1.728 97.012 34.572 ;
     RECT  97.012 1.728 97.085 34.302 ;
     RECT  97.085 2.418 97.204 34.302 ;
     RECT  97.204 3.6 97.229 6.12 ;
     RECT  97.229 3.6 97.331 5.976 ;
     RECT  97.204 28.416 97.337 28.44 ;
     RECT  97.331 3.6 97.625 5.496 ;
     RECT  97.625 5.088 97.733 5.496 ;
     RECT  97.733 5.088 97.769 5.112 ;
     RECT  96.545 35.904 97.913 35.928 ;
     RECT  97.625 3.6 97.949 3.624 ;
    LAYER M5 ;
     RECT  30 0.133 30.144 0.144 ;
     RECT  30.168 0.133 30.384 0.144 ;
     RECT  30.408 0.133 30.552 0.144 ;
     RECT  32.976 0.133 33 0.144 ;
     RECT  36.336 0.133 36.36 0.144 ;
     RECT  38.592 0.133 38.688 0.144 ;
     RECT  38.712 0.133 38.928 0.144 ;
     RECT  38.952 0.133 39.168 0.144 ;
     RECT  39.192 0.133 39.408 0.144 ;
     RECT  39.432 0.133 39.648 0.144 ;
     RECT  39.672 0.133 39.888 0.144 ;
     RECT  39.912 0.133 40.128 0.144 ;
     RECT  40.152 0.133 40.368 0.144 ;
     RECT  40.392 0.133 40.608 0.144 ;
     RECT  40.632 0.133 40.848 0.144 ;
     RECT  40.872 0.133 41.088 0.144 ;
     RECT  41.112 0.133 41.256 0.144 ;
     RECT  49.296 0.133 49.392 0.144 ;
     RECT  49.416 0.133 49.632 0.144 ;
     RECT  49.656 0.133 49.872 0.144 ;
     RECT  49.896 0.133 50.04 0.144 ;
     RECT  59.52 0.133 59.544 0.144 ;
     RECT  60.768 0.133 60.792 0.144 ;
     RECT  63.456 0.133 63.552 0.144 ;
     RECT  63.576 0.133 63.792 0.144 ;
     RECT  63.816 0.133 64.032 0.144 ;
     RECT  64.056 0.133 64.272 0.144 ;
     RECT  64.296 0.133 64.56 0.144 ;
     RECT  64.584 0.133 64.68 0.144 ;
     RECT  69.312 0.133 69.336 0.144 ;
     RECT  4.536 0.144 4.752 0.192 ;
     RECT  4.776 0.144 4.992 0.192 ;
     RECT  5.016 0.144 5.232 0.192 ;
     RECT  5.256 0.144 5.472 0.192 ;
     RECT  5.496 0.144 5.712 0.192 ;
     RECT  5.736 0.144 5.952 0.192 ;
     RECT  5.976 0.144 6.192 0.192 ;
     RECT  6.216 0.144 6.432 0.192 ;
     RECT  6.456 0.144 6.672 0.192 ;
     RECT  6.696 0.144 6.912 0.192 ;
     RECT  6.936 0.144 7.2 0.192 ;
     RECT  7.224 0.144 7.44 0.192 ;
     RECT  7.464 0.144 7.68 0.192 ;
     RECT  7.704 0.144 7.92 0.192 ;
     RECT  7.944 0.144 8.16 0.192 ;
     RECT  8.184 0.144 8.4 0.192 ;
     RECT  8.424 0.144 8.64 0.192 ;
     RECT  8.664 0.144 8.88 0.192 ;
     RECT  8.904 0.144 9.12 0.192 ;
     RECT  9.144 0.144 9.36 0.192 ;
     RECT  9.384 0.144 9.6 0.192 ;
     RECT  9.624 0.144 9.84 0.192 ;
     RECT  9.864 0.144 10.128 0.192 ;
     RECT  10.152 0.144 10.368 0.192 ;
     RECT  10.392 0.144 10.608 0.192 ;
     RECT  10.632 0.144 10.848 0.192 ;
     RECT  10.872 0.144 11.088 0.192 ;
     RECT  11.112 0.144 11.328 0.192 ;
     RECT  11.352 0.144 11.568 0.192 ;
     RECT  11.592 0.144 11.808 0.192 ;
     RECT  11.832 0.144 12.048 0.192 ;
     RECT  12.072 0.144 12.288 0.192 ;
     RECT  12.312 0.144 12.528 0.192 ;
     RECT  12.552 0.144 12.768 0.192 ;
     RECT  12.792 0.144 13.056 0.192 ;
     RECT  13.08 0.144 13.296 0.192 ;
     RECT  13.32 0.144 13.536 0.192 ;
     RECT  13.56 0.144 13.776 0.192 ;
     RECT  13.8 0.144 14.016 0.192 ;
     RECT  14.04 0.144 14.256 0.192 ;
     RECT  14.28 0.144 14.496 0.192 ;
     RECT  14.52 0.144 14.736 0.192 ;
     RECT  14.76 0.144 14.976 0.192 ;
     RECT  15 0.144 15.216 0.192 ;
     RECT  15.24 0.144 15.456 0.192 ;
     RECT  15.48 0.144 15.696 0.192 ;
     RECT  15.72 0.144 15.984 0.192 ;
     RECT  16.008 0.144 16.224 0.192 ;
     RECT  16.248 0.144 16.464 0.192 ;
     RECT  16.488 0.144 16.704 0.192 ;
     RECT  16.728 0.144 16.944 0.192 ;
     RECT  16.968 0.144 17.184 0.192 ;
     RECT  17.208 0.144 17.424 0.192 ;
     RECT  17.448 0.144 17.664 0.192 ;
     RECT  17.688 0.144 17.904 0.192 ;
     RECT  17.928 0.144 18.144 0.192 ;
     RECT  18.168 0.144 18.384 0.192 ;
     RECT  18.408 0.144 18.672 0.192 ;
     RECT  18.696 0.144 18.912 0.192 ;
     RECT  18.936 0.144 19.152 0.192 ;
     RECT  19.176 0.144 19.392 0.192 ;
     RECT  19.416 0.144 19.632 0.192 ;
     RECT  19.656 0.144 19.872 0.192 ;
     RECT  19.896 0.144 20.112 0.192 ;
     RECT  20.136 0.144 20.352 0.192 ;
     RECT  20.376 0.144 20.592 0.192 ;
     RECT  20.616 0.144 20.832 0.192 ;
     RECT  20.856 0.144 21.072 0.192 ;
     RECT  21.096 0.144 21.312 0.192 ;
     RECT  21.336 0.144 21.6 0.192 ;
     RECT  21.624 0.144 21.84 0.192 ;
     RECT  21.864 0.144 22.08 0.192 ;
     RECT  22.104 0.144 22.32 0.192 ;
     RECT  22.344 0.144 22.56 0.192 ;
     RECT  22.584 0.144 22.8 0.192 ;
     RECT  22.824 0.144 23.04 0.192 ;
     RECT  23.064 0.144 23.28 0.192 ;
     RECT  23.304 0.144 23.52 0.192 ;
     RECT  23.544 0.144 23.76 0.192 ;
     RECT  23.784 0.144 24 0.192 ;
     RECT  24.024 0.144 24.24 0.192 ;
     RECT  24.264 0.144 24.528 0.192 ;
     RECT  24.552 0.144 24.768 0.192 ;
     RECT  24.792 0.144 25.008 0.192 ;
     RECT  25.032 0.144 25.248 0.192 ;
     RECT  25.272 0.144 25.488 0.192 ;
     RECT  25.512 0.144 25.728 0.192 ;
     RECT  25.752 0.144 25.968 0.192 ;
     RECT  25.992 0.144 26.208 0.192 ;
     RECT  26.232 0.144 26.448 0.192 ;
     RECT  26.472 0.144 26.688 0.192 ;
     RECT  26.712 0.144 26.928 0.192 ;
     RECT  26.952 0.144 27.216 0.192 ;
     RECT  27.24 0.144 27.456 0.192 ;
     RECT  27.48 0.144 27.696 0.192 ;
     RECT  27.72 0.144 27.936 0.192 ;
     RECT  27.96 0.144 28.176 0.192 ;
     RECT  28.2 0.144 28.416 0.192 ;
     RECT  28.44 0.144 28.656 0.192 ;
     RECT  28.68 0.144 28.896 0.192 ;
     RECT  28.92 0.144 29.136 0.192 ;
     RECT  29.16 0.144 29.376 0.192 ;
     RECT  29.4 0.144 29.616 0.192 ;
     RECT  29.64 0.144 29.856 0.192 ;
     RECT  29.88 0.144 30.144 0.192 ;
     RECT  30.168 0.144 30.384 0.192 ;
     RECT  30.408 0.144 30.624 0.192 ;
     RECT  30.648 0.144 30.864 0.192 ;
     RECT  30.888 0.144 31.104 0.192 ;
     RECT  31.128 0.144 31.344 0.192 ;
     RECT  31.368 0.144 31.584 0.192 ;
     RECT  31.608 0.144 31.824 0.192 ;
     RECT  31.848 0.144 32.064 0.192 ;
     RECT  32.088 0.144 32.304 0.192 ;
     RECT  32.328 0.144 32.544 0.192 ;
     RECT  32.568 0.144 32.784 0.192 ;
     RECT  32.808 0.144 33.072 0.192 ;
     RECT  33.096 0.144 33.312 0.192 ;
     RECT  33.336 0.144 33.552 0.192 ;
     RECT  33.576 0.144 33.792 0.192 ;
     RECT  33.816 0.144 34.032 0.192 ;
     RECT  34.056 0.144 34.272 0.192 ;
     RECT  34.296 0.144 34.512 0.192 ;
     RECT  34.536 0.144 34.752 0.192 ;
     RECT  34.776 0.144 34.992 0.192 ;
     RECT  35.016 0.144 35.232 0.192 ;
     RECT  35.256 0.144 35.472 0.192 ;
     RECT  35.496 0.144 35.712 0.192 ;
     RECT  35.736 0.144 36 0.192 ;
     RECT  36.024 0.144 36.24 0.192 ;
     RECT  36.264 0.144 36.48 0.192 ;
     RECT  36.504 0.144 36.72 0.192 ;
     RECT  36.744 0.144 36.96 0.192 ;
     RECT  36.984 0.144 37.2 0.192 ;
     RECT  37.224 0.144 37.44 0.192 ;
     RECT  37.464 0.144 37.68 0.192 ;
     RECT  37.704 0.144 37.92 0.192 ;
     RECT  37.944 0.144 38.16 0.192 ;
     RECT  38.184 0.144 38.4 0.192 ;
     RECT  38.424 0.144 38.688 0.192 ;
     RECT  38.712 0.144 38.928 0.192 ;
     RECT  38.952 0.144 39.168 0.192 ;
     RECT  39.192 0.144 39.408 0.192 ;
     RECT  39.432 0.144 39.648 0.192 ;
     RECT  39.672 0.144 39.888 0.192 ;
     RECT  39.912 0.144 40.128 0.192 ;
     RECT  40.152 0.144 40.368 0.192 ;
     RECT  40.392 0.144 40.608 0.192 ;
     RECT  40.632 0.144 40.848 0.192 ;
     RECT  40.872 0.144 41.088 0.192 ;
     RECT  41.112 0.144 41.328 0.192 ;
     RECT  41.352 0.144 41.616 0.192 ;
     RECT  41.64 0.144 41.856 0.192 ;
     RECT  41.88 0.144 42.096 0.192 ;
     RECT  42.12 0.144 42.336 0.192 ;
     RECT  42.36 0.144 42.576 0.192 ;
     RECT  42.6 0.144 42.816 0.192 ;
     RECT  42.84 0.144 43.056 0.192 ;
     RECT  43.08 0.144 43.296 0.192 ;
     RECT  43.32 0.144 43.536 0.192 ;
     RECT  43.56 0.144 43.776 0.192 ;
     RECT  43.8 0.144 44.016 0.192 ;
     RECT  44.04 0.144 44.256 0.192 ;
     RECT  44.28 0.144 44.544 0.192 ;
     RECT  44.568 0.144 44.784 0.192 ;
     RECT  44.808 0.144 45.024 0.192 ;
     RECT  45.048 0.144 45.264 0.192 ;
     RECT  45.288 0.144 45.504 0.192 ;
     RECT  45.528 0.144 45.744 0.192 ;
     RECT  45.768 0.144 45.984 0.192 ;
     RECT  46.008 0.144 46.224 0.192 ;
     RECT  46.248 0.144 46.464 0.192 ;
     RECT  46.488 0.144 46.704 0.192 ;
     RECT  46.728 0.144 46.944 0.192 ;
     RECT  46.968 0.144 47.232 0.192 ;
     RECT  47.256 0.144 47.472 0.192 ;
     RECT  47.496 0.144 47.712 0.192 ;
     RECT  47.736 0.144 47.952 0.192 ;
     RECT  47.976 0.144 48.192 0.192 ;
     RECT  48.216 0.144 48.432 0.192 ;
     RECT  48.456 0.144 48.672 0.192 ;
     RECT  48.696 0.144 48.912 0.192 ;
     RECT  48.936 0.144 49.152 0.192 ;
     RECT  49.176 0.144 49.392 0.192 ;
     RECT  49.416 0.144 49.632 0.192 ;
     RECT  49.656 0.144 49.872 0.192 ;
     RECT  49.896 0.144 50.16 0.192 ;
     RECT  50.184 0.144 50.4 0.192 ;
     RECT  50.424 0.144 50.64 0.192 ;
     RECT  50.664 0.144 50.88 0.192 ;
     RECT  50.904 0.144 51.12 0.192 ;
     RECT  51.144 0.144 51.36 0.192 ;
     RECT  51.384 0.144 51.6 0.192 ;
     RECT  51.624 0.144 51.84 0.192 ;
     RECT  51.864 0.144 52.08 0.192 ;
     RECT  52.104 0.144 52.32 0.192 ;
     RECT  52.344 0.144 52.56 0.192 ;
     RECT  52.584 0.144 52.8 0.192 ;
     RECT  52.824 0.144 53.088 0.192 ;
     RECT  53.112 0.144 53.328 0.192 ;
     RECT  53.352 0.144 53.568 0.192 ;
     RECT  53.592 0.144 53.808 0.192 ;
     RECT  53.832 0.144 54.048 0.192 ;
     RECT  54.072 0.144 54.288 0.192 ;
     RECT  54.312 0.144 54.528 0.192 ;
     RECT  54.552 0.144 54.768 0.192 ;
     RECT  54.792 0.144 55.008 0.192 ;
     RECT  55.032 0.144 55.248 0.192 ;
     RECT  55.272 0.144 55.488 0.192 ;
     RECT  55.512 0.144 55.776 0.192 ;
     RECT  55.8 0.144 56.016 0.192 ;
     RECT  56.04 0.144 56.256 0.192 ;
     RECT  56.28 0.144 56.496 0.192 ;
     RECT  56.52 0.144 56.736 0.192 ;
     RECT  56.76 0.144 56.976 0.192 ;
     RECT  57 0.144 57.216 0.192 ;
     RECT  57.24 0.144 57.456 0.192 ;
     RECT  57.48 0.144 57.696 0.192 ;
     RECT  57.72 0.144 57.936 0.192 ;
     RECT  57.96 0.144 58.176 0.192 ;
     RECT  58.2 0.144 58.416 0.192 ;
     RECT  58.44 0.144 58.704 0.192 ;
     RECT  58.728 0.144 58.944 0.192 ;
     RECT  58.968 0.144 59.184 0.192 ;
     RECT  59.208 0.144 59.424 0.192 ;
     RECT  59.448 0.144 59.664 0.192 ;
     RECT  59.688 0.144 59.904 0.192 ;
     RECT  59.928 0.144 60.144 0.192 ;
     RECT  60.168 0.144 60.384 0.192 ;
     RECT  60.408 0.144 60.624 0.192 ;
     RECT  60.648 0.144 60.864 0.192 ;
     RECT  60.888 0.144 61.104 0.192 ;
     RECT  61.128 0.144 61.344 0.192 ;
     RECT  61.368 0.144 61.632 0.192 ;
     RECT  61.656 0.144 61.872 0.192 ;
     RECT  61.896 0.144 62.112 0.192 ;
     RECT  62.136 0.144 62.352 0.192 ;
     RECT  62.376 0.144 62.592 0.192 ;
     RECT  62.616 0.144 62.832 0.192 ;
     RECT  62.856 0.144 63.072 0.192 ;
     RECT  63.096 0.144 63.312 0.192 ;
     RECT  63.336 0.144 63.552 0.192 ;
     RECT  63.576 0.144 63.792 0.192 ;
     RECT  63.816 0.144 64.032 0.192 ;
     RECT  64.056 0.144 64.272 0.192 ;
     RECT  64.296 0.144 64.56 0.192 ;
     RECT  64.584 0.144 64.8 0.192 ;
     RECT  64.824 0.144 65.04 0.192 ;
     RECT  65.064 0.144 65.28 0.192 ;
     RECT  65.304 0.144 65.52 0.192 ;
     RECT  65.544 0.144 65.76 0.192 ;
     RECT  65.784 0.144 66 0.192 ;
     RECT  66.024 0.144 66.24 0.192 ;
     RECT  66.264 0.144 66.48 0.192 ;
     RECT  66.504 0.144 66.72 0.192 ;
     RECT  66.744 0.144 66.96 0.192 ;
     RECT  66.984 0.144 67.248 0.192 ;
     RECT  67.272 0.144 67.488 0.192 ;
     RECT  67.512 0.144 67.728 0.192 ;
     RECT  67.752 0.144 67.968 0.192 ;
     RECT  67.992 0.144 68.208 0.192 ;
     RECT  68.232 0.144 68.448 0.192 ;
     RECT  68.472 0.144 68.688 0.192 ;
     RECT  68.712 0.144 68.928 0.192 ;
     RECT  68.952 0.144 69.168 0.192 ;
     RECT  69.192 0.144 69.408 0.192 ;
     RECT  69.432 0.144 69.648 0.192 ;
     RECT  69.672 0.144 69.888 0.192 ;
     RECT  69.912 0.144 70.176 0.192 ;
     RECT  70.2 0.144 70.416 0.192 ;
     RECT  70.44 0.144 70.656 0.192 ;
     RECT  70.68 0.144 70.896 0.192 ;
     RECT  70.92 0.144 71.136 0.192 ;
     RECT  71.16 0.144 71.376 0.192 ;
     RECT  71.4 0.144 71.616 0.192 ;
     RECT  71.64 0.144 71.856 0.192 ;
     RECT  71.88 0.144 72.096 0.192 ;
     RECT  72.12 0.144 72.336 0.192 ;
     RECT  72.36 0.144 72.576 0.192 ;
     RECT  72.6 0.144 72.816 0.192 ;
     RECT  72.84 0.144 73.104 0.192 ;
     RECT  73.128 0.144 73.344 0.192 ;
     RECT  73.368 0.144 73.584 0.192 ;
     RECT  73.608 0.144 73.824 0.192 ;
     RECT  73.848 0.144 74.064 0.192 ;
     RECT  74.088 0.144 74.304 0.192 ;
     RECT  74.328 0.144 74.544 0.192 ;
     RECT  74.568 0.144 74.784 0.192 ;
     RECT  74.808 0.144 75.024 0.192 ;
     RECT  75.048 0.144 75.264 0.192 ;
     RECT  75.288 0.144 75.504 0.192 ;
     RECT  75.528 0.144 75.792 0.192 ;
     RECT  75.816 0.144 76.032 0.192 ;
     RECT  76.056 0.144 76.272 0.192 ;
     RECT  76.296 0.144 76.512 0.192 ;
     RECT  76.536 0.144 76.752 0.192 ;
     RECT  76.776 0.144 76.992 0.192 ;
     RECT  77.016 0.144 77.232 0.192 ;
     RECT  77.256 0.144 77.472 0.192 ;
     RECT  77.496 0.144 77.712 0.192 ;
     RECT  77.736 0.144 77.952 0.192 ;
     RECT  77.976 0.144 78.192 0.192 ;
     RECT  78.216 0.144 78.432 0.192 ;
     RECT  78.456 0.144 78.72 0.192 ;
     RECT  78.744 0.144 78.96 0.192 ;
     RECT  78.984 0.144 79.2 0.192 ;
     RECT  79.224 0.144 79.44 0.192 ;
     RECT  79.464 0.144 79.68 0.192 ;
     RECT  79.704 0.144 79.92 0.192 ;
     RECT  79.944 0.144 80.16 0.192 ;
     RECT  80.184 0.144 80.4 0.192 ;
     RECT  80.424 0.144 80.64 0.192 ;
     RECT  80.664 0.144 80.88 0.192 ;
     RECT  80.904 0.144 81.12 0.192 ;
     RECT  81.144 0.144 81.36 0.192 ;
     RECT  81.384 0.144 81.648 0.192 ;
     RECT  81.672 0.144 81.888 0.192 ;
     RECT  81.912 0.144 82.128 0.192 ;
     RECT  82.152 0.144 82.368 0.192 ;
     RECT  82.392 0.144 82.608 0.192 ;
     RECT  82.632 0.144 82.848 0.192 ;
     RECT  82.872 0.144 83.088 0.192 ;
     RECT  83.112 0.144 83.328 0.192 ;
     RECT  83.352 0.144 83.568 0.192 ;
     RECT  83.592 0.144 83.808 0.192 ;
     RECT  83.832 0.144 84.048 0.192 ;
     RECT  84.072 0.144 84.288 0.192 ;
     RECT  84.312 0.144 84.576 0.192 ;
     RECT  84.6 0.144 84.816 0.192 ;
     RECT  84.84 0.144 85.056 0.192 ;
     RECT  85.08 0.144 85.296 0.192 ;
     RECT  85.32 0.144 85.536 0.192 ;
     RECT  85.56 0.144 85.776 0.192 ;
     RECT  85.8 0.144 86.016 0.192 ;
     RECT  86.04 0.144 86.256 0.192 ;
     RECT  86.28 0.144 86.496 0.192 ;
     RECT  86.52 0.144 86.736 0.192 ;
     RECT  86.76 0.144 86.976 0.192 ;
     RECT  87 0.144 87.264 0.192 ;
     RECT  87.288 0.144 87.504 0.192 ;
     RECT  87.528 0.144 87.744 0.192 ;
     RECT  87.768 0.144 87.984 0.192 ;
     RECT  88.008 0.144 88.224 0.192 ;
     RECT  88.248 0.144 88.464 0.192 ;
     RECT  88.488 0.144 88.704 0.192 ;
     RECT  88.728 0.144 88.944 0.192 ;
     RECT  88.968 0.144 89.184 0.192 ;
     RECT  89.208 0.144 89.424 0.192 ;
     RECT  89.448 0.144 89.664 0.192 ;
     RECT  89.688 0.144 89.904 0.192 ;
     RECT  89.928 0.144 90.192 0.192 ;
     RECT  90.216 0.144 90.432 0.192 ;
     RECT  90.456 0.144 90.672 0.192 ;
     RECT  90.696 0.144 90.912 0.192 ;
     RECT  90.936 0.144 91.152 0.192 ;
     RECT  91.176 0.144 91.392 0.192 ;
     RECT  91.416 0.144 91.632 0.192 ;
     RECT  91.656 0.144 91.872 0.192 ;
     RECT  91.896 0.144 92.112 0.192 ;
     RECT  92.136 0.144 92.352 0.192 ;
     RECT  92.376 0.144 92.592 0.192 ;
     RECT  92.616 0.144 92.832 0.192 ;
     RECT  92.856 0.144 93.12 0.192 ;
     RECT  93.144 0.144 93.36 0.192 ;
     RECT  93.384 0.144 93.6 0.192 ;
     RECT  93.624 0.144 93.84 0.192 ;
     RECT  93.864 0.144 94.08 0.192 ;
     RECT  94.104 0.144 94.32 0.192 ;
     RECT  94.344 0.144 94.56 0.192 ;
     RECT  94.584 0.144 94.8 0.192 ;
     RECT  94.824 0.144 95.04 0.192 ;
     RECT  95.064 0.144 95.28 0.192 ;
     RECT  95.304 0.144 95.52 0.192 ;
     RECT  95.544 0.144 95.808 0.192 ;
     RECT  95.832 0.144 96.048 0.192 ;
     RECT  96.072 0.144 96.288 0.192 ;
     RECT  96.312 0.144 96.528 0.192 ;
     RECT  96.552 0.144 96.768 0.192 ;
     RECT  96.792 0.144 97.008 0.192 ;
     RECT  4.512 0.192 97.032 1.763 ;
     RECT  10.32 1.763 91.992 1.811 ;
     RECT  4.992 1.763 8.52 1.859 ;
     RECT  12.528 1.811 22.104 1.859 ;
     RECT  23.184 1.811 33.768 1.859 ;
     RECT  34.752 1.811 82.152 1.859 ;
     RECT  93.36 1.763 97.032 1.859 ;
     RECT  2.4 2.137 2.52 2.151 ;
     RECT  93.84 1.859 97.032 2.151 ;
     RECT  12.768 1.859 22.104 2.291 ;
     RECT  25.728 1.859 33.768 2.821 ;
     RECT  34.8 1.859 82.152 2.821 ;
     RECT  5.1 1.859 8.52 2.915 ;
     RECT  12.768 2.291 14.04 2.915 ;
     RECT  15.9 2.291 22.104 2.915 ;
     RECT  25.728 2.821 82.152 2.915 ;
     RECT  83.184 1.811 91.992 2.915 ;
     RECT  15.9 2.915 16.488 2.963 ;
     RECT  18.384 2.915 21.612 2.963 ;
     RECT  25.728 2.915 81.96 2.963 ;
     RECT  90.672 2.915 91.812 2.963 ;
     RECT  83.184 2.915 89.304 3.205 ;
     RECT  25.728 2.963 54.12 3.347 ;
     RECT  7.2 2.915 8.52 3.443 ;
     RECT  10.32 1.811 11.352 3.443 ;
     RECT  12.768 2.915 13.512 3.443 ;
     RECT  18.48 2.963 21.612 3.443 ;
     RECT  25.728 3.347 52.344 3.443 ;
     RECT  55.392 2.963 81.96 3.443 ;
     RECT  93.84 2.151 97.212 3.443 ;
     RECT  83.088 3.205 89.304 3.491 ;
     RECT  5.1 2.915 5.736 3.685 ;
     RECT  10.32 3.443 10.812 3.875 ;
     RECT  7.2 3.443 8.28 4.019 ;
     RECT  18.6 3.443 19.896 4.019 ;
     RECT  21.024 3.443 21.612 4.019 ;
     RECT  83.088 3.491 84.12 4.019 ;
     RECT  85.104 3.491 89.304 4.019 ;
     RECT  93.84 3.443 94.512 4.019 ;
     RECT  94.08 4.019 94.512 4.067 ;
     RECT  85.296 4.019 89.304 4.163 ;
     RECT  15.9 2.963 16.392 4.261 ;
     RECT  12.816 3.443 13.512 4.453 ;
     RECT  4.272 3.685 5.736 4.501 ;
     RECT  23.184 1.859 24.456 4.501 ;
     RECT  25.728 3.443 51.864 4.501 ;
     RECT  4.272 4.501 5.976 4.547 ;
     RECT  91.5 2.963 91.812 4.549 ;
     RECT  7.8 4.019 8.28 4.595 ;
     RECT  23.184 4.501 51.864 4.595 ;
     RECT  44.976 4.595 51.864 4.691 ;
     RECT  95.52 3.443 97.212 4.933 ;
     RECT  91.248 4.549 91.812 5.029 ;
     RECT  23.184 4.595 43.896 5.171 ;
     RECT  55.392 3.443 55.416 5.171 ;
     RECT  56.4 3.443 81.96 5.171 ;
     RECT  85.296 4.163 89.112 5.171 ;
     RECT  95.52 4.933 97.32 5.171 ;
     RECT  25.728 5.171 33.624 5.219 ;
     RECT  53.568 3.347 54.12 5.219 ;
     RECT  5.1 4.547 5.976 5.267 ;
     RECT  71.856 5.171 79.368 5.267 ;
     RECT  12.72 4.453 13.512 5.317 ;
     RECT  80.448 5.171 81.96 5.317 ;
     RECT  83.088 4.019 83.712 5.317 ;
     RECT  18.6 4.019 18.912 5.413 ;
     RECT  15.9 4.261 16.632 5.507 ;
     RECT  85.488 5.171 89.112 5.557 ;
     RECT  94.2 4.067 94.512 5.557 ;
     RECT  21.12 4.019 21.612 5.605 ;
     RECT  85.488 5.557 89.448 5.699 ;
     RECT  7.8 4.595 8.112 5.701 ;
     RECT  10.5 3.875 10.812 5.701 ;
     RECT  25.728 5.219 27.012 5.747 ;
     RECT  28.08 5.219 33.624 5.747 ;
     RECT  44.976 4.691 51.312 5.747 ;
     RECT  56.4 5.171 70.632 5.747 ;
     RECT  96.288 5.171 97.32 5.747 ;
     RECT  23.184 5.171 24.648 5.795 ;
     RECT  28.08 5.747 28.104 5.795 ;
     RECT  29.28 5.747 33.624 5.795 ;
     RECT  56.4 5.747 60.696 5.795 ;
     RECT  71.856 5.267 79.224 5.987 ;
     RECT  96.9 5.747 97.32 5.987 ;
     RECT  18.48 5.413 18.912 6.085 ;
     RECT  53.568 5.219 54.012 6.085 ;
     RECT  34.656 5.171 43.896 6.181 ;
     RECT  44.976 5.747 48.792 6.181 ;
     RECT  61.68 5.747 70.632 6.181 ;
     RECT  91.152 5.029 91.812 6.227 ;
     RECT  20.88 5.605 21.612 6.275 ;
     RECT  18.48 6.085 19.416 6.323 ;
     RECT  34.656 6.181 48.792 6.323 ;
     RECT  80.448 5.317 83.712 6.323 ;
     RECT  86.1 5.699 89.448 6.323 ;
     RECT  24 5.795 24.648 6.371 ;
     RECT  50.112 5.747 51.312 6.371 ;
     RECT  34.656 6.323 45.912 6.419 ;
     RECT  10.224 5.701 10.812 6.515 ;
     RECT  56.4 5.795 59.832 6.515 ;
     RECT  87.744 6.323 89.448 6.515 ;
     RECT  93.264 5.557 94.512 6.515 ;
     RECT  21.12 6.275 21.612 6.563 ;
     RECT  37.008 6.419 45.912 6.563 ;
     RECT  52.992 6.085 54.012 6.611 ;
     RECT  15.9 5.507 16.212 6.613 ;
     RECT  21.168 6.563 21.612 6.707 ;
     RECT  50.16 6.371 51.312 6.709 ;
     RECT  7.8 5.701 9.096 6.803 ;
     RECT  42.768 6.563 45.912 6.803 ;
     RECT  61.68 6.181 70.68 6.803 ;
     RECT  71.856 5.987 75.816 6.803 ;
     RECT  80.448 6.323 82.2 6.803 ;
     RECT  83.28 6.323 83.712 6.803 ;
     RECT  91.248 6.227 91.812 6.803 ;
     RECT  12.672 5.317 13.512 6.805 ;
     RECT  64.5 6.803 70.68 6.805 ;
     RECT  71.856 6.803 74.328 6.805 ;
     RECT  87.744 6.515 89.112 6.851 ;
     RECT  18.6 6.323 19.416 6.899 ;
     RECT  61.68 6.803 63.432 6.899 ;
     RECT  64.5 6.805 74.328 6.899 ;
     RECT  76.848 5.987 79.224 6.899 ;
     RECT  46.944 6.323 48.612 6.947 ;
     RECT  64.5 6.899 66.168 6.947 ;
     RECT  67.2 6.899 74.328 6.947 ;
     RECT  63.12 6.899 63.144 6.995 ;
     RECT  87.744 6.851 87.768 7.235 ;
     RECT  29.4 5.795 33.624 7.237 ;
     RECT  34.656 6.419 35.88 7.237 ;
     RECT  61.68 6.899 62.112 7.237 ;
     RECT  14.976 6.613 16.212 7.379 ;
     RECT  29.4 7.237 35.88 7.475 ;
     RECT  37.008 6.563 41.688 7.475 ;
     RECT  47.664 6.947 48.612 7.475 ;
     RECT  50.16 6.709 51.72 7.475 ;
     RECT  66.048 6.947 66.168 7.475 ;
     RECT  67.2 6.947 73.512 7.475 ;
     RECT  66.048 7.475 66.12 7.523 ;
     RECT  12.528 6.805 13.512 7.667 ;
     RECT  75.3 6.803 75.816 7.667 ;
     RECT  64.5 6.947 65.016 7.763 ;
     RECT  29.4 7.475 33.048 8.003 ;
     RECT  37.5 7.475 41.688 8.003 ;
     RECT  42.768 6.803 44.28 8.003 ;
     RECT  56.4 6.515 59.688 8.003 ;
     RECT  64.5 7.763 64.968 8.003 ;
     RECT  66.096 7.523 66.12 8.003 ;
     RECT  69.312 7.475 70.212 8.003 ;
     RECT  76.848 6.899 79.128 8.003 ;
     RECT  80.7 6.803 81.432 8.003 ;
     RECT  60.768 7.237 62.112 8.195 ;
     RECT  75.3 7.667 75.768 8.291 ;
     RECT  31.536 8.003 33.048 8.579 ;
     RECT  34.176 7.475 35.112 8.579 ;
     RECT  37.5 8.003 37.992 8.579 ;
     RECT  39.072 8.003 40.512 8.579 ;
     RECT  51 7.475 51.72 8.579 ;
     RECT  69.408 8.003 70.212 8.579 ;
     RECT  71.472 7.475 73.464 8.579 ;
     RECT  76.992 8.003 78.648 8.579 ;
     RECT  80.7 8.003 81.384 8.579 ;
     RECT  75.3 8.291 75.72 8.915 ;
     RECT  42.768 8.003 43.752 9.155 ;
     RECT  60.768 8.195 60.792 9.155 ;
     RECT  78 8.579 78.648 9.155 ;
     RECT  29.4 8.003 30.456 10.307 ;
     RECT  41.664 8.003 41.688 10.883 ;
     RECT  45.504 6.803 45.912 10.883 ;
     RECT  47.712 7.475 48.612 10.883 ;
     RECT  58.272 8.003 59.412 10.883 ;
     RECT  42.768 9.155 43.212 11.459 ;
     RECT  72.6 8.579 72.912 18.181 ;
     RECT  0.24 7.093 0.264 18.419 ;
     RECT  75.3 8.915 75.612 18.469 ;
     RECT  10.5 6.515 10.812 18.661 ;
     RECT  10.5 18.661 11.544 18.803 ;
     RECT  75.3 18.469 75.72 18.803 ;
     RECT  32.1 8.579 32.412 19.333 ;
     RECT  48.3 10.883 48.612 27.637 ;
     RECT  18.6 6.899 18.912 27.685 ;
     RECT  29.4 10.307 29.712 27.685 ;
     RECT  34.8 8.579 35.112 27.685 ;
     RECT  86.1 6.323 86.412 27.685 ;
     RECT  94.2 6.515 94.512 27.685 ;
     RECT  21.3 6.707 21.612 27.781 ;
     RECT  64.5 8.003 64.812 27.781 ;
     RECT  67.2 7.475 67.512 27.781 ;
     RECT  72.48 18.181 72.912 27.781 ;
     RECT  18.48 27.685 18.912 27.829 ;
     RECT  51 8.579 51.312 27.829 ;
     RECT  5.1 5.267 5.412 27.877 ;
     RECT  7.8 6.803 8.112 27.877 ;
     RECT  13.2 7.667 13.512 27.877 ;
     RECT  15.9 7.379 16.212 27.877 ;
     RECT  18.144 27.829 18.912 27.877 ;
     RECT  22.8 27.301 22.824 27.877 ;
     RECT  24 6.371 24.312 27.877 ;
     RECT  26.7 5.747 27.012 27.877 ;
     RECT  29.232 27.685 29.712 27.877 ;
     RECT  31.968 19.333 32.412 27.877 ;
     RECT  34.704 27.685 35.112 27.877 ;
     RECT  37.5 8.579 37.812 27.877 ;
     RECT  40.2 8.579 40.512 27.877 ;
     RECT  41.616 27.829 41.64 27.877 ;
     RECT  42.9 11.459 43.212 27.877 ;
     RECT  51 27.829 51.864 27.877 ;
     RECT  59.1 10.883 59.412 27.877 ;
     RECT  67.2 27.781 68.472 27.877 ;
     RECT  69.9 8.579 70.212 27.877 ;
     RECT  71.856 27.781 72.912 27.877 ;
     RECT  83.4 6.803 83.712 27.877 ;
     RECT  85.776 27.685 86.412 27.877 ;
     RECT  88.8 6.851 89.112 27.877 ;
     RECT  91.5 6.803 91.812 27.877 ;
     RECT  94.08 27.685 94.512 27.877 ;
     RECT  96.9 5.987 97.212 27.877 ;
     RECT  10.5 18.803 10.812 28.165 ;
     RECT  10.368 28.165 10.812 28.261 ;
     RECT  13.056 27.877 13.8 28.261 ;
     RECT  39.648 27.877 43.212 28.261 ;
     RECT  80.7 8.579 81.012 28.261 ;
     RECT  7.68 27.877 8.112 28.309 ;
     RECT  10.32 28.261 10.812 28.309 ;
     RECT  14.976 27.877 16.212 28.309 ;
     RECT  17.904 27.877 18.912 28.309 ;
     RECT  20.352 27.781 21.612 28.309 ;
     RECT  22.8 27.877 24.408 28.309 ;
     RECT  25.968 27.877 27.012 28.309 ;
     RECT  34.032 27.877 35.112 28.309 ;
     RECT  38.928 28.261 43.212 28.309 ;
     RECT  56.4 8.003 56.712 28.309 ;
     RECT  57.696 27.877 57.72 28.309 ;
     RECT  58.944 27.877 59.412 28.309 ;
     RECT  64.5 27.781 64.92 28.309 ;
     RECT  66.48 27.877 68.472 28.309 ;
     RECT  82.848 27.877 83.712 28.309 ;
     RECT  85.536 27.877 86.52 28.309 ;
     RECT  90.672 27.877 91.812 28.309 ;
     RECT  45.6 10.883 45.912 28.357 ;
     RECT  46.944 28.309 46.968 28.357 ;
     RECT  53.7 6.611 54.012 28.357 ;
     RECT  55.488 28.309 56.712 28.357 ;
     RECT  57.696 28.309 59.688 28.357 ;
     RECT  64.5 28.309 68.472 28.357 ;
     RECT  78 9.155 78.312 28.357 ;
     RECT  6.432 27.877 6.456 28.405 ;
     RECT  7.68 28.309 11.352 28.405 ;
     RECT  12.768 28.261 13.8 28.405 ;
     RECT  14.976 28.309 16.488 28.405 ;
     RECT  22.8 28.309 27.72 28.405 ;
     RECT  29.136 27.877 29.712 28.405 ;
     RECT  31.104 27.877 32.412 28.405 ;
     RECT  34.032 28.309 35.256 28.405 ;
     RECT  36.48 27.877 37.812 28.405 ;
     RECT  38.928 28.309 43.56 28.405 ;
     RECT  45.6 28.357 46.968 28.405 ;
     RECT  48.192 27.637 48.612 28.405 ;
     RECT  50.4 27.877 51.864 28.405 ;
     RECT  53.7 28.357 59.688 28.405 ;
     RECT  61.8 8.195 62.112 28.405 ;
     RECT  63.792 28.357 68.472 28.405 ;
     RECT  69.9 27.877 73.128 28.405 ;
     RECT  75.3 18.803 75.612 28.405 ;
     RECT  77.232 28.357 78.312 28.405 ;
     RECT  96.768 27.877 97.212 28.405 ;
     RECT  4.752 27.877 5.412 28.453 ;
     RECT  6.432 28.405 11.352 28.453 ;
     RECT  12.528 28.405 16.728 28.453 ;
     RECT  17.904 28.309 21.612 28.453 ;
     RECT  22.8 28.405 29.712 28.453 ;
     RECT  31.104 28.405 35.256 28.453 ;
     RECT  36.24 28.405 44.28 28.453 ;
     RECT  45.264 28.405 48.612 28.453 ;
     RECT  50.4 28.405 60.648 28.453 ;
     RECT  61.8 28.405 68.712 28.453 ;
     RECT  69.792 28.405 75.612 28.453 ;
     RECT  76.992 28.405 78.312 28.453 ;
     RECT  79.44 27.877 79.464 28.453 ;
     RECT  80.544 28.261 81.012 28.453 ;
     RECT  82.848 28.309 86.52 28.453 ;
     RECT  88.704 27.877 89.112 28.453 ;
     RECT  45.264 28.453 48.936 28.837 ;
     RECT  93.36 27.877 94.512 28.837 ;
     RECT  45.264 28.837 49.176 29.029 ;
     RECT  50.4 28.453 86.52 29.029 ;
     RECT  90.192 28.309 91.812 29.029 ;
     RECT  22.8 28.453 44.28 31.189 ;
     RECT  45.264 29.029 86.52 31.189 ;
     RECT  4.512 28.453 21.612 33.013 ;
     RECT  22.8 31.189 86.52 33.013 ;
     RECT  87.984 28.453 89.112 33.013 ;
     RECT  90.192 29.029 92.376 33.013 ;
     RECT  2.4 2.151 2.712 34.569 ;
     RECT  96.528 28.405 97.212 34.569 ;
     RECT  2.4 34.569 2.52 34.583 ;
     RECT  4.512 33.013 86.52 34.583 ;
     RECT  87.984 33.013 92.376 34.583 ;
     RECT  96.528 34.569 97.02 34.583 ;
     RECT  93.36 28.837 95.064 34.645 ;
     RECT  62.352 34.583 86.52 34.739 ;
     RECT  4.512 34.583 31.848 35.893 ;
     RECT  33.072 34.583 61.368 35.893 ;
     RECT  62.352 34.739 86.28 35.893 ;
     RECT  87.984 34.583 91.176 35.893 ;
     RECT  92.352 34.583 92.376 35.893 ;
     RECT  93.36 34.645 95.544 35.893 ;
     RECT  96.528 34.583 96.792 35.893 ;
     RECT  4.512 35.893 97.032 36.528 ;
     RECT  4.536 36.528 4.752 36.56 ;
     RECT  4.776 36.528 4.992 36.56 ;
     RECT  5.016 36.528 5.232 36.56 ;
     RECT  5.256 36.528 5.472 36.56 ;
     RECT  5.496 36.528 5.712 36.56 ;
     RECT  5.736 36.528 5.952 36.56 ;
     RECT  5.976 36.528 6.192 36.56 ;
     RECT  6.216 36.528 6.432 36.56 ;
     RECT  6.456 36.528 6.672 36.56 ;
     RECT  6.696 36.528 6.912 36.56 ;
     RECT  6.936 36.528 7.2 36.56 ;
     RECT  7.224 36.528 7.44 36.56 ;
     RECT  7.464 36.528 7.68 36.56 ;
     RECT  7.704 36.528 7.92 36.56 ;
     RECT  7.944 36.528 8.16 36.56 ;
     RECT  8.184 36.528 8.4 36.56 ;
     RECT  8.424 36.528 8.64 36.56 ;
     RECT  8.664 36.528 8.88 36.56 ;
     RECT  8.904 36.528 9.12 36.56 ;
     RECT  9.144 36.528 9.36 36.56 ;
     RECT  9.384 36.528 9.6 36.56 ;
     RECT  9.624 36.528 9.84 36.56 ;
     RECT  9.864 36.528 10.128 36.56 ;
     RECT  10.152 36.528 10.368 36.56 ;
     RECT  10.392 36.528 10.608 36.56 ;
     RECT  10.632 36.528 10.848 36.56 ;
     RECT  10.872 36.528 11.088 36.56 ;
     RECT  11.112 36.528 11.328 36.56 ;
     RECT  11.352 36.528 11.568 36.56 ;
     RECT  11.592 36.528 11.808 36.56 ;
     RECT  11.832 36.528 12.048 36.56 ;
     RECT  12.072 36.528 12.288 36.56 ;
     RECT  12.312 36.528 12.528 36.56 ;
     RECT  12.552 36.528 12.768 36.56 ;
     RECT  12.792 36.528 13.056 36.56 ;
     RECT  13.08 36.528 13.296 36.56 ;
     RECT  13.32 36.528 13.536 36.56 ;
     RECT  13.56 36.528 13.776 36.56 ;
     RECT  13.8 36.528 14.016 36.56 ;
     RECT  14.04 36.528 14.256 36.56 ;
     RECT  14.28 36.528 14.496 36.56 ;
     RECT  14.52 36.528 14.736 36.56 ;
     RECT  14.76 36.528 14.976 36.56 ;
     RECT  15 36.528 15.216 36.56 ;
     RECT  15.24 36.528 15.456 36.56 ;
     RECT  15.48 36.528 15.696 36.56 ;
     RECT  15.72 36.528 15.984 36.56 ;
     RECT  16.008 36.528 16.224 36.56 ;
     RECT  16.248 36.528 16.464 36.56 ;
     RECT  16.488 36.528 16.704 36.56 ;
     RECT  16.728 36.528 16.944 36.56 ;
     RECT  16.968 36.528 17.184 36.56 ;
     RECT  17.208 36.528 17.424 36.56 ;
     RECT  17.448 36.528 17.664 36.56 ;
     RECT  17.688 36.528 17.904 36.56 ;
     RECT  17.928 36.528 18.144 36.56 ;
     RECT  18.168 36.528 18.384 36.56 ;
     RECT  18.408 36.528 18.672 36.56 ;
     RECT  18.696 36.528 18.912 36.56 ;
     RECT  18.936 36.528 19.152 36.56 ;
     RECT  19.176 36.528 19.392 36.56 ;
     RECT  19.416 36.528 19.632 36.56 ;
     RECT  19.656 36.528 19.872 36.56 ;
     RECT  19.896 36.528 20.112 36.56 ;
     RECT  20.136 36.528 20.352 36.56 ;
     RECT  20.376 36.528 20.592 36.56 ;
     RECT  20.616 36.528 20.832 36.56 ;
     RECT  20.856 36.528 21.072 36.56 ;
     RECT  21.096 36.528 21.312 36.56 ;
     RECT  21.336 36.528 21.6 36.56 ;
     RECT  21.624 36.528 21.84 36.56 ;
     RECT  21.864 36.528 22.08 36.56 ;
     RECT  22.104 36.528 22.32 36.56 ;
     RECT  22.344 36.528 22.56 36.56 ;
     RECT  22.584 36.528 22.8 36.56 ;
     RECT  22.824 36.528 23.04 36.56 ;
     RECT  23.064 36.528 23.28 36.56 ;
     RECT  23.304 36.528 23.52 36.56 ;
     RECT  23.544 36.528 23.76 36.56 ;
     RECT  23.784 36.528 24 36.56 ;
     RECT  24.024 36.528 24.24 36.56 ;
     RECT  24.264 36.528 24.528 36.56 ;
     RECT  24.552 36.528 24.768 36.56 ;
     RECT  24.792 36.528 25.008 36.56 ;
     RECT  25.032 36.528 25.248 36.56 ;
     RECT  25.272 36.528 25.488 36.56 ;
     RECT  25.512 36.528 25.728 36.56 ;
     RECT  25.752 36.528 25.968 36.56 ;
     RECT  25.992 36.528 26.208 36.56 ;
     RECT  26.232 36.528 26.448 36.56 ;
     RECT  26.472 36.528 26.688 36.56 ;
     RECT  26.712 36.528 26.928 36.56 ;
     RECT  26.952 36.528 27.216 36.56 ;
     RECT  27.24 36.528 27.456 36.56 ;
     RECT  27.48 36.528 27.696 36.56 ;
     RECT  27.72 36.528 27.936 36.56 ;
     RECT  27.96 36.528 28.176 36.56 ;
     RECT  28.2 36.528 28.416 36.56 ;
     RECT  28.44 36.528 28.656 36.56 ;
     RECT  28.68 36.528 28.896 36.56 ;
     RECT  28.92 36.528 29.136 36.56 ;
     RECT  29.16 36.528 29.376 36.56 ;
     RECT  29.4 36.528 29.616 36.56 ;
     RECT  29.64 36.528 29.856 36.56 ;
     RECT  29.88 36.528 30.144 36.56 ;
     RECT  30.168 36.528 30.384 36.56 ;
     RECT  30.408 36.528 30.624 36.56 ;
     RECT  30.648 36.528 30.864 36.56 ;
     RECT  30.888 36.528 31.104 36.56 ;
     RECT  31.128 36.528 31.344 36.56 ;
     RECT  31.368 36.528 31.584 36.56 ;
     RECT  31.608 36.528 31.824 36.56 ;
     RECT  31.848 36.528 32.064 36.56 ;
     RECT  32.088 36.528 32.304 36.56 ;
     RECT  32.328 36.528 32.544 36.56 ;
     RECT  32.568 36.528 32.784 36.56 ;
     RECT  32.808 36.528 33.072 36.56 ;
     RECT  33.096 36.528 33.312 36.56 ;
     RECT  33.336 36.528 33.552 36.56 ;
     RECT  33.576 36.528 33.792 36.56 ;
     RECT  33.816 36.528 34.032 36.56 ;
     RECT  34.056 36.528 34.272 36.56 ;
     RECT  34.296 36.528 34.512 36.56 ;
     RECT  34.536 36.528 34.752 36.56 ;
     RECT  34.776 36.528 34.992 36.56 ;
     RECT  35.016 36.528 35.232 36.56 ;
     RECT  35.256 36.528 35.472 36.56 ;
     RECT  35.496 36.528 35.712 36.56 ;
     RECT  35.736 36.528 36 36.56 ;
     RECT  36.024 36.528 36.24 36.56 ;
     RECT  36.264 36.528 36.48 36.56 ;
     RECT  36.504 36.528 36.72 36.56 ;
     RECT  36.744 36.528 36.96 36.56 ;
     RECT  36.984 36.528 37.2 36.56 ;
     RECT  37.224 36.528 37.44 36.56 ;
     RECT  37.464 36.528 37.68 36.56 ;
     RECT  37.704 36.528 37.92 36.56 ;
     RECT  37.944 36.528 38.16 36.56 ;
     RECT  38.184 36.528 38.4 36.56 ;
     RECT  38.424 36.528 38.688 36.56 ;
     RECT  38.712 36.528 38.928 36.56 ;
     RECT  38.952 36.528 39.168 36.56 ;
     RECT  39.192 36.528 39.408 36.56 ;
     RECT  39.432 36.528 39.648 36.56 ;
     RECT  39.672 36.528 39.888 36.56 ;
     RECT  39.912 36.528 40.128 36.56 ;
     RECT  40.152 36.528 40.368 36.56 ;
     RECT  40.392 36.528 40.608 36.56 ;
     RECT  40.632 36.528 40.848 36.56 ;
     RECT  40.872 36.528 41.088 36.56 ;
     RECT  41.112 36.528 41.328 36.56 ;
     RECT  41.352 36.528 41.616 36.56 ;
     RECT  41.64 36.528 41.856 36.56 ;
     RECT  41.88 36.528 42.096 36.56 ;
     RECT  42.12 36.528 42.336 36.56 ;
     RECT  42.36 36.528 42.576 36.56 ;
     RECT  42.6 36.528 42.816 36.56 ;
     RECT  42.84 36.528 43.056 36.56 ;
     RECT  43.08 36.528 43.296 36.56 ;
     RECT  43.32 36.528 43.536 36.56 ;
     RECT  43.56 36.528 43.776 36.56 ;
     RECT  43.8 36.528 44.016 36.56 ;
     RECT  44.04 36.528 44.256 36.56 ;
     RECT  44.28 36.528 44.544 36.56 ;
     RECT  44.568 36.528 44.784 36.56 ;
     RECT  44.808 36.528 45.024 36.56 ;
     RECT  45.048 36.528 45.264 36.56 ;
     RECT  45.288 36.528 45.504 36.56 ;
     RECT  45.528 36.528 45.744 36.56 ;
     RECT  45.768 36.528 45.984 36.56 ;
     RECT  46.008 36.528 46.224 36.56 ;
     RECT  46.248 36.528 46.464 36.56 ;
     RECT  46.488 36.528 46.704 36.56 ;
     RECT  46.728 36.528 46.944 36.56 ;
     RECT  46.968 36.528 47.232 36.56 ;
     RECT  47.256 36.528 47.472 36.56 ;
     RECT  47.496 36.528 47.712 36.56 ;
     RECT  47.736 36.528 47.952 36.56 ;
     RECT  47.976 36.528 48.192 36.56 ;
     RECT  48.216 36.528 48.432 36.56 ;
     RECT  48.456 36.528 48.672 36.56 ;
     RECT  48.696 36.528 48.912 36.56 ;
     RECT  48.936 36.528 49.152 36.56 ;
     RECT  49.176 36.528 49.392 36.56 ;
     RECT  49.416 36.528 49.632 36.56 ;
     RECT  49.656 36.528 49.872 36.56 ;
     RECT  49.896 36.528 50.16 36.56 ;
     RECT  50.184 36.528 50.4 36.56 ;
     RECT  50.424 36.528 50.64 36.56 ;
     RECT  50.664 36.528 50.88 36.56 ;
     RECT  50.904 36.528 51.12 36.56 ;
     RECT  51.144 36.528 51.36 36.56 ;
     RECT  51.384 36.528 51.6 36.56 ;
     RECT  51.624 36.528 51.84 36.56 ;
     RECT  51.864 36.528 52.08 36.56 ;
     RECT  52.104 36.528 52.32 36.56 ;
     RECT  52.344 36.528 52.56 36.56 ;
     RECT  52.584 36.528 52.8 36.56 ;
     RECT  52.824 36.528 53.088 36.56 ;
     RECT  53.112 36.528 53.328 36.56 ;
     RECT  53.352 36.528 53.568 36.56 ;
     RECT  53.592 36.528 53.808 36.56 ;
     RECT  53.832 36.528 54.048 36.56 ;
     RECT  54.072 36.528 54.288 36.56 ;
     RECT  54.312 36.528 54.528 36.56 ;
     RECT  54.552 36.528 54.768 36.56 ;
     RECT  54.792 36.528 55.008 36.56 ;
     RECT  55.032 36.528 55.248 36.56 ;
     RECT  55.272 36.528 55.488 36.56 ;
     RECT  55.512 36.528 55.776 36.56 ;
     RECT  55.8 36.528 56.016 36.56 ;
     RECT  56.04 36.528 56.256 36.56 ;
     RECT  56.28 36.528 56.496 36.56 ;
     RECT  56.52 36.528 56.736 36.56 ;
     RECT  56.76 36.528 56.976 36.56 ;
     RECT  57 36.528 57.216 36.56 ;
     RECT  57.24 36.528 57.456 36.56 ;
     RECT  57.48 36.528 57.696 36.56 ;
     RECT  57.72 36.528 57.936 36.56 ;
     RECT  57.96 36.528 58.176 36.56 ;
     RECT  58.2 36.528 58.416 36.56 ;
     RECT  58.44 36.528 58.704 36.56 ;
     RECT  58.728 36.528 58.944 36.56 ;
     RECT  58.968 36.528 59.184 36.56 ;
     RECT  59.208 36.528 59.424 36.56 ;
     RECT  59.448 36.528 59.664 36.56 ;
     RECT  59.688 36.528 59.904 36.56 ;
     RECT  59.928 36.528 60.144 36.56 ;
     RECT  60.168 36.528 60.384 36.56 ;
     RECT  60.408 36.528 60.624 36.56 ;
     RECT  60.648 36.528 60.864 36.56 ;
     RECT  60.888 36.528 61.104 36.56 ;
     RECT  61.128 36.528 61.344 36.56 ;
     RECT  61.368 36.528 61.632 36.56 ;
     RECT  61.656 36.528 61.872 36.56 ;
     RECT  61.896 36.528 62.112 36.56 ;
     RECT  62.136 36.528 62.352 36.56 ;
     RECT  62.376 36.528 62.592 36.56 ;
     RECT  62.616 36.528 62.832 36.56 ;
     RECT  62.856 36.528 63.072 36.56 ;
     RECT  63.096 36.528 63.312 36.56 ;
     RECT  63.336 36.528 63.552 36.56 ;
     RECT  63.576 36.528 63.792 36.56 ;
     RECT  63.816 36.528 64.032 36.56 ;
     RECT  64.056 36.528 64.272 36.56 ;
     RECT  64.296 36.528 64.56 36.56 ;
     RECT  64.584 36.528 64.8 36.56 ;
     RECT  64.824 36.528 65.04 36.56 ;
     RECT  65.064 36.528 65.28 36.56 ;
     RECT  65.304 36.528 65.52 36.56 ;
     RECT  65.544 36.528 65.76 36.56 ;
     RECT  65.784 36.528 66 36.56 ;
     RECT  66.024 36.528 66.24 36.56 ;
     RECT  66.264 36.528 66.48 36.56 ;
     RECT  66.504 36.528 66.72 36.56 ;
     RECT  66.744 36.528 66.96 36.56 ;
     RECT  66.984 36.528 67.248 36.56 ;
     RECT  67.272 36.528 67.488 36.56 ;
     RECT  67.512 36.528 67.728 36.56 ;
     RECT  67.752 36.528 67.968 36.56 ;
     RECT  67.992 36.528 68.208 36.56 ;
     RECT  68.232 36.528 68.448 36.56 ;
     RECT  68.472 36.528 68.688 36.56 ;
     RECT  68.712 36.528 68.928 36.56 ;
     RECT  68.952 36.528 69.168 36.56 ;
     RECT  69.192 36.528 69.408 36.56 ;
     RECT  69.432 36.528 69.648 36.56 ;
     RECT  69.672 36.528 69.888 36.56 ;
     RECT  69.912 36.528 70.176 36.56 ;
     RECT  70.2 36.528 70.416 36.56 ;
     RECT  70.44 36.528 70.656 36.56 ;
     RECT  70.68 36.528 70.896 36.56 ;
     RECT  70.92 36.528 71.136 36.56 ;
     RECT  71.16 36.528 71.376 36.56 ;
     RECT  71.4 36.528 71.616 36.56 ;
     RECT  71.64 36.528 71.856 36.56 ;
     RECT  71.88 36.528 72.096 36.56 ;
     RECT  72.12 36.528 72.336 36.56 ;
     RECT  72.36 36.528 72.576 36.56 ;
     RECT  72.6 36.528 72.816 36.56 ;
     RECT  72.84 36.528 73.104 36.56 ;
     RECT  73.128 36.528 73.344 36.56 ;
     RECT  73.368 36.528 73.584 36.56 ;
     RECT  73.608 36.528 73.824 36.56 ;
     RECT  73.848 36.528 74.064 36.56 ;
     RECT  74.088 36.528 74.304 36.56 ;
     RECT  74.328 36.528 74.544 36.56 ;
     RECT  74.568 36.528 74.784 36.56 ;
     RECT  74.808 36.528 75.024 36.56 ;
     RECT  75.048 36.528 75.264 36.56 ;
     RECT  75.288 36.528 75.504 36.56 ;
     RECT  75.528 36.528 75.792 36.56 ;
     RECT  75.816 36.528 76.032 36.56 ;
     RECT  76.056 36.528 76.272 36.56 ;
     RECT  76.296 36.528 76.512 36.56 ;
     RECT  76.536 36.528 76.752 36.56 ;
     RECT  76.776 36.528 76.992 36.56 ;
     RECT  77.016 36.528 77.232 36.56 ;
     RECT  77.256 36.528 77.472 36.56 ;
     RECT  77.496 36.528 77.712 36.56 ;
     RECT  77.736 36.528 77.952 36.56 ;
     RECT  77.976 36.528 78.192 36.56 ;
     RECT  78.216 36.528 78.432 36.56 ;
     RECT  78.456 36.528 78.72 36.56 ;
     RECT  78.744 36.528 78.96 36.56 ;
     RECT  78.984 36.528 79.2 36.56 ;
     RECT  79.224 36.528 79.44 36.56 ;
     RECT  79.464 36.528 79.68 36.56 ;
     RECT  79.704 36.528 79.92 36.56 ;
     RECT  79.944 36.528 80.16 36.56 ;
     RECT  80.184 36.528 80.4 36.56 ;
     RECT  80.424 36.528 80.64 36.56 ;
     RECT  80.664 36.528 80.88 36.56 ;
     RECT  80.904 36.528 81.12 36.56 ;
     RECT  81.144 36.528 81.36 36.56 ;
     RECT  81.384 36.528 81.648 36.56 ;
     RECT  81.672 36.528 81.888 36.56 ;
     RECT  81.912 36.528 82.128 36.56 ;
     RECT  82.152 36.528 82.368 36.56 ;
     RECT  82.392 36.528 82.608 36.56 ;
     RECT  82.632 36.528 82.848 36.56 ;
     RECT  82.872 36.528 83.088 36.56 ;
     RECT  83.112 36.528 83.328 36.56 ;
     RECT  83.352 36.528 83.568 36.56 ;
     RECT  83.592 36.528 83.808 36.56 ;
     RECT  83.832 36.528 84.048 36.56 ;
     RECT  84.072 36.528 84.288 36.56 ;
     RECT  84.312 36.528 84.576 36.56 ;
     RECT  84.6 36.528 84.816 36.56 ;
     RECT  84.84 36.528 85.056 36.56 ;
     RECT  85.08 36.528 85.296 36.56 ;
     RECT  85.32 36.528 85.536 36.56 ;
     RECT  85.56 36.528 85.776 36.56 ;
     RECT  85.8 36.528 86.016 36.56 ;
     RECT  86.04 36.528 86.256 36.56 ;
     RECT  86.28 36.528 86.496 36.56 ;
     RECT  86.52 36.528 86.736 36.56 ;
     RECT  86.76 36.528 86.976 36.56 ;
     RECT  87 36.528 87.264 36.56 ;
     RECT  87.288 36.528 87.504 36.56 ;
     RECT  87.528 36.528 87.744 36.56 ;
     RECT  87.768 36.528 87.984 36.56 ;
     RECT  88.008 36.528 88.224 36.56 ;
     RECT  88.248 36.528 88.464 36.56 ;
     RECT  88.488 36.528 88.704 36.56 ;
     RECT  88.728 36.528 88.944 36.56 ;
     RECT  88.968 36.528 89.184 36.56 ;
     RECT  89.208 36.528 89.424 36.56 ;
     RECT  89.448 36.528 89.664 36.56 ;
     RECT  89.688 36.528 89.904 36.56 ;
     RECT  89.928 36.528 90.192 36.56 ;
     RECT  90.216 36.528 90.432 36.56 ;
     RECT  90.456 36.528 90.672 36.56 ;
     RECT  90.696 36.528 90.912 36.56 ;
     RECT  90.936 36.528 91.152 36.56 ;
     RECT  91.176 36.528 91.392 36.56 ;
     RECT  91.416 36.528 91.632 36.56 ;
     RECT  91.656 36.528 91.872 36.56 ;
     RECT  91.896 36.528 92.112 36.56 ;
     RECT  92.136 36.528 92.352 36.56 ;
     RECT  92.376 36.528 92.592 36.56 ;
     RECT  92.616 36.528 92.832 36.56 ;
     RECT  92.856 36.528 93.12 36.56 ;
     RECT  93.144 36.528 93.36 36.56 ;
     RECT  93.384 36.528 93.6 36.56 ;
     RECT  93.624 36.528 93.84 36.56 ;
     RECT  93.864 36.528 94.08 36.56 ;
     RECT  94.104 36.528 94.32 36.56 ;
     RECT  94.344 36.528 94.56 36.56 ;
     RECT  94.584 36.528 94.8 36.56 ;
     RECT  94.824 36.528 95.04 36.56 ;
     RECT  95.064 36.528 95.28 36.56 ;
     RECT  95.304 36.528 95.52 36.56 ;
     RECT  95.544 36.528 95.808 36.56 ;
     RECT  95.832 36.528 96.048 36.56 ;
     RECT  96.072 36.528 96.288 36.56 ;
     RECT  96.312 36.528 96.528 36.56 ;
     RECT  96.552 36.528 96.768 36.56 ;
     RECT  96.792 36.528 97.008 36.56 ;
     RECT  59.544 0.133 59.616 0.144 ;
     RECT  59.736 0.133 59.856 0.144 ;
     RECT  59.976 0.133 60.096 0.144 ;
     RECT  60.216 0.133 60.336 0.144 ;
     RECT  60.456 0.133 60.576 0.144 ;
     RECT  60.696 0.133 60.768 0.144 ;
     RECT  91.992 1.763 93.36 1.859 ;
     RECT  11.352 1.811 12.528 1.859 ;
     RECT  22.104 1.811 23.184 2.915 ;
     RECT  33.768 1.811 34.752 1.859 ;
     RECT  82.152 1.811 83.184 2.915 ;
     RECT  11.352 1.859 12.768 3.443 ;
     RECT  24.456 1.859 25.728 4.501 ;
     RECT  33.768 1.859 34.8 2.821 ;
     RECT  5.736 2.915 7.2 4.019 ;
     RECT  16.488 2.915 16.632 2.963 ;
     RECT  81.96 2.915 83.184 3.205 ;
     RECT  89.304 2.915 90.672 2.963 ;
     RECT  16.392 2.963 16.632 4.261 ;
     RECT  54.12 2.963 55.392 5.171 ;
     RECT  81.96 3.205 83.088 5.317 ;
     RECT  52.344 3.347 53.568 3.443 ;
     RECT  12.72 3.443 12.816 4.453 ;
     RECT  19.896 3.443 21.024 4.019 ;
     RECT  55.416 3.443 56.4 5.171 ;
     RECT  94.512 3.443 95.52 5.171 ;
     RECT  84.12 3.491 85.104 4.019 ;
     RECT  5.736 4.019 5.976 4.501 ;
     RECT  94.08 4.067 94.2 5.557 ;
     RECT  89.112 4.163 89.304 5.557 ;
     RECT  8.112 4.595 8.28 5.701 ;
     RECT  43.896 4.595 44.976 6.181 ;
     RECT  24.648 5.171 25.728 5.747 ;
     RECT  33.624 5.171 34.656 7.237 ;
     RECT  70.632 5.171 71.856 6.181 ;
     RECT  79.368 5.171 80.448 5.267 ;
     RECT  27.012 5.219 28.08 5.795 ;
     RECT  79.224 5.267 80.448 6.803 ;
     RECT  91.812 5.557 93.264 6.515 ;
     RECT  9.096 5.701 10.224 6.515 ;
     RECT  28.104 5.747 29.28 5.795 ;
     RECT  48.792 5.747 50.112 6.323 ;
     RECT  60.696 5.747 61.68 5.795 ;
     RECT  59.832 5.795 61.68 6.515 ;
     RECT  75.816 5.987 76.848 7.667 ;
     RECT  19.416 6.085 20.88 6.275 ;
     RECT  70.68 6.181 71.856 6.805 ;
     RECT  45.912 6.323 46.944 6.947 ;
     RECT  48.612 6.323 50.112 6.371 ;
     RECT  82.2 6.323 83.28 6.803 ;
     RECT  86.412 6.323 87.744 7.235 ;
     RECT  35.88 6.419 37.008 7.475 ;
     RECT  9.096 6.515 10.5 6.803 ;
     RECT  59.688 6.515 61.68 7.237 ;
     RECT  41.688 6.563 42.768 10.883 ;
     RECT  13.512 6.613 14.976 7.379 ;
     RECT  44.28 6.803 45.504 8.003 ;
     RECT  63.432 6.803 64.5 6.899 ;
     RECT  74.328 6.803 75.3 6.947 ;
     RECT  79.224 6.803 80.7 6.899 ;
     RECT  87.768 6.851 88.8 7.235 ;
     RECT  62.112 6.899 63.12 6.995 ;
     RECT  63.144 6.899 64.5 6.995 ;
     RECT  66.168 6.899 67.2 7.475 ;
     RECT  65.016 6.947 66.048 7.523 ;
     RECT  59.688 7.237 60.768 8.003 ;
     RECT  33.048 7.475 34.176 8.579 ;
     RECT  66.12 7.475 67.2 8.003 ;
     RECT  70.212 7.475 71.472 8.579 ;
     RECT  65.016 7.523 66.096 7.763 ;
     RECT  75.768 7.667 76.848 8.003 ;
     RECT  64.968 7.763 66.096 8.003 ;
     RECT  30.456 8.003 31.536 8.579 ;
     RECT  37.992 8.003 39.072 8.579 ;
     RECT  40.512 8.003 41.664 10.883 ;
     RECT  59.412 8.003 60.768 9.155 ;
     RECT  75.768 8.003 76.992 8.291 ;
     RECT  60.792 8.195 61.8 9.155 ;
     RECT  75.72 8.291 76.992 8.579 ;
     RECT  21.612 27.301 22.8 33.013 ;
     RECT  22.824 27.301 24 27.877 ;
     RECT  18.912 27.781 20.352 28.309 ;
     RECT  68.472 27.781 69.9 28.405 ;
     RECT  40.512 27.829 41.616 27.877 ;
     RECT  41.64 27.829 42.9 27.877 ;
     RECT  5.412 27.877 6.432 28.453 ;
     RECT  6.456 27.877 7.68 28.405 ;
     RECT  13.8 27.877 14.976 28.405 ;
     RECT  29.712 27.877 31.104 28.453 ;
     RECT  35.112 27.877 36.48 28.309 ;
     RECT  56.712 27.877 57.696 28.357 ;
     RECT  57.72 27.877 58.944 28.309 ;
     RECT  78.312 27.877 79.44 28.453 ;
     RECT  79.464 27.877 80.7 28.261 ;
     RECT  37.812 28.261 38.928 28.405 ;
     RECT  79.464 28.261 80.544 28.453 ;
     RECT  11.352 28.309 12.768 28.405 ;
     RECT  16.488 28.309 17.904 28.405 ;
     RECT  27.72 28.309 29.136 28.405 ;
     RECT  35.256 28.309 36.48 28.405 ;
     RECT  45.912 28.309 46.944 28.357 ;
     RECT  46.968 28.309 48.192 28.405 ;
     RECT  54.012 28.309 55.488 28.357 ;
     RECT  89.112 28.309 90.192 33.013 ;
     RECT  11.352 28.405 12.528 28.453 ;
     RECT  16.728 28.405 17.904 28.453 ;
     RECT  35.256 28.405 36.24 28.453 ;
     RECT  44.28 28.405 45.264 31.189 ;
     RECT  60.648 28.405 61.8 28.453 ;
     RECT  68.712 28.405 69.792 28.453 ;
     RECT  75.612 28.405 76.992 28.453 ;
     RECT  48.936 28.453 50.4 28.837 ;
     RECT  86.52 28.453 87.984 34.739 ;
     RECT  49.176 28.837 50.4 29.029 ;
     RECT  95.064 28.837 96.528 34.645 ;
     RECT  92.376 29.029 93.36 35.893 ;
     RECT  97.02 34.569 97.032 34.583 ;
     RECT  31.848 34.583 33.072 35.893 ;
     RECT  61.368 34.583 62.352 35.893 ;
     RECT  91.176 34.583 92.352 35.893 ;
     RECT  96.792 34.583 97.032 35.893 ;
     RECT  95.544 34.645 96.528 35.893 ;
     RECT  86.28 34.739 87.984 35.893 ;
  END
END dsfd_hstnv_761
END LIBRARY
